VERSION 5.8 ;
BUSBITCHARS "[]" ;
DIVIDERCHAR "/" ;
UNITS
    DATABASE MICRONS 1000 ;
END UNITS

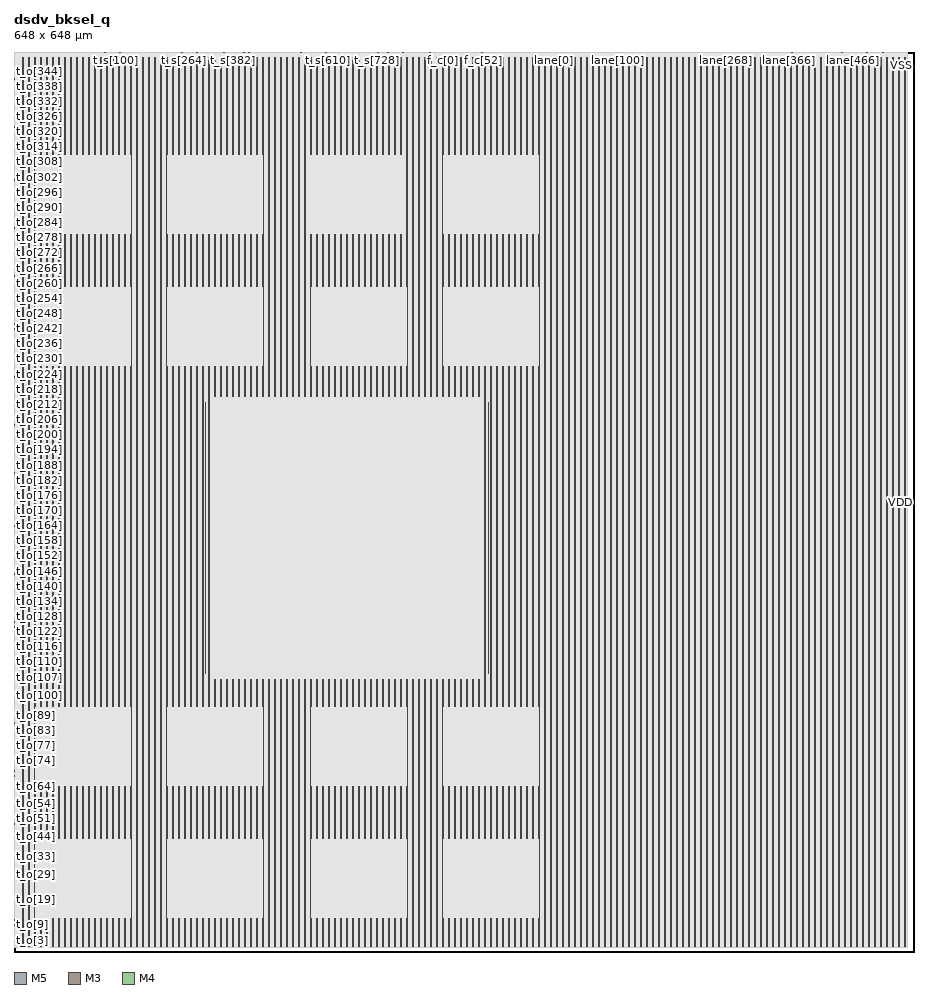
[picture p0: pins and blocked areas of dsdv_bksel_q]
MACRO dsdv_bksel_q
  FOREIGN dsdv_bksel_q 0 0 ;
  CLASS BLOCK ;
  SIZE 648 BY 648 ;
  PIN ck
    DIRECTION INPUT ;
    USE SIGNAL ;
    PORT
      LAYER M5 ;
        RECT  304.560 647.52 304.584 648 ;
    END
  END ck
  PIN f_c[0]
    DIRECTION INPUT ;
    USE SIGNAL ;
    PORT
      LAYER M3 ;
        RECT  309.132 647.962 309.15 648 ;
    END
  END f_c[0]
  PIN f_c[10]
    DIRECTION INPUT ;
    USE SIGNAL ;
    PORT
      LAYER M3 ;
        RECT  314.712 647.962 314.73 648 ;
    END
  END f_c[10]
  PIN f_c[11]
    DIRECTION INPUT ;
    USE SIGNAL ;
    PORT
      LAYER M5 ;
        RECT  315.264 647.916 315.288 648 ;
    END
  END f_c[11]
  PIN f_c[12]
    DIRECTION INPUT ;
    USE SIGNAL ;
    PORT
      LAYER M3 ;
        RECT  315.828 647.962 315.846 648 ;
    END
  END f_c[12]
  PIN f_c[13]
    DIRECTION INPUT ;
    USE SIGNAL ;
    PORT
      LAYER M5 ;
        RECT  316.368 647.916 316.392 648 ;
    END
  END f_c[13]
  PIN f_c[14]
    DIRECTION INPUT ;
    USE SIGNAL ;
    PORT
      LAYER M3 ;
        RECT  316.944 647.962 316.962 648 ;
    END
  END f_c[14]
  PIN f_c[15]
    DIRECTION INPUT ;
    USE SIGNAL ;
    PORT
      LAYER M5 ;
        RECT  317.472 647.916 317.496 648 ;
    END
  END f_c[15]
  PIN f_c[16]
    DIRECTION INPUT ;
    USE SIGNAL ;
    PORT
      LAYER M3 ;
        RECT  318.06 647.962 318.078 648 ;
    END
  END f_c[16]
  PIN f_c[17]
    DIRECTION INPUT ;
    USE SIGNAL ;
    PORT
      LAYER M5 ;
        RECT  318.624 647.916 318.648 648 ;
    END
  END f_c[17]
  PIN f_c[18]
    DIRECTION INPUT ;
    USE SIGNAL ;
    PORT
      LAYER M3 ;
        RECT  319.176 647.962 319.194 648 ;
    END
  END f_c[18]
  PIN f_c[19]
    DIRECTION INPUT ;
    USE SIGNAL ;
    PORT
      LAYER M5 ;
        RECT  319.728 647.916 319.752 648 ;
    END
  END f_c[19]
  PIN f_c[1]
    DIRECTION INPUT ;
    USE SIGNAL ;
    PORT
      LAYER M5 ;
        RECT  309.696 647.916 309.72 648 ;
    END
  END f_c[1]
  PIN f_c[20]
    DIRECTION INPUT ;
    USE SIGNAL ;
    PORT
      LAYER M3 ;
        RECT  320.292 647.962 320.31 648 ;
    END
  END f_c[20]
  PIN f_c[21]
    DIRECTION INPUT ;
    USE SIGNAL ;
    PORT
      LAYER M5 ;
        RECT  320.832 647.916 320.856 648 ;
    END
  END f_c[21]
  PIN f_c[22]
    DIRECTION INPUT ;
    USE SIGNAL ;
    PORT
      LAYER M3 ;
        RECT  321.372 647.962 321.39 648 ;
    END
  END f_c[22]
  PIN f_c[23]
    DIRECTION INPUT ;
    USE SIGNAL ;
    PORT
      LAYER M5 ;
        RECT  321.936 647.916 321.96 648 ;
    END
  END f_c[23]
  PIN f_c[24]
    DIRECTION INPUT ;
    USE SIGNAL ;
    PORT
      LAYER M3 ;
        RECT  322.488 647.962 322.506 648 ;
    END
  END f_c[24]
  PIN f_c[25]
    DIRECTION INPUT ;
    USE SIGNAL ;
    PORT
      LAYER M5 ;
        RECT  323.04 647.916 323.064 648 ;
    END
  END f_c[25]
  PIN f_c[26]
    DIRECTION INPUT ;
    USE SIGNAL ;
    PORT
      LAYER M3 ;
        RECT  323.604 647.962 323.622 648 ;
    END
  END f_c[26]
  PIN f_c[27]
    DIRECTION INPUT ;
    USE SIGNAL ;
    PORT
      LAYER M5 ;
        RECT  324.192 647.916 324.216 648 ;
    END
  END f_c[27]
  PIN f_c[28]
    DIRECTION INPUT ;
    USE SIGNAL ;
    PORT
      LAYER M3 ;
        RECT  324.72 647.962 324.738 648 ;
    END
  END f_c[28]
  PIN f_c[29]
    DIRECTION INPUT ;
    USE SIGNAL ;
    PORT
      LAYER M5 ;
        RECT  325.296 647.916 325.32 648 ;
    END
  END f_c[29]
  PIN f_c[2]
    DIRECTION INPUT ;
    USE SIGNAL ;
    PORT
      LAYER M3 ;
        RECT  310.248 647.962 310.266 648 ;
    END
  END f_c[2]
  PIN f_c[30]
    DIRECTION INPUT ;
    USE SIGNAL ;
    PORT
      LAYER M3 ;
        RECT  325.836 647.962 325.854 648 ;
    END
  END f_c[30]
  PIN f_c[31]
    DIRECTION INPUT ;
    USE SIGNAL ;
    PORT
      LAYER M5 ;
        RECT  326.4 647.916 326.424 648 ;
    END
  END f_c[31]
  PIN f_c[32]
    DIRECTION INPUT ;
    USE SIGNAL ;
    PORT
      LAYER M3 ;
        RECT  326.952 647.962 326.97 648 ;
    END
  END f_c[32]
  PIN f_c[33]
    DIRECTION INPUT ;
    USE SIGNAL ;
    PORT
      LAYER M5 ;
        RECT  327.504 647.916 327.528 648 ;
    END
  END f_c[33]
  PIN f_c[34]
    DIRECTION INPUT ;
    USE SIGNAL ;
    PORT
      LAYER M3 ;
        RECT  328.068 647.962 328.086 648 ;
    END
  END f_c[34]
  PIN f_c[35]
    DIRECTION INPUT ;
    USE SIGNAL ;
    PORT
      LAYER M5 ;
        RECT  328.608 647.916 328.632 648 ;
    END
  END f_c[35]
  PIN f_c[36]
    DIRECTION INPUT ;
    USE SIGNAL ;
    PORT
      LAYER M3 ;
        RECT  329.184 647.962 329.202 648 ;
    END
  END f_c[36]
  PIN f_c[37]
    DIRECTION INPUT ;
    USE SIGNAL ;
    PORT
      LAYER M5 ;
        RECT  329.712 647.916 329.736 648 ;
    END
  END f_c[37]
  PIN f_c[38]
    DIRECTION INPUT ;
    USE SIGNAL ;
    PORT
      LAYER M3 ;
        RECT  330.3 647.962 330.318 648 ;
    END
  END f_c[38]
  PIN f_c[39]
    DIRECTION INPUT ;
    USE SIGNAL ;
    PORT
      LAYER M5 ;
        RECT  330.864 647.916 330.888 648 ;
    END
  END f_c[39]
  PIN f_c[3]
    DIRECTION INPUT ;
    USE SIGNAL ;
    PORT
      LAYER M5 ;
        RECT  310.8 647.916 310.824 648 ;
    END
  END f_c[3]
  PIN f_c[40]
    DIRECTION INPUT ;
    USE SIGNAL ;
    PORT
      LAYER M3 ;
        RECT  331.416 647.962 331.434 648 ;
    END
  END f_c[40]
  PIN f_c[41]
    DIRECTION INPUT ;
    USE SIGNAL ;
    PORT
      LAYER M5 ;
        RECT  331.968 647.916 331.992 648 ;
    END
  END f_c[41]
  PIN f_c[42]
    DIRECTION INPUT ;
    USE SIGNAL ;
    PORT
      LAYER M3 ;
        RECT  332.532 647.962 332.55 648 ;
    END
  END f_c[42]
  PIN f_c[43]
    DIRECTION INPUT ;
    USE SIGNAL ;
    PORT
      LAYER M5 ;
        RECT  333.072 647.916 333.096 648 ;
    END
  END f_c[43]
  PIN f_c[44]
    DIRECTION INPUT ;
    USE SIGNAL ;
    PORT
      LAYER M3 ;
        RECT  333.612 647.962 333.63 648 ;
    END
  END f_c[44]
  PIN f_c[45]
    DIRECTION INPUT ;
    USE SIGNAL ;
    PORT
      LAYER M5 ;
        RECT  334.176 647.916 334.2 648 ;
    END
  END f_c[45]
  PIN f_c[46]
    DIRECTION INPUT ;
    USE SIGNAL ;
    PORT
      LAYER M3 ;
        RECT  334.728 647.962 334.746 648 ;
    END
  END f_c[46]
  PIN f_c[47]
    DIRECTION INPUT ;
    USE SIGNAL ;
    PORT
      LAYER M5 ;
        RECT  335.28 647.916 335.304 648 ;
    END
  END f_c[47]
  PIN f_c[48]
    DIRECTION INPUT ;
    USE SIGNAL ;
    PORT
      LAYER M3 ;
        RECT  335.844 647.962 335.862 648 ;
    END
  END f_c[48]
  PIN f_c[49]
    DIRECTION INPUT ;
    USE SIGNAL ;
    PORT
      LAYER M5 ;
        RECT  336.432 647.916 336.456 648 ;
    END
  END f_c[49]
  PIN f_c[4]
    DIRECTION INPUT ;
    USE SIGNAL ;
    PORT
      LAYER M3 ;
        RECT  311.364 647.962 311.382 648 ;
    END
  END f_c[4]
  PIN f_c[50]
    DIRECTION INPUT ;
    USE SIGNAL ;
    PORT
      LAYER M3 ;
        RECT  336.96 647.962 336.978 648 ;
    END
  END f_c[50]
  PIN f_c[51]
    DIRECTION INPUT ;
    USE SIGNAL ;
    PORT
      LAYER M5 ;
        RECT  337.536 647.916 337.56 648 ;
    END
  END f_c[51]
  PIN f_c[52]
    DIRECTION INPUT ;
    USE SIGNAL ;
    PORT
      LAYER M3 ;
        RECT  338.076 647.962 338.094 648 ;
    END
  END f_c[52]
  PIN f_c[53]
    DIRECTION INPUT ;
    USE SIGNAL ;
    PORT
      LAYER M5 ;
        RECT  338.64 647.916 338.664 648 ;
    END
  END f_c[53]
  PIN f_c[54]
    DIRECTION INPUT ;
    USE SIGNAL ;
    PORT
      LAYER M3 ;
        RECT  339.192 647.962 339.21 648 ;
    END
  END f_c[54]
  PIN f_c[55]
    DIRECTION INPUT ;
    USE SIGNAL ;
    PORT
      LAYER M5 ;
        RECT  339.744 647.916 339.768 648 ;
    END
  END f_c[55]
  PIN f_c[56]
    DIRECTION INPUT ;
    USE SIGNAL ;
    PORT
      LAYER M3 ;
        RECT  340.308 647.962 340.326 648 ;
    END
  END f_c[56]
  PIN f_c[57]
    DIRECTION INPUT ;
    USE SIGNAL ;
    PORT
      LAYER M5 ;
        RECT  340.848 647.916 340.872 648 ;
    END
  END f_c[57]
  PIN f_c[58]
    DIRECTION INPUT ;
    USE SIGNAL ;
    PORT
      LAYER M3 ;
        RECT  341.424 647.962 341.442 648 ;
    END
  END f_c[58]
  PIN f_c[59]
    DIRECTION INPUT ;
    USE SIGNAL ;
    PORT
      LAYER M5 ;
        RECT  341.952 647.916 341.976 648 ;
    END
  END f_c[59]
  PIN f_c[5]
    DIRECTION INPUT ;
    USE SIGNAL ;
    PORT
      LAYER M5 ;
        RECT  311.952 647.916 311.976 648 ;
    END
  END f_c[5]
  PIN f_c[60]
    DIRECTION INPUT ;
    USE SIGNAL ;
    PORT
      LAYER M3 ;
        RECT  342.54 647.962 342.558 648 ;
    END
  END f_c[60]
  PIN f_c[61]
    DIRECTION INPUT ;
    USE SIGNAL ;
    PORT
      LAYER M5 ;
        RECT  343.104 647.916 343.128 648 ;
    END
  END f_c[61]
  PIN f_c[62]
    DIRECTION INPUT ;
    USE SIGNAL ;
    PORT
      LAYER M3 ;
        RECT  343.656 647.962 343.674 648 ;
    END
  END f_c[62]
  PIN f_c[63]
    DIRECTION INPUT ;
    USE SIGNAL ;
    PORT
      LAYER M5 ;
        RECT  344.208 647.916 344.232 648 ;
    END
  END f_c[63]
  PIN f_c[64]
    DIRECTION INPUT ;
    USE SIGNAL ;
    PORT
      LAYER M3 ;
        RECT  344.772 647.962 344.79 648 ;
    END
  END f_c[64]
  PIN f_c[65]
    DIRECTION INPUT ;
    USE SIGNAL ;
    PORT
      LAYER M5 ;
        RECT  345.312 647.916 345.336 648 ;
    END
  END f_c[65]
  PIN f_c[6]
    DIRECTION INPUT ;
    USE SIGNAL ;
    PORT
      LAYER M3 ;
        RECT  312.48 647.962 312.498 648 ;
    END
  END f_c[6]
  PIN f_c[7]
    DIRECTION INPUT ;
    USE SIGNAL ;
    PORT
      LAYER M5 ;
        RECT  313.056 647.916 313.08 648 ;
    END
  END f_c[7]
  PIN f_c[8]
    DIRECTION INPUT ;
    USE SIGNAL ;
    PORT
      LAYER M3 ;
        RECT  313.596 647.962 313.614 648 ;
    END
  END f_c[8]
  PIN f_c[9]
    DIRECTION INPUT ;
    USE SIGNAL ;
    PORT
      LAYER M5 ;
        RECT  314.16 647.916 314.184 648 ;
    END
  END f_c[9]
  PIN f_cr
    DIRECTION INPUT ;
    USE SIGNAL ;
    PORT
      LAYER M3 ;
        RECT  346.68 647.962 346.698 648 ;
    END
  END f_cr
  PIN lane[0]
    DIRECTION INPUT ;
    USE SIGNAL ;
    PORT
      LAYER M3 ;
        RECT  389.016 647.962 389.034 648 ;
    END
  END lane[0]
  PIN lane[100]
    DIRECTION INPUT ;
    USE SIGNAL ;
    PORT
      LAYER M3 ;
        RECT  435.168 647.962 435.186 648 ;
    END
  END lane[100]
  PIN lane[101]
    DIRECTION INPUT ;
    USE SIGNAL ;
    PORT
      LAYER M5 ;
        RECT  435.6 647.916 435.624 648 ;
    END
  END lane[101]
  PIN lane[102]
    DIRECTION INPUT ;
    USE SIGNAL ;
    PORT
      LAYER M3 ;
        RECT  436.068 647.962 436.086 648 ;
    END
  END lane[102]
  PIN lane[103]
    DIRECTION INPUT ;
    USE SIGNAL ;
    PORT
      LAYER M5 ;
        RECT  436.56 647.916 436.584 648 ;
    END
  END lane[103]
  PIN lane[104]
    DIRECTION INPUT ;
    USE SIGNAL ;
    PORT
      LAYER M3 ;
        RECT  437.004 647.962 437.022 648 ;
    END
  END lane[104]
  PIN lane[105]
    DIRECTION INPUT ;
    USE SIGNAL ;
    PORT
      LAYER M5 ;
        RECT  437.472 647.916 437.496 648 ;
    END
  END lane[105]
  PIN lane[106]
    DIRECTION INPUT ;
    USE SIGNAL ;
    PORT
      LAYER M3 ;
        RECT  437.94 647.962 437.958 648 ;
    END
  END lane[106]
  PIN lane[107]
    DIRECTION INPUT ;
    USE SIGNAL ;
    PORT
      LAYER M5 ;
        RECT  438.384 647.916 438.408 648 ;
    END
  END lane[107]
  PIN lane[108]
    DIRECTION INPUT ;
    USE SIGNAL ;
    PORT
      LAYER M3 ;
        RECT  438.84 647.962 438.858 648 ;
    END
  END lane[108]
  PIN lane[109]
    DIRECTION INPUT ;
    USE SIGNAL ;
    PORT
      LAYER M5 ;
        RECT  439.296 647.916 439.32 648 ;
    END
  END lane[109]
  PIN lane[10]
    DIRECTION INPUT ;
    USE SIGNAL ;
    PORT
      LAYER M3 ;
        RECT  393.624 647.962 393.642 648 ;
    END
  END lane[10]
  PIN lane[110]
    DIRECTION INPUT ;
    USE SIGNAL ;
    PORT
      LAYER M3 ;
        RECT  439.776 647.962 439.794 648 ;
    END
  END lane[110]
  PIN lane[111]
    DIRECTION INPUT ;
    USE SIGNAL ;
    PORT
      LAYER M5 ;
        RECT  440.208 647.916 440.232 648 ;
    END
  END lane[111]
  PIN lane[112]
    DIRECTION INPUT ;
    USE SIGNAL ;
    PORT
      LAYER M3 ;
        RECT  440.712 647.962 440.73 648 ;
    END
  END lane[112]
  PIN lane[113]
    DIRECTION INPUT ;
    USE SIGNAL ;
    PORT
      LAYER M5 ;
        RECT  441.168 647.916 441.192 648 ;
    END
  END lane[113]
  PIN lane[114]
    DIRECTION INPUT ;
    USE SIGNAL ;
    PORT
      LAYER M3 ;
        RECT  441.612 647.962 441.63 648 ;
    END
  END lane[114]
  PIN lane[115]
    DIRECTION INPUT ;
    USE SIGNAL ;
    PORT
      LAYER M5 ;
        RECT  442.08 647.916 442.104 648 ;
    END
  END lane[115]
  PIN lane[116]
    DIRECTION INPUT ;
    USE SIGNAL ;
    PORT
      LAYER M3 ;
        RECT  442.548 647.962 442.566 648 ;
    END
  END lane[116]
  PIN lane[117]
    DIRECTION INPUT ;
    USE SIGNAL ;
    PORT
      LAYER M5 ;
        RECT  442.992 647.916 443.016 648 ;
    END
  END lane[117]
  PIN lane[118]
    DIRECTION INPUT ;
    USE SIGNAL ;
    PORT
      LAYER M3 ;
        RECT  443.448 647.962 443.466 648 ;
    END
  END lane[118]
  PIN lane[119]
    DIRECTION INPUT ;
    USE SIGNAL ;
    PORT
      LAYER M5 ;
        RECT  443.904 647.916 443.928 648 ;
    END
  END lane[119]
  PIN lane[11]
    DIRECTION INPUT ;
    USE SIGNAL ;
    PORT
      LAYER M5 ;
        RECT  394.08 647.916 394.104 648 ;
    END
  END lane[11]
  PIN lane[120]
    DIRECTION INPUT ;
    USE SIGNAL ;
    PORT
      LAYER M3 ;
        RECT  444.384 647.962 444.402 648 ;
    END
  END lane[120]
  PIN lane[121]
    DIRECTION INPUT ;
    USE SIGNAL ;
    PORT
      LAYER M5 ;
        RECT  444.864 647.916 444.888 648 ;
    END
  END lane[121]
  PIN lane[122]
    DIRECTION INPUT ;
    USE SIGNAL ;
    PORT
      LAYER M3 ;
        RECT  445.356 647.962 445.374 648 ;
    END
  END lane[122]
  PIN lane[123]
    DIRECTION INPUT ;
    USE SIGNAL ;
    PORT
      LAYER M5 ;
        RECT  445.776 647.916 445.8 648 ;
    END
  END lane[123]
  PIN lane[124]
    DIRECTION INPUT ;
    USE SIGNAL ;
    PORT
      LAYER M3 ;
        RECT  446.22 647.962 446.238 648 ;
    END
  END lane[124]
  PIN lane[125]
    DIRECTION INPUT ;
    USE SIGNAL ;
    PORT
      LAYER M5 ;
        RECT  446.688 647.916 446.712 648 ;
    END
  END lane[125]
  PIN lane[126]
    DIRECTION INPUT ;
    USE SIGNAL ;
    PORT
      LAYER M3 ;
        RECT  447.156 647.962 447.174 648 ;
    END
  END lane[126]
  PIN lane[127]
    DIRECTION INPUT ;
    USE SIGNAL ;
    PORT
      LAYER M5 ;
        RECT  447.6 647.916 447.624 648 ;
    END
  END lane[127]
  PIN lane[128]
    DIRECTION INPUT ;
    USE SIGNAL ;
    PORT
      LAYER M3 ;
        RECT  448.092 647.962 448.11 648 ;
    END
  END lane[128]
  PIN lane[129]
    DIRECTION INPUT ;
    USE SIGNAL ;
    PORT
      LAYER M5 ;
        RECT  448.512 647.916 448.536 648 ;
    END
  END lane[129]
  PIN lane[12]
    DIRECTION INPUT ;
    USE SIGNAL ;
    PORT
      LAYER M3 ;
        RECT  394.56 647.962 394.578 648 ;
    END
  END lane[12]
  PIN lane[130]
    DIRECTION INPUT ;
    USE SIGNAL ;
    PORT
      LAYER M3 ;
        RECT  448.992 647.962 449.01 648 ;
    END
  END lane[130]
  PIN lane[131]
    DIRECTION INPUT ;
    USE SIGNAL ;
    PORT
      LAYER M5 ;
        RECT  449.472 647.916 449.496 648 ;
    END
  END lane[131]
  PIN lane[132]
    DIRECTION INPUT ;
    USE SIGNAL ;
    PORT
      LAYER M3 ;
        RECT  449.928 647.962 449.946 648 ;
    END
  END lane[132]
  PIN lane[133]
    DIRECTION INPUT ;
    USE SIGNAL ;
    PORT
      LAYER M5 ;
        RECT  450.384 647.916 450.408 648 ;
    END
  END lane[133]
  PIN lane[134]
    DIRECTION INPUT ;
    USE SIGNAL ;
    PORT
      LAYER M3 ;
        RECT  450.828 647.962 450.846 648 ;
    END
  END lane[134]
  PIN lane[135]
    DIRECTION INPUT ;
    USE SIGNAL ;
    PORT
      LAYER M5 ;
        RECT  451.296 647.916 451.32 648 ;
    END
  END lane[135]
  PIN lane[136]
    DIRECTION INPUT ;
    USE SIGNAL ;
    PORT
      LAYER M3 ;
        RECT  451.764 647.962 451.782 648 ;
    END
  END lane[136]
  PIN lane[137]
    DIRECTION INPUT ;
    USE SIGNAL ;
    PORT
      LAYER M5 ;
        RECT  452.208 647.916 452.232 648 ;
    END
  END lane[137]
  PIN lane[138]
    DIRECTION INPUT ;
    USE SIGNAL ;
    PORT
      LAYER M3 ;
        RECT  452.7 647.962 452.718 648 ;
    END
  END lane[138]
  PIN lane[139]
    DIRECTION INPUT ;
    USE SIGNAL ;
    PORT
      LAYER M5 ;
        RECT  453.168 647.916 453.192 648 ;
    END
  END lane[139]
  PIN lane[13]
    DIRECTION INPUT ;
    USE SIGNAL ;
    PORT
      LAYER M5 ;
        RECT  395.04 647.916 395.064 648 ;
    END
  END lane[13]
  PIN lane[140]
    DIRECTION INPUT ;
    USE SIGNAL ;
    PORT
      LAYER M3 ;
        RECT  453.6 647.962 453.618 648 ;
    END
  END lane[140]
  PIN lane[141]
    DIRECTION INPUT ;
    USE SIGNAL ;
    PORT
      LAYER M5 ;
        RECT  454.08 647.916 454.104 648 ;
    END
  END lane[141]
  PIN lane[142]
    DIRECTION INPUT ;
    USE SIGNAL ;
    PORT
      LAYER M3 ;
        RECT  454.536 647.962 454.554 648 ;
    END
  END lane[142]
  PIN lane[143]
    DIRECTION INPUT ;
    USE SIGNAL ;
    PORT
      LAYER M5 ;
        RECT  454.992 647.916 455.016 648 ;
    END
  END lane[143]
  PIN lane[144]
    DIRECTION INPUT ;
    USE SIGNAL ;
    PORT
      LAYER M3 ;
        RECT  455.472 647.962 455.49 648 ;
    END
  END lane[144]
  PIN lane[145]
    DIRECTION INPUT ;
    USE SIGNAL ;
    PORT
      LAYER M5 ;
        RECT  455.904 647.916 455.928 648 ;
    END
  END lane[145]
  PIN lane[146]
    DIRECTION INPUT ;
    USE SIGNAL ;
    PORT
      LAYER M3 ;
        RECT  456.372 647.962 456.39 648 ;
    END
  END lane[146]
  PIN lane[147]
    DIRECTION INPUT ;
    USE SIGNAL ;
    PORT
      LAYER M5 ;
        RECT  456.816 647.916 456.84 648 ;
    END
  END lane[147]
  PIN lane[148]
    DIRECTION INPUT ;
    USE SIGNAL ;
    PORT
      LAYER M3 ;
        RECT  457.308 647.962 457.326 648 ;
    END
  END lane[148]
  PIN lane[149]
    DIRECTION INPUT ;
    USE SIGNAL ;
    PORT
      LAYER M5 ;
        RECT  457.776 647.916 457.8 648 ;
    END
  END lane[149]
  PIN lane[14]
    DIRECTION INPUT ;
    USE SIGNAL ;
    PORT
      LAYER M3 ;
        RECT  395.496 647.962 395.514 648 ;
    END
  END lane[14]
  PIN lane[150]
    DIRECTION INPUT ;
    USE SIGNAL ;
    PORT
      LAYER M3 ;
        RECT  458.244 647.962 458.262 648 ;
    END
  END lane[150]
  PIN lane[151]
    DIRECTION INPUT ;
    USE SIGNAL ;
    PORT
      LAYER M5 ;
        RECT  458.688 647.916 458.712 648 ;
    END
  END lane[151]
  PIN lane[152]
    DIRECTION INPUT ;
    USE SIGNAL ;
    PORT
      LAYER M3 ;
        RECT  459.144 647.962 459.162 648 ;
    END
  END lane[152]
  PIN lane[153]
    DIRECTION INPUT ;
    USE SIGNAL ;
    PORT
      LAYER M5 ;
        RECT  459.6 647.916 459.624 648 ;
    END
  END lane[153]
  PIN lane[154]
    DIRECTION INPUT ;
    USE SIGNAL ;
    PORT
      LAYER M3 ;
        RECT  460.08 647.962 460.098 648 ;
    END
  END lane[154]
  PIN lane[155]
    DIRECTION INPUT ;
    USE SIGNAL ;
    PORT
      LAYER M5 ;
        RECT  460.512 647.916 460.536 648 ;
    END
  END lane[155]
  PIN lane[156]
    DIRECTION INPUT ;
    USE SIGNAL ;
    PORT
      LAYER M3 ;
        RECT  460.98 647.962 460.998 648 ;
    END
  END lane[156]
  PIN lane[157]
    DIRECTION INPUT ;
    USE SIGNAL ;
    PORT
      LAYER M5 ;
        RECT  461.472 647.916 461.496 648 ;
    END
  END lane[157]
  PIN lane[158]
    DIRECTION INPUT ;
    USE SIGNAL ;
    PORT
      LAYER M3 ;
        RECT  461.916 647.962 461.934 648 ;
    END
  END lane[158]
  PIN lane[159]
    DIRECTION INPUT ;
    USE SIGNAL ;
    PORT
      LAYER M5 ;
        RECT  462.384 647.916 462.408 648 ;
    END
  END lane[159]
  PIN lane[15]
    DIRECTION INPUT ;
    USE SIGNAL ;
    PORT
      LAYER M5 ;
        RECT  395.952 647.916 395.976 648 ;
    END
  END lane[15]
  PIN lane[160]
    DIRECTION INPUT ;
    USE SIGNAL ;
    PORT
      LAYER M3 ;
        RECT  462.852 647.962 462.87 648 ;
    END
  END lane[160]
  PIN lane[161]
    DIRECTION INPUT ;
    USE SIGNAL ;
    PORT
      LAYER M5 ;
        RECT  463.296 647.916 463.32 648 ;
    END
  END lane[161]
  PIN lane[162]
    DIRECTION INPUT ;
    USE SIGNAL ;
    PORT
      LAYER M3 ;
        RECT  463.752 647.962 463.77 648 ;
    END
  END lane[162]
  PIN lane[163]
    DIRECTION INPUT ;
    USE SIGNAL ;
    PORT
      LAYER M5 ;
        RECT  464.208 647.916 464.232 648 ;
    END
  END lane[163]
  PIN lane[164]
    DIRECTION INPUT ;
    USE SIGNAL ;
    PORT
      LAYER M3 ;
        RECT  464.688 647.962 464.706 648 ;
    END
  END lane[164]
  PIN lane[165]
    DIRECTION INPUT ;
    USE SIGNAL ;
    PORT
      LAYER M5 ;
        RECT  465.12 647.916 465.144 648 ;
    END
  END lane[165]
  PIN lane[166]
    DIRECTION INPUT ;
    USE SIGNAL ;
    PORT
      LAYER M3 ;
        RECT  465.624 647.962 465.642 648 ;
    END
  END lane[166]
  PIN lane[167]
    DIRECTION INPUT ;
    USE SIGNAL ;
    PORT
      LAYER M5 ;
        RECT  466.08 647.916 466.104 648 ;
    END
  END lane[167]
  PIN lane[168]
    DIRECTION INPUT ;
    USE SIGNAL ;
    PORT
      LAYER M3 ;
        RECT  466.524 647.962 466.542 648 ;
    END
  END lane[168]
  PIN lane[169]
    DIRECTION INPUT ;
    USE SIGNAL ;
    PORT
      LAYER M5 ;
        RECT  466.992 647.916 467.016 648 ;
    END
  END lane[169]
  PIN lane[16]
    DIRECTION INPUT ;
    USE SIGNAL ;
    PORT
      LAYER M3 ;
        RECT  396.396 647.962 396.414 648 ;
    END
  END lane[16]
  PIN lane[170]
    DIRECTION INPUT ;
    USE SIGNAL ;
    PORT
      LAYER M3 ;
        RECT  467.46 647.962 467.478 648 ;
    END
  END lane[170]
  PIN lane[171]
    DIRECTION INPUT ;
    USE SIGNAL ;
    PORT
      LAYER M5 ;
        RECT  467.904 647.916 467.928 648 ;
    END
  END lane[171]
  PIN lane[172]
    DIRECTION INPUT ;
    USE SIGNAL ;
    PORT
      LAYER M3 ;
        RECT  468.36 647.962 468.378 648 ;
    END
  END lane[172]
  PIN lane[173]
    DIRECTION INPUT ;
    USE SIGNAL ;
    PORT
      LAYER M5 ;
        RECT  468.816 647.916 468.84 648 ;
    END
  END lane[173]
  PIN lane[174]
    DIRECTION INPUT ;
    USE SIGNAL ;
    PORT
      LAYER M3 ;
        RECT  469.296 647.962 469.314 648 ;
    END
  END lane[174]
  PIN lane[175]
    DIRECTION INPUT ;
    USE SIGNAL ;
    PORT
      LAYER M5 ;
        RECT  469.776 647.916 469.8 648 ;
    END
  END lane[175]
  PIN lane[176]
    DIRECTION INPUT ;
    USE SIGNAL ;
    PORT
      LAYER M3 ;
        RECT  470.232 647.962 470.25 648 ;
    END
  END lane[176]
  PIN lane[177]
    DIRECTION INPUT ;
    USE SIGNAL ;
    PORT
      LAYER M5 ;
        RECT  470.688 647.916 470.712 648 ;
    END
  END lane[177]
  PIN lane[178]
    DIRECTION INPUT ;
    USE SIGNAL ;
    PORT
      LAYER M3 ;
        RECT  471.132 647.962 471.15 648 ;
    END
  END lane[178]
  PIN lane[179]
    DIRECTION INPUT ;
    USE SIGNAL ;
    PORT
      LAYER M5 ;
        RECT  471.6 647.916 471.624 648 ;
    END
  END lane[179]
  PIN lane[17]
    DIRECTION INPUT ;
    USE SIGNAL ;
    PORT
      LAYER M5 ;
        RECT  396.864 647.916 396.888 648 ;
    END
  END lane[17]
  PIN lane[180]
    DIRECTION INPUT ;
    USE SIGNAL ;
    PORT
      LAYER M3 ;
        RECT  472.068 647.962 472.086 648 ;
    END
  END lane[180]
  PIN lane[181]
    DIRECTION INPUT ;
    USE SIGNAL ;
    PORT
      LAYER M5 ;
        RECT  472.512 647.916 472.536 648 ;
    END
  END lane[181]
  PIN lane[182]
    DIRECTION INPUT ;
    USE SIGNAL ;
    PORT
      LAYER M3 ;
        RECT  473.004 647.962 473.022 648 ;
    END
  END lane[182]
  PIN lane[183]
    DIRECTION INPUT ;
    USE SIGNAL ;
    PORT
      LAYER M5 ;
        RECT  473.424 647.916 473.448 648 ;
    END
  END lane[183]
  PIN lane[184]
    DIRECTION INPUT ;
    USE SIGNAL ;
    PORT
      LAYER M3 ;
        RECT  473.904 647.962 473.922 648 ;
    END
  END lane[184]
  PIN lane[185]
    DIRECTION INPUT ;
    USE SIGNAL ;
    PORT
      LAYER M5 ;
        RECT  474.384 647.916 474.408 648 ;
    END
  END lane[185]
  PIN lane[186]
    DIRECTION INPUT ;
    USE SIGNAL ;
    PORT
      LAYER M3 ;
        RECT  474.84 647.962 474.858 648 ;
    END
  END lane[186]
  PIN lane[187]
    DIRECTION INPUT ;
    USE SIGNAL ;
    PORT
      LAYER M5 ;
        RECT  475.296 647.916 475.32 648 ;
    END
  END lane[187]
  PIN lane[188]
    DIRECTION INPUT ;
    USE SIGNAL ;
    PORT
      LAYER M3 ;
        RECT  475.74 647.962 475.758 648 ;
    END
  END lane[188]
  PIN lane[189]
    DIRECTION INPUT ;
    USE SIGNAL ;
    PORT
      LAYER M5 ;
        RECT  476.208 647.916 476.232 648 ;
    END
  END lane[189]
  PIN lane[18]
    DIRECTION INPUT ;
    USE SIGNAL ;
    PORT
      LAYER M3 ;
        RECT  397.332 647.962 397.35 648 ;
    END
  END lane[18]
  PIN lane[190]
    DIRECTION INPUT ;
    USE SIGNAL ;
    PORT
      LAYER M3 ;
        RECT  476.676 647.962 476.694 648 ;
    END
  END lane[190]
  PIN lane[191]
    DIRECTION INPUT ;
    USE SIGNAL ;
    PORT
      LAYER M5 ;
        RECT  477.12 647.916 477.144 648 ;
    END
  END lane[191]
  PIN lane[192]
    DIRECTION INPUT ;
    USE SIGNAL ;
    PORT
      LAYER M3 ;
        RECT  477.576 647.962 477.594 648 ;
    END
  END lane[192]
  PIN lane[193]
    DIRECTION INPUT ;
    USE SIGNAL ;
    PORT
      LAYER M5 ;
        RECT  478.08 647.916 478.104 648 ;
    END
  END lane[193]
  PIN lane[194]
    DIRECTION INPUT ;
    USE SIGNAL ;
    PORT
      LAYER M3 ;
        RECT  478.512 647.962 478.53 648 ;
    END
  END lane[194]
  PIN lane[195]
    DIRECTION INPUT ;
    USE SIGNAL ;
    PORT
      LAYER M5 ;
        RECT  478.992 647.916 479.016 648 ;
    END
  END lane[195]
  PIN lane[196]
    DIRECTION INPUT ;
    USE SIGNAL ;
    PORT
      LAYER M3 ;
        RECT  479.448 647.962 479.466 648 ;
    END
  END lane[196]
  PIN lane[197]
    DIRECTION INPUT ;
    USE SIGNAL ;
    PORT
      LAYER M5 ;
        RECT  479.904 647.916 479.928 648 ;
    END
  END lane[197]
  PIN lane[198]
    DIRECTION INPUT ;
    USE SIGNAL ;
    PORT
      LAYER M3 ;
        RECT  480.384 647.962 480.402 648 ;
    END
  END lane[198]
  PIN lane[199]
    DIRECTION INPUT ;
    USE SIGNAL ;
    PORT
      LAYER M5 ;
        RECT  480.816 647.916 480.84 648 ;
    END
  END lane[199]
  PIN lane[19]
    DIRECTION INPUT ;
    USE SIGNAL ;
    PORT
      LAYER M5 ;
        RECT  397.776 647.916 397.8 648 ;
    END
  END lane[19]
  PIN lane[1]
    DIRECTION INPUT ;
    USE SIGNAL ;
    PORT
      LAYER M5 ;
        RECT  389.472 647.916 389.496 648 ;
    END
  END lane[1]
  PIN lane[200]
    DIRECTION INPUT ;
    USE SIGNAL ;
    PORT
      LAYER M3 ;
        RECT  481.284 647.962 481.302 648 ;
    END
  END lane[200]
  PIN lane[201]
    DIRECTION INPUT ;
    USE SIGNAL ;
    PORT
      LAYER M5 ;
        RECT  481.776 647.916 481.8 648 ;
    END
  END lane[201]
  PIN lane[202]
    DIRECTION INPUT ;
    USE SIGNAL ;
    PORT
      LAYER M3 ;
        RECT  482.22 647.962 482.238 648 ;
    END
  END lane[202]
  PIN lane[203]
    DIRECTION INPUT ;
    USE SIGNAL ;
    PORT
      LAYER M5 ;
        RECT  482.688 647.916 482.712 648 ;
    END
  END lane[203]
  PIN lane[204]
    DIRECTION INPUT ;
    USE SIGNAL ;
    PORT
      LAYER M3 ;
        RECT  483.156 647.962 483.174 648 ;
    END
  END lane[204]
  PIN lane[205]
    DIRECTION INPUT ;
    USE SIGNAL ;
    PORT
      LAYER M5 ;
        RECT  483.6 647.916 483.624 648 ;
    END
  END lane[205]
  PIN lane[206]
    DIRECTION INPUT ;
    USE SIGNAL ;
    PORT
      LAYER M3 ;
        RECT  484.056 647.962 484.074 648 ;
    END
  END lane[206]
  PIN lane[207]
    DIRECTION INPUT ;
    USE SIGNAL ;
    PORT
      LAYER M5 ;
        RECT  484.512 647.916 484.536 648 ;
    END
  END lane[207]
  PIN lane[208]
    DIRECTION INPUT ;
    USE SIGNAL ;
    PORT
      LAYER M3 ;
        RECT  484.992 647.962 485.01 648 ;
    END
  END lane[208]
  PIN lane[209]
    DIRECTION INPUT ;
    USE SIGNAL ;
    PORT
      LAYER M5 ;
        RECT  485.424 647.916 485.448 648 ;
    END
  END lane[209]
  PIN lane[20]
    DIRECTION INPUT ;
    USE SIGNAL ;
    PORT
      LAYER M3 ;
        RECT  398.232 647.962 398.25 648 ;
    END
  END lane[20]
  PIN lane[210]
    DIRECTION INPUT ;
    USE SIGNAL ;
    PORT
      LAYER M3 ;
        RECT  485.892 647.962 485.91 648 ;
    END
  END lane[210]
  PIN lane[211]
    DIRECTION INPUT ;
    USE SIGNAL ;
    PORT
      LAYER M5 ;
        RECT  486.384 647.916 486.408 648 ;
    END
  END lane[211]
  PIN lane[212]
    DIRECTION INPUT ;
    USE SIGNAL ;
    PORT
      LAYER M3 ;
        RECT  486.828 647.962 486.846 648 ;
    END
  END lane[212]
  PIN lane[213]
    DIRECTION INPUT ;
    USE SIGNAL ;
    PORT
      LAYER M5 ;
        RECT  487.296 647.916 487.32 648 ;
    END
  END lane[213]
  PIN lane[214]
    DIRECTION INPUT ;
    USE SIGNAL ;
    PORT
      LAYER M3 ;
        RECT  487.764 647.962 487.782 648 ;
    END
  END lane[214]
  PIN lane[215]
    DIRECTION INPUT ;
    USE SIGNAL ;
    PORT
      LAYER M5 ;
        RECT  488.208 647.916 488.232 648 ;
    END
  END lane[215]
  PIN lane[216]
    DIRECTION INPUT ;
    USE SIGNAL ;
    PORT
      LAYER M3 ;
        RECT  488.664 647.962 488.682 648 ;
    END
  END lane[216]
  PIN lane[217]
    DIRECTION INPUT ;
    USE SIGNAL ;
    PORT
      LAYER M5 ;
        RECT  489.12 647.916 489.144 648 ;
    END
  END lane[217]
  PIN lane[218]
    DIRECTION INPUT ;
    USE SIGNAL ;
    PORT
      LAYER M3 ;
        RECT  489.6 647.962 489.618 648 ;
    END
  END lane[218]
  PIN lane[219]
    DIRECTION INPUT ;
    USE SIGNAL ;
    PORT
      LAYER M5 ;
        RECT  490.08 647.916 490.104 648 ;
    END
  END lane[219]
  PIN lane[21]
    DIRECTION INPUT ;
    USE SIGNAL ;
    PORT
      LAYER M5 ;
        RECT  398.688 647.916 398.712 648 ;
    END
  END lane[21]
  PIN lane[220]
    DIRECTION INPUT ;
    USE SIGNAL ;
    PORT
      LAYER M3 ;
        RECT  490.536 647.962 490.554 648 ;
    END
  END lane[220]
  PIN lane[221]
    DIRECTION INPUT ;
    USE SIGNAL ;
    PORT
      LAYER M5 ;
        RECT  490.992 647.916 491.016 648 ;
    END
  END lane[221]
  PIN lane[222]
    DIRECTION INPUT ;
    USE SIGNAL ;
    PORT
      LAYER M3 ;
        RECT  491.436 647.962 491.454 648 ;
    END
  END lane[222]
  PIN lane[223]
    DIRECTION INPUT ;
    USE SIGNAL ;
    PORT
      LAYER M5 ;
        RECT  491.904 647.916 491.928 648 ;
    END
  END lane[223]
  PIN lane[224]
    DIRECTION INPUT ;
    USE SIGNAL ;
    PORT
      LAYER M3 ;
        RECT  492.372 647.962 492.39 648 ;
    END
  END lane[224]
  PIN lane[225]
    DIRECTION INPUT ;
    USE SIGNAL ;
    PORT
      LAYER M5 ;
        RECT  492.816 647.916 492.84 648 ;
    END
  END lane[225]
  PIN lane[226]
    DIRECTION INPUT ;
    USE SIGNAL ;
    PORT
      LAYER M3 ;
        RECT  493.272 647.962 493.29 648 ;
    END
  END lane[226]
  PIN lane[227]
    DIRECTION INPUT ;
    USE SIGNAL ;
    PORT
      LAYER M5 ;
        RECT  493.728 647.916 493.752 648 ;
    END
  END lane[227]
  PIN lane[228]
    DIRECTION INPUT ;
    USE SIGNAL ;
    PORT
      LAYER M3 ;
        RECT  494.208 647.962 494.226 648 ;
    END
  END lane[228]
  PIN lane[229]
    DIRECTION INPUT ;
    USE SIGNAL ;
    PORT
      LAYER M5 ;
        RECT  494.688 647.916 494.712 648 ;
    END
  END lane[229]
  PIN lane[22]
    DIRECTION INPUT ;
    USE SIGNAL ;
    PORT
      LAYER M3 ;
        RECT  399.168 647.962 399.186 648 ;
    END
  END lane[22]
  PIN lane[230]
    DIRECTION INPUT ;
    USE SIGNAL ;
    PORT
      LAYER M3 ;
        RECT  495.144 647.962 495.162 648 ;
    END
  END lane[230]
  PIN lane[231]
    DIRECTION INPUT ;
    USE SIGNAL ;
    PORT
      LAYER M5 ;
        RECT  495.6 647.916 495.624 648 ;
    END
  END lane[231]
  PIN lane[232]
    DIRECTION INPUT ;
    USE SIGNAL ;
    PORT
      LAYER M3 ;
        RECT  496.044 647.962 496.062 648 ;
    END
  END lane[232]
  PIN lane[233]
    DIRECTION INPUT ;
    USE SIGNAL ;
    PORT
      LAYER M5 ;
        RECT  496.512 647.916 496.536 648 ;
    END
  END lane[233]
  PIN lane[234]
    DIRECTION INPUT ;
    USE SIGNAL ;
    PORT
      LAYER M3 ;
        RECT  496.98 647.962 496.998 648 ;
    END
  END lane[234]
  PIN lane[235]
    DIRECTION INPUT ;
    USE SIGNAL ;
    PORT
      LAYER M5 ;
        RECT  497.424 647.916 497.448 648 ;
    END
  END lane[235]
  PIN lane[236]
    DIRECTION INPUT ;
    USE SIGNAL ;
    PORT
      LAYER M3 ;
        RECT  497.916 647.962 497.934 648 ;
    END
  END lane[236]
  PIN lane[237]
    DIRECTION INPUT ;
    USE SIGNAL ;
    PORT
      LAYER M5 ;
        RECT  498.384 647.916 498.408 648 ;
    END
  END lane[237]
  PIN lane[238]
    DIRECTION INPUT ;
    USE SIGNAL ;
    PORT
      LAYER M3 ;
        RECT  498.816 647.962 498.834 648 ;
    END
  END lane[238]
  PIN lane[239]
    DIRECTION INPUT ;
    USE SIGNAL ;
    PORT
      LAYER M5 ;
        RECT  499.296 647.916 499.32 648 ;
    END
  END lane[239]
  PIN lane[23]
    DIRECTION INPUT ;
    USE SIGNAL ;
    PORT
      LAYER M5 ;
        RECT  399.648 647.916 399.672 648 ;
    END
  END lane[23]
  PIN lane[240]
    DIRECTION INPUT ;
    USE SIGNAL ;
    PORT
      LAYER M3 ;
        RECT  499.752 647.962 499.77 648 ;
    END
  END lane[240]
  PIN lane[241]
    DIRECTION INPUT ;
    USE SIGNAL ;
    PORT
      LAYER M5 ;
        RECT  500.208 647.916 500.232 648 ;
    END
  END lane[241]
  PIN lane[242]
    DIRECTION INPUT ;
    USE SIGNAL ;
    PORT
      LAYER M3 ;
        RECT  500.688 647.962 500.706 648 ;
    END
  END lane[242]
  PIN lane[243]
    DIRECTION INPUT ;
    USE SIGNAL ;
    PORT
      LAYER M5 ;
        RECT  501.12 647.916 501.144 648 ;
    END
  END lane[243]
  PIN lane[244]
    DIRECTION INPUT ;
    USE SIGNAL ;
    PORT
      LAYER M3 ;
        RECT  501.588 647.962 501.606 648 ;
    END
  END lane[244]
  PIN lane[245]
    DIRECTION INPUT ;
    USE SIGNAL ;
    PORT
      LAYER M5 ;
        RECT  502.032 647.916 502.056 648 ;
    END
  END lane[245]
  PIN lane[246]
    DIRECTION INPUT ;
    USE SIGNAL ;
    PORT
      LAYER M3 ;
        RECT  502.524 647.962 502.542 648 ;
    END
  END lane[246]
  PIN lane[247]
    DIRECTION INPUT ;
    USE SIGNAL ;
    PORT
      LAYER M5 ;
        RECT  502.992 647.916 503.016 648 ;
    END
  END lane[247]
  PIN lane[248]
    DIRECTION INPUT ;
    USE SIGNAL ;
    PORT
      LAYER M3 ;
        RECT  503.424 647.962 503.442 648 ;
    END
  END lane[248]
  PIN lane[249]
    DIRECTION INPUT ;
    USE SIGNAL ;
    PORT
      LAYER M5 ;
        RECT  503.904 647.916 503.928 648 ;
    END
  END lane[249]
  PIN lane[24]
    DIRECTION INPUT ;
    USE SIGNAL ;
    PORT
      LAYER M3 ;
        RECT  400.104 647.962 400.122 648 ;
    END
  END lane[24]
  PIN lane[250]
    DIRECTION INPUT ;
    USE SIGNAL ;
    PORT
      LAYER M3 ;
        RECT  504.36 647.962 504.378 648 ;
    END
  END lane[250]
  PIN lane[251]
    DIRECTION INPUT ;
    USE SIGNAL ;
    PORT
      LAYER M5 ;
        RECT  504.816 647.916 504.84 648 ;
    END
  END lane[251]
  PIN lane[252]
    DIRECTION INPUT ;
    USE SIGNAL ;
    PORT
      LAYER M3 ;
        RECT  505.296 647.962 505.314 648 ;
    END
  END lane[252]
  PIN lane[253]
    DIRECTION INPUT ;
    USE SIGNAL ;
    PORT
      LAYER M5 ;
        RECT  505.728 647.916 505.752 648 ;
    END
  END lane[253]
  PIN lane[254]
    DIRECTION INPUT ;
    USE SIGNAL ;
    PORT
      LAYER M3 ;
        RECT  506.196 647.962 506.214 648 ;
    END
  END lane[254]
  PIN lane[255]
    DIRECTION INPUT ;
    USE SIGNAL ;
    PORT
      LAYER M5 ;
        RECT  506.688 647.916 506.712 648 ;
    END
  END lane[255]
  PIN lane[256]
    DIRECTION INPUT ;
    USE SIGNAL ;
    PORT
      LAYER M3 ;
        RECT  507.132 647.962 507.15 648 ;
    END
  END lane[256]
  PIN lane[257]
    DIRECTION INPUT ;
    USE SIGNAL ;
    PORT
      LAYER M5 ;
        RECT  507.6 647.916 507.624 648 ;
    END
  END lane[257]
  PIN lane[258]
    DIRECTION INPUT ;
    USE SIGNAL ;
    PORT
      LAYER M3 ;
        RECT  508.068 647.962 508.086 648 ;
    END
  END lane[258]
  PIN lane[259]
    DIRECTION INPUT ;
    USE SIGNAL ;
    PORT
      LAYER M5 ;
        RECT  508.512 647.916 508.536 648 ;
    END
  END lane[259]
  PIN lane[25]
    DIRECTION INPUT ;
    USE SIGNAL ;
    PORT
      LAYER M5 ;
        RECT  400.56 647.916 400.584 648 ;
    END
  END lane[25]
  PIN lane[260]
    DIRECTION INPUT ;
    USE SIGNAL ;
    PORT
      LAYER M3 ;
        RECT  508.968 647.962 508.986 648 ;
    END
  END lane[260]
  PIN lane[261]
    DIRECTION INPUT ;
    USE SIGNAL ;
    PORT
      LAYER M5 ;
        RECT  509.424 647.916 509.448 648 ;
    END
  END lane[261]
  PIN lane[262]
    DIRECTION INPUT ;
    USE SIGNAL ;
    PORT
      LAYER M3 ;
        RECT  509.904 647.962 509.922 648 ;
    END
  END lane[262]
  PIN lane[263]
    DIRECTION INPUT ;
    USE SIGNAL ;
    PORT
      LAYER M5 ;
        RECT  510.336 647.916 510.36 648 ;
    END
  END lane[263]
  PIN lane[264]
    DIRECTION INPUT ;
    USE SIGNAL ;
    PORT
      LAYER M3 ;
        RECT  510.804 647.962 510.822 648 ;
    END
  END lane[264]
  PIN lane[265]
    DIRECTION INPUT ;
    USE SIGNAL ;
    PORT
      LAYER M5 ;
        RECT  511.296 647.916 511.32 648 ;
    END
  END lane[265]
  PIN lane[266]
    DIRECTION INPUT ;
    USE SIGNAL ;
    PORT
      LAYER M3 ;
        RECT  511.74 647.962 511.758 648 ;
    END
  END lane[266]
  PIN lane[267]
    DIRECTION INPUT ;
    USE SIGNAL ;
    PORT
      LAYER M5 ;
        RECT  512.208 647.916 512.232 648 ;
    END
  END lane[267]
  PIN lane[268]
    DIRECTION INPUT ;
    USE SIGNAL ;
    PORT
      LAYER M3 ;
        RECT  512.676 647.962 512.694 648 ;
    END
  END lane[268]
  PIN lane[269]
    DIRECTION INPUT ;
    USE SIGNAL ;
    PORT
      LAYER M5 ;
        RECT  513.12 647.916 513.144 648 ;
    END
  END lane[269]
  PIN lane[26]
    DIRECTION INPUT ;
    USE SIGNAL ;
    PORT
      LAYER M3 ;
        RECT  401.004 647.962 401.022 648 ;
    END
  END lane[26]
  PIN lane[270]
    DIRECTION INPUT ;
    USE SIGNAL ;
    PORT
      LAYER M3 ;
        RECT  513.576 647.962 513.594 648 ;
    END
  END lane[270]
  PIN lane[271]
    DIRECTION INPUT ;
    USE SIGNAL ;
    PORT
      LAYER M5 ;
        RECT  514.032 647.916 514.056 648 ;
    END
  END lane[271]
  PIN lane[272]
    DIRECTION INPUT ;
    USE SIGNAL ;
    PORT
      LAYER M3 ;
        RECT  514.512 647.962 514.53 648 ;
    END
  END lane[272]
  PIN lane[273]
    DIRECTION INPUT ;
    USE SIGNAL ;
    PORT
      LAYER M5 ;
        RECT  514.992 647.916 515.016 648 ;
    END
  END lane[273]
  PIN lane[274]
    DIRECTION INPUT ;
    USE SIGNAL ;
    PORT
      LAYER M3 ;
        RECT  515.448 647.962 515.466 648 ;
    END
  END lane[274]
  PIN lane[275]
    DIRECTION INPUT ;
    USE SIGNAL ;
    PORT
      LAYER M5 ;
        RECT  515.904 647.916 515.928 648 ;
    END
  END lane[275]
  PIN lane[276]
    DIRECTION INPUT ;
    USE SIGNAL ;
    PORT
      LAYER M3 ;
        RECT  516.348 647.962 516.366 648 ;
    END
  END lane[276]
  PIN lane[277]
    DIRECTION INPUT ;
    USE SIGNAL ;
    PORT
      LAYER M5 ;
        RECT  516.816 647.916 516.84 648 ;
    END
  END lane[277]
  PIN lane[278]
    DIRECTION INPUT ;
    USE SIGNAL ;
    PORT
      LAYER M3 ;
        RECT  517.284 647.962 517.302 648 ;
    END
  END lane[278]
  PIN lane[279]
    DIRECTION INPUT ;
    USE SIGNAL ;
    PORT
      LAYER M5 ;
        RECT  517.728 647.916 517.752 648 ;
    END
  END lane[279]
  PIN lane[27]
    DIRECTION INPUT ;
    USE SIGNAL ;
    PORT
      LAYER M5 ;
        RECT  401.472 647.916 401.496 648 ;
    END
  END lane[27]
  PIN lane[280]
    DIRECTION INPUT ;
    USE SIGNAL ;
    PORT
      LAYER M3 ;
        RECT  518.22 647.962 518.238 648 ;
    END
  END lane[280]
  PIN lane[281]
    DIRECTION INPUT ;
    USE SIGNAL ;
    PORT
      LAYER M5 ;
        RECT  518.64 647.916 518.664 648 ;
    END
  END lane[281]
  PIN lane[282]
    DIRECTION INPUT ;
    USE SIGNAL ;
    PORT
      LAYER M3 ;
        RECT  519.12 647.962 519.138 648 ;
    END
  END lane[282]
  PIN lane[283]
    DIRECTION INPUT ;
    USE SIGNAL ;
    PORT
      LAYER M5 ;
        RECT  519.6 647.916 519.624 648 ;
    END
  END lane[283]
  PIN lane[284]
    DIRECTION INPUT ;
    USE SIGNAL ;
    PORT
      LAYER M3 ;
        RECT  520.056 647.962 520.074 648 ;
    END
  END lane[284]
  PIN lane[285]
    DIRECTION INPUT ;
    USE SIGNAL ;
    PORT
      LAYER M5 ;
        RECT  520.512 647.916 520.536 648 ;
    END
  END lane[285]
  PIN lane[286]
    DIRECTION INPUT ;
    USE SIGNAL ;
    PORT
      LAYER M3 ;
        RECT  520.956 647.962 520.974 648 ;
    END
  END lane[286]
  PIN lane[287]
    DIRECTION INPUT ;
    USE SIGNAL ;
    PORT
      LAYER M5 ;
        RECT  521.424 647.916 521.448 648 ;
    END
  END lane[287]
  PIN lane[288]
    DIRECTION INPUT ;
    USE SIGNAL ;
    PORT
      LAYER M3 ;
        RECT  521.892 647.962 521.91 648 ;
    END
  END lane[288]
  PIN lane[289]
    DIRECTION INPUT ;
    USE SIGNAL ;
    PORT
      LAYER M5 ;
        RECT  522.336 647.916 522.36 648 ;
    END
  END lane[289]
  PIN lane[28]
    DIRECTION INPUT ;
    USE SIGNAL ;
    PORT
      LAYER M3 ;
        RECT  401.94 647.962 401.958 648 ;
    END
  END lane[28]
  PIN lane[290]
    DIRECTION INPUT ;
    USE SIGNAL ;
    PORT
      LAYER M3 ;
        RECT  522.828 647.962 522.846 648 ;
    END
  END lane[290]
  PIN lane[291]
    DIRECTION INPUT ;
    USE SIGNAL ;
    PORT
      LAYER M5 ;
        RECT  523.296 647.916 523.32 648 ;
    END
  END lane[291]
  PIN lane[292]
    DIRECTION INPUT ;
    USE SIGNAL ;
    PORT
      LAYER M3 ;
        RECT  523.728 647.962 523.746 648 ;
    END
  END lane[292]
  PIN lane[293]
    DIRECTION INPUT ;
    USE SIGNAL ;
    PORT
      LAYER M5 ;
        RECT  524.208 647.916 524.232 648 ;
    END
  END lane[293]
  PIN lane[294]
    DIRECTION INPUT ;
    USE SIGNAL ;
    PORT
      LAYER M3 ;
        RECT  524.664 647.962 524.682 648 ;
    END
  END lane[294]
  PIN lane[295]
    DIRECTION INPUT ;
    USE SIGNAL ;
    PORT
      LAYER M5 ;
        RECT  525.12 647.916 525.144 648 ;
    END
  END lane[295]
  PIN lane[296]
    DIRECTION INPUT ;
    USE SIGNAL ;
    PORT
      LAYER M3 ;
        RECT  525.6 647.962 525.618 648 ;
    END
  END lane[296]
  PIN lane[297]
    DIRECTION INPUT ;
    USE SIGNAL ;
    PORT
      LAYER M5 ;
        RECT  526.032 647.916 526.056 648 ;
    END
  END lane[297]
  PIN lane[298]
    DIRECTION INPUT ;
    USE SIGNAL ;
    PORT
      LAYER M3 ;
        RECT  526.5 647.962 526.518 648 ;
    END
  END lane[298]
  PIN lane[299]
    DIRECTION INPUT ;
    USE SIGNAL ;
    PORT
      LAYER M5 ;
        RECT  526.944 647.916 526.968 648 ;
    END
  END lane[299]
  PIN lane[29]
    DIRECTION INPUT ;
    USE SIGNAL ;
    PORT
      LAYER M5 ;
        RECT  402.384 647.916 402.408 648 ;
    END
  END lane[29]
  PIN lane[2]
    DIRECTION INPUT ;
    USE SIGNAL ;
    PORT
      LAYER M3 ;
        RECT  389.952 647.962 389.97 648 ;
    END
  END lane[2]
  PIN lane[300]
    DIRECTION INPUT ;
    USE SIGNAL ;
    PORT
      LAYER M3 ;
        RECT  527.436 647.962 527.454 648 ;
    END
  END lane[300]
  PIN lane[301]
    DIRECTION INPUT ;
    USE SIGNAL ;
    PORT
      LAYER M5 ;
        RECT  527.904 647.916 527.928 648 ;
    END
  END lane[301]
  PIN lane[302]
    DIRECTION INPUT ;
    USE SIGNAL ;
    PORT
      LAYER M3 ;
        RECT  528.336 647.962 528.354 648 ;
    END
  END lane[302]
  PIN lane[303]
    DIRECTION INPUT ;
    USE SIGNAL ;
    PORT
      LAYER M5 ;
        RECT  528.816 647.916 528.84 648 ;
    END
  END lane[303]
  PIN lane[304]
    DIRECTION INPUT ;
    USE SIGNAL ;
    PORT
      LAYER M3 ;
        RECT  529.272 647.962 529.29 648 ;
    END
  END lane[304]
  PIN lane[305]
    DIRECTION INPUT ;
    USE SIGNAL ;
    PORT
      LAYER M5 ;
        RECT  529.728 647.916 529.752 648 ;
    END
  END lane[305]
  PIN lane[306]
    DIRECTION INPUT ;
    USE SIGNAL ;
    PORT
      LAYER M3 ;
        RECT  530.208 647.962 530.226 648 ;
    END
  END lane[306]
  PIN lane[307]
    DIRECTION INPUT ;
    USE SIGNAL ;
    PORT
      LAYER M5 ;
        RECT  530.64 647.916 530.664 648 ;
    END
  END lane[307]
  PIN lane[308]
    DIRECTION INPUT ;
    USE SIGNAL ;
    PORT
      LAYER M3 ;
        RECT  531.108 647.962 531.126 648 ;
    END
  END lane[308]
  PIN lane[309]
    DIRECTION INPUT ;
    USE SIGNAL ;
    PORT
      LAYER M5 ;
        RECT  531.6 647.916 531.624 648 ;
    END
  END lane[309]
  PIN lane[30]
    DIRECTION INPUT ;
    USE SIGNAL ;
    PORT
      LAYER M3 ;
        RECT  402.876 647.962 402.894 648 ;
    END
  END lane[30]
  PIN lane[310]
    DIRECTION INPUT ;
    USE SIGNAL ;
    PORT
      LAYER M3 ;
        RECT  532.044 647.962 532.062 648 ;
    END
  END lane[310]
  PIN lane[311]
    DIRECTION INPUT ;
    USE SIGNAL ;
    PORT
      LAYER M5 ;
        RECT  532.512 647.916 532.536 648 ;
    END
  END lane[311]
  PIN lane[312]
    DIRECTION INPUT ;
    USE SIGNAL ;
    PORT
      LAYER M3 ;
        RECT  532.98 647.962 532.998 648 ;
    END
  END lane[312]
  PIN lane[313]
    DIRECTION INPUT ;
    USE SIGNAL ;
    PORT
      LAYER M5 ;
        RECT  533.424 647.916 533.448 648 ;
    END
  END lane[313]
  PIN lane[314]
    DIRECTION INPUT ;
    USE SIGNAL ;
    PORT
      LAYER M3 ;
        RECT  533.88 647.962 533.898 648 ;
    END
  END lane[314]
  PIN lane[315]
    DIRECTION INPUT ;
    USE SIGNAL ;
    PORT
      LAYER M5 ;
        RECT  534.336 647.916 534.36 648 ;
    END
  END lane[315]
  PIN lane[316]
    DIRECTION INPUT ;
    USE SIGNAL ;
    PORT
      LAYER M3 ;
        RECT  534.816 647.962 534.834 648 ;
    END
  END lane[316]
  PIN lane[317]
    DIRECTION INPUT ;
    USE SIGNAL ;
    PORT
      LAYER M5 ;
        RECT  535.248 647.916 535.272 648 ;
    END
  END lane[317]
  PIN lane[318]
    DIRECTION INPUT ;
    USE SIGNAL ;
    PORT
      LAYER M3 ;
        RECT  535.752 647.962 535.77 648 ;
    END
  END lane[318]
  PIN lane[319]
    DIRECTION INPUT ;
    USE SIGNAL ;
    PORT
      LAYER M5 ;
        RECT  536.208 647.916 536.232 648 ;
    END
  END lane[319]
  PIN lane[31]
    DIRECTION INPUT ;
    USE SIGNAL ;
    PORT
      LAYER M5 ;
        RECT  403.344 647.916 403.368 648 ;
    END
  END lane[31]
  PIN lane[320]
    DIRECTION INPUT ;
    USE SIGNAL ;
    PORT
      LAYER M3 ;
        RECT  536.652 647.962 536.67 648 ;
    END
  END lane[320]
  PIN lane[321]
    DIRECTION INPUT ;
    USE SIGNAL ;
    PORT
      LAYER M5 ;
        RECT  537.12 647.916 537.144 648 ;
    END
  END lane[321]
  PIN lane[322]
    DIRECTION INPUT ;
    USE SIGNAL ;
    PORT
      LAYER M3 ;
        RECT  537.588 647.962 537.606 648 ;
    END
  END lane[322]
  PIN lane[323]
    DIRECTION INPUT ;
    USE SIGNAL ;
    PORT
      LAYER M5 ;
        RECT  538.032 647.916 538.056 648 ;
    END
  END lane[323]
  PIN lane[324]
    DIRECTION INPUT ;
    USE SIGNAL ;
    PORT
      LAYER M3 ;
        RECT  538.488 647.962 538.506 648 ;
    END
  END lane[324]
  PIN lane[325]
    DIRECTION INPUT ;
    USE SIGNAL ;
    PORT
      LAYER M5 ;
        RECT  538.944 647.916 538.968 648 ;
    END
  END lane[325]
  PIN lane[326]
    DIRECTION INPUT ;
    USE SIGNAL ;
    PORT
      LAYER M3 ;
        RECT  539.424 647.962 539.442 648 ;
    END
  END lane[326]
  PIN lane[327]
    DIRECTION INPUT ;
    USE SIGNAL ;
    PORT
      LAYER M5 ;
        RECT  539.904 647.916 539.928 648 ;
    END
  END lane[327]
  PIN lane[328]
    DIRECTION INPUT ;
    USE SIGNAL ;
    PORT
      LAYER M3 ;
        RECT  540.36 647.962 540.378 648 ;
    END
  END lane[328]
  PIN lane[329]
    DIRECTION INPUT ;
    USE SIGNAL ;
    PORT
      LAYER M5 ;
        RECT  540.816 647.916 540.84 648 ;
    END
  END lane[329]
  PIN lane[32]
    DIRECTION INPUT ;
    USE SIGNAL ;
    PORT
      LAYER M3 ;
        RECT  403.776 647.962 403.794 648 ;
    END
  END lane[32]
  PIN lane[330]
    DIRECTION INPUT ;
    USE SIGNAL ;
    PORT
      LAYER M3 ;
        RECT  541.26 647.962 541.278 648 ;
    END
  END lane[330]
  PIN lane[331]
    DIRECTION INPUT ;
    USE SIGNAL ;
    PORT
      LAYER M5 ;
        RECT  541.728 647.916 541.752 648 ;
    END
  END lane[331]
  PIN lane[332]
    DIRECTION INPUT ;
    USE SIGNAL ;
    PORT
      LAYER M3 ;
        RECT  542.196 647.962 542.214 648 ;
    END
  END lane[332]
  PIN lane[333]
    DIRECTION INPUT ;
    USE SIGNAL ;
    PORT
      LAYER M5 ;
        RECT  542.64 647.916 542.664 648 ;
    END
  END lane[333]
  PIN lane[334]
    DIRECTION INPUT ;
    USE SIGNAL ;
    PORT
      LAYER M3 ;
        RECT  543.132 647.962 543.15 648 ;
    END
  END lane[334]
  PIN lane[335]
    DIRECTION INPUT ;
    USE SIGNAL ;
    PORT
      LAYER M5 ;
        RECT  543.552 647.916 543.576 648 ;
    END
  END lane[335]
  PIN lane[336]
    DIRECTION INPUT ;
    USE SIGNAL ;
    PORT
      LAYER M3 ;
        RECT  544.032 647.962 544.05 648 ;
    END
  END lane[336]
  PIN lane[337]
    DIRECTION INPUT ;
    USE SIGNAL ;
    PORT
      LAYER M5 ;
        RECT  544.512 647.916 544.536 648 ;
    END
  END lane[337]
  PIN lane[338]
    DIRECTION INPUT ;
    USE SIGNAL ;
    PORT
      LAYER M3 ;
        RECT  544.968 647.962 544.986 648 ;
    END
  END lane[338]
  PIN lane[339]
    DIRECTION INPUT ;
    USE SIGNAL ;
    PORT
      LAYER M5 ;
        RECT  545.424 647.916 545.448 648 ;
    END
  END lane[339]
  PIN lane[33]
    DIRECTION INPUT ;
    USE SIGNAL ;
    PORT
      LAYER M5 ;
        RECT  404.256 647.916 404.28 648 ;
    END
  END lane[33]
  PIN lane[340]
    DIRECTION INPUT ;
    USE SIGNAL ;
    PORT
      LAYER M3 ;
        RECT  545.868 647.962 545.886 648 ;
    END
  END lane[340]
  PIN lane[341]
    DIRECTION INPUT ;
    USE SIGNAL ;
    PORT
      LAYER M5 ;
        RECT  546.336 647.916 546.36 648 ;
    END
  END lane[341]
  PIN lane[342]
    DIRECTION INPUT ;
    USE SIGNAL ;
    PORT
      LAYER M3 ;
        RECT  546.804 647.962 546.822 648 ;
    END
  END lane[342]
  PIN lane[343]
    DIRECTION INPUT ;
    USE SIGNAL ;
    PORT
      LAYER M5 ;
        RECT  547.248 647.916 547.272 648 ;
    END
  END lane[343]
  PIN lane[344]
    DIRECTION INPUT ;
    USE SIGNAL ;
    PORT
      LAYER M3 ;
        RECT  547.74 647.962 547.758 648 ;
    END
  END lane[344]
  PIN lane[345]
    DIRECTION INPUT ;
    USE SIGNAL ;
    PORT
      LAYER M5 ;
        RECT  548.208 647.916 548.232 648 ;
    END
  END lane[345]
  PIN lane[346]
    DIRECTION INPUT ;
    USE SIGNAL ;
    PORT
      LAYER M3 ;
        RECT  548.64 647.962 548.658 648 ;
    END
  END lane[346]
  PIN lane[347]
    DIRECTION INPUT ;
    USE SIGNAL ;
    PORT
      LAYER M5 ;
        RECT  549.12 647.916 549.144 648 ;
    END
  END lane[347]
  PIN lane[348]
    DIRECTION INPUT ;
    USE SIGNAL ;
    PORT
      LAYER M3 ;
        RECT  549.576 647.962 549.594 648 ;
    END
  END lane[348]
  PIN lane[349]
    DIRECTION INPUT ;
    USE SIGNAL ;
    PORT
      LAYER M5 ;
        RECT  550.032 647.916 550.056 648 ;
    END
  END lane[349]
  PIN lane[34]
    DIRECTION INPUT ;
    USE SIGNAL ;
    PORT
      LAYER M3 ;
        RECT  404.712 647.962 404.73 648 ;
    END
  END lane[34]
  PIN lane[350]
    DIRECTION INPUT ;
    USE SIGNAL ;
    PORT
      LAYER M3 ;
        RECT  550.512 647.962 550.53 648 ;
    END
  END lane[350]
  PIN lane[351]
    DIRECTION INPUT ;
    USE SIGNAL ;
    PORT
      LAYER M5 ;
        RECT  550.944 647.916 550.968 648 ;
    END
  END lane[351]
  PIN lane[352]
    DIRECTION INPUT ;
    USE SIGNAL ;
    PORT
      LAYER M3 ;
        RECT  551.412 647.962 551.43 648 ;
    END
  END lane[352]
  PIN lane[353]
    DIRECTION INPUT ;
    USE SIGNAL ;
    PORT
      LAYER M5 ;
        RECT  551.856 647.916 551.88 648 ;
    END
  END lane[353]
  PIN lane[354]
    DIRECTION INPUT ;
    USE SIGNAL ;
    PORT
      LAYER M3 ;
        RECT  552.348 647.962 552.366 648 ;
    END
  END lane[354]
  PIN lane[355]
    DIRECTION INPUT ;
    USE SIGNAL ;
    PORT
      LAYER M5 ;
        RECT  552.816 647.916 552.84 648 ;
    END
  END lane[355]
  PIN lane[356]
    DIRECTION INPUT ;
    USE SIGNAL ;
    PORT
      LAYER M3 ;
        RECT  553.284 647.962 553.302 648 ;
    END
  END lane[356]
  PIN lane[357]
    DIRECTION INPUT ;
    USE SIGNAL ;
    PORT
      LAYER M5 ;
        RECT  553.728 647.916 553.752 648 ;
    END
  END lane[357]
  PIN lane[358]
    DIRECTION INPUT ;
    USE SIGNAL ;
    PORT
      LAYER M3 ;
        RECT  554.184 647.962 554.202 648 ;
    END
  END lane[358]
  PIN lane[359]
    DIRECTION INPUT ;
    USE SIGNAL ;
    PORT
      LAYER M5 ;
        RECT  554.64 647.916 554.664 648 ;
    END
  END lane[359]
  PIN lane[35]
    DIRECTION INPUT ;
    USE SIGNAL ;
    PORT
      LAYER M5 ;
        RECT  405.168 647.916 405.192 648 ;
    END
  END lane[35]
  PIN lane[360]
    DIRECTION INPUT ;
    USE SIGNAL ;
    PORT
      LAYER M3 ;
        RECT  555.12 647.962 555.138 648 ;
    END
  END lane[360]
  PIN lane[361]
    DIRECTION INPUT ;
    USE SIGNAL ;
    PORT
      LAYER M5 ;
        RECT  555.552 647.916 555.576 648 ;
    END
  END lane[361]
  PIN lane[362]
    DIRECTION INPUT ;
    USE SIGNAL ;
    PORT
      LAYER M3 ;
        RECT  556.02 647.962 556.038 648 ;
    END
  END lane[362]
  PIN lane[363]
    DIRECTION INPUT ;
    USE SIGNAL ;
    PORT
      LAYER M5 ;
        RECT  556.512 647.916 556.536 648 ;
    END
  END lane[363]
  PIN lane[364]
    DIRECTION INPUT ;
    USE SIGNAL ;
    PORT
      LAYER M3 ;
        RECT  556.956 647.962 556.974 648 ;
    END
  END lane[364]
  PIN lane[365]
    DIRECTION INPUT ;
    USE SIGNAL ;
    PORT
      LAYER M5 ;
        RECT  557.424 647.916 557.448 648 ;
    END
  END lane[365]
  PIN lane[366]
    DIRECTION INPUT ;
    USE SIGNAL ;
    PORT
      LAYER M3 ;
        RECT  557.892 647.962 557.91 648 ;
    END
  END lane[366]
  PIN lane[367]
    DIRECTION INPUT ;
    USE SIGNAL ;
    PORT
      LAYER M5 ;
        RECT  558.336 647.916 558.36 648 ;
    END
  END lane[367]
  PIN lane[368]
    DIRECTION INPUT ;
    USE SIGNAL ;
    PORT
      LAYER M3 ;
        RECT  558.792 647.962 558.81 648 ;
    END
  END lane[368]
  PIN lane[369]
    DIRECTION INPUT ;
    USE SIGNAL ;
    PORT
      LAYER M5 ;
        RECT  559.248 647.916 559.272 648 ;
    END
  END lane[369]
  PIN lane[36]
    DIRECTION INPUT ;
    USE SIGNAL ;
    PORT
      LAYER M3 ;
        RECT  405.648 647.962 405.666 648 ;
    END
  END lane[36]
  PIN lane[370]
    DIRECTION INPUT ;
    USE SIGNAL ;
    PORT
      LAYER M3 ;
        RECT  559.728 647.962 559.746 648 ;
    END
  END lane[370]
  PIN lane[371]
    DIRECTION INPUT ;
    USE SIGNAL ;
    PORT
      LAYER M5 ;
        RECT  560.16 647.916 560.184 648 ;
    END
  END lane[371]
  PIN lane[372]
    DIRECTION INPUT ;
    USE SIGNAL ;
    PORT
      LAYER M3 ;
        RECT  560.664 647.962 560.682 648 ;
    END
  END lane[372]
  PIN lane[373]
    DIRECTION INPUT ;
    USE SIGNAL ;
    PORT
      LAYER M5 ;
        RECT  561.12 647.916 561.144 648 ;
    END
  END lane[373]
  PIN lane[374]
    DIRECTION INPUT ;
    USE SIGNAL ;
    PORT
      LAYER M3 ;
        RECT  561.564 647.962 561.582 648 ;
    END
  END lane[374]
  PIN lane[375]
    DIRECTION INPUT ;
    USE SIGNAL ;
    PORT
      LAYER M5 ;
        RECT  562.032 647.916 562.056 648 ;
    END
  END lane[375]
  PIN lane[376]
    DIRECTION INPUT ;
    USE SIGNAL ;
    PORT
      LAYER M3 ;
        RECT  562.5 647.962 562.518 648 ;
    END
  END lane[376]
  PIN lane[377]
    DIRECTION INPUT ;
    USE SIGNAL ;
    PORT
      LAYER M5 ;
        RECT  562.944 647.916 562.968 648 ;
    END
  END lane[377]
  PIN lane[378]
    DIRECTION INPUT ;
    USE SIGNAL ;
    PORT
      LAYER M3 ;
        RECT  563.4 647.962 563.418 648 ;
    END
  END lane[378]
  PIN lane[379]
    DIRECTION INPUT ;
    USE SIGNAL ;
    PORT
      LAYER M5 ;
        RECT  563.856 647.916 563.88 648 ;
    END
  END lane[379]
  PIN lane[37]
    DIRECTION INPUT ;
    USE SIGNAL ;
    PORT
      LAYER M5 ;
        RECT  406.08 647.916 406.104 648 ;
    END
  END lane[37]
  PIN lane[380]
    DIRECTION INPUT ;
    USE SIGNAL ;
    PORT
      LAYER M3 ;
        RECT  564.336 647.962 564.354 648 ;
    END
  END lane[380]
  PIN lane[381]
    DIRECTION INPUT ;
    USE SIGNAL ;
    PORT
      LAYER M5 ;
        RECT  564.816 647.916 564.84 648 ;
    END
  END lane[381]
  PIN lane[382]
    DIRECTION INPUT ;
    USE SIGNAL ;
    PORT
      LAYER M3 ;
        RECT  565.272 647.962 565.29 648 ;
    END
  END lane[382]
  PIN lane[383]
    DIRECTION INPUT ;
    USE SIGNAL ;
    PORT
      LAYER M5 ;
        RECT  565.728 647.916 565.752 648 ;
    END
  END lane[383]
  PIN lane[384]
    DIRECTION INPUT ;
    USE SIGNAL ;
    PORT
      LAYER M3 ;
        RECT  566.172 647.962 566.19 648 ;
    END
  END lane[384]
  PIN lane[385]
    DIRECTION INPUT ;
    USE SIGNAL ;
    PORT
      LAYER M5 ;
        RECT  566.64 647.916 566.664 648 ;
    END
  END lane[385]
  PIN lane[386]
    DIRECTION INPUT ;
    USE SIGNAL ;
    PORT
      LAYER M3 ;
        RECT  567.108 647.962 567.126 648 ;
    END
  END lane[386]
  PIN lane[387]
    DIRECTION INPUT ;
    USE SIGNAL ;
    PORT
      LAYER M5 ;
        RECT  567.552 647.916 567.576 648 ;
    END
  END lane[387]
  PIN lane[388]
    DIRECTION INPUT ;
    USE SIGNAL ;
    PORT
      LAYER M3 ;
        RECT  568.044 647.962 568.062 648 ;
    END
  END lane[388]
  PIN lane[389]
    DIRECTION INPUT ;
    USE SIGNAL ;
    PORT
      LAYER M5 ;
        RECT  568.464 647.916 568.488 648 ;
    END
  END lane[389]
  PIN lane[38]
    DIRECTION INPUT ;
    USE SIGNAL ;
    PORT
      LAYER M3 ;
        RECT  406.548 647.962 406.566 648 ;
    END
  END lane[38]
  PIN lane[390]
    DIRECTION INPUT ;
    USE SIGNAL ;
    PORT
      LAYER M3 ;
        RECT  568.944 647.962 568.962 648 ;
    END
  END lane[390]
  PIN lane[391]
    DIRECTION INPUT ;
    USE SIGNAL ;
    PORT
      LAYER M5 ;
        RECT  569.424 647.916 569.448 648 ;
    END
  END lane[391]
  PIN lane[392]
    DIRECTION INPUT ;
    USE SIGNAL ;
    PORT
      LAYER M3 ;
        RECT  569.88 647.962 569.898 648 ;
    END
  END lane[392]
  PIN lane[393]
    DIRECTION INPUT ;
    USE SIGNAL ;
    PORT
      LAYER M5 ;
        RECT  570.336 647.916 570.36 648 ;
    END
  END lane[393]
  PIN lane[394]
    DIRECTION INPUT ;
    USE SIGNAL ;
    PORT
      LAYER M3 ;
        RECT  570.78 647.962 570.798 648 ;
    END
  END lane[394]
  PIN lane[395]
    DIRECTION INPUT ;
    USE SIGNAL ;
    PORT
      LAYER M5 ;
        RECT  571.248 647.916 571.272 648 ;
    END
  END lane[395]
  PIN lane[396]
    DIRECTION INPUT ;
    USE SIGNAL ;
    PORT
      LAYER M3 ;
        RECT  571.716 647.962 571.734 648 ;
    END
  END lane[396]
  PIN lane[397]
    DIRECTION INPUT ;
    USE SIGNAL ;
    PORT
      LAYER M5 ;
        RECT  572.16 647.916 572.184 648 ;
    END
  END lane[397]
  PIN lane[398]
    DIRECTION INPUT ;
    USE SIGNAL ;
    PORT
      LAYER M3 ;
        RECT  572.652 647.962 572.67 648 ;
    END
  END lane[398]
  PIN lane[399]
    DIRECTION INPUT ;
    USE SIGNAL ;
    PORT
      LAYER M5 ;
        RECT  573.12 647.916 573.144 648 ;
    END
  END lane[399]
  PIN lane[39]
    DIRECTION INPUT ;
    USE SIGNAL ;
    PORT
      LAYER M5 ;
        RECT  406.992 647.916 407.016 648 ;
    END
  END lane[39]
  PIN lane[3]
    DIRECTION INPUT ;
    USE SIGNAL ;
    PORT
      LAYER M5 ;
        RECT  390.384 647.916 390.408 648 ;
    END
  END lane[3]
  PIN lane[400]
    DIRECTION INPUT ;
    USE SIGNAL ;
    PORT
      LAYER M3 ;
        RECT  573.552 647.962 573.57 648 ;
    END
  END lane[400]
  PIN lane[401]
    DIRECTION INPUT ;
    USE SIGNAL ;
    PORT
      LAYER M5 ;
        RECT  574.032 647.916 574.056 648 ;
    END
  END lane[401]
  PIN lane[402]
    DIRECTION INPUT ;
    USE SIGNAL ;
    PORT
      LAYER M3 ;
        RECT  574.488 647.962 574.506 648 ;
    END
  END lane[402]
  PIN lane[403]
    DIRECTION INPUT ;
    USE SIGNAL ;
    PORT
      LAYER M5 ;
        RECT  574.944 647.916 574.968 648 ;
    END
  END lane[403]
  PIN lane[404]
    DIRECTION INPUT ;
    USE SIGNAL ;
    PORT
      LAYER M3 ;
        RECT  575.424 647.962 575.442 648 ;
    END
  END lane[404]
  PIN lane[405]
    DIRECTION INPUT ;
    USE SIGNAL ;
    PORT
      LAYER M5 ;
        RECT  575.856 647.916 575.88 648 ;
    END
  END lane[405]
  PIN lane[406]
    DIRECTION INPUT ;
    USE SIGNAL ;
    PORT
      LAYER M3 ;
        RECT  576.324 647.962 576.342 648 ;
    END
  END lane[406]
  PIN lane[407]
    DIRECTION INPUT ;
    USE SIGNAL ;
    PORT
      LAYER M5 ;
        RECT  576.816 647.916 576.84 648 ;
    END
  END lane[407]
  PIN lane[408]
    DIRECTION INPUT ;
    USE SIGNAL ;
    PORT
      LAYER M3 ;
        RECT  577.26 647.962 577.278 648 ;
    END
  END lane[408]
  PIN lane[409]
    DIRECTION INPUT ;
    USE SIGNAL ;
    PORT
      LAYER M5 ;
        RECT  577.728 647.916 577.752 648 ;
    END
  END lane[409]
  PIN lane[40]
    DIRECTION INPUT ;
    USE SIGNAL ;
    PORT
      LAYER M3 ;
        RECT  407.484 647.962 407.502 648 ;
    END
  END lane[40]
  PIN lane[410]
    DIRECTION INPUT ;
    USE SIGNAL ;
    PORT
      LAYER M3 ;
        RECT  578.196 647.962 578.214 648 ;
    END
  END lane[410]
  PIN lane[411]
    DIRECTION INPUT ;
    USE SIGNAL ;
    PORT
      LAYER M5 ;
        RECT  578.64 647.916 578.664 648 ;
    END
  END lane[411]
  PIN lane[412]
    DIRECTION INPUT ;
    USE SIGNAL ;
    PORT
      LAYER M3 ;
        RECT  579.096 647.962 579.114 648 ;
    END
  END lane[412]
  PIN lane[413]
    DIRECTION INPUT ;
    USE SIGNAL ;
    PORT
      LAYER M5 ;
        RECT  579.552 647.916 579.576 648 ;
    END
  END lane[413]
  PIN lane[414]
    DIRECTION INPUT ;
    USE SIGNAL ;
    PORT
      LAYER M3 ;
        RECT  580.032 647.962 580.05 648 ;
    END
  END lane[414]
  PIN lane[415]
    DIRECTION INPUT ;
    USE SIGNAL ;
    PORT
      LAYER M5 ;
        RECT  580.464 647.916 580.488 648 ;
    END
  END lane[415]
  PIN lane[416]
    DIRECTION INPUT ;
    USE SIGNAL ;
    PORT
      LAYER M3 ;
        RECT  580.932 647.962 580.95 648 ;
    END
  END lane[416]
  PIN lane[417]
    DIRECTION INPUT ;
    USE SIGNAL ;
    PORT
      LAYER M5 ;
        RECT  581.424 647.916 581.448 648 ;
    END
  END lane[417]
  PIN lane[418]
    DIRECTION INPUT ;
    USE SIGNAL ;
    PORT
      LAYER M3 ;
        RECT  581.868 647.962 581.886 648 ;
    END
  END lane[418]
  PIN lane[419]
    DIRECTION INPUT ;
    USE SIGNAL ;
    PORT
      LAYER M5 ;
        RECT  582.336 647.916 582.36 648 ;
    END
  END lane[419]
  PIN lane[41]
    DIRECTION INPUT ;
    USE SIGNAL ;
    PORT
      LAYER M5 ;
        RECT  407.952 647.916 407.976 648 ;
    END
  END lane[41]
  PIN lane[420]
    DIRECTION INPUT ;
    USE SIGNAL ;
    PORT
      LAYER M3 ;
        RECT  582.804 647.962 582.822 648 ;
    END
  END lane[420]
  PIN lane[421]
    DIRECTION INPUT ;
    USE SIGNAL ;
    PORT
      LAYER M5 ;
        RECT  583.248 647.916 583.272 648 ;
    END
  END lane[421]
  PIN lane[422]
    DIRECTION INPUT ;
    USE SIGNAL ;
    PORT
      LAYER M3 ;
        RECT  583.704 647.962 583.722 648 ;
    END
  END lane[422]
  PIN lane[423]
    DIRECTION INPUT ;
    USE SIGNAL ;
    PORT
      LAYER M5 ;
        RECT  584.16 647.916 584.184 648 ;
    END
  END lane[423]
  PIN lane[424]
    DIRECTION INPUT ;
    USE SIGNAL ;
    PORT
      LAYER M3 ;
        RECT  584.64 647.962 584.658 648 ;
    END
  END lane[424]
  PIN lane[425]
    DIRECTION INPUT ;
    USE SIGNAL ;
    PORT
      LAYER M5 ;
        RECT  585.12 647.916 585.144 648 ;
    END
  END lane[425]
  PIN lane[426]
    DIRECTION INPUT ;
    USE SIGNAL ;
    PORT
      LAYER M3 ;
        RECT  585.576 647.962 585.594 648 ;
    END
  END lane[426]
  PIN lane[427]
    DIRECTION INPUT ;
    USE SIGNAL ;
    PORT
      LAYER M5 ;
        RECT  586.032 647.916 586.056 648 ;
    END
  END lane[427]
  PIN lane[428]
    DIRECTION INPUT ;
    USE SIGNAL ;
    PORT
      LAYER M3 ;
        RECT  586.476 647.962 586.494 648 ;
    END
  END lane[428]
  PIN lane[429]
    DIRECTION INPUT ;
    USE SIGNAL ;
    PORT
      LAYER M5 ;
        RECT  586.944 647.916 586.968 648 ;
    END
  END lane[429]
  PIN lane[42]
    DIRECTION INPUT ;
    USE SIGNAL ;
    PORT
      LAYER M3 ;
        RECT  408.384 647.962 408.402 648 ;
    END
  END lane[42]
  PIN lane[430]
    DIRECTION INPUT ;
    USE SIGNAL ;
    PORT
      LAYER M3 ;
        RECT  587.412 647.962 587.43 648 ;
    END
  END lane[430]
  PIN lane[431]
    DIRECTION INPUT ;
    USE SIGNAL ;
    PORT
      LAYER M5 ;
        RECT  587.856 647.916 587.88 648 ;
    END
  END lane[431]
  PIN lane[432]
    DIRECTION INPUT ;
    USE SIGNAL ;
    PORT
      LAYER M3 ;
        RECT  588.312 647.962 588.33 648 ;
    END
  END lane[432]
  PIN lane[433]
    DIRECTION INPUT ;
    USE SIGNAL ;
    PORT
      LAYER M5 ;
        RECT  588.768 647.916 588.792 648 ;
    END
  END lane[433]
  PIN lane[434]
    DIRECTION INPUT ;
    USE SIGNAL ;
    PORT
      LAYER M3 ;
        RECT  589.248 647.962 589.266 648 ;
    END
  END lane[434]
  PIN lane[435]
    DIRECTION INPUT ;
    USE SIGNAL ;
    PORT
      LAYER M5 ;
        RECT  589.728 647.916 589.752 648 ;
    END
  END lane[435]
  PIN lane[436]
    DIRECTION INPUT ;
    USE SIGNAL ;
    PORT
      LAYER M3 ;
        RECT  590.184 647.962 590.202 648 ;
    END
  END lane[436]
  PIN lane[437]
    DIRECTION INPUT ;
    USE SIGNAL ;
    PORT
      LAYER M5 ;
        RECT  590.64 647.916 590.664 648 ;
    END
  END lane[437]
  PIN lane[438]
    DIRECTION INPUT ;
    USE SIGNAL ;
    PORT
      LAYER M3 ;
        RECT  591.12 647.962 591.138 648 ;
    END
  END lane[438]
  PIN lane[439]
    DIRECTION INPUT ;
    USE SIGNAL ;
    PORT
      LAYER M5 ;
        RECT  591.552 647.916 591.576 648 ;
    END
  END lane[439]
  PIN lane[43]
    DIRECTION INPUT ;
    USE SIGNAL ;
    PORT
      LAYER M5 ;
        RECT  408.864 647.916 408.888 648 ;
    END
  END lane[43]
  PIN lane[440]
    DIRECTION INPUT ;
    USE SIGNAL ;
    PORT
      LAYER M3 ;
        RECT  592.02 647.962 592.038 648 ;
    END
  END lane[440]
  PIN lane[441]
    DIRECTION INPUT ;
    USE SIGNAL ;
    PORT
      LAYER M5 ;
        RECT  592.464 647.916 592.488 648 ;
    END
  END lane[441]
  PIN lane[442]
    DIRECTION INPUT ;
    USE SIGNAL ;
    PORT
      LAYER M3 ;
        RECT  592.956 647.962 592.974 648 ;
    END
  END lane[442]
  PIN lane[443]
    DIRECTION INPUT ;
    USE SIGNAL ;
    PORT
      LAYER M5 ;
        RECT  593.424 647.916 593.448 648 ;
    END
  END lane[443]
  PIN lane[444]
    DIRECTION INPUT ;
    USE SIGNAL ;
    PORT
      LAYER M3 ;
        RECT  593.856 647.962 593.874 648 ;
    END
  END lane[444]
  PIN lane[445]
    DIRECTION INPUT ;
    USE SIGNAL ;
    PORT
      LAYER M5 ;
        RECT  594.336 647.916 594.36 648 ;
    END
  END lane[445]
  PIN lane[446]
    DIRECTION INPUT ;
    USE SIGNAL ;
    PORT
      LAYER M3 ;
        RECT  594.792 647.962 594.81 648 ;
    END
  END lane[446]
  PIN lane[447]
    DIRECTION INPUT ;
    USE SIGNAL ;
    PORT
      LAYER M5 ;
        RECT  595.248 647.916 595.272 648 ;
    END
  END lane[447]
  PIN lane[448]
    DIRECTION INPUT ;
    USE SIGNAL ;
    PORT
      LAYER M3 ;
        RECT  595.728 647.962 595.746 648 ;
    END
  END lane[448]
  PIN lane[449]
    DIRECTION INPUT ;
    USE SIGNAL ;
    PORT
      LAYER M5 ;
        RECT  596.16 647.916 596.184 648 ;
    END
  END lane[449]
  PIN lane[44]
    DIRECTION INPUT ;
    USE SIGNAL ;
    PORT
      LAYER M3 ;
        RECT  409.32 647.962 409.338 648 ;
    END
  END lane[44]
  PIN lane[450]
    DIRECTION INPUT ;
    USE SIGNAL ;
    PORT
      LAYER M3 ;
        RECT  596.628 647.962 596.646 648 ;
    END
  END lane[450]
  PIN lane[451]
    DIRECTION INPUT ;
    USE SIGNAL ;
    PORT
      LAYER M5 ;
        RECT  597.072 647.916 597.096 648 ;
    END
  END lane[451]
  PIN lane[452]
    DIRECTION INPUT ;
    USE SIGNAL ;
    PORT
      LAYER M3 ;
        RECT  597.564 647.962 597.582 648 ;
    END
  END lane[452]
  PIN lane[453]
    DIRECTION INPUT ;
    USE SIGNAL ;
    PORT
      LAYER M5 ;
        RECT  598.032 647.916 598.056 648 ;
    END
  END lane[453]
  PIN lane[454]
    DIRECTION INPUT ;
    USE SIGNAL ;
    PORT
      LAYER M3 ;
        RECT  598.464 647.962 598.482 648 ;
    END
  END lane[454]
  PIN lane[455]
    DIRECTION INPUT ;
    USE SIGNAL ;
    PORT
      LAYER M5 ;
        RECT  598.944 647.916 598.968 648 ;
    END
  END lane[455]
  PIN lane[456]
    DIRECTION INPUT ;
    USE SIGNAL ;
    PORT
      LAYER M3 ;
        RECT  599.4 647.962 599.418 648 ;
    END
  END lane[456]
  PIN lane[457]
    DIRECTION INPUT ;
    USE SIGNAL ;
    PORT
      LAYER M5 ;
        RECT  599.856 647.916 599.88 648 ;
    END
  END lane[457]
  PIN lane[458]
    DIRECTION INPUT ;
    USE SIGNAL ;
    PORT
      LAYER M3 ;
        RECT  600.336 647.962 600.354 648 ;
    END
  END lane[458]
  PIN lane[459]
    DIRECTION INPUT ;
    USE SIGNAL ;
    PORT
      LAYER M5 ;
        RECT  600.768 647.916 600.792 648 ;
    END
  END lane[459]
  PIN lane[45]
    DIRECTION INPUT ;
    USE SIGNAL ;
    PORT
      LAYER M5 ;
        RECT  409.776 647.916 409.8 648 ;
    END
  END lane[45]
  PIN lane[460]
    DIRECTION INPUT ;
    USE SIGNAL ;
    PORT
      LAYER M3 ;
        RECT  601.236 647.962 601.254 648 ;
    END
  END lane[460]
  PIN lane[461]
    DIRECTION INPUT ;
    USE SIGNAL ;
    PORT
      LAYER M5 ;
        RECT  601.728 647.916 601.752 648 ;
    END
  END lane[461]
  PIN lane[462]
    DIRECTION INPUT ;
    USE SIGNAL ;
    PORT
      LAYER M3 ;
        RECT  602.172 647.962 602.19 648 ;
    END
  END lane[462]
  PIN lane[463]
    DIRECTION INPUT ;
    USE SIGNAL ;
    PORT
      LAYER M5 ;
        RECT  602.64 647.916 602.664 648 ;
    END
  END lane[463]
  PIN lane[464]
    DIRECTION INPUT ;
    USE SIGNAL ;
    PORT
      LAYER M3 ;
        RECT  603.108 647.962 603.126 648 ;
    END
  END lane[464]
  PIN lane[465]
    DIRECTION INPUT ;
    USE SIGNAL ;
    PORT
      LAYER M5 ;
        RECT  603.552 647.916 603.576 648 ;
    END
  END lane[465]
  PIN lane[466]
    DIRECTION INPUT ;
    USE SIGNAL ;
    PORT
      LAYER M3 ;
        RECT  604.008 647.962 604.026 648 ;
    END
  END lane[466]
  PIN lane[467]
    DIRECTION INPUT ;
    USE SIGNAL ;
    PORT
      LAYER M5 ;
        RECT  604.464 647.916 604.488 648 ;
    END
  END lane[467]
  PIN lane[468]
    DIRECTION INPUT ;
    USE SIGNAL ;
    PORT
      LAYER M3 ;
        RECT  604.944 647.962 604.962 648 ;
    END
  END lane[468]
  PIN lane[469]
    DIRECTION INPUT ;
    USE SIGNAL ;
    PORT
      LAYER M5 ;
        RECT  605.376 647.916 605.4 648 ;
    END
  END lane[469]
  PIN lane[46]
    DIRECTION INPUT ;
    USE SIGNAL ;
    PORT
      LAYER M3 ;
        RECT  410.256 647.962 410.274 648 ;
    END
  END lane[46]
  PIN lane[470]
    DIRECTION INPUT ;
    USE SIGNAL ;
    PORT
      LAYER M3 ;
        RECT  605.844 647.962 605.862 648 ;
    END
  END lane[470]
  PIN lane[471]
    DIRECTION INPUT ;
    USE SIGNAL ;
    PORT
      LAYER M5 ;
        RECT  606.336 647.916 606.36 648 ;
    END
  END lane[471]
  PIN lane[472]
    DIRECTION INPUT ;
    USE SIGNAL ;
    PORT
      LAYER M3 ;
        RECT  606.78 647.962 606.798 648 ;
    END
  END lane[472]
  PIN lane[473]
    DIRECTION INPUT ;
    USE SIGNAL ;
    PORT
      LAYER M5 ;
        RECT  607.248 647.916 607.272 648 ;
    END
  END lane[473]
  PIN lane[474]
    DIRECTION INPUT ;
    USE SIGNAL ;
    PORT
      LAYER M3 ;
        RECT  607.716 647.962 607.734 648 ;
    END
  END lane[474]
  PIN lane[475]
    DIRECTION INPUT ;
    USE SIGNAL ;
    PORT
      LAYER M5 ;
        RECT  608.16 647.916 608.184 648 ;
    END
  END lane[475]
  PIN lane[476]
    DIRECTION INPUT ;
    USE SIGNAL ;
    PORT
      LAYER M3 ;
        RECT  608.616 647.962 608.634 648 ;
    END
  END lane[476]
  PIN lane[477]
    DIRECTION INPUT ;
    USE SIGNAL ;
    PORT
      LAYER M5 ;
        RECT  609.072 647.916 609.096 648 ;
    END
  END lane[477]
  PIN lane[478]
    DIRECTION INPUT ;
    USE SIGNAL ;
    PORT
      LAYER M3 ;
        RECT  609.552 647.962 609.57 648 ;
    END
  END lane[478]
  PIN lane[479]
    DIRECTION INPUT ;
    USE SIGNAL ;
    PORT
      LAYER M5 ;
        RECT  610.032 647.916 610.056 648 ;
    END
  END lane[479]
  PIN lane[47]
    DIRECTION INPUT ;
    USE SIGNAL ;
    PORT
      LAYER M5 ;
        RECT  410.688 647.916 410.712 648 ;
    END
  END lane[47]
  PIN lane[480]
    DIRECTION INPUT ;
    USE SIGNAL ;
    PORT
      LAYER M3 ;
        RECT  610.488 647.962 610.506 648 ;
    END
  END lane[480]
  PIN lane[481]
    DIRECTION INPUT ;
    USE SIGNAL ;
    PORT
      LAYER M5 ;
        RECT  610.944 647.916 610.968 648 ;
    END
  END lane[481]
  PIN lane[482]
    DIRECTION INPUT ;
    USE SIGNAL ;
    PORT
      LAYER M3 ;
        RECT  611.388 647.962 611.406 648 ;
    END
  END lane[482]
  PIN lane[483]
    DIRECTION INPUT ;
    USE SIGNAL ;
    PORT
      LAYER M5 ;
        RECT  611.856 647.916 611.88 648 ;
    END
  END lane[483]
  PIN lane[484]
    DIRECTION INPUT ;
    USE SIGNAL ;
    PORT
      LAYER M3 ;
        RECT  612.324 647.962 612.342 648 ;
    END
  END lane[484]
  PIN lane[485]
    DIRECTION INPUT ;
    USE SIGNAL ;
    PORT
      LAYER M5 ;
        RECT  612.768 647.916 612.792 648 ;
    END
  END lane[485]
  PIN lane[486]
    DIRECTION INPUT ;
    USE SIGNAL ;
    PORT
      LAYER M3 ;
        RECT  613.26 647.962 613.278 648 ;
    END
  END lane[486]
  PIN lane[487]
    DIRECTION INPUT ;
    USE SIGNAL ;
    PORT
      LAYER M5 ;
        RECT  613.68 647.916 613.704 648 ;
    END
  END lane[487]
  PIN lane[488]
    DIRECTION INPUT ;
    USE SIGNAL ;
    PORT
      LAYER M3 ;
        RECT  614.16 647.962 614.178 648 ;
    END
  END lane[488]
  PIN lane[489]
    DIRECTION INPUT ;
    USE SIGNAL ;
    PORT
      LAYER M5 ;
        RECT  614.64 647.916 614.664 648 ;
    END
  END lane[489]
  PIN lane[48]
    DIRECTION INPUT ;
    USE SIGNAL ;
    PORT
      LAYER M3 ;
        RECT  411.156 647.962 411.174 648 ;
    END
  END lane[48]
  PIN lane[490]
    DIRECTION INPUT ;
    USE SIGNAL ;
    PORT
      LAYER M3 ;
        RECT  615.096 647.962 615.114 648 ;
    END
  END lane[490]
  PIN lane[491]
    DIRECTION INPUT ;
    USE SIGNAL ;
    PORT
      LAYER M5 ;
        RECT  615.552 647.916 615.576 648 ;
    END
  END lane[491]
  PIN lane[492]
    DIRECTION INPUT ;
    USE SIGNAL ;
    PORT
      LAYER M3 ;
        RECT  615.996 647.962 616.014 648 ;
    END
  END lane[492]
  PIN lane[493]
    DIRECTION INPUT ;
    USE SIGNAL ;
    PORT
      LAYER M5 ;
        RECT  616.464 647.916 616.488 648 ;
    END
  END lane[493]
  PIN lane[494]
    DIRECTION INPUT ;
    USE SIGNAL ;
    PORT
      LAYER M3 ;
        RECT  616.932 647.962 616.95 648 ;
    END
  END lane[494]
  PIN lane[495]
    DIRECTION INPUT ;
    USE SIGNAL ;
    PORT
      LAYER M5 ;
        RECT  617.376 647.916 617.4 648 ;
    END
  END lane[495]
  PIN lane[496]
    DIRECTION INPUT ;
    USE SIGNAL ;
    PORT
      LAYER M3 ;
        RECT  617.868 647.962 617.886 648 ;
    END
  END lane[496]
  PIN lane[497]
    DIRECTION INPUT ;
    USE SIGNAL ;
    PORT
      LAYER M5 ;
        RECT  618.336 647.916 618.36 648 ;
    END
  END lane[497]
  PIN lane[498]
    DIRECTION INPUT ;
    USE SIGNAL ;
    PORT
      LAYER M3 ;
        RECT  618.768 647.962 618.786 648 ;
    END
  END lane[498]
  PIN lane[499]
    DIRECTION INPUT ;
    USE SIGNAL ;
    PORT
      LAYER M5 ;
        RECT  619.248 647.916 619.272 648 ;
    END
  END lane[499]
  PIN lane[49]
    DIRECTION INPUT ;
    USE SIGNAL ;
    PORT
      LAYER M5 ;
        RECT  411.648 647.916 411.672 648 ;
    END
  END lane[49]
  PIN lane[4]
    DIRECTION INPUT ;
    USE SIGNAL ;
    PORT
      LAYER M3 ;
        RECT  390.852 647.962 390.87 648 ;
    END
  END lane[4]
  PIN lane[500]
    DIRECTION INPUT ;
    USE SIGNAL ;
    PORT
      LAYER M3 ;
        RECT  619.704 647.962 619.722 648 ;
    END
  END lane[500]
  PIN lane[501]
    DIRECTION INPUT ;
    USE SIGNAL ;
    PORT
      LAYER M5 ;
        RECT  620.16 647.916 620.184 648 ;
    END
  END lane[501]
  PIN lane[502]
    DIRECTION INPUT ;
    USE SIGNAL ;
    PORT
      LAYER M3 ;
        RECT  620.64 647.962 620.658 648 ;
    END
  END lane[502]
  PIN lane[503]
    DIRECTION INPUT ;
    USE SIGNAL ;
    PORT
      LAYER M5 ;
        RECT  621.072 647.916 621.096 648 ;
    END
  END lane[503]
  PIN lane[504]
    DIRECTION INPUT ;
    USE SIGNAL ;
    PORT
      LAYER M3 ;
        RECT  621.54 647.962 621.558 648 ;
    END
  END lane[504]
  PIN lane[505]
    DIRECTION INPUT ;
    USE SIGNAL ;
    PORT
      LAYER M5 ;
        RECT  621.984 647.916 622.008 648 ;
    END
  END lane[505]
  PIN lane[506]
    DIRECTION INPUT ;
    USE SIGNAL ;
    PORT
      LAYER M3 ;
        RECT  622.476 647.962 622.494 648 ;
    END
  END lane[506]
  PIN lane[507]
    DIRECTION INPUT ;
    USE SIGNAL ;
    PORT
      LAYER M5 ;
        RECT  622.944 647.916 622.968 648 ;
    END
  END lane[507]
  PIN lane[508]
    DIRECTION INPUT ;
    USE SIGNAL ;
    PORT
      LAYER M3 ;
        RECT  623.376 647.962 623.394 648 ;
    END
  END lane[508]
  PIN lane[509]
    DIRECTION INPUT ;
    USE SIGNAL ;
    PORT
      LAYER M5 ;
        RECT  623.856 647.916 623.88 648 ;
    END
  END lane[509]
  PIN lane[50]
    DIRECTION INPUT ;
    USE SIGNAL ;
    PORT
      LAYER M3 ;
        RECT  412.092 647.962 412.11 648 ;
    END
  END lane[50]
  PIN lane[510]
    DIRECTION INPUT ;
    USE SIGNAL ;
    PORT
      LAYER M3 ;
        RECT  624.312 647.962 624.33 648 ;
    END
  END lane[510]
  PIN lane[511]
    DIRECTION INPUT ;
    USE SIGNAL ;
    PORT
      LAYER M5 ;
        RECT  624.768 647.916 624.792 648 ;
    END
  END lane[511]
  PIN lane[512]
    DIRECTION INPUT ;
    USE SIGNAL ;
    PORT
      LAYER M3 ;
        RECT  625.248 647.962 625.266 648 ;
    END
  END lane[512]
  PIN lane[513]
    DIRECTION INPUT ;
    USE SIGNAL ;
    PORT
      LAYER M5 ;
        RECT  625.68 647.916 625.704 648 ;
    END
  END lane[513]
  PIN lane[514]
    DIRECTION INPUT ;
    USE SIGNAL ;
    PORT
      LAYER M3 ;
        RECT  626.148 647.962 626.166 648 ;
    END
  END lane[514]
  PIN lane[51]
    DIRECTION INPUT ;
    USE SIGNAL ;
    PORT
      LAYER M5 ;
        RECT  412.56 647.916 412.584 648 ;
    END
  END lane[51]
  PIN lane[52]
    DIRECTION INPUT ;
    USE SIGNAL ;
    PORT
      LAYER M3 ;
        RECT  413.028 647.962 413.046 648 ;
    END
  END lane[52]
  PIN lane[53]
    DIRECTION INPUT ;
    USE SIGNAL ;
    PORT
      LAYER M5 ;
        RECT  413.472 647.916 413.496 648 ;
    END
  END lane[53]
  PIN lane[54]
    DIRECTION INPUT ;
    USE SIGNAL ;
    PORT
      LAYER M3 ;
        RECT  413.928 647.962 413.946 648 ;
    END
  END lane[54]
  PIN lane[55]
    DIRECTION INPUT ;
    USE SIGNAL ;
    PORT
      LAYER M5 ;
        RECT  414.384 647.916 414.408 648 ;
    END
  END lane[55]
  PIN lane[56]
    DIRECTION INPUT ;
    USE SIGNAL ;
    PORT
      LAYER M3 ;
        RECT  414.864 647.962 414.882 648 ;
    END
  END lane[56]
  PIN lane[57]
    DIRECTION INPUT ;
    USE SIGNAL ;
    PORT
      LAYER M5 ;
        RECT  415.296 647.916 415.32 648 ;
    END
  END lane[57]
  PIN lane[58]
    DIRECTION INPUT ;
    USE SIGNAL ;
    PORT
      LAYER M3 ;
        RECT  415.764 647.962 415.782 648 ;
    END
  END lane[58]
  PIN lane[59]
    DIRECTION INPUT ;
    USE SIGNAL ;
    PORT
      LAYER M5 ;
        RECT  416.256 647.916 416.28 648 ;
    END
  END lane[59]
  PIN lane[5]
    DIRECTION INPUT ;
    USE SIGNAL ;
    PORT
      LAYER M5 ;
        RECT  391.344 647.916 391.368 648 ;
    END
  END lane[5]
  PIN lane[60]
    DIRECTION INPUT ;
    USE SIGNAL ;
    PORT
      LAYER M3 ;
        RECT  416.7 647.962 416.718 648 ;
    END
  END lane[60]
  PIN lane[61]
    DIRECTION INPUT ;
    USE SIGNAL ;
    PORT
      LAYER M5 ;
        RECT  417.168 647.916 417.192 648 ;
    END
  END lane[61]
  PIN lane[62]
    DIRECTION INPUT ;
    USE SIGNAL ;
    PORT
      LAYER M3 ;
        RECT  417.636 647.962 417.654 648 ;
    END
  END lane[62]
  PIN lane[63]
    DIRECTION INPUT ;
    USE SIGNAL ;
    PORT
      LAYER M5 ;
        RECT  418.08 647.916 418.104 648 ;
    END
  END lane[63]
  PIN lane[64]
    DIRECTION INPUT ;
    USE SIGNAL ;
    PORT
      LAYER M3 ;
        RECT  418.536 647.962 418.554 648 ;
    END
  END lane[64]
  PIN lane[65]
    DIRECTION INPUT ;
    USE SIGNAL ;
    PORT
      LAYER M5 ;
        RECT  418.992 647.916 419.016 648 ;
    END
  END lane[65]
  PIN lane[66]
    DIRECTION INPUT ;
    USE SIGNAL ;
    PORT
      LAYER M3 ;
        RECT  419.472 647.962 419.49 648 ;
    END
  END lane[66]
  PIN lane[67]
    DIRECTION INPUT ;
    USE SIGNAL ;
    PORT
      LAYER M5 ;
        RECT  419.952 647.916 419.976 648 ;
    END
  END lane[67]
  PIN lane[68]
    DIRECTION INPUT ;
    USE SIGNAL ;
    PORT
      LAYER M3 ;
        RECT  420.408 647.962 420.426 648 ;
    END
  END lane[68]
  PIN lane[69]
    DIRECTION INPUT ;
    USE SIGNAL ;
    PORT
      LAYER M5 ;
        RECT  420.864 647.916 420.888 648 ;
    END
  END lane[69]
  PIN lane[6]
    DIRECTION INPUT ;
    USE SIGNAL ;
    PORT
      LAYER M3 ;
        RECT  391.788 647.962 391.806 648 ;
    END
  END lane[6]
  PIN lane[70]
    DIRECTION INPUT ;
    USE SIGNAL ;
    PORT
      LAYER M3 ;
        RECT  421.308 647.962 421.326 648 ;
    END
  END lane[70]
  PIN lane[71]
    DIRECTION INPUT ;
    USE SIGNAL ;
    PORT
      LAYER M5 ;
        RECT  421.776 647.916 421.8 648 ;
    END
  END lane[71]
  PIN lane[72]
    DIRECTION INPUT ;
    USE SIGNAL ;
    PORT
      LAYER M3 ;
        RECT  422.244 647.962 422.262 648 ;
    END
  END lane[72]
  PIN lane[73]
    DIRECTION INPUT ;
    USE SIGNAL ;
    PORT
      LAYER M5 ;
        RECT  422.688 647.916 422.712 648 ;
    END
  END lane[73]
  PIN lane[74]
    DIRECTION INPUT ;
    USE SIGNAL ;
    PORT
      LAYER M3 ;
        RECT  423.18 647.962 423.198 648 ;
    END
  END lane[74]
  PIN lane[75]
    DIRECTION INPUT ;
    USE SIGNAL ;
    PORT
      LAYER M5 ;
        RECT  423.6 647.916 423.624 648 ;
    END
  END lane[75]
  PIN lane[76]
    DIRECTION INPUT ;
    USE SIGNAL ;
    PORT
      LAYER M3 ;
        RECT  424.08 647.962 424.098 648 ;
    END
  END lane[76]
  PIN lane[77]
    DIRECTION INPUT ;
    USE SIGNAL ;
    PORT
      LAYER M5 ;
        RECT  424.56 647.916 424.584 648 ;
    END
  END lane[77]
  PIN lane[78]
    DIRECTION INPUT ;
    USE SIGNAL ;
    PORT
      LAYER M3 ;
        RECT  425.016 647.962 425.034 648 ;
    END
  END lane[78]
  PIN lane[79]
    DIRECTION INPUT ;
    USE SIGNAL ;
    PORT
      LAYER M5 ;
        RECT  425.472 647.916 425.496 648 ;
    END
  END lane[79]
  PIN lane[7]
    DIRECTION INPUT ;
    USE SIGNAL ;
    PORT
      LAYER M5 ;
        RECT  392.256 647.916 392.28 648 ;
    END
  END lane[7]
  PIN lane[80]
    DIRECTION INPUT ;
    USE SIGNAL ;
    PORT
      LAYER M3 ;
        RECT  425.916 647.962 425.934 648 ;
    END
  END lane[80]
  PIN lane[81]
    DIRECTION INPUT ;
    USE SIGNAL ;
    PORT
      LAYER M5 ;
        RECT  426.384 647.916 426.408 648 ;
    END
  END lane[81]
  PIN lane[82]
    DIRECTION INPUT ;
    USE SIGNAL ;
    PORT
      LAYER M3 ;
        RECT  426.852 647.962 426.87 648 ;
    END
  END lane[82]
  PIN lane[83]
    DIRECTION INPUT ;
    USE SIGNAL ;
    PORT
      LAYER M5 ;
        RECT  427.296 647.916 427.32 648 ;
    END
  END lane[83]
  PIN lane[84]
    DIRECTION INPUT ;
    USE SIGNAL ;
    PORT
      LAYER M3 ;
        RECT  427.788 647.962 427.806 648 ;
    END
  END lane[84]
  PIN lane[85]
    DIRECTION INPUT ;
    USE SIGNAL ;
    PORT
      LAYER M5 ;
        RECT  428.256 647.916 428.28 648 ;
    END
  END lane[85]
  PIN lane[86]
    DIRECTION INPUT ;
    USE SIGNAL ;
    PORT
      LAYER M3 ;
        RECT  428.688 647.962 428.706 648 ;
    END
  END lane[86]
  PIN lane[87]
    DIRECTION INPUT ;
    USE SIGNAL ;
    PORT
      LAYER M5 ;
        RECT  429.168 647.916 429.192 648 ;
    END
  END lane[87]
  PIN lane[88]
    DIRECTION INPUT ;
    USE SIGNAL ;
    PORT
      LAYER M3 ;
        RECT  429.624 647.962 429.642 648 ;
    END
  END lane[88]
  PIN lane[89]
    DIRECTION INPUT ;
    USE SIGNAL ;
    PORT
      LAYER M5 ;
        RECT  430.08 647.916 430.104 648 ;
    END
  END lane[89]
  PIN lane[8]
    DIRECTION INPUT ;
    USE SIGNAL ;
    PORT
      LAYER M3 ;
        RECT  392.724 647.962 392.742 648 ;
    END
  END lane[8]
  PIN lane[90]
    DIRECTION INPUT ;
    USE SIGNAL ;
    PORT
      LAYER M3 ;
        RECT  430.56 647.962 430.578 648 ;
    END
  END lane[90]
  PIN lane[91]
    DIRECTION INPUT ;
    USE SIGNAL ;
    PORT
      LAYER M5 ;
        RECT  430.992 647.916 431.016 648 ;
    END
  END lane[91]
  PIN lane[92]
    DIRECTION INPUT ;
    USE SIGNAL ;
    PORT
      LAYER M3 ;
        RECT  431.46 647.962 431.478 648 ;
    END
  END lane[92]
  PIN lane[93]
    DIRECTION INPUT ;
    USE SIGNAL ;
    PORT
      LAYER M5 ;
        RECT  431.904 647.916 431.928 648 ;
    END
  END lane[93]
  PIN lane[94]
    DIRECTION INPUT ;
    USE SIGNAL ;
    PORT
      LAYER M3 ;
        RECT  432.396 647.962 432.414 648 ;
    END
  END lane[94]
  PIN lane[95]
    DIRECTION INPUT ;
    USE SIGNAL ;
    PORT
      LAYER M5 ;
        RECT  432.864 647.916 432.888 648 ;
    END
  END lane[95]
  PIN lane[96]
    DIRECTION INPUT ;
    USE SIGNAL ;
    PORT
      LAYER M3 ;
        RECT  433.296 647.962 433.314 648 ;
    END
  END lane[96]
  PIN lane[97]
    DIRECTION INPUT ;
    USE SIGNAL ;
    PORT
      LAYER M5 ;
        RECT  433.776 647.916 433.8 648 ;
    END
  END lane[97]
  PIN lane[98]
    DIRECTION INPUT ;
    USE SIGNAL ;
    PORT
      LAYER M3 ;
        RECT  434.232 647.962 434.25 648 ;
    END
  END lane[98]
  PIN lane[99]
    DIRECTION INPUT ;
    USE SIGNAL ;
    PORT
      LAYER M5 ;
        RECT  434.688 647.916 434.712 648 ;
    END
  END lane[99]
  PIN lane[9]
    DIRECTION INPUT ;
    USE SIGNAL ;
    PORT
      LAYER M5 ;
        RECT  393.168 647.916 393.192 648 ;
    END
  END lane[9]
  PIN rst
    DIRECTION INPUT ;
    USE SIGNAL ;
    PORT
      LAYER M3 ;
        RECT  307.836 647.962 307.854 648 ;
    END
  END rst
  PIN t_o[0]
    DIRECTION OUTPUT ;
    USE SIGNAL ;
    PORT
      LAYER M4 ;
        RECT  0 3.072 0.084 3.096 ;
    END
  END t_o[0]
  PIN t_o[100]
    DIRECTION OUTPUT ;
    USE SIGNAL ;
    PORT
      LAYER M4 ;
        RECT  0 184.896 0.084 184.92 ;
    END
  END t_o[100]
  PIN t_o[101]
    DIRECTION OUTPUT ;
    USE SIGNAL ;
    PORT
      LAYER M4 ;
        RECT  0 186.72 0.084 186.744 ;
    END
  END t_o[101]
  PIN t_o[102]
    DIRECTION OUTPUT ;
    USE SIGNAL ;
    PORT
      LAYER M4 ;
        RECT  0 188.544 0.084 188.568 ;
    END
  END t_o[102]
  PIN t_o[103]
    DIRECTION OUTPUT ;
    USE SIGNAL ;
    PORT
      LAYER M4 ;
        RECT  0 190.32 0.084 190.344 ;
    END
  END t_o[103]
  PIN t_o[104]
    DIRECTION OUTPUT ;
    USE SIGNAL ;
    PORT
      LAYER M4 ;
        RECT  0 192.144 0.084 192.168 ;
    END
  END t_o[104]
  PIN t_o[105]
    DIRECTION OUTPUT ;
    USE SIGNAL ;
    PORT
      LAYER M4 ;
        RECT  0 193.968 0.084 193.992 ;
    END
  END t_o[105]
  PIN t_o[106]
    DIRECTION OUTPUT ;
    USE SIGNAL ;
    PORT
      LAYER M4 ;
        RECT  0 195.792 0.084 195.816 ;
    END
  END t_o[106]
  PIN t_o[107]
    DIRECTION OUTPUT ;
    USE SIGNAL ;
    PORT
      LAYER M4 ;
        RECT  0 197.616 0.084 197.64 ;
    END
  END t_o[107]
  PIN t_o[108]
    DIRECTION OUTPUT ;
    USE SIGNAL ;
    PORT
      LAYER M4 ;
        RECT  0 199.44 0.084 199.464 ;
    END
  END t_o[108]
  PIN t_o[109]
    DIRECTION OUTPUT ;
    USE SIGNAL ;
    PORT
      LAYER M4 ;
        RECT  0 201.264 0.084 201.288 ;
    END
  END t_o[109]
  PIN t_o[10]
    DIRECTION OUTPUT ;
    USE SIGNAL ;
    PORT
      LAYER M4 ;
        RECT  0 21.264 0.084 21.288 ;
    END
  END t_o[10]
  PIN t_o[110]
    DIRECTION OUTPUT ;
    USE SIGNAL ;
    PORT
      LAYER M4 ;
        RECT  0 203.088 0.084 203.112 ;
    END
  END t_o[110]
  PIN t_o[111]
    DIRECTION OUTPUT ;
    USE SIGNAL ;
    PORT
      LAYER M4 ;
        RECT  0 204.912 0.084 204.936 ;
    END
  END t_o[111]
  PIN t_o[112]
    DIRECTION OUTPUT ;
    USE SIGNAL ;
    PORT
      LAYER M4 ;
        RECT  0 206.688 0.084 206.712 ;
    END
  END t_o[112]
  PIN t_o[113]
    DIRECTION OUTPUT ;
    USE SIGNAL ;
    PORT
      LAYER M4 ;
        RECT  0 208.512 0.084 208.536 ;
    END
  END t_o[113]
  PIN t_o[114]
    DIRECTION OUTPUT ;
    USE SIGNAL ;
    PORT
      LAYER M4 ;
        RECT  0 210.336 0.084 210.36 ;
    END
  END t_o[114]
  PIN t_o[115]
    DIRECTION OUTPUT ;
    USE SIGNAL ;
    PORT
      LAYER M4 ;
        RECT  0 212.16 0.084 212.184 ;
    END
  END t_o[115]
  PIN t_o[116]
    DIRECTION OUTPUT ;
    USE SIGNAL ;
    PORT
      LAYER M4 ;
        RECT  0 213.984 0.084 214.008 ;
    END
  END t_o[116]
  PIN t_o[117]
    DIRECTION OUTPUT ;
    USE SIGNAL ;
    PORT
      LAYER M4 ;
        RECT  0 215.808 0.084 215.832 ;
    END
  END t_o[117]
  PIN t_o[118]
    DIRECTION OUTPUT ;
    USE SIGNAL ;
    PORT
      LAYER M4 ;
        RECT  0 217.632 0.084 217.656 ;
    END
  END t_o[118]
  PIN t_o[119]
    DIRECTION OUTPUT ;
    USE SIGNAL ;
    PORT
      LAYER M4 ;
        RECT  0 219.456 0.084 219.48 ;
    END
  END t_o[119]
  PIN t_o[11]
    DIRECTION OUTPUT ;
    USE SIGNAL ;
    PORT
      LAYER M4 ;
        RECT  0 23.04 0.084 23.064 ;
    END
  END t_o[11]
  PIN t_o[120]
    DIRECTION OUTPUT ;
    USE SIGNAL ;
    PORT
      LAYER M4 ;
        RECT  0 221.232 0.084 221.256 ;
    END
  END t_o[120]
  PIN t_o[121]
    DIRECTION OUTPUT ;
    USE SIGNAL ;
    PORT
      LAYER M4 ;
        RECT  0 223.056 0.084 223.08 ;
    END
  END t_o[121]
  PIN t_o[122]
    DIRECTION OUTPUT ;
    USE SIGNAL ;
    PORT
      LAYER M4 ;
        RECT  0 224.88 0.084 224.904 ;
    END
  END t_o[122]
  PIN t_o[123]
    DIRECTION OUTPUT ;
    USE SIGNAL ;
    PORT
      LAYER M4 ;
        RECT  0 226.704 0.084 226.728 ;
    END
  END t_o[123]
  PIN t_o[124]
    DIRECTION OUTPUT ;
    USE SIGNAL ;
    PORT
      LAYER M4 ;
        RECT  0 228.528 0.084 228.552 ;
    END
  END t_o[124]
  PIN t_o[125]
    DIRECTION OUTPUT ;
    USE SIGNAL ;
    PORT
      LAYER M4 ;
        RECT  0 230.352 0.084 230.376 ;
    END
  END t_o[125]
  PIN t_o[126]
    DIRECTION OUTPUT ;
    USE SIGNAL ;
    PORT
      LAYER M4 ;
        RECT  0 232.176 0.084 232.2 ;
    END
  END t_o[126]
  PIN t_o[127]
    DIRECTION OUTPUT ;
    USE SIGNAL ;
    PORT
      LAYER M4 ;
        RECT  0 234 0.084 234.024 ;
    END
  END t_o[127]
  PIN t_o[128]
    DIRECTION OUTPUT ;
    USE SIGNAL ;
    PORT
      LAYER M4 ;
        RECT  0 235.824 0.084 235.848 ;
    END
  END t_o[128]
  PIN t_o[129]
    DIRECTION OUTPUT ;
    USE SIGNAL ;
    PORT
      LAYER M4 ;
        RECT  0 237.6 0.084 237.624 ;
    END
  END t_o[129]
  PIN t_o[12]
    DIRECTION OUTPUT ;
    USE SIGNAL ;
    PORT
      LAYER M4 ;
        RECT  0 24.864 0.084 24.888 ;
    END
  END t_o[12]
  PIN t_o[130]
    DIRECTION OUTPUT ;
    USE SIGNAL ;
    PORT
      LAYER M4 ;
        RECT  0 239.424 0.084 239.448 ;
    END
  END t_o[130]
  PIN t_o[131]
    DIRECTION OUTPUT ;
    USE SIGNAL ;
    PORT
      LAYER M4 ;
        RECT  0 241.248 0.084 241.272 ;
    END
  END t_o[131]
  PIN t_o[132]
    DIRECTION OUTPUT ;
    USE SIGNAL ;
    PORT
      LAYER M4 ;
        RECT  0 243.072 0.084 243.096 ;
    END
  END t_o[132]
  PIN t_o[133]
    DIRECTION OUTPUT ;
    USE SIGNAL ;
    PORT
      LAYER M4 ;
        RECT  0 244.896 0.084 244.92 ;
    END
  END t_o[133]
  PIN t_o[134]
    DIRECTION OUTPUT ;
    USE SIGNAL ;
    PORT
      LAYER M4 ;
        RECT  0 246.72 0.084 246.744 ;
    END
  END t_o[134]
  PIN t_o[135]
    DIRECTION OUTPUT ;
    USE SIGNAL ;
    PORT
      LAYER M4 ;
        RECT  0 248.544 0.084 248.568 ;
    END
  END t_o[135]
  PIN t_o[136]
    DIRECTION OUTPUT ;
    USE SIGNAL ;
    PORT
      LAYER M4 ;
        RECT  0 250.368 0.084 250.392 ;
    END
  END t_o[136]
  PIN t_o[137]
    DIRECTION OUTPUT ;
    USE SIGNAL ;
    PORT
      LAYER M4 ;
        RECT  0 252.144 0.084 252.168 ;
    END
  END t_o[137]
  PIN t_o[138]
    DIRECTION OUTPUT ;
    USE SIGNAL ;
    PORT
      LAYER M4 ;
        RECT  0 253.968 0.084 253.992 ;
    END
  END t_o[138]
  PIN t_o[139]
    DIRECTION OUTPUT ;
    USE SIGNAL ;
    PORT
      LAYER M4 ;
        RECT  0 255.792 0.084 255.816 ;
    END
  END t_o[139]
  PIN t_o[13]
    DIRECTION OUTPUT ;
    USE SIGNAL ;
    PORT
      LAYER M4 ;
        RECT  0 26.688 0.084 26.712 ;
    END
  END t_o[13]
  PIN t_o[140]
    DIRECTION OUTPUT ;
    USE SIGNAL ;
    PORT
      LAYER M4 ;
        RECT  0 257.616 0.084 257.64 ;
    END
  END t_o[140]
  PIN t_o[141]
    DIRECTION OUTPUT ;
    USE SIGNAL ;
    PORT
      LAYER M4 ;
        RECT  0 259.44 0.084 259.464 ;
    END
  END t_o[141]
  PIN t_o[142]
    DIRECTION OUTPUT ;
    USE SIGNAL ;
    PORT
      LAYER M4 ;
        RECT  0 261.264 0.084 261.288 ;
    END
  END t_o[142]
  PIN t_o[143]
    DIRECTION OUTPUT ;
    USE SIGNAL ;
    PORT
      LAYER M4 ;
        RECT  0 263.088 0.084 263.112 ;
    END
  END t_o[143]
  PIN t_o[144]
    DIRECTION OUTPUT ;
    USE SIGNAL ;
    PORT
      LAYER M4 ;
        RECT  0 264.912 0.084 264.936 ;
    END
  END t_o[144]
  PIN t_o[145]
    DIRECTION OUTPUT ;
    USE SIGNAL ;
    PORT
      LAYER M4 ;
        RECT  0 266.688 0.084 266.712 ;
    END
  END t_o[145]
  PIN t_o[146]
    DIRECTION OUTPUT ;
    USE SIGNAL ;
    PORT
      LAYER M4 ;
        RECT  0 268.512 0.084 268.536 ;
    END
  END t_o[146]
  PIN t_o[147]
    DIRECTION OUTPUT ;
    USE SIGNAL ;
    PORT
      LAYER M4 ;
        RECT  0 270.336 0.084 270.36 ;
    END
  END t_o[147]
  PIN t_o[148]
    DIRECTION OUTPUT ;
    USE SIGNAL ;
    PORT
      LAYER M4 ;
        RECT  0 272.16 0.084 272.184 ;
    END
  END t_o[148]
  PIN t_o[149]
    DIRECTION OUTPUT ;
    USE SIGNAL ;
    PORT
      LAYER M4 ;
        RECT  0 273.984 0.084 274.008 ;
    END
  END t_o[149]
  PIN t_o[14]
    DIRECTION OUTPUT ;
    USE SIGNAL ;
    PORT
      LAYER M4 ;
        RECT  0 28.512 0.084 28.536 ;
    END
  END t_o[14]
  PIN t_o[150]
    DIRECTION OUTPUT ;
    USE SIGNAL ;
    PORT
      LAYER M4 ;
        RECT  0 275.808 0.084 275.832 ;
    END
  END t_o[150]
  PIN t_o[151]
    DIRECTION OUTPUT ;
    USE SIGNAL ;
    PORT
      LAYER M4 ;
        RECT  0 277.632 0.084 277.656 ;
    END
  END t_o[151]
  PIN t_o[152]
    DIRECTION OUTPUT ;
    USE SIGNAL ;
    PORT
      LAYER M4 ;
        RECT  0 279.456 0.084 279.48 ;
    END
  END t_o[152]
  PIN t_o[153]
    DIRECTION OUTPUT ;
    USE SIGNAL ;
    PORT
      LAYER M4 ;
        RECT  0 281.28 0.084 281.304 ;
    END
  END t_o[153]
  PIN t_o[154]
    DIRECTION OUTPUT ;
    USE SIGNAL ;
    PORT
      LAYER M4 ;
        RECT  0 283.056 0.084 283.08 ;
    END
  END t_o[154]
  PIN t_o[155]
    DIRECTION OUTPUT ;
    USE SIGNAL ;
    PORT
      LAYER M4 ;
        RECT  0 284.88 0.084 284.904 ;
    END
  END t_o[155]
  PIN t_o[156]
    DIRECTION OUTPUT ;
    USE SIGNAL ;
    PORT
      LAYER M4 ;
        RECT  0 286.704 0.084 286.728 ;
    END
  END t_o[156]
  PIN t_o[157]
    DIRECTION OUTPUT ;
    USE SIGNAL ;
    PORT
      LAYER M4 ;
        RECT  0 288.528 0.084 288.552 ;
    END
  END t_o[157]
  PIN t_o[158]
    DIRECTION OUTPUT ;
    USE SIGNAL ;
    PORT
      LAYER M4 ;
        RECT  0 290.352 0.084 290.376 ;
    END
  END t_o[158]
  PIN t_o[159]
    DIRECTION OUTPUT ;
    USE SIGNAL ;
    PORT
      LAYER M4 ;
        RECT  0 292.176 0.084 292.2 ;
    END
  END t_o[159]
  PIN t_o[15]
    DIRECTION OUTPUT ;
    USE SIGNAL ;
    PORT
      LAYER M4 ;
        RECT  0 30.336 0.084 30.36 ;
    END
  END t_o[15]
  PIN t_o[160]
    DIRECTION OUTPUT ;
    USE SIGNAL ;
    PORT
      LAYER M4 ;
        RECT  0 294 0.084 294.024 ;
    END
  END t_o[160]
  PIN t_o[161]
    DIRECTION OUTPUT ;
    USE SIGNAL ;
    PORT
      LAYER M4 ;
        RECT  0 295.824 0.084 295.848 ;
    END
  END t_o[161]
  PIN t_o[162]
    DIRECTION OUTPUT ;
    USE SIGNAL ;
    PORT
      LAYER M4 ;
        RECT  0 297.6 0.084 297.624 ;
    END
  END t_o[162]
  PIN t_o[163]
    DIRECTION OUTPUT ;
    USE SIGNAL ;
    PORT
      LAYER M4 ;
        RECT  0 299.424 0.084 299.448 ;
    END
  END t_o[163]
  PIN t_o[164]
    DIRECTION OUTPUT ;
    USE SIGNAL ;
    PORT
      LAYER M4 ;
        RECT  0 301.248 0.084 301.272 ;
    END
  END t_o[164]
  PIN t_o[165]
    DIRECTION OUTPUT ;
    USE SIGNAL ;
    PORT
      LAYER M4 ;
        RECT  0 303.072 0.084 303.096 ;
    END
  END t_o[165]
  PIN t_o[166]
    DIRECTION OUTPUT ;
    USE SIGNAL ;
    PORT
      LAYER M4 ;
        RECT  0 304.896 0.084 304.92 ;
    END
  END t_o[166]
  PIN t_o[167]
    DIRECTION OUTPUT ;
    USE SIGNAL ;
    PORT
      LAYER M4 ;
        RECT  0 306.72 0.084 306.744 ;
    END
  END t_o[167]
  PIN t_o[168]
    DIRECTION OUTPUT ;
    USE SIGNAL ;
    PORT
      LAYER M4 ;
        RECT  0 308.544 0.084 308.568 ;
    END
  END t_o[168]
  PIN t_o[169]
    DIRECTION OUTPUT ;
    USE SIGNAL ;
    PORT
      LAYER M4 ;
        RECT  0 310.368 0.084 310.392 ;
    END
  END t_o[169]
  PIN t_o[16]
    DIRECTION OUTPUT ;
    USE SIGNAL ;
    PORT
      LAYER M4 ;
        RECT  0 32.16 0.084 32.184 ;
    END
  END t_o[16]
  PIN t_o[170]
    DIRECTION OUTPUT ;
    USE SIGNAL ;
    PORT
      LAYER M4 ;
        RECT  0 312.192 0.084 312.216 ;
    END
  END t_o[170]
  PIN t_o[171]
    DIRECTION OUTPUT ;
    USE SIGNAL ;
    PORT
      LAYER M4 ;
        RECT  0 313.968 0.084 313.992 ;
    END
  END t_o[171]
  PIN t_o[172]
    DIRECTION OUTPUT ;
    USE SIGNAL ;
    PORT
      LAYER M4 ;
        RECT  0 315.792 0.084 315.816 ;
    END
  END t_o[172]
  PIN t_o[173]
    DIRECTION OUTPUT ;
    USE SIGNAL ;
    PORT
      LAYER M4 ;
        RECT  0 317.616 0.084 317.64 ;
    END
  END t_o[173]
  PIN t_o[174]
    DIRECTION OUTPUT ;
    USE SIGNAL ;
    PORT
      LAYER M4 ;
        RECT  0 319.44 0.084 319.464 ;
    END
  END t_o[174]
  PIN t_o[175]
    DIRECTION OUTPUT ;
    USE SIGNAL ;
    PORT
      LAYER M4 ;
        RECT  0 321.264 0.084 321.288 ;
    END
  END t_o[175]
  PIN t_o[176]
    DIRECTION OUTPUT ;
    USE SIGNAL ;
    PORT
      LAYER M4 ;
        RECT  0 323.088 0.084 323.112 ;
    END
  END t_o[176]
  PIN t_o[177]
    DIRECTION OUTPUT ;
    USE SIGNAL ;
    PORT
      LAYER M4 ;
        RECT  0 324.912 0.084 324.936 ;
    END
  END t_o[177]
  PIN t_o[178]
    DIRECTION OUTPUT ;
    USE SIGNAL ;
    PORT
      LAYER M4 ;
        RECT  0 326.736 0.084 326.76 ;
    END
  END t_o[178]
  PIN t_o[179]
    DIRECTION OUTPUT ;
    USE SIGNAL ;
    PORT
      LAYER M4 ;
        RECT  0 328.512 0.084 328.536 ;
    END
  END t_o[179]
  PIN t_o[17]
    DIRECTION OUTPUT ;
    USE SIGNAL ;
    PORT
      LAYER M4 ;
        RECT  0 33.984 0.084 34.008 ;
    END
  END t_o[17]
  PIN t_o[180]
    DIRECTION OUTPUT ;
    USE SIGNAL ;
    PORT
      LAYER M4 ;
        RECT  0 330.336 0.084 330.36 ;
    END
  END t_o[180]
  PIN t_o[181]
    DIRECTION OUTPUT ;
    USE SIGNAL ;
    PORT
      LAYER M4 ;
        RECT  0 332.16 0.084 332.184 ;
    END
  END t_o[181]
  PIN t_o[182]
    DIRECTION OUTPUT ;
    USE SIGNAL ;
    PORT
      LAYER M4 ;
        RECT  0 333.984 0.084 334.008 ;
    END
  END t_o[182]
  PIN t_o[183]
    DIRECTION OUTPUT ;
    USE SIGNAL ;
    PORT
      LAYER M4 ;
        RECT  0 335.808 0.084 335.832 ;
    END
  END t_o[183]
  PIN t_o[184]
    DIRECTION OUTPUT ;
    USE SIGNAL ;
    PORT
      LAYER M4 ;
        RECT  0 337.632 0.084 337.656 ;
    END
  END t_o[184]
  PIN t_o[185]
    DIRECTION OUTPUT ;
    USE SIGNAL ;
    PORT
      LAYER M4 ;
        RECT  0 339.456 0.084 339.48 ;
    END
  END t_o[185]
  PIN t_o[186]
    DIRECTION OUTPUT ;
    USE SIGNAL ;
    PORT
      LAYER M4 ;
        RECT  0 341.28 0.084 341.304 ;
    END
  END t_o[186]
  PIN t_o[187]
    DIRECTION OUTPUT ;
    USE SIGNAL ;
    PORT
      LAYER M4 ;
        RECT  0 343.104 0.084 343.128 ;
    END
  END t_o[187]
  PIN t_o[188]
    DIRECTION OUTPUT ;
    USE SIGNAL ;
    PORT
      LAYER M4 ;
        RECT  0 344.88 0.084 344.904 ;
    END
  END t_o[188]
  PIN t_o[189]
    DIRECTION OUTPUT ;
    USE SIGNAL ;
    PORT
      LAYER M4 ;
        RECT  0 346.704 0.084 346.728 ;
    END
  END t_o[189]
  PIN t_o[18]
    DIRECTION OUTPUT ;
    USE SIGNAL ;
    PORT
      LAYER M4 ;
        RECT  0 35.808 0.084 35.832 ;
    END
  END t_o[18]
  PIN t_o[190]
    DIRECTION OUTPUT ;
    USE SIGNAL ;
    PORT
      LAYER M4 ;
        RECT  0 348.528 0.084 348.552 ;
    END
  END t_o[190]
  PIN t_o[191]
    DIRECTION OUTPUT ;
    USE SIGNAL ;
    PORT
      LAYER M4 ;
        RECT  0 350.352 0.084 350.376 ;
    END
  END t_o[191]
  PIN t_o[192]
    DIRECTION OUTPUT ;
    USE SIGNAL ;
    PORT
      LAYER M4 ;
        RECT  0 352.176 0.084 352.2 ;
    END
  END t_o[192]
  PIN t_o[193]
    DIRECTION OUTPUT ;
    USE SIGNAL ;
    PORT
      LAYER M4 ;
        RECT  0 354 0.084 354.024 ;
    END
  END t_o[193]
  PIN t_o[194]
    DIRECTION OUTPUT ;
    USE SIGNAL ;
    PORT
      LAYER M4 ;
        RECT  0 355.824 0.084 355.848 ;
    END
  END t_o[194]
  PIN t_o[195]
    DIRECTION OUTPUT ;
    USE SIGNAL ;
    PORT
      LAYER M4 ;
        RECT  0 357.648 0.084 357.672 ;
    END
  END t_o[195]
  PIN t_o[196]
    DIRECTION OUTPUT ;
    USE SIGNAL ;
    PORT
      LAYER M4 ;
        RECT  0 359.424 0.084 359.448 ;
    END
  END t_o[196]
  PIN t_o[197]
    DIRECTION OUTPUT ;
    USE SIGNAL ;
    PORT
      LAYER M4 ;
        RECT  0 361.248 0.084 361.272 ;
    END
  END t_o[197]
  PIN t_o[198]
    DIRECTION OUTPUT ;
    USE SIGNAL ;
    PORT
      LAYER M4 ;
        RECT  0 363.072 0.084 363.096 ;
    END
  END t_o[198]
  PIN t_o[199]
    DIRECTION OUTPUT ;
    USE SIGNAL ;
    PORT
      LAYER M4 ;
        RECT  0 364.896 0.084 364.92 ;
    END
  END t_o[199]
  PIN t_o[19]
    DIRECTION OUTPUT ;
    USE SIGNAL ;
    PORT
      LAYER M4 ;
        RECT  0 37.584 0.084 37.608 ;
    END
  END t_o[19]
  PIN t_o[1]
    DIRECTION OUTPUT ;
    USE SIGNAL ;
    PORT
      LAYER M4 ;
        RECT  0 4.896 0.084 4.92 ;
    END
  END t_o[1]
  PIN t_o[200]
    DIRECTION OUTPUT ;
    USE SIGNAL ;
    PORT
      LAYER M4 ;
        RECT  0 366.72 0.084 366.744 ;
    END
  END t_o[200]
  PIN t_o[201]
    DIRECTION OUTPUT ;
    USE SIGNAL ;
    PORT
      LAYER M4 ;
        RECT  0 368.544 0.084 368.568 ;
    END
  END t_o[201]
  PIN t_o[202]
    DIRECTION OUTPUT ;
    USE SIGNAL ;
    PORT
      LAYER M4 ;
        RECT  0 370.368 0.084 370.392 ;
    END
  END t_o[202]
  PIN t_o[203]
    DIRECTION OUTPUT ;
    USE SIGNAL ;
    PORT
      LAYER M4 ;
        RECT  0 372.192 0.084 372.216 ;
    END
  END t_o[203]
  PIN t_o[204]
    DIRECTION OUTPUT ;
    USE SIGNAL ;
    PORT
      LAYER M4 ;
        RECT  0 373.968 0.084 373.992 ;
    END
  END t_o[204]
  PIN t_o[205]
    DIRECTION OUTPUT ;
    USE SIGNAL ;
    PORT
      LAYER M4 ;
        RECT  0 375.792 0.084 375.816 ;
    END
  END t_o[205]
  PIN t_o[206]
    DIRECTION OUTPUT ;
    USE SIGNAL ;
    PORT
      LAYER M4 ;
        RECT  0 377.616 0.084 377.64 ;
    END
  END t_o[206]
  PIN t_o[207]
    DIRECTION OUTPUT ;
    USE SIGNAL ;
    PORT
      LAYER M4 ;
        RECT  0 379.44 0.084 379.464 ;
    END
  END t_o[207]
  PIN t_o[208]
    DIRECTION OUTPUT ;
    USE SIGNAL ;
    PORT
      LAYER M4 ;
        RECT  0 381.264 0.084 381.288 ;
    END
  END t_o[208]
  PIN t_o[209]
    DIRECTION OUTPUT ;
    USE SIGNAL ;
    PORT
      LAYER M4 ;
        RECT  0 383.088 0.084 383.112 ;
    END
  END t_o[209]
  PIN t_o[20]
    DIRECTION OUTPUT ;
    USE SIGNAL ;
    PORT
      LAYER M4 ;
        RECT  0 39.408 0.084 39.432 ;
    END
  END t_o[20]
  PIN t_o[210]
    DIRECTION OUTPUT ;
    USE SIGNAL ;
    PORT
      LAYER M4 ;
        RECT  0 384.912 0.084 384.936 ;
    END
  END t_o[210]
  PIN t_o[211]
    DIRECTION OUTPUT ;
    USE SIGNAL ;
    PORT
      LAYER M4 ;
        RECT  0 386.736 0.084 386.76 ;
    END
  END t_o[211]
  PIN t_o[212]
    DIRECTION OUTPUT ;
    USE SIGNAL ;
    PORT
      LAYER M4 ;
        RECT  0 388.56 0.084 388.584 ;
    END
  END t_o[212]
  PIN t_o[213]
    DIRECTION OUTPUT ;
    USE SIGNAL ;
    PORT
      LAYER M4 ;
        RECT  0 390.336 0.084 390.36 ;
    END
  END t_o[213]
  PIN t_o[214]
    DIRECTION OUTPUT ;
    USE SIGNAL ;
    PORT
      LAYER M4 ;
        RECT  0 392.16 0.084 392.184 ;
    END
  END t_o[214]
  PIN t_o[215]
    DIRECTION OUTPUT ;
    USE SIGNAL ;
    PORT
      LAYER M4 ;
        RECT  0 393.984 0.084 394.008 ;
    END
  END t_o[215]
  PIN t_o[216]
    DIRECTION OUTPUT ;
    USE SIGNAL ;
    PORT
      LAYER M4 ;
        RECT  0 395.808 0.084 395.832 ;
    END
  END t_o[216]
  PIN t_o[217]
    DIRECTION OUTPUT ;
    USE SIGNAL ;
    PORT
      LAYER M4 ;
        RECT  0 397.632 0.084 397.656 ;
    END
  END t_o[217]
  PIN t_o[218]
    DIRECTION OUTPUT ;
    USE SIGNAL ;
    PORT
      LAYER M4 ;
        RECT  0 399.456 0.084 399.48 ;
    END
  END t_o[218]
  PIN t_o[219]
    DIRECTION OUTPUT ;
    USE SIGNAL ;
    PORT
      LAYER M4 ;
        RECT  0 401.28 0.084 401.304 ;
    END
  END t_o[219]
  PIN t_o[21]
    DIRECTION OUTPUT ;
    USE SIGNAL ;
    PORT
      LAYER M4 ;
        RECT  0 41.232 0.084 41.256 ;
    END
  END t_o[21]
  PIN t_o[220]
    DIRECTION OUTPUT ;
    USE SIGNAL ;
    PORT
      LAYER M4 ;
        RECT  0 403.104 0.084 403.128 ;
    END
  END t_o[220]
  PIN t_o[221]
    DIRECTION OUTPUT ;
    USE SIGNAL ;
    PORT
      LAYER M4 ;
        RECT  0 404.88 0.084 404.904 ;
    END
  END t_o[221]
  PIN t_o[222]
    DIRECTION OUTPUT ;
    USE SIGNAL ;
    PORT
      LAYER M4 ;
        RECT  0 406.704 0.084 406.728 ;
    END
  END t_o[222]
  PIN t_o[223]
    DIRECTION OUTPUT ;
    USE SIGNAL ;
    PORT
      LAYER M4 ;
        RECT  0 408.528 0.084 408.552 ;
    END
  END t_o[223]
  PIN t_o[224]
    DIRECTION OUTPUT ;
    USE SIGNAL ;
    PORT
      LAYER M4 ;
        RECT  0 410.352 0.084 410.376 ;
    END
  END t_o[224]
  PIN t_o[225]
    DIRECTION OUTPUT ;
    USE SIGNAL ;
    PORT
      LAYER M4 ;
        RECT  0 412.176 0.084 412.2 ;
    END
  END t_o[225]
  PIN t_o[226]
    DIRECTION OUTPUT ;
    USE SIGNAL ;
    PORT
      LAYER M4 ;
        RECT  0 414 0.084 414.024 ;
    END
  END t_o[226]
  PIN t_o[227]
    DIRECTION OUTPUT ;
    USE SIGNAL ;
    PORT
      LAYER M4 ;
        RECT  0 415.824 0.084 415.848 ;
    END
  END t_o[227]
  PIN t_o[228]
    DIRECTION OUTPUT ;
    USE SIGNAL ;
    PORT
      LAYER M4 ;
        RECT  0 417.648 0.084 417.672 ;
    END
  END t_o[228]
  PIN t_o[229]
    DIRECTION OUTPUT ;
    USE SIGNAL ;
    PORT
      LAYER M4 ;
        RECT  0 419.472 0.084 419.496 ;
    END
  END t_o[229]
  PIN t_o[22]
    DIRECTION OUTPUT ;
    USE SIGNAL ;
    PORT
      LAYER M4 ;
        RECT  0 43.056 0.084 43.08 ;
    END
  END t_o[22]
  PIN t_o[230]
    DIRECTION OUTPUT ;
    USE SIGNAL ;
    PORT
      LAYER M4 ;
        RECT  0 421.248 0.084 421.272 ;
    END
  END t_o[230]
  PIN t_o[231]
    DIRECTION OUTPUT ;
    USE SIGNAL ;
    PORT
      LAYER M4 ;
        RECT  0 423.072 0.084 423.096 ;
    END
  END t_o[231]
  PIN t_o[232]
    DIRECTION OUTPUT ;
    USE SIGNAL ;
    PORT
      LAYER M4 ;
        RECT  0 424.896 0.084 424.92 ;
    END
  END t_o[232]
  PIN t_o[233]
    DIRECTION OUTPUT ;
    USE SIGNAL ;
    PORT
      LAYER M4 ;
        RECT  0 426.72 0.084 426.744 ;
    END
  END t_o[233]
  PIN t_o[234]
    DIRECTION OUTPUT ;
    USE SIGNAL ;
    PORT
      LAYER M4 ;
        RECT  0 428.544 0.084 428.568 ;
    END
  END t_o[234]
  PIN t_o[235]
    DIRECTION OUTPUT ;
    USE SIGNAL ;
    PORT
      LAYER M4 ;
        RECT  0 430.368 0.084 430.392 ;
    END
  END t_o[235]
  PIN t_o[236]
    DIRECTION OUTPUT ;
    USE SIGNAL ;
    PORT
      LAYER M4 ;
        RECT  0 432.192 0.084 432.216 ;
    END
  END t_o[236]
  PIN t_o[237]
    DIRECTION OUTPUT ;
    USE SIGNAL ;
    PORT
      LAYER M4 ;
        RECT  0 434.016 0.084 434.04 ;
    END
  END t_o[237]
  PIN t_o[238]
    DIRECTION OUTPUT ;
    USE SIGNAL ;
    PORT
      LAYER M4 ;
        RECT  0 435.792 0.084 435.816 ;
    END
  END t_o[238]
  PIN t_o[239]
    DIRECTION OUTPUT ;
    USE SIGNAL ;
    PORT
      LAYER M4 ;
        RECT  0 437.616 0.084 437.64 ;
    END
  END t_o[239]
  PIN t_o[23]
    DIRECTION OUTPUT ;
    USE SIGNAL ;
    PORT
      LAYER M4 ;
        RECT  0 44.88 0.084 44.904 ;
    END
  END t_o[23]
  PIN t_o[240]
    DIRECTION OUTPUT ;
    USE SIGNAL ;
    PORT
      LAYER M4 ;
        RECT  0 439.44 0.084 439.464 ;
    END
  END t_o[240]
  PIN t_o[241]
    DIRECTION OUTPUT ;
    USE SIGNAL ;
    PORT
      LAYER M4 ;
        RECT  0 441.264 0.084 441.288 ;
    END
  END t_o[241]
  PIN t_o[242]
    DIRECTION OUTPUT ;
    USE SIGNAL ;
    PORT
      LAYER M4 ;
        RECT  0 443.088 0.084 443.112 ;
    END
  END t_o[242]
  PIN t_o[243]
    DIRECTION OUTPUT ;
    USE SIGNAL ;
    PORT
      LAYER M4 ;
        RECT  0 444.912 0.084 444.936 ;
    END
  END t_o[243]
  PIN t_o[244]
    DIRECTION OUTPUT ;
    USE SIGNAL ;
    PORT
      LAYER M4 ;
        RECT  0 446.736 0.084 446.76 ;
    END
  END t_o[244]
  PIN t_o[245]
    DIRECTION OUTPUT ;
    USE SIGNAL ;
    PORT
      LAYER M4 ;
        RECT  0 448.56 0.084 448.584 ;
    END
  END t_o[245]
  PIN t_o[246]
    DIRECTION OUTPUT ;
    USE SIGNAL ;
    PORT
      LAYER M4 ;
        RECT  0 450.384 0.084 450.408 ;
    END
  END t_o[246]
  PIN t_o[247]
    DIRECTION OUTPUT ;
    USE SIGNAL ;
    PORT
      LAYER M4 ;
        RECT  0 452.16 0.084 452.184 ;
    END
  END t_o[247]
  PIN t_o[248]
    DIRECTION OUTPUT ;
    USE SIGNAL ;
    PORT
      LAYER M4 ;
        RECT  0 453.984 0.084 454.008 ;
    END
  END t_o[248]
  PIN t_o[249]
    DIRECTION OUTPUT ;
    USE SIGNAL ;
    PORT
      LAYER M4 ;
        RECT  0 455.808 0.084 455.832 ;
    END
  END t_o[249]
  PIN t_o[24]
    DIRECTION OUTPUT ;
    USE SIGNAL ;
    PORT
      LAYER M4 ;
        RECT  0 46.704 0.084 46.728 ;
    END
  END t_o[24]
  PIN t_o[250]
    DIRECTION OUTPUT ;
    USE SIGNAL ;
    PORT
      LAYER M4 ;
        RECT  0 457.632 0.084 457.656 ;
    END
  END t_o[250]
  PIN t_o[251]
    DIRECTION OUTPUT ;
    USE SIGNAL ;
    PORT
      LAYER M4 ;
        RECT  0 459.456 0.084 459.48 ;
    END
  END t_o[251]
  PIN t_o[252]
    DIRECTION OUTPUT ;
    USE SIGNAL ;
    PORT
      LAYER M4 ;
        RECT  0 461.28 0.084 461.304 ;
    END
  END t_o[252]
  PIN t_o[253]
    DIRECTION OUTPUT ;
    USE SIGNAL ;
    PORT
      LAYER M4 ;
        RECT  0 463.104 0.084 463.128 ;
    END
  END t_o[253]
  PIN t_o[254]
    DIRECTION OUTPUT ;
    USE SIGNAL ;
    PORT
      LAYER M4 ;
        RECT  0 464.928 0.084 464.952 ;
    END
  END t_o[254]
  PIN t_o[255]
    DIRECTION OUTPUT ;
    USE SIGNAL ;
    PORT
      LAYER M4 ;
        RECT  0 466.704 0.084 466.728 ;
    END
  END t_o[255]
  PIN t_o[256]
    DIRECTION OUTPUT ;
    USE SIGNAL ;
    PORT
      LAYER M4 ;
        RECT  0 468.528 0.084 468.552 ;
    END
  END t_o[256]
  PIN t_o[257]
    DIRECTION OUTPUT ;
    USE SIGNAL ;
    PORT
      LAYER M4 ;
        RECT  0 470.352 0.084 470.376 ;
    END
  END t_o[257]
  PIN t_o[258]
    DIRECTION OUTPUT ;
    USE SIGNAL ;
    PORT
      LAYER M4 ;
        RECT  0 472.176 0.084 472.2 ;
    END
  END t_o[258]
  PIN t_o[259]
    DIRECTION OUTPUT ;
    USE SIGNAL ;
    PORT
      LAYER M4 ;
        RECT  0 474 0.084 474.024 ;
    END
  END t_o[259]
  PIN t_o[25]
    DIRECTION OUTPUT ;
    USE SIGNAL ;
    PORT
      LAYER M4 ;
        RECT  0 48.528 0.084 48.552 ;
    END
  END t_o[25]
  PIN t_o[260]
    DIRECTION OUTPUT ;
    USE SIGNAL ;
    PORT
      LAYER M4 ;
        RECT  0 475.824 0.084 475.848 ;
    END
  END t_o[260]
  PIN t_o[261]
    DIRECTION OUTPUT ;
    USE SIGNAL ;
    PORT
      LAYER M4 ;
        RECT  0 477.648 0.084 477.672 ;
    END
  END t_o[261]
  PIN t_o[262]
    DIRECTION OUTPUT ;
    USE SIGNAL ;
    PORT
      LAYER M4 ;
        RECT  0 479.472 0.084 479.496 ;
    END
  END t_o[262]
  PIN t_o[263]
    DIRECTION OUTPUT ;
    USE SIGNAL ;
    PORT
      LAYER M4 ;
        RECT  0 481.248 0.084 481.272 ;
    END
  END t_o[263]
  PIN t_o[264]
    DIRECTION OUTPUT ;
    USE SIGNAL ;
    PORT
      LAYER M4 ;
        RECT  0 483.072 0.084 483.096 ;
    END
  END t_o[264]
  PIN t_o[265]
    DIRECTION OUTPUT ;
    USE SIGNAL ;
    PORT
      LAYER M4 ;
        RECT  0 484.896 0.084 484.92 ;
    END
  END t_o[265]
  PIN t_o[266]
    DIRECTION OUTPUT ;
    USE SIGNAL ;
    PORT
      LAYER M4 ;
        RECT  0 486.72 0.084 486.744 ;
    END
  END t_o[266]
  PIN t_o[267]
    DIRECTION OUTPUT ;
    USE SIGNAL ;
    PORT
      LAYER M4 ;
        RECT  0 488.544 0.084 488.568 ;
    END
  END t_o[267]
  PIN t_o[268]
    DIRECTION OUTPUT ;
    USE SIGNAL ;
    PORT
      LAYER M4 ;
        RECT  0 490.368 0.084 490.392 ;
    END
  END t_o[268]
  PIN t_o[269]
    DIRECTION OUTPUT ;
    USE SIGNAL ;
    PORT
      LAYER M4 ;
        RECT  0 492.192 0.084 492.216 ;
    END
  END t_o[269]
  PIN t_o[26]
    DIRECTION OUTPUT ;
    USE SIGNAL ;
    PORT
      LAYER M4 ;
        RECT  0 50.352 0.084 50.376 ;
    END
  END t_o[26]
  PIN t_o[270]
    DIRECTION OUTPUT ;
    USE SIGNAL ;
    PORT
      LAYER M4 ;
        RECT  0 494.016 0.084 494.04 ;
    END
  END t_o[270]
  PIN t_o[271]
    DIRECTION OUTPUT ;
    USE SIGNAL ;
    PORT
      LAYER M4 ;
        RECT  0 495.84 0.084 495.864 ;
    END
  END t_o[271]
  PIN t_o[272]
    DIRECTION OUTPUT ;
    USE SIGNAL ;
    PORT
      LAYER M4 ;
        RECT  0 497.616 0.084 497.64 ;
    END
  END t_o[272]
  PIN t_o[273]
    DIRECTION OUTPUT ;
    USE SIGNAL ;
    PORT
      LAYER M4 ;
        RECT  0 499.44 0.084 499.464 ;
    END
  END t_o[273]
  PIN t_o[274]
    DIRECTION OUTPUT ;
    USE SIGNAL ;
    PORT
      LAYER M4 ;
        RECT  0 501.264 0.084 501.288 ;
    END
  END t_o[274]
  PIN t_o[275]
    DIRECTION OUTPUT ;
    USE SIGNAL ;
    PORT
      LAYER M4 ;
        RECT  0 503.088 0.084 503.112 ;
    END
  END t_o[275]
  PIN t_o[276]
    DIRECTION OUTPUT ;
    USE SIGNAL ;
    PORT
      LAYER M4 ;
        RECT  0 504.912 0.084 504.936 ;
    END
  END t_o[276]
  PIN t_o[277]
    DIRECTION OUTPUT ;
    USE SIGNAL ;
    PORT
      LAYER M4 ;
        RECT  0 506.736 0.084 506.76 ;
    END
  END t_o[277]
  PIN t_o[278]
    DIRECTION OUTPUT ;
    USE SIGNAL ;
    PORT
      LAYER M4 ;
        RECT  0 508.56 0.084 508.584 ;
    END
  END t_o[278]
  PIN t_o[279]
    DIRECTION OUTPUT ;
    USE SIGNAL ;
    PORT
      LAYER M4 ;
        RECT  0 510.384 0.084 510.408 ;
    END
  END t_o[279]
  PIN t_o[27]
    DIRECTION OUTPUT ;
    USE SIGNAL ;
    PORT
      LAYER M4 ;
        RECT  0 52.128 0.084 52.152 ;
    END
  END t_o[27]
  PIN t_o[280]
    DIRECTION OUTPUT ;
    USE SIGNAL ;
    PORT
      LAYER M4 ;
        RECT  0 512.16 0.084 512.184 ;
    END
  END t_o[280]
  PIN t_o[281]
    DIRECTION OUTPUT ;
    USE SIGNAL ;
    PORT
      LAYER M4 ;
        RECT  0 513.984 0.084 514.008 ;
    END
  END t_o[281]
  PIN t_o[282]
    DIRECTION OUTPUT ;
    USE SIGNAL ;
    PORT
      LAYER M4 ;
        RECT  0 515.808 0.084 515.832 ;
    END
  END t_o[282]
  PIN t_o[283]
    DIRECTION OUTPUT ;
    USE SIGNAL ;
    PORT
      LAYER M4 ;
        RECT  0 517.632 0.084 517.656 ;
    END
  END t_o[283]
  PIN t_o[284]
    DIRECTION OUTPUT ;
    USE SIGNAL ;
    PORT
      LAYER M4 ;
        RECT  0 519.456 0.084 519.48 ;
    END
  END t_o[284]
  PIN t_o[285]
    DIRECTION OUTPUT ;
    USE SIGNAL ;
    PORT
      LAYER M4 ;
        RECT  0 521.28 0.084 521.304 ;
    END
  END t_o[285]
  PIN t_o[286]
    DIRECTION OUTPUT ;
    USE SIGNAL ;
    PORT
      LAYER M4 ;
        RECT  0 523.104 0.084 523.128 ;
    END
  END t_o[286]
  PIN t_o[287]
    DIRECTION OUTPUT ;
    USE SIGNAL ;
    PORT
      LAYER M4 ;
        RECT  0 524.928 0.084 524.952 ;
    END
  END t_o[287]
  PIN t_o[288]
    DIRECTION OUTPUT ;
    USE SIGNAL ;
    PORT
      LAYER M4 ;
        RECT  0 526.752 0.084 526.776 ;
    END
  END t_o[288]
  PIN t_o[289]
    DIRECTION OUTPUT ;
    USE SIGNAL ;
    PORT
      LAYER M4 ;
        RECT  0 528.528 0.084 528.552 ;
    END
  END t_o[289]
  PIN t_o[28]
    DIRECTION OUTPUT ;
    USE SIGNAL ;
    PORT
      LAYER M4 ;
        RECT  0 53.952 0.084 53.976 ;
    END
  END t_o[28]
  PIN t_o[290]
    DIRECTION OUTPUT ;
    USE SIGNAL ;
    PORT
      LAYER M4 ;
        RECT  0 530.352 0.084 530.376 ;
    END
  END t_o[290]
  PIN t_o[291]
    DIRECTION OUTPUT ;
    USE SIGNAL ;
    PORT
      LAYER M4 ;
        RECT  0 532.176 0.084 532.2 ;
    END
  END t_o[291]
  PIN t_o[292]
    DIRECTION OUTPUT ;
    USE SIGNAL ;
    PORT
      LAYER M4 ;
        RECT  0 534 0.084 534.024 ;
    END
  END t_o[292]
  PIN t_o[293]
    DIRECTION OUTPUT ;
    USE SIGNAL ;
    PORT
      LAYER M4 ;
        RECT  0 535.824 0.084 535.848 ;
    END
  END t_o[293]
  PIN t_o[294]
    DIRECTION OUTPUT ;
    USE SIGNAL ;
    PORT
      LAYER M4 ;
        RECT  0 537.648 0.084 537.672 ;
    END
  END t_o[294]
  PIN t_o[295]
    DIRECTION OUTPUT ;
    USE SIGNAL ;
    PORT
      LAYER M4 ;
        RECT  0 539.472 0.084 539.496 ;
    END
  END t_o[295]
  PIN t_o[296]
    DIRECTION OUTPUT ;
    USE SIGNAL ;
    PORT
      LAYER M4 ;
        RECT  0 541.296 0.084 541.32 ;
    END
  END t_o[296]
  PIN t_o[297]
    DIRECTION OUTPUT ;
    USE SIGNAL ;
    PORT
      LAYER M4 ;
        RECT  0 543.072 0.084 543.096 ;
    END
  END t_o[297]
  PIN t_o[298]
    DIRECTION OUTPUT ;
    USE SIGNAL ;
    PORT
      LAYER M4 ;
        RECT  0 544.896 0.084 544.92 ;
    END
  END t_o[298]
  PIN t_o[299]
    DIRECTION OUTPUT ;
    USE SIGNAL ;
    PORT
      LAYER M4 ;
        RECT  0 546.72 0.084 546.744 ;
    END
  END t_o[299]
  PIN t_o[29]
    DIRECTION OUTPUT ;
    USE SIGNAL ;
    PORT
      LAYER M4 ;
        RECT  0 55.776 0.084 55.8 ;
    END
  END t_o[29]
  PIN t_o[2]
    DIRECTION OUTPUT ;
    USE SIGNAL ;
    PORT
      LAYER M4 ;
        RECT  0 6.672 0.084 6.696 ;
    END
  END t_o[2]
  PIN t_o[300]
    DIRECTION OUTPUT ;
    USE SIGNAL ;
    PORT
      LAYER M4 ;
        RECT  0 548.544 0.084 548.568 ;
    END
  END t_o[300]
  PIN t_o[301]
    DIRECTION OUTPUT ;
    USE SIGNAL ;
    PORT
      LAYER M4 ;
        RECT  0 550.368 0.084 550.392 ;
    END
  END t_o[301]
  PIN t_o[302]
    DIRECTION OUTPUT ;
    USE SIGNAL ;
    PORT
      LAYER M4 ;
        RECT  0 552.192 0.084 552.216 ;
    END
  END t_o[302]
  PIN t_o[303]
    DIRECTION OUTPUT ;
    USE SIGNAL ;
    PORT
      LAYER M4 ;
        RECT  0 554.016 0.084 554.04 ;
    END
  END t_o[303]
  PIN t_o[304]
    DIRECTION OUTPUT ;
    USE SIGNAL ;
    PORT
      LAYER M4 ;
        RECT  0 555.84 0.084 555.864 ;
    END
  END t_o[304]
  PIN t_o[305]
    DIRECTION OUTPUT ;
    USE SIGNAL ;
    PORT
      LAYER M4 ;
        RECT  0 557.664 0.084 557.688 ;
    END
  END t_o[305]
  PIN t_o[306]
    DIRECTION OUTPUT ;
    USE SIGNAL ;
    PORT
      LAYER M4 ;
        RECT  0 559.44 0.084 559.464 ;
    END
  END t_o[306]
  PIN t_o[307]
    DIRECTION OUTPUT ;
    USE SIGNAL ;
    PORT
      LAYER M4 ;
        RECT  0 561.264 0.084 561.288 ;
    END
  END t_o[307]
  PIN t_o[308]
    DIRECTION OUTPUT ;
    USE SIGNAL ;
    PORT
      LAYER M4 ;
        RECT  0 563.088 0.084 563.112 ;
    END
  END t_o[308]
  PIN t_o[309]
    DIRECTION OUTPUT ;
    USE SIGNAL ;
    PORT
      LAYER M4 ;
        RECT  0 564.912 0.084 564.936 ;
    END
  END t_o[309]
  PIN t_o[30]
    DIRECTION OUTPUT ;
    USE SIGNAL ;
    PORT
      LAYER M4 ;
        RECT  0 57.6 0.084 57.624 ;
    END
  END t_o[30]
  PIN t_o[310]
    DIRECTION OUTPUT ;
    USE SIGNAL ;
    PORT
      LAYER M4 ;
        RECT  0 566.736 0.084 566.76 ;
    END
  END t_o[310]
  PIN t_o[311]
    DIRECTION OUTPUT ;
    USE SIGNAL ;
    PORT
      LAYER M4 ;
        RECT  0 568.56 0.084 568.584 ;
    END
  END t_o[311]
  PIN t_o[312]
    DIRECTION OUTPUT ;
    USE SIGNAL ;
    PORT
      LAYER M4 ;
        RECT  0 570.384 0.084 570.408 ;
    END
  END t_o[312]
  PIN t_o[313]
    DIRECTION OUTPUT ;
    USE SIGNAL ;
    PORT
      LAYER M4 ;
        RECT  0 572.208 0.084 572.232 ;
    END
  END t_o[313]
  PIN t_o[314]
    DIRECTION OUTPUT ;
    USE SIGNAL ;
    PORT
      LAYER M4 ;
        RECT  0 573.984 0.084 574.008 ;
    END
  END t_o[314]
  PIN t_o[315]
    DIRECTION OUTPUT ;
    USE SIGNAL ;
    PORT
      LAYER M4 ;
        RECT  0 575.808 0.084 575.832 ;
    END
  END t_o[315]
  PIN t_o[316]
    DIRECTION OUTPUT ;
    USE SIGNAL ;
    PORT
      LAYER M4 ;
        RECT  0 577.632 0.084 577.656 ;
    END
  END t_o[316]
  PIN t_o[317]
    DIRECTION OUTPUT ;
    USE SIGNAL ;
    PORT
      LAYER M4 ;
        RECT  0 579.456 0.084 579.48 ;
    END
  END t_o[317]
  PIN t_o[318]
    DIRECTION OUTPUT ;
    USE SIGNAL ;
    PORT
      LAYER M4 ;
        RECT  0 581.28 0.084 581.304 ;
    END
  END t_o[318]
  PIN t_o[319]
    DIRECTION OUTPUT ;
    USE SIGNAL ;
    PORT
      LAYER M4 ;
        RECT  0 583.104 0.084 583.128 ;
    END
  END t_o[319]
  PIN t_o[31]
    DIRECTION OUTPUT ;
    USE SIGNAL ;
    PORT
      LAYER M4 ;
        RECT  0 59.424 0.084 59.448 ;
    END
  END t_o[31]
  PIN t_o[320]
    DIRECTION OUTPUT ;
    USE SIGNAL ;
    PORT
      LAYER M4 ;
        RECT  0 584.928 0.084 584.952 ;
    END
  END t_o[320]
  PIN t_o[321]
    DIRECTION OUTPUT ;
    USE SIGNAL ;
    PORT
      LAYER M4 ;
        RECT  0 586.752 0.084 586.776 ;
    END
  END t_o[321]
  PIN t_o[322]
    DIRECTION OUTPUT ;
    USE SIGNAL ;
    PORT
      LAYER M4 ;
        RECT  0 588.528 0.084 588.552 ;
    END
  END t_o[322]
  PIN t_o[323]
    DIRECTION OUTPUT ;
    USE SIGNAL ;
    PORT
      LAYER M4 ;
        RECT  0 590.352 0.084 590.376 ;
    END
  END t_o[323]
  PIN t_o[324]
    DIRECTION OUTPUT ;
    USE SIGNAL ;
    PORT
      LAYER M4 ;
        RECT  0 592.176 0.084 592.2 ;
    END
  END t_o[324]
  PIN t_o[325]
    DIRECTION OUTPUT ;
    USE SIGNAL ;
    PORT
      LAYER M4 ;
        RECT  0 594 0.084 594.024 ;
    END
  END t_o[325]
  PIN t_o[326]
    DIRECTION OUTPUT ;
    USE SIGNAL ;
    PORT
      LAYER M4 ;
        RECT  0 595.824 0.084 595.848 ;
    END
  END t_o[326]
  PIN t_o[327]
    DIRECTION OUTPUT ;
    USE SIGNAL ;
    PORT
      LAYER M4 ;
        RECT  0 597.648 0.084 597.672 ;
    END
  END t_o[327]
  PIN t_o[328]
    DIRECTION OUTPUT ;
    USE SIGNAL ;
    PORT
      LAYER M4 ;
        RECT  0 599.472 0.084 599.496 ;
    END
  END t_o[328]
  PIN t_o[329]
    DIRECTION OUTPUT ;
    USE SIGNAL ;
    PORT
      LAYER M4 ;
        RECT  0 601.296 0.084 601.32 ;
    END
  END t_o[329]
  PIN t_o[32]
    DIRECTION OUTPUT ;
    USE SIGNAL ;
    PORT
      LAYER M4 ;
        RECT  0 61.248 0.084 61.272 ;
    END
  END t_o[32]
  PIN t_o[330]
    DIRECTION OUTPUT ;
    USE SIGNAL ;
    PORT
      LAYER M4 ;
        RECT  0 603.12 0.084 603.144 ;
    END
  END t_o[330]
  PIN t_o[331]
    DIRECTION OUTPUT ;
    USE SIGNAL ;
    PORT
      LAYER M4 ;
        RECT  0 604.896 0.084 604.92 ;
    END
  END t_o[331]
  PIN t_o[332]
    DIRECTION OUTPUT ;
    USE SIGNAL ;
    PORT
      LAYER M4 ;
        RECT  0 606.72 0.084 606.744 ;
    END
  END t_o[332]
  PIN t_o[333]
    DIRECTION OUTPUT ;
    USE SIGNAL ;
    PORT
      LAYER M4 ;
        RECT  0 608.544 0.084 608.568 ;
    END
  END t_o[333]
  PIN t_o[334]
    DIRECTION OUTPUT ;
    USE SIGNAL ;
    PORT
      LAYER M4 ;
        RECT  0 610.368 0.084 610.392 ;
    END
  END t_o[334]
  PIN t_o[335]
    DIRECTION OUTPUT ;
    USE SIGNAL ;
    PORT
      LAYER M4 ;
        RECT  0 612.192 0.084 612.216 ;
    END
  END t_o[335]
  PIN t_o[336]
    DIRECTION OUTPUT ;
    USE SIGNAL ;
    PORT
      LAYER M4 ;
        RECT  0 614.016 0.084 614.04 ;
    END
  END t_o[336]
  PIN t_o[337]
    DIRECTION OUTPUT ;
    USE SIGNAL ;
    PORT
      LAYER M4 ;
        RECT  0 615.84 0.084 615.864 ;
    END
  END t_o[337]
  PIN t_o[338]
    DIRECTION OUTPUT ;
    USE SIGNAL ;
    PORT
      LAYER M4 ;
        RECT  0 617.664 0.084 617.688 ;
    END
  END t_o[338]
  PIN t_o[339]
    DIRECTION OUTPUT ;
    USE SIGNAL ;
    PORT
      LAYER M4 ;
        RECT  0 619.44 0.084 619.464 ;
    END
  END t_o[339]
  PIN t_o[33]
    DIRECTION OUTPUT ;
    USE SIGNAL ;
    PORT
      LAYER M4 ;
        RECT  0 63.072 0.084 63.096 ;
    END
  END t_o[33]
  PIN t_o[340]
    DIRECTION OUTPUT ;
    USE SIGNAL ;
    PORT
      LAYER M4 ;
        RECT  0 621.264 0.084 621.288 ;
    END
  END t_o[340]
  PIN t_o[341]
    DIRECTION OUTPUT ;
    USE SIGNAL ;
    PORT
      LAYER M4 ;
        RECT  0 623.088 0.084 623.112 ;
    END
  END t_o[341]
  PIN t_o[342]
    DIRECTION OUTPUT ;
    USE SIGNAL ;
    PORT
      LAYER M4 ;
        RECT  0 624.912 0.084 624.936 ;
    END
  END t_o[342]
  PIN t_o[343]
    DIRECTION OUTPUT ;
    USE SIGNAL ;
    PORT
      LAYER M4 ;
        RECT  0 626.736 0.084 626.76 ;
    END
  END t_o[343]
  PIN t_o[344]
    DIRECTION OUTPUT ;
    USE SIGNAL ;
    PORT
      LAYER M4 ;
        RECT  0 628.56 0.084 628.584 ;
    END
  END t_o[344]
  PIN t_o[345]
    DIRECTION OUTPUT ;
    USE SIGNAL ;
    PORT
      LAYER M4 ;
        RECT  0 630.384 0.084 630.408 ;
    END
  END t_o[345]
  PIN t_o[346]
    DIRECTION OUTPUT ;
    USE SIGNAL ;
    PORT
      LAYER M4 ;
        RECT  0 632.208 0.084 632.232 ;
    END
  END t_o[346]
  PIN t_o[347]
    DIRECTION OUTPUT ;
    USE SIGNAL ;
    PORT
      LAYER M4 ;
        RECT  0 634.032 0.084 634.056 ;
    END
  END t_o[347]
  PIN t_o[348]
    DIRECTION OUTPUT ;
    USE SIGNAL ;
    PORT
      LAYER M4 ;
        RECT  0 635.808 0.084 635.832 ;
    END
  END t_o[348]
  PIN t_o[349]
    DIRECTION OUTPUT ;
    USE SIGNAL ;
    PORT
      LAYER M4 ;
        RECT  0 637.632 0.084 637.656 ;
    END
  END t_o[349]
  PIN t_o[34]
    DIRECTION OUTPUT ;
    USE SIGNAL ;
    PORT
      LAYER M4 ;
        RECT  0 64.896 0.084 64.92 ;
    END
  END t_o[34]
  PIN t_o[350]
    DIRECTION OUTPUT ;
    USE SIGNAL ;
    PORT
      LAYER M4 ;
        RECT  0 639.456 0.084 639.48 ;
    END
  END t_o[350]
  PIN t_o[351]
    DIRECTION OUTPUT ;
    USE SIGNAL ;
    PORT
      LAYER M4 ;
        RECT  0 641.28 0.084 641.304 ;
    END
  END t_o[351]
  PIN t_o[352]
    DIRECTION OUTPUT ;
    USE SIGNAL ;
    PORT
      LAYER M4 ;
        RECT  0 643.104 0.084 643.128 ;
    END
  END t_o[352]
  PIN t_o[353]
    DIRECTION OUTPUT ;
    USE SIGNAL ;
    PORT
      LAYER M4 ;
        RECT  0 644.928 0.084 644.952 ;
    END
  END t_o[353]
  PIN t_o[35]
    DIRECTION OUTPUT ;
    USE SIGNAL ;
    PORT
      LAYER M4 ;
        RECT  0 66.72 0.084 66.744 ;
    END
  END t_o[35]
  PIN t_o[36]
    DIRECTION OUTPUT ;
    USE SIGNAL ;
    PORT
      LAYER M4 ;
        RECT  0 68.496 0.084 68.52 ;
    END
  END t_o[36]
  PIN t_o[37]
    DIRECTION OUTPUT ;
    USE SIGNAL ;
    PORT
      LAYER M4 ;
        RECT  0 70.32 0.084 70.344 ;
    END
  END t_o[37]
  PIN t_o[38]
    DIRECTION OUTPUT ;
    USE SIGNAL ;
    PORT
      LAYER M4 ;
        RECT  0 72.144 0.084 72.168 ;
    END
  END t_o[38]
  PIN t_o[39]
    DIRECTION OUTPUT ;
    USE SIGNAL ;
    PORT
      LAYER M4 ;
        RECT  0 73.968 0.084 73.992 ;
    END
  END t_o[39]
  PIN t_o[3]
    DIRECTION OUTPUT ;
    USE SIGNAL ;
    PORT
      LAYER M4 ;
        RECT  0 8.496 0.084 8.52 ;
    END
  END t_o[3]
  PIN t_o[40]
    DIRECTION OUTPUT ;
    USE SIGNAL ;
    PORT
      LAYER M4 ;
        RECT  0 75.792 0.084 75.816 ;
    END
  END t_o[40]
  PIN t_o[41]
    DIRECTION OUTPUT ;
    USE SIGNAL ;
    PORT
      LAYER M4 ;
        RECT  0 77.616 0.084 77.64 ;
    END
  END t_o[41]
  PIN t_o[42]
    DIRECTION OUTPUT ;
    USE SIGNAL ;
    PORT
      LAYER M4 ;
        RECT  0 79.44 0.084 79.464 ;
    END
  END t_o[42]
  PIN t_o[43]
    DIRECTION OUTPUT ;
    USE SIGNAL ;
    PORT
      LAYER M4 ;
        RECT  0 81.264 0.084 81.288 ;
    END
  END t_o[43]
  PIN t_o[44]
    DIRECTION OUTPUT ;
    USE SIGNAL ;
    PORT
      LAYER M4 ;
        RECT  0 83.04 0.084 83.064 ;
    END
  END t_o[44]
  PIN t_o[45]
    DIRECTION OUTPUT ;
    USE SIGNAL ;
    PORT
      LAYER M4 ;
        RECT  0 84.864 0.084 84.888 ;
    END
  END t_o[45]
  PIN t_o[46]
    DIRECTION OUTPUT ;
    USE SIGNAL ;
    PORT
      LAYER M4 ;
        RECT  0 86.688 0.084 86.712 ;
    END
  END t_o[46]
  PIN t_o[47]
    DIRECTION OUTPUT ;
    USE SIGNAL ;
    PORT
      LAYER M4 ;
        RECT  0 88.512 0.084 88.536 ;
    END
  END t_o[47]
  PIN t_o[48]
    DIRECTION OUTPUT ;
    USE SIGNAL ;
    PORT
      LAYER M4 ;
        RECT  0 90.336 0.084 90.36 ;
    END
  END t_o[48]
  PIN t_o[49]
    DIRECTION OUTPUT ;
    USE SIGNAL ;
    PORT
      LAYER M4 ;
        RECT  0 92.16 0.084 92.184 ;
    END
  END t_o[49]
  PIN t_o[4]
    DIRECTION OUTPUT ;
    USE SIGNAL ;
    PORT
      LAYER M4 ;
        RECT  0 10.32 0.084 10.344 ;
    END
  END t_o[4]
  PIN t_o[50]
    DIRECTION OUTPUT ;
    USE SIGNAL ;
    PORT
      LAYER M4 ;
        RECT  0 93.984 0.084 94.008 ;
    END
  END t_o[50]
  PIN t_o[51]
    DIRECTION OUTPUT ;
    USE SIGNAL ;
    PORT
      LAYER M4 ;
        RECT  0 95.808 0.084 95.832 ;
    END
  END t_o[51]
  PIN t_o[52]
    DIRECTION OUTPUT ;
    USE SIGNAL ;
    PORT
      LAYER M4 ;
        RECT  0 97.632 0.084 97.656 ;
    END
  END t_o[52]
  PIN t_o[53]
    DIRECTION OUTPUT ;
    USE SIGNAL ;
    PORT
      LAYER M4 ;
        RECT  0 99.408 0.084 99.432 ;
    END
  END t_o[53]
  PIN t_o[54]
    DIRECTION OUTPUT ;
    USE SIGNAL ;
    PORT
      LAYER M4 ;
        RECT  0 101.232 0.084 101.256 ;
    END
  END t_o[54]
  PIN t_o[55]
    DIRECTION OUTPUT ;
    USE SIGNAL ;
    PORT
      LAYER M4 ;
        RECT  0 103.056 0.084 103.08 ;
    END
  END t_o[55]
  PIN t_o[56]
    DIRECTION OUTPUT ;
    USE SIGNAL ;
    PORT
      LAYER M4 ;
        RECT  0 104.88 0.084 104.904 ;
    END
  END t_o[56]
  PIN t_o[57]
    DIRECTION OUTPUT ;
    USE SIGNAL ;
    PORT
      LAYER M4 ;
        RECT  0 106.704 0.084 106.728 ;
    END
  END t_o[57]
  PIN t_o[58]
    DIRECTION OUTPUT ;
    USE SIGNAL ;
    PORT
      LAYER M4 ;
        RECT  0 108.528 0.084 108.552 ;
    END
  END t_o[58]
  PIN t_o[59]
    DIRECTION OUTPUT ;
    USE SIGNAL ;
    PORT
      LAYER M4 ;
        RECT  0 110.352 0.084 110.376 ;
    END
  END t_o[59]
  PIN t_o[5]
    DIRECTION OUTPUT ;
    USE SIGNAL ;
    PORT
      LAYER M4 ;
        RECT  0 12.144 0.084 12.168 ;
    END
  END t_o[5]
  PIN t_o[60]
    DIRECTION OUTPUT ;
    USE SIGNAL ;
    PORT
      LAYER M4 ;
        RECT  0 112.176 0.084 112.2 ;
    END
  END t_o[60]
  PIN t_o[61]
    DIRECTION OUTPUT ;
    USE SIGNAL ;
    PORT
      LAYER M4 ;
        RECT  0 113.952 0.084 113.976 ;
    END
  END t_o[61]
  PIN t_o[62]
    DIRECTION OUTPUT ;
    USE SIGNAL ;
    PORT
      LAYER M4 ;
        RECT  0 115.776 0.084 115.8 ;
    END
  END t_o[62]
  PIN t_o[63]
    DIRECTION OUTPUT ;
    USE SIGNAL ;
    PORT
      LAYER M4 ;
        RECT  0 117.6 0.084 117.624 ;
    END
  END t_o[63]
  PIN t_o[64]
    DIRECTION OUTPUT ;
    USE SIGNAL ;
    PORT
      LAYER M4 ;
        RECT  0 119.424 0.084 119.448 ;
    END
  END t_o[64]
  PIN t_o[65]
    DIRECTION OUTPUT ;
    USE SIGNAL ;
    PORT
      LAYER M4 ;
        RECT  0 121.248 0.084 121.272 ;
    END
  END t_o[65]
  PIN t_o[66]
    DIRECTION OUTPUT ;
    USE SIGNAL ;
    PORT
      LAYER M4 ;
        RECT  0 123.072 0.084 123.096 ;
    END
  END t_o[66]
  PIN t_o[67]
    DIRECTION OUTPUT ;
    USE SIGNAL ;
    PORT
      LAYER M4 ;
        RECT  0 124.896 0.084 124.92 ;
    END
  END t_o[67]
  PIN t_o[68]
    DIRECTION OUTPUT ;
    USE SIGNAL ;
    PORT
      LAYER M4 ;
        RECT  0 126.72 0.084 126.744 ;
    END
  END t_o[68]
  PIN t_o[69]
    DIRECTION OUTPUT ;
    USE SIGNAL ;
    PORT
      LAYER M4 ;
        RECT  0 128.544 0.084 128.568 ;
    END
  END t_o[69]
  PIN t_o[6]
    DIRECTION OUTPUT ;
    USE SIGNAL ;
    PORT
      LAYER M4 ;
        RECT  0 13.968 0.084 13.992 ;
    END
  END t_o[6]
  PIN t_o[70]
    DIRECTION OUTPUT ;
    USE SIGNAL ;
    PORT
      LAYER M4 ;
        RECT  0 130.32 0.084 130.344 ;
    END
  END t_o[70]
  PIN t_o[71]
    DIRECTION OUTPUT ;
    USE SIGNAL ;
    PORT
      LAYER M4 ;
        RECT  0 132.144 0.084 132.168 ;
    END
  END t_o[71]
  PIN t_o[72]
    DIRECTION OUTPUT ;
    USE SIGNAL ;
    PORT
      LAYER M4 ;
        RECT  0 133.968 0.084 133.992 ;
    END
  END t_o[72]
  PIN t_o[73]
    DIRECTION OUTPUT ;
    USE SIGNAL ;
    PORT
      LAYER M4 ;
        RECT  0 135.792 0.084 135.816 ;
    END
  END t_o[73]
  PIN t_o[74]
    DIRECTION OUTPUT ;
    USE SIGNAL ;
    PORT
      LAYER M4 ;
        RECT  0 137.616 0.084 137.64 ;
    END
  END t_o[74]
  PIN t_o[75]
    DIRECTION OUTPUT ;
    USE SIGNAL ;
    PORT
      LAYER M4 ;
        RECT  0 139.44 0.084 139.464 ;
    END
  END t_o[75]
  PIN t_o[76]
    DIRECTION OUTPUT ;
    USE SIGNAL ;
    PORT
      LAYER M4 ;
        RECT  0 141.264 0.084 141.288 ;
    END
  END t_o[76]
  PIN t_o[77]
    DIRECTION OUTPUT ;
    USE SIGNAL ;
    PORT
      LAYER M4 ;
        RECT  0 143.088 0.084 143.112 ;
    END
  END t_o[77]
  PIN t_o[78]
    DIRECTION OUTPUT ;
    USE SIGNAL ;
    PORT
      LAYER M4 ;
        RECT  0 144.864 0.084 144.888 ;
    END
  END t_o[78]
  PIN t_o[79]
    DIRECTION OUTPUT ;
    USE SIGNAL ;
    PORT
      LAYER M4 ;
        RECT  0 146.688 0.084 146.712 ;
    END
  END t_o[79]
  PIN t_o[7]
    DIRECTION OUTPUT ;
    USE SIGNAL ;
    PORT
      LAYER M4 ;
        RECT  0 15.792 0.084 15.816 ;
    END
  END t_o[7]
  PIN t_o[80]
    DIRECTION OUTPUT ;
    USE SIGNAL ;
    PORT
      LAYER M4 ;
        RECT  0 148.512 0.084 148.536 ;
    END
  END t_o[80]
  PIN t_o[81]
    DIRECTION OUTPUT ;
    USE SIGNAL ;
    PORT
      LAYER M4 ;
        RECT  0 150.336 0.084 150.36 ;
    END
  END t_o[81]
  PIN t_o[82]
    DIRECTION OUTPUT ;
    USE SIGNAL ;
    PORT
      LAYER M4 ;
        RECT  0 152.16 0.084 152.184 ;
    END
  END t_o[82]
  PIN t_o[83]
    DIRECTION OUTPUT ;
    USE SIGNAL ;
    PORT
      LAYER M4 ;
        RECT  0 153.984 0.084 154.008 ;
    END
  END t_o[83]
  PIN t_o[84]
    DIRECTION OUTPUT ;
    USE SIGNAL ;
    PORT
      LAYER M4 ;
        RECT  0 155.808 0.084 155.832 ;
    END
  END t_o[84]
  PIN t_o[85]
    DIRECTION OUTPUT ;
    USE SIGNAL ;
    PORT
      LAYER M4 ;
        RECT  0 157.632 0.084 157.656 ;
    END
  END t_o[85]
  PIN t_o[86]
    DIRECTION OUTPUT ;
    USE SIGNAL ;
    PORT
      LAYER M4 ;
        RECT  0 159.408 0.084 159.432 ;
    END
  END t_o[86]
  PIN t_o[87]
    DIRECTION OUTPUT ;
    USE SIGNAL ;
    PORT
      LAYER M4 ;
        RECT  0 161.232 0.084 161.256 ;
    END
  END t_o[87]
  PIN t_o[88]
    DIRECTION OUTPUT ;
    USE SIGNAL ;
    PORT
      LAYER M4 ;
        RECT  0 163.056 0.084 163.08 ;
    END
  END t_o[88]
  PIN t_o[89]
    DIRECTION OUTPUT ;
    USE SIGNAL ;
    PORT
      LAYER M4 ;
        RECT  0 164.88 0.084 164.904 ;
    END
  END t_o[89]
  PIN t_o[8]
    DIRECTION OUTPUT ;
    USE SIGNAL ;
    PORT
      LAYER M4 ;
        RECT  0 17.616 0.084 17.64 ;
    END
  END t_o[8]
  PIN t_o[90]
    DIRECTION OUTPUT ;
    USE SIGNAL ;
    PORT
      LAYER M4 ;
        RECT  0 166.704 0.084 166.728 ;
    END
  END t_o[90]
  PIN t_o[91]
    DIRECTION OUTPUT ;
    USE SIGNAL ;
    PORT
      LAYER M4 ;
        RECT  0 168.528 0.084 168.552 ;
    END
  END t_o[91]
  PIN t_o[92]
    DIRECTION OUTPUT ;
    USE SIGNAL ;
    PORT
      LAYER M4 ;
        RECT  0 170.352 0.084 170.376 ;
    END
  END t_o[92]
  PIN t_o[93]
    DIRECTION OUTPUT ;
    USE SIGNAL ;
    PORT
      LAYER M4 ;
        RECT  0 172.176 0.084 172.2 ;
    END
  END t_o[93]
  PIN t_o[94]
    DIRECTION OUTPUT ;
    USE SIGNAL ;
    PORT
      LAYER M4 ;
        RECT  0 174 0.084 174.024 ;
    END
  END t_o[94]
  PIN t_o[95]
    DIRECTION OUTPUT ;
    USE SIGNAL ;
    PORT
      LAYER M4 ;
        RECT  0 175.776 0.084 175.8 ;
    END
  END t_o[95]
  PIN t_o[96]
    DIRECTION OUTPUT ;
    USE SIGNAL ;
    PORT
      LAYER M4 ;
        RECT  0 177.6 0.084 177.624 ;
    END
  END t_o[96]
  PIN t_o[97]
    DIRECTION OUTPUT ;
    USE SIGNAL ;
    PORT
      LAYER M4 ;
        RECT  0 179.424 0.084 179.448 ;
    END
  END t_o[97]
  PIN t_o[98]
    DIRECTION OUTPUT ;
    USE SIGNAL ;
    PORT
      LAYER M4 ;
        RECT  0 181.248 0.084 181.272 ;
    END
  END t_o[98]
  PIN t_o[99]
    DIRECTION OUTPUT ;
    USE SIGNAL ;
    PORT
      LAYER M4 ;
        RECT  0 183.072 0.084 183.096 ;
    END
  END t_o[99]
  PIN t_o[9]
    DIRECTION OUTPUT ;
    USE SIGNAL ;
    PORT
      LAYER M4 ;
        RECT  0 19.44 0.084 19.464 ;
    END
  END t_o[9]
  PIN t_s[0]
    DIRECTION OUTPUT ;
    USE SIGNAL ;
    PORT
      LAYER M3 ;
        RECT  43.344 647.962 43.362 648 ;
    END
  END t_s[0]
  PIN t_s[100]
    DIRECTION OUTPUT ;
    USE SIGNAL ;
    PORT
      LAYER M3 ;
        RECT  73.296 647.962 73.314 648 ;
    END
  END t_s[100]
  PIN t_s[101]
    DIRECTION OUTPUT ;
    USE SIGNAL ;
    PORT
      LAYER M5 ;
        RECT  73.584 647.916 73.608 648 ;
    END
  END t_s[101]
  PIN t_s[102]
    DIRECTION OUTPUT ;
    USE SIGNAL ;
    PORT
      LAYER M3 ;
        RECT  73.908 647.962 73.926 648 ;
    END
  END t_s[102]
  PIN t_s[103]
    DIRECTION OUTPUT ;
    USE SIGNAL ;
    PORT
      LAYER M5 ;
        RECT  74.208 647.916 74.232 648 ;
    END
  END t_s[103]
  PIN t_s[104]
    DIRECTION OUTPUT ;
    USE SIGNAL ;
    PORT
      LAYER M3 ;
        RECT  74.52 647.962 74.538 648 ;
    END
  END t_s[104]
  PIN t_s[105]
    DIRECTION OUTPUT ;
    USE SIGNAL ;
    PORT
      LAYER M5 ;
        RECT  74.784 647.916 74.808 648 ;
    END
  END t_s[105]
  PIN t_s[106]
    DIRECTION OUTPUT ;
    USE SIGNAL ;
    PORT
      LAYER M3 ;
        RECT  75.096 647.962 75.114 648 ;
    END
  END t_s[106]
  PIN t_s[107]
    DIRECTION OUTPUT ;
    USE SIGNAL ;
    PORT
      LAYER M5 ;
        RECT  75.408 647.916 75.432 648 ;
    END
  END t_s[107]
  PIN t_s[108]
    DIRECTION OUTPUT ;
    USE SIGNAL ;
    PORT
      LAYER M3 ;
        RECT  75.708 647.962 75.726 648 ;
    END
  END t_s[108]
  PIN t_s[109]
    DIRECTION OUTPUT ;
    USE SIGNAL ;
    PORT
      LAYER M5 ;
        RECT  75.984 647.916 76.008 648 ;
    END
  END t_s[109]
  PIN t_s[10]
    DIRECTION OUTPUT ;
    USE SIGNAL ;
    PORT
      LAYER M3 ;
        RECT  46.332 647.962 46.35 648 ;
    END
  END t_s[10]
  PIN t_s[110]
    DIRECTION OUTPUT ;
    USE SIGNAL ;
    PORT
      LAYER M3 ;
        RECT  76.32 647.962 76.338 648 ;
    END
  END t_s[110]
  PIN t_s[111]
    DIRECTION OUTPUT ;
    USE SIGNAL ;
    PORT
      LAYER M5 ;
        RECT  76.608 647.916 76.632 648 ;
    END
  END t_s[111]
  PIN t_s[112]
    DIRECTION OUTPUT ;
    USE SIGNAL ;
    PORT
      LAYER M3 ;
        RECT  76.896 647.962 76.914 648 ;
    END
  END t_s[112]
  PIN t_s[113]
    DIRECTION OUTPUT ;
    USE SIGNAL ;
    PORT
      LAYER M5 ;
        RECT  77.184 647.916 77.208 648 ;
    END
  END t_s[113]
  PIN t_s[114]
    DIRECTION OUTPUT ;
    USE SIGNAL ;
    PORT
      LAYER M3 ;
        RECT  77.508 647.962 77.526 648 ;
    END
  END t_s[114]
  PIN t_s[115]
    DIRECTION OUTPUT ;
    USE SIGNAL ;
    PORT
      LAYER M5 ;
        RECT  77.808 647.916 77.832 648 ;
    END
  END t_s[115]
  PIN t_s[116]
    DIRECTION OUTPUT ;
    USE SIGNAL ;
    PORT
      LAYER M3 ;
        RECT  78.084 647.962 78.102 648 ;
    END
  END t_s[116]
  PIN t_s[117]
    DIRECTION OUTPUT ;
    USE SIGNAL ;
    PORT
      LAYER M5 ;
        RECT  78.384 647.916 78.408 648 ;
    END
  END t_s[117]
  PIN t_s[118]
    DIRECTION OUTPUT ;
    USE SIGNAL ;
    PORT
      LAYER M3 ;
        RECT  78.696 647.962 78.714 648 ;
    END
  END t_s[118]
  PIN t_s[119]
    DIRECTION OUTPUT ;
    USE SIGNAL ;
    PORT
      LAYER M5 ;
        RECT  79.008 647.916 79.032 648 ;
    END
  END t_s[119]
  PIN t_s[11]
    DIRECTION OUTPUT ;
    USE SIGNAL ;
    PORT
      LAYER M5 ;
        RECT  46.656 647.916 46.68 648 ;
    END
  END t_s[11]
  PIN t_s[120]
    DIRECTION OUTPUT ;
    USE SIGNAL ;
    PORT
      LAYER M3 ;
        RECT  79.308 647.962 79.326 648 ;
    END
  END t_s[120]
  PIN t_s[121]
    DIRECTION OUTPUT ;
    USE SIGNAL ;
    PORT
      LAYER M5 ;
        RECT  79.584 647.916 79.608 648 ;
    END
  END t_s[121]
  PIN t_s[122]
    DIRECTION OUTPUT ;
    USE SIGNAL ;
    PORT
      LAYER M3 ;
        RECT  79.884 647.962 79.902 648 ;
    END
  END t_s[122]
  PIN t_s[123]
    DIRECTION OUTPUT ;
    USE SIGNAL ;
    PORT
      LAYER M5 ;
        RECT  80.208 647.916 80.232 648 ;
    END
  END t_s[123]
  PIN t_s[124]
    DIRECTION OUTPUT ;
    USE SIGNAL ;
    PORT
      LAYER M3 ;
        RECT  80.496 647.962 80.514 648 ;
    END
  END t_s[124]
  PIN t_s[125]
    DIRECTION OUTPUT ;
    USE SIGNAL ;
    PORT
      LAYER M5 ;
        RECT  80.784 647.916 80.808 648 ;
    END
  END t_s[125]
  PIN t_s[126]
    DIRECTION OUTPUT ;
    USE SIGNAL ;
    PORT
      LAYER M3 ;
        RECT  81.108 647.962 81.126 648 ;
    END
  END t_s[126]
  PIN t_s[127]
    DIRECTION OUTPUT ;
    USE SIGNAL ;
    PORT
      LAYER M5 ;
        RECT  81.408 647.916 81.432 648 ;
    END
  END t_s[127]
  PIN t_s[128]
    DIRECTION OUTPUT ;
    USE SIGNAL ;
    PORT
      LAYER M3 ;
        RECT  81.684 647.962 81.702 648 ;
    END
  END t_s[128]
  PIN t_s[129]
    DIRECTION OUTPUT ;
    USE SIGNAL ;
    PORT
      LAYER M5 ;
        RECT  81.984 647.916 82.008 648 ;
    END
  END t_s[129]
  PIN t_s[12]
    DIRECTION OUTPUT ;
    USE SIGNAL ;
    PORT
      LAYER M3 ;
        RECT  46.944 647.962 46.962 648 ;
    END
  END t_s[12]
  PIN t_s[130]
    DIRECTION OUTPUT ;
    USE SIGNAL ;
    PORT
      LAYER M3 ;
        RECT  82.296 647.962 82.314 648 ;
    END
  END t_s[130]
  PIN t_s[131]
    DIRECTION OUTPUT ;
    USE SIGNAL ;
    PORT
      LAYER M5 ;
        RECT  82.608 647.916 82.632 648 ;
    END
  END t_s[131]
  PIN t_s[132]
    DIRECTION OUTPUT ;
    USE SIGNAL ;
    PORT
      LAYER M3 ;
        RECT  82.908 647.962 82.926 648 ;
    END
  END t_s[132]
  PIN t_s[133]
    DIRECTION OUTPUT ;
    USE SIGNAL ;
    PORT
      LAYER M5 ;
        RECT  83.184 647.916 83.208 648 ;
    END
  END t_s[133]
  PIN t_s[134]
    DIRECTION OUTPUT ;
    USE SIGNAL ;
    PORT
      LAYER M3 ;
        RECT  83.484 647.962 83.502 648 ;
    END
  END t_s[134]
  PIN t_s[135]
    DIRECTION OUTPUT ;
    USE SIGNAL ;
    PORT
      LAYER M5 ;
        RECT  83.808 647.916 83.832 648 ;
    END
  END t_s[135]
  PIN t_s[136]
    DIRECTION OUTPUT ;
    USE SIGNAL ;
    PORT
      LAYER M3 ;
        RECT  84.096 647.962 84.114 648 ;
    END
  END t_s[136]
  PIN t_s[137]
    DIRECTION OUTPUT ;
    USE SIGNAL ;
    PORT
      LAYER M5 ;
        RECT  84.384 647.916 84.408 648 ;
    END
  END t_s[137]
  PIN t_s[138]
    DIRECTION OUTPUT ;
    USE SIGNAL ;
    PORT
      LAYER M3 ;
        RECT  84.708 647.962 84.726 648 ;
    END
  END t_s[138]
  PIN t_s[139]
    DIRECTION OUTPUT ;
    USE SIGNAL ;
    PORT
      LAYER M5 ;
        RECT  85.008 647.916 85.032 648 ;
    END
  END t_s[139]
  PIN t_s[13]
    DIRECTION OUTPUT ;
    USE SIGNAL ;
    PORT
      LAYER M5 ;
        RECT  47.232 647.916 47.256 648 ;
    END
  END t_s[13]
  PIN t_s[140]
    DIRECTION OUTPUT ;
    USE SIGNAL ;
    PORT
      LAYER M3 ;
        RECT  85.284 647.962 85.302 648 ;
    END
  END t_s[140]
  PIN t_s[141]
    DIRECTION OUTPUT ;
    USE SIGNAL ;
    PORT
      LAYER M5 ;
        RECT  85.584 647.916 85.608 648 ;
    END
  END t_s[141]
  PIN t_s[142]
    DIRECTION OUTPUT ;
    USE SIGNAL ;
    PORT
      LAYER M3 ;
        RECT  85.896 647.962 85.914 648 ;
    END
  END t_s[142]
  PIN t_s[143]
    DIRECTION OUTPUT ;
    USE SIGNAL ;
    PORT
      LAYER M5 ;
        RECT  86.208 647.916 86.232 648 ;
    END
  END t_s[143]
  PIN t_s[144]
    DIRECTION OUTPUT ;
    USE SIGNAL ;
    PORT
      LAYER M3 ;
        RECT  86.508 647.962 86.526 648 ;
    END
  END t_s[144]
  PIN t_s[145]
    DIRECTION OUTPUT ;
    USE SIGNAL ;
    PORT
      LAYER M5 ;
        RECT  86.784 647.916 86.808 648 ;
    END
  END t_s[145]
  PIN t_s[146]
    DIRECTION OUTPUT ;
    USE SIGNAL ;
    PORT
      LAYER M3 ;
        RECT  87.084 647.962 87.102 648 ;
    END
  END t_s[146]
  PIN t_s[147]
    DIRECTION OUTPUT ;
    USE SIGNAL ;
    PORT
      LAYER M5 ;
        RECT  87.408 647.916 87.432 648 ;
    END
  END t_s[147]
  PIN t_s[148]
    DIRECTION OUTPUT ;
    USE SIGNAL ;
    PORT
      LAYER M3 ;
        RECT  87.696 647.962 87.714 648 ;
    END
  END t_s[148]
  PIN t_s[149]
    DIRECTION OUTPUT ;
    USE SIGNAL ;
    PORT
      LAYER M5 ;
        RECT  87.984 647.916 88.008 648 ;
    END
  END t_s[149]
  PIN t_s[14]
    DIRECTION OUTPUT ;
    USE SIGNAL ;
    PORT
      LAYER M3 ;
        RECT  47.52 647.962 47.538 648 ;
    END
  END t_s[14]
  PIN t_s[150]
    DIRECTION OUTPUT ;
    USE SIGNAL ;
    PORT
      LAYER M3 ;
        RECT  88.272 647.962 88.29 648 ;
    END
  END t_s[150]
  PIN t_s[151]
    DIRECTION OUTPUT ;
    USE SIGNAL ;
    PORT
      LAYER M5 ;
        RECT  88.608 647.916 88.632 648 ;
    END
  END t_s[151]
  PIN t_s[152]
    DIRECTION OUTPUT ;
    USE SIGNAL ;
    PORT
      LAYER M3 ;
        RECT  88.884 647.962 88.902 648 ;
    END
  END t_s[152]
  PIN t_s[153]
    DIRECTION OUTPUT ;
    USE SIGNAL ;
    PORT
      LAYER M5 ;
        RECT  89.184 647.916 89.208 648 ;
    END
  END t_s[153]
  PIN t_s[154]
    DIRECTION OUTPUT ;
    USE SIGNAL ;
    PORT
      LAYER M3 ;
        RECT  89.496 647.962 89.514 648 ;
    END
  END t_s[154]
  PIN t_s[155]
    DIRECTION OUTPUT ;
    USE SIGNAL ;
    PORT
      LAYER M5 ;
        RECT  89.808 647.916 89.832 648 ;
    END
  END t_s[155]
  PIN t_s[156]
    DIRECTION OUTPUT ;
    USE SIGNAL ;
    PORT
      LAYER M3 ;
        RECT  90.072 647.962 90.09 648 ;
    END
  END t_s[156]
  PIN t_s[157]
    DIRECTION OUTPUT ;
    USE SIGNAL ;
    PORT
      LAYER M5 ;
        RECT  90.384 647.916 90.408 648 ;
    END
  END t_s[157]
  PIN t_s[158]
    DIRECTION OUTPUT ;
    USE SIGNAL ;
    PORT
      LAYER M3 ;
        RECT  90.684 647.962 90.702 648 ;
    END
  END t_s[158]
  PIN t_s[159]
    DIRECTION OUTPUT ;
    USE SIGNAL ;
    PORT
      LAYER M5 ;
        RECT  90.96 647.916 90.984 648 ;
    END
  END t_s[159]
  PIN t_s[15]
    DIRECTION OUTPUT ;
    USE SIGNAL ;
    PORT
      LAYER M5 ;
        RECT  47.856 647.916 47.88 648 ;
    END
  END t_s[15]
  PIN t_s[160]
    DIRECTION OUTPUT ;
    USE SIGNAL ;
    PORT
      LAYER M3 ;
        RECT  91.296 647.962 91.314 648 ;
    END
  END t_s[160]
  PIN t_s[161]
    DIRECTION OUTPUT ;
    USE SIGNAL ;
    PORT
      LAYER M5 ;
        RECT  91.584 647.916 91.608 648 ;
    END
  END t_s[161]
  PIN t_s[162]
    DIRECTION OUTPUT ;
    USE SIGNAL ;
    PORT
      LAYER M3 ;
        RECT  91.872 647.962 91.89 648 ;
    END
  END t_s[162]
  PIN t_s[163]
    DIRECTION OUTPUT ;
    USE SIGNAL ;
    PORT
      LAYER M5 ;
        RECT  92.16 647.916 92.184 648 ;
    END
  END t_s[163]
  PIN t_s[164]
    DIRECTION OUTPUT ;
    USE SIGNAL ;
    PORT
      LAYER M3 ;
        RECT  92.484 647.962 92.502 648 ;
    END
  END t_s[164]
  PIN t_s[165]
    DIRECTION OUTPUT ;
    USE SIGNAL ;
    PORT
      LAYER M5 ;
        RECT  92.784 647.916 92.808 648 ;
    END
  END t_s[165]
  PIN t_s[166]
    DIRECTION OUTPUT ;
    USE SIGNAL ;
    PORT
      LAYER M3 ;
        RECT  93.096 647.962 93.114 648 ;
    END
  END t_s[166]
  PIN t_s[167]
    DIRECTION OUTPUT ;
    USE SIGNAL ;
    PORT
      LAYER M5 ;
        RECT  93.36 647.916 93.384 648 ;
    END
  END t_s[167]
  PIN t_s[168]
    DIRECTION OUTPUT ;
    USE SIGNAL ;
    PORT
      LAYER M3 ;
        RECT  93.672 647.962 93.69 648 ;
    END
  END t_s[168]
  PIN t_s[169]
    DIRECTION OUTPUT ;
    USE SIGNAL ;
    PORT
      LAYER M5 ;
        RECT  93.984 647.916 94.008 648 ;
    END
  END t_s[169]
  PIN t_s[16]
    DIRECTION OUTPUT ;
    USE SIGNAL ;
    PORT
      LAYER M3 ;
        RECT  48.132 647.962 48.15 648 ;
    END
  END t_s[16]
  PIN t_s[170]
    DIRECTION OUTPUT ;
    USE SIGNAL ;
    PORT
      LAYER M3 ;
        RECT  94.284 647.962 94.302 648 ;
    END
  END t_s[170]
  PIN t_s[171]
    DIRECTION OUTPUT ;
    USE SIGNAL ;
    PORT
      LAYER M5 ;
        RECT  94.56 647.916 94.584 648 ;
    END
  END t_s[171]
  PIN t_s[172]
    DIRECTION OUTPUT ;
    USE SIGNAL ;
    PORT
      LAYER M3 ;
        RECT  94.896 647.962 94.914 648 ;
    END
  END t_s[172]
  PIN t_s[173]
    DIRECTION OUTPUT ;
    USE SIGNAL ;
    PORT
      LAYER M5 ;
        RECT  95.184 647.916 95.208 648 ;
    END
  END t_s[173]
  PIN t_s[174]
    DIRECTION OUTPUT ;
    USE SIGNAL ;
    PORT
      LAYER M3 ;
        RECT  95.472 647.962 95.49 648 ;
    END
  END t_s[174]
  PIN t_s[175]
    DIRECTION OUTPUT ;
    USE SIGNAL ;
    PORT
      LAYER M5 ;
        RECT  95.76 647.916 95.784 648 ;
    END
  END t_s[175]
  PIN t_s[176]
    DIRECTION OUTPUT ;
    USE SIGNAL ;
    PORT
      LAYER M3 ;
        RECT  96.084 647.962 96.102 648 ;
    END
  END t_s[176]
  PIN t_s[177]
    DIRECTION OUTPUT ;
    USE SIGNAL ;
    PORT
      LAYER M5 ;
        RECT  96.384 647.916 96.408 648 ;
    END
  END t_s[177]
  PIN t_s[178]
    DIRECTION OUTPUT ;
    USE SIGNAL ;
    PORT
      LAYER M3 ;
        RECT  96.696 647.962 96.714 648 ;
    END
  END t_s[178]
  PIN t_s[179]
    DIRECTION OUTPUT ;
    USE SIGNAL ;
    PORT
      LAYER M5 ;
        RECT  96.96 647.916 96.984 648 ;
    END
  END t_s[179]
  PIN t_s[17]
    DIRECTION OUTPUT ;
    USE SIGNAL ;
    PORT
      LAYER M5 ;
        RECT  48.432 647.916 48.456 648 ;
    END
  END t_s[17]
  PIN t_s[180]
    DIRECTION OUTPUT ;
    USE SIGNAL ;
    PORT
      LAYER M3 ;
        RECT  97.272 647.962 97.29 648 ;
    END
  END t_s[180]
  PIN t_s[181]
    DIRECTION OUTPUT ;
    USE SIGNAL ;
    PORT
      LAYER M5 ;
        RECT  97.584 647.916 97.608 648 ;
    END
  END t_s[181]
  PIN t_s[182]
    DIRECTION OUTPUT ;
    USE SIGNAL ;
    PORT
      LAYER M3 ;
        RECT  97.884 647.962 97.902 648 ;
    END
  END t_s[182]
  PIN t_s[183]
    DIRECTION OUTPUT ;
    USE SIGNAL ;
    PORT
      LAYER M5 ;
        RECT  98.16 647.916 98.184 648 ;
    END
  END t_s[183]
  PIN t_s[184]
    DIRECTION OUTPUT ;
    USE SIGNAL ;
    PORT
      LAYER M3 ;
        RECT  98.46 647.962 98.478 648 ;
    END
  END t_s[184]
  PIN t_s[185]
    DIRECTION OUTPUT ;
    USE SIGNAL ;
    PORT
      LAYER M5 ;
        RECT  98.784 647.916 98.808 648 ;
    END
  END t_s[185]
  PIN t_s[186]
    DIRECTION OUTPUT ;
    USE SIGNAL ;
    PORT
      LAYER M3 ;
        RECT  99.072 647.962 99.09 648 ;
    END
  END t_s[186]
  PIN t_s[187]
    DIRECTION OUTPUT ;
    USE SIGNAL ;
    PORT
      LAYER M5 ;
        RECT  99.36 647.916 99.384 648 ;
    END
  END t_s[187]
  PIN t_s[188]
    DIRECTION OUTPUT ;
    USE SIGNAL ;
    PORT
      LAYER M3 ;
        RECT  99.684 647.962 99.702 648 ;
    END
  END t_s[188]
  PIN t_s[189]
    DIRECTION OUTPUT ;
    USE SIGNAL ;
    PORT
      LAYER M5 ;
        RECT  99.984 647.916 100.008 648 ;
    END
  END t_s[189]
  PIN t_s[18]
    DIRECTION OUTPUT ;
    USE SIGNAL ;
    PORT
      LAYER M3 ;
        RECT  48.744 647.962 48.762 648 ;
    END
  END t_s[18]
  PIN t_s[190]
    DIRECTION OUTPUT ;
    USE SIGNAL ;
    PORT
      LAYER M3 ;
        RECT  100.26 647.962 100.278 648 ;
    END
  END t_s[190]
  PIN t_s[191]
    DIRECTION OUTPUT ;
    USE SIGNAL ;
    PORT
      LAYER M5 ;
        RECT  100.56 647.916 100.584 648 ;
    END
  END t_s[191]
  PIN t_s[192]
    DIRECTION OUTPUT ;
    USE SIGNAL ;
    PORT
      LAYER M3 ;
        RECT  100.872 647.962 100.89 648 ;
    END
  END t_s[192]
  PIN t_s[193]
    DIRECTION OUTPUT ;
    USE SIGNAL ;
    PORT
      LAYER M5 ;
        RECT  101.184 647.916 101.208 648 ;
    END
  END t_s[193]
  PIN t_s[194]
    DIRECTION OUTPUT ;
    USE SIGNAL ;
    PORT
      LAYER M3 ;
        RECT  101.484 647.962 101.502 648 ;
    END
  END t_s[194]
  PIN t_s[195]
    DIRECTION OUTPUT ;
    USE SIGNAL ;
    PORT
      LAYER M5 ;
        RECT  101.76 647.916 101.784 648 ;
    END
  END t_s[195]
  PIN t_s[196]
    DIRECTION OUTPUT ;
    USE SIGNAL ;
    PORT
      LAYER M3 ;
        RECT  102.06 647.962 102.078 648 ;
    END
  END t_s[196]
  PIN t_s[197]
    DIRECTION OUTPUT ;
    USE SIGNAL ;
    PORT
      LAYER M5 ;
        RECT  102.384 647.916 102.408 648 ;
    END
  END t_s[197]
  PIN t_s[198]
    DIRECTION OUTPUT ;
    USE SIGNAL ;
    PORT
      LAYER M3 ;
        RECT  102.672 647.962 102.69 648 ;
    END
  END t_s[198]
  PIN t_s[199]
    DIRECTION OUTPUT ;
    USE SIGNAL ;
    PORT
      LAYER M5 ;
        RECT  102.96 647.916 102.984 648 ;
    END
  END t_s[199]
  PIN t_s[19]
    DIRECTION OUTPUT ;
    USE SIGNAL ;
    PORT
      LAYER M5 ;
        RECT  49.008 647.916 49.032 648 ;
    END
  END t_s[19]
  PIN t_s[1]
    DIRECTION OUTPUT ;
    USE SIGNAL ;
    PORT
      LAYER M5 ;
        RECT  43.632 647.916 43.656 648 ;
    END
  END t_s[1]
  PIN t_s[200]
    DIRECTION OUTPUT ;
    USE SIGNAL ;
    PORT
      LAYER M3 ;
        RECT  103.284 647.962 103.302 648 ;
    END
  END t_s[200]
  PIN t_s[201]
    DIRECTION OUTPUT ;
    USE SIGNAL ;
    PORT
      LAYER M5 ;
        RECT  103.584 647.916 103.608 648 ;
    END
  END t_s[201]
  PIN t_s[202]
    DIRECTION OUTPUT ;
    USE SIGNAL ;
    PORT
      LAYER M3 ;
        RECT  103.86 647.962 103.878 648 ;
    END
  END t_s[202]
  PIN t_s[203]
    DIRECTION OUTPUT ;
    USE SIGNAL ;
    PORT
      LAYER M5 ;
        RECT  104.16 647.916 104.184 648 ;
    END
  END t_s[203]
  PIN t_s[204]
    DIRECTION OUTPUT ;
    USE SIGNAL ;
    PORT
      LAYER M3 ;
        RECT  104.472 647.962 104.49 648 ;
    END
  END t_s[204]
  PIN t_s[205]
    DIRECTION OUTPUT ;
    USE SIGNAL ;
    PORT
      LAYER M5 ;
        RECT  104.784 647.916 104.808 648 ;
    END
  END t_s[205]
  PIN t_s[206]
    DIRECTION OUTPUT ;
    USE SIGNAL ;
    PORT
      LAYER M3 ;
        RECT  105.084 647.962 105.102 648 ;
    END
  END t_s[206]
  PIN t_s[207]
    DIRECTION OUTPUT ;
    USE SIGNAL ;
    PORT
      LAYER M5 ;
        RECT  105.36 647.916 105.384 648 ;
    END
  END t_s[207]
  PIN t_s[208]
    DIRECTION OUTPUT ;
    USE SIGNAL ;
    PORT
      LAYER M3 ;
        RECT  105.66 647.962 105.678 648 ;
    END
  END t_s[208]
  PIN t_s[209]
    DIRECTION OUTPUT ;
    USE SIGNAL ;
    PORT
      LAYER M5 ;
        RECT  105.984 647.916 106.008 648 ;
    END
  END t_s[209]
  PIN t_s[20]
    DIRECTION OUTPUT ;
    USE SIGNAL ;
    PORT
      LAYER M3 ;
        RECT  49.32 647.962 49.338 648 ;
    END
  END t_s[20]
  PIN t_s[210]
    DIRECTION OUTPUT ;
    USE SIGNAL ;
    PORT
      LAYER M3 ;
        RECT  106.272 647.962 106.29 648 ;
    END
  END t_s[210]
  PIN t_s[211]
    DIRECTION OUTPUT ;
    USE SIGNAL ;
    PORT
      LAYER M5 ;
        RECT  106.56 647.916 106.584 648 ;
    END
  END t_s[211]
  PIN t_s[212]
    DIRECTION OUTPUT ;
    USE SIGNAL ;
    PORT
      LAYER M3 ;
        RECT  106.884 647.962 106.902 648 ;
    END
  END t_s[212]
  PIN t_s[213]
    DIRECTION OUTPUT ;
    USE SIGNAL ;
    PORT
      LAYER M5 ;
        RECT  107.184 647.916 107.208 648 ;
    END
  END t_s[213]
  PIN t_s[214]
    DIRECTION OUTPUT ;
    USE SIGNAL ;
    PORT
      LAYER M3 ;
        RECT  107.46 647.962 107.478 648 ;
    END
  END t_s[214]
  PIN t_s[215]
    DIRECTION OUTPUT ;
    USE SIGNAL ;
    PORT
      LAYER M5 ;
        RECT  107.76 647.916 107.784 648 ;
    END
  END t_s[215]
  PIN t_s[216]
    DIRECTION OUTPUT ;
    USE SIGNAL ;
    PORT
      LAYER M3 ;
        RECT  108.072 647.962 108.09 648 ;
    END
  END t_s[216]
  PIN t_s[217]
    DIRECTION OUTPUT ;
    USE SIGNAL ;
    PORT
      LAYER M5 ;
        RECT  108.384 647.916 108.408 648 ;
    END
  END t_s[217]
  PIN t_s[218]
    DIRECTION OUTPUT ;
    USE SIGNAL ;
    PORT
      LAYER M3 ;
        RECT  108.648 647.962 108.666 648 ;
    END
  END t_s[218]
  PIN t_s[219]
    DIRECTION OUTPUT ;
    USE SIGNAL ;
    PORT
      LAYER M5 ;
        RECT  108.96 647.916 108.984 648 ;
    END
  END t_s[219]
  PIN t_s[21]
    DIRECTION OUTPUT ;
    USE SIGNAL ;
    PORT
      LAYER M5 ;
        RECT  49.632 647.916 49.656 648 ;
    END
  END t_s[21]
  PIN t_s[220]
    DIRECTION OUTPUT ;
    USE SIGNAL ;
    PORT
      LAYER M3 ;
        RECT  109.26 647.962 109.278 648 ;
    END
  END t_s[220]
  PIN t_s[221]
    DIRECTION OUTPUT ;
    USE SIGNAL ;
    PORT
      LAYER M5 ;
        RECT  109.584 647.916 109.608 648 ;
    END
  END t_s[221]
  PIN t_s[222]
    DIRECTION OUTPUT ;
    USE SIGNAL ;
    PORT
      LAYER M3 ;
        RECT  109.872 647.962 109.89 648 ;
    END
  END t_s[222]
  PIN t_s[223]
    DIRECTION OUTPUT ;
    USE SIGNAL ;
    PORT
      LAYER M5 ;
        RECT  110.16 647.916 110.184 648 ;
    END
  END t_s[223]
  PIN t_s[224]
    DIRECTION OUTPUT ;
    USE SIGNAL ;
    PORT
      LAYER M3 ;
        RECT  110.448 647.962 110.466 648 ;
    END
  END t_s[224]
  PIN t_s[225]
    DIRECTION OUTPUT ;
    USE SIGNAL ;
    PORT
      LAYER M5 ;
        RECT  110.784 647.916 110.808 648 ;
    END
  END t_s[225]
  PIN t_s[226]
    DIRECTION OUTPUT ;
    USE SIGNAL ;
    PORT
      LAYER M3 ;
        RECT  111.06 647.962 111.078 648 ;
    END
  END t_s[226]
  PIN t_s[227]
    DIRECTION OUTPUT ;
    USE SIGNAL ;
    PORT
      LAYER M5 ;
        RECT  111.36 647.916 111.384 648 ;
    END
  END t_s[227]
  PIN t_s[228]
    DIRECTION OUTPUT ;
    USE SIGNAL ;
    PORT
      LAYER M3 ;
        RECT  111.672 647.962 111.69 648 ;
    END
  END t_s[228]
  PIN t_s[229]
    DIRECTION OUTPUT ;
    USE SIGNAL ;
    PORT
      LAYER M5 ;
        RECT  111.936 647.916 111.96 648 ;
    END
  END t_s[229]
  PIN t_s[22]
    DIRECTION OUTPUT ;
    USE SIGNAL ;
    PORT
      LAYER M3 ;
        RECT  49.932 647.962 49.95 648 ;
    END
  END t_s[22]
  PIN t_s[230]
    DIRECTION OUTPUT ;
    USE SIGNAL ;
    PORT
      LAYER M3 ;
        RECT  112.248 647.962 112.266 648 ;
    END
  END t_s[230]
  PIN t_s[231]
    DIRECTION OUTPUT ;
    USE SIGNAL ;
    PORT
      LAYER M5 ;
        RECT  112.56 647.916 112.584 648 ;
    END
  END t_s[231]
  PIN t_s[232]
    DIRECTION OUTPUT ;
    USE SIGNAL ;
    PORT
      LAYER M3 ;
        RECT  112.86 647.962 112.878 648 ;
    END
  END t_s[232]
  PIN t_s[233]
    DIRECTION OUTPUT ;
    USE SIGNAL ;
    PORT
      LAYER M5 ;
        RECT  113.136 647.916 113.16 648 ;
    END
  END t_s[233]
  PIN t_s[234]
    DIRECTION OUTPUT ;
    USE SIGNAL ;
    PORT
      LAYER M3 ;
        RECT  113.472 647.962 113.49 648 ;
    END
  END t_s[234]
  PIN t_s[235]
    DIRECTION OUTPUT ;
    USE SIGNAL ;
    PORT
      LAYER M5 ;
        RECT  113.76 647.916 113.784 648 ;
    END
  END t_s[235]
  PIN t_s[236]
    DIRECTION OUTPUT ;
    USE SIGNAL ;
    PORT
      LAYER M3 ;
        RECT  114.048 647.962 114.066 648 ;
    END
  END t_s[236]
  PIN t_s[237]
    DIRECTION OUTPUT ;
    USE SIGNAL ;
    PORT
      LAYER M5 ;
        RECT  114.336 647.916 114.36 648 ;
    END
  END t_s[237]
  PIN t_s[238]
    DIRECTION OUTPUT ;
    USE SIGNAL ;
    PORT
      LAYER M3 ;
        RECT  114.66 647.962 114.678 648 ;
    END
  END t_s[238]
  PIN t_s[239]
    DIRECTION OUTPUT ;
    USE SIGNAL ;
    PORT
      LAYER M5 ;
        RECT  114.96 647.916 114.984 648 ;
    END
  END t_s[239]
  PIN t_s[23]
    DIRECTION OUTPUT ;
    USE SIGNAL ;
    PORT
      LAYER M5 ;
        RECT  50.208 647.916 50.232 648 ;
    END
  END t_s[23]
  PIN t_s[240]
    DIRECTION OUTPUT ;
    USE SIGNAL ;
    PORT
      LAYER M3 ;
        RECT  115.272 647.962 115.29 648 ;
    END
  END t_s[240]
  PIN t_s[241]
    DIRECTION OUTPUT ;
    USE SIGNAL ;
    PORT
      LAYER M5 ;
        RECT  115.536 647.916 115.56 648 ;
    END
  END t_s[241]
  PIN t_s[242]
    DIRECTION OUTPUT ;
    USE SIGNAL ;
    PORT
      LAYER M3 ;
        RECT  115.848 647.962 115.866 648 ;
    END
  END t_s[242]
  PIN t_s[243]
    DIRECTION OUTPUT ;
    USE SIGNAL ;
    PORT
      LAYER M5 ;
        RECT  116.16 647.916 116.184 648 ;
    END
  END t_s[243]
  PIN t_s[244]
    DIRECTION OUTPUT ;
    USE SIGNAL ;
    PORT
      LAYER M3 ;
        RECT  116.46 647.962 116.478 648 ;
    END
  END t_s[244]
  PIN t_s[245]
    DIRECTION OUTPUT ;
    USE SIGNAL ;
    PORT
      LAYER M5 ;
        RECT  116.736 647.916 116.76 648 ;
    END
  END t_s[245]
  PIN t_s[246]
    DIRECTION OUTPUT ;
    USE SIGNAL ;
    PORT
      LAYER M3 ;
        RECT  117.072 647.962 117.09 648 ;
    END
  END t_s[246]
  PIN t_s[247]
    DIRECTION OUTPUT ;
    USE SIGNAL ;
    PORT
      LAYER M5 ;
        RECT  117.36 647.916 117.384 648 ;
    END
  END t_s[247]
  PIN t_s[248]
    DIRECTION OUTPUT ;
    USE SIGNAL ;
    PORT
      LAYER M3 ;
        RECT  117.648 647.962 117.666 648 ;
    END
  END t_s[248]
  PIN t_s[249]
    DIRECTION OUTPUT ;
    USE SIGNAL ;
    PORT
      LAYER M5 ;
        RECT  117.936 647.916 117.96 648 ;
    END
  END t_s[249]
  PIN t_s[24]
    DIRECTION OUTPUT ;
    USE SIGNAL ;
    PORT
      LAYER M3 ;
        RECT  50.544 647.962 50.562 648 ;
    END
  END t_s[24]
  PIN t_s[250]
    DIRECTION OUTPUT ;
    USE SIGNAL ;
    PORT
      LAYER M3 ;
        RECT  118.26 647.962 118.278 648 ;
    END
  END t_s[250]
  PIN t_s[251]
    DIRECTION OUTPUT ;
    USE SIGNAL ;
    PORT
      LAYER M5 ;
        RECT  118.56 647.916 118.584 648 ;
    END
  END t_s[251]
  PIN t_s[252]
    DIRECTION OUTPUT ;
    USE SIGNAL ;
    PORT
      LAYER M3 ;
        RECT  118.836 647.962 118.854 648 ;
    END
  END t_s[252]
  PIN t_s[253]
    DIRECTION OUTPUT ;
    USE SIGNAL ;
    PORT
      LAYER M5 ;
        RECT  119.136 647.916 119.16 648 ;
    END
  END t_s[253]
  PIN t_s[254]
    DIRECTION OUTPUT ;
    USE SIGNAL ;
    PORT
      LAYER M3 ;
        RECT  119.448 647.962 119.466 648 ;
    END
  END t_s[254]
  PIN t_s[255]
    DIRECTION OUTPUT ;
    USE SIGNAL ;
    PORT
      LAYER M5 ;
        RECT  119.76 647.916 119.784 648 ;
    END
  END t_s[255]
  PIN t_s[256]
    DIRECTION OUTPUT ;
    USE SIGNAL ;
    PORT
      LAYER M3 ;
        RECT  120.06 647.962 120.078 648 ;
    END
  END t_s[256]
  PIN t_s[257]
    DIRECTION OUTPUT ;
    USE SIGNAL ;
    PORT
      LAYER M5 ;
        RECT  120.336 647.916 120.36 648 ;
    END
  END t_s[257]
  PIN t_s[258]
    DIRECTION OUTPUT ;
    USE SIGNAL ;
    PORT
      LAYER M3 ;
        RECT  120.636 647.962 120.654 648 ;
    END
  END t_s[258]
  PIN t_s[259]
    DIRECTION OUTPUT ;
    USE SIGNAL ;
    PORT
      LAYER M5 ;
        RECT  120.96 647.916 120.984 648 ;
    END
  END t_s[259]
  PIN t_s[25]
    DIRECTION OUTPUT ;
    USE SIGNAL ;
    PORT
      LAYER M5 ;
        RECT  50.832 647.916 50.856 648 ;
    END
  END t_s[25]
  PIN t_s[260]
    DIRECTION OUTPUT ;
    USE SIGNAL ;
    PORT
      LAYER M3 ;
        RECT  121.248 647.962 121.266 648 ;
    END
  END t_s[260]
  PIN t_s[261]
    DIRECTION OUTPUT ;
    USE SIGNAL ;
    PORT
      LAYER M5 ;
        RECT  121.536 647.916 121.56 648 ;
    END
  END t_s[261]
  PIN t_s[262]
    DIRECTION OUTPUT ;
    USE SIGNAL ;
    PORT
      LAYER M3 ;
        RECT  121.86 647.962 121.878 648 ;
    END
  END t_s[262]
  PIN t_s[263]
    DIRECTION OUTPUT ;
    USE SIGNAL ;
    PORT
      LAYER M5 ;
        RECT  122.16 647.916 122.184 648 ;
    END
  END t_s[263]
  PIN t_s[264]
    DIRECTION OUTPUT ;
    USE SIGNAL ;
    PORT
      LAYER M3 ;
        RECT  122.436 647.962 122.454 648 ;
    END
  END t_s[264]
  PIN t_s[265]
    DIRECTION OUTPUT ;
    USE SIGNAL ;
    PORT
      LAYER M5 ;
        RECT  122.736 647.916 122.76 648 ;
    END
  END t_s[265]
  PIN t_s[266]
    DIRECTION OUTPUT ;
    USE SIGNAL ;
    PORT
      LAYER M3 ;
        RECT  123.048 647.962 123.066 648 ;
    END
  END t_s[266]
  PIN t_s[267]
    DIRECTION OUTPUT ;
    USE SIGNAL ;
    PORT
      LAYER M5 ;
        RECT  123.36 647.916 123.384 648 ;
    END
  END t_s[267]
  PIN t_s[268]
    DIRECTION OUTPUT ;
    USE SIGNAL ;
    PORT
      LAYER M3 ;
        RECT  123.66 647.962 123.678 648 ;
    END
  END t_s[268]
  PIN t_s[269]
    DIRECTION OUTPUT ;
    USE SIGNAL ;
    PORT
      LAYER M5 ;
        RECT  123.936 647.916 123.96 648 ;
    END
  END t_s[269]
  PIN t_s[26]
    DIRECTION OUTPUT ;
    USE SIGNAL ;
    PORT
      LAYER M3 ;
        RECT  51.12 647.962 51.138 648 ;
    END
  END t_s[26]
  PIN t_s[270]
    DIRECTION OUTPUT ;
    USE SIGNAL ;
    PORT
      LAYER M3 ;
        RECT  124.236 647.962 124.254 648 ;
    END
  END t_s[270]
  PIN t_s[271]
    DIRECTION OUTPUT ;
    USE SIGNAL ;
    PORT
      LAYER M5 ;
        RECT  124.56 647.916 124.584 648 ;
    END
  END t_s[271]
  PIN t_s[272]
    DIRECTION OUTPUT ;
    USE SIGNAL ;
    PORT
      LAYER M3 ;
        RECT  124.848 647.962 124.866 648 ;
    END
  END t_s[272]
  PIN t_s[273]
    DIRECTION OUTPUT ;
    USE SIGNAL ;
    PORT
      LAYER M5 ;
        RECT  125.136 647.916 125.16 648 ;
    END
  END t_s[273]
  PIN t_s[274]
    DIRECTION OUTPUT ;
    USE SIGNAL ;
    PORT
      LAYER M3 ;
        RECT  125.46 647.962 125.478 648 ;
    END
  END t_s[274]
  PIN t_s[275]
    DIRECTION OUTPUT ;
    USE SIGNAL ;
    PORT
      LAYER M5 ;
        RECT  125.76 647.916 125.784 648 ;
    END
  END t_s[275]
  PIN t_s[276]
    DIRECTION OUTPUT ;
    USE SIGNAL ;
    PORT
      LAYER M3 ;
        RECT  126.036 647.962 126.054 648 ;
    END
  END t_s[276]
  PIN t_s[277]
    DIRECTION OUTPUT ;
    USE SIGNAL ;
    PORT
      LAYER M5 ;
        RECT  126.336 647.916 126.36 648 ;
    END
  END t_s[277]
  PIN t_s[278]
    DIRECTION OUTPUT ;
    USE SIGNAL ;
    PORT
      LAYER M3 ;
        RECT  126.648 647.962 126.666 648 ;
    END
  END t_s[278]
  PIN t_s[279]
    DIRECTION OUTPUT ;
    USE SIGNAL ;
    PORT
      LAYER M5 ;
        RECT  126.96 647.916 126.984 648 ;
    END
  END t_s[279]
  PIN t_s[27]
    DIRECTION OUTPUT ;
    USE SIGNAL ;
    PORT
      LAYER M5 ;
        RECT  51.408 647.916 51.432 648 ;
    END
  END t_s[27]
  PIN t_s[280]
    DIRECTION OUTPUT ;
    USE SIGNAL ;
    PORT
      LAYER M3 ;
        RECT  127.26 647.962 127.278 648 ;
    END
  END t_s[280]
  PIN t_s[281]
    DIRECTION OUTPUT ;
    USE SIGNAL ;
    PORT
      LAYER M5 ;
        RECT  127.536 647.916 127.56 648 ;
    END
  END t_s[281]
  PIN t_s[282]
    DIRECTION OUTPUT ;
    USE SIGNAL ;
    PORT
      LAYER M3 ;
        RECT  127.836 647.962 127.854 648 ;
    END
  END t_s[282]
  PIN t_s[283]
    DIRECTION OUTPUT ;
    USE SIGNAL ;
    PORT
      LAYER M5 ;
        RECT  128.16 647.916 128.184 648 ;
    END
  END t_s[283]
  PIN t_s[284]
    DIRECTION OUTPUT ;
    USE SIGNAL ;
    PORT
      LAYER M3 ;
        RECT  128.448 647.962 128.466 648 ;
    END
  END t_s[284]
  PIN t_s[285]
    DIRECTION OUTPUT ;
    USE SIGNAL ;
    PORT
      LAYER M5 ;
        RECT  128.736 647.916 128.76 648 ;
    END
  END t_s[285]
  PIN t_s[286]
    DIRECTION OUTPUT ;
    USE SIGNAL ;
    PORT
      LAYER M3 ;
        RECT  129.06 647.962 129.078 648 ;
    END
  END t_s[286]
  PIN t_s[287]
    DIRECTION OUTPUT ;
    USE SIGNAL ;
    PORT
      LAYER M5 ;
        RECT  129.36 647.916 129.384 648 ;
    END
  END t_s[287]
  PIN t_s[288]
    DIRECTION OUTPUT ;
    USE SIGNAL ;
    PORT
      LAYER M3 ;
        RECT  129.636 647.962 129.654 648 ;
    END
  END t_s[288]
  PIN t_s[289]
    DIRECTION OUTPUT ;
    USE SIGNAL ;
    PORT
      LAYER M5 ;
        RECT  129.936 647.916 129.96 648 ;
    END
  END t_s[289]
  PIN t_s[28]
    DIRECTION OUTPUT ;
    USE SIGNAL ;
    PORT
      LAYER M3 ;
        RECT  51.732 647.962 51.75 648 ;
    END
  END t_s[28]
  PIN t_s[290]
    DIRECTION OUTPUT ;
    USE SIGNAL ;
    PORT
      LAYER M3 ;
        RECT  130.248 647.962 130.266 648 ;
    END
  END t_s[290]
  PIN t_s[291]
    DIRECTION OUTPUT ;
    USE SIGNAL ;
    PORT
      LAYER M5 ;
        RECT  130.56 647.916 130.584 648 ;
    END
  END t_s[291]
  PIN t_s[292]
    DIRECTION OUTPUT ;
    USE SIGNAL ;
    PORT
      LAYER M3 ;
        RECT  130.824 647.962 130.842 648 ;
    END
  END t_s[292]
  PIN t_s[293]
    DIRECTION OUTPUT ;
    USE SIGNAL ;
    PORT
      LAYER M5 ;
        RECT  131.136 647.916 131.16 648 ;
    END
  END t_s[293]
  PIN t_s[294]
    DIRECTION OUTPUT ;
    USE SIGNAL ;
    PORT
      LAYER M3 ;
        RECT  131.436 647.962 131.454 648 ;
    END
  END t_s[294]
  PIN t_s[295]
    DIRECTION OUTPUT ;
    USE SIGNAL ;
    PORT
      LAYER M5 ;
        RECT  131.76 647.916 131.784 648 ;
    END
  END t_s[295]
  PIN t_s[296]
    DIRECTION OUTPUT ;
    USE SIGNAL ;
    PORT
      LAYER M3 ;
        RECT  132.048 647.962 132.066 648 ;
    END
  END t_s[296]
  PIN t_s[297]
    DIRECTION OUTPUT ;
    USE SIGNAL ;
    PORT
      LAYER M5 ;
        RECT  132.336 647.916 132.36 648 ;
    END
  END t_s[297]
  PIN t_s[298]
    DIRECTION OUTPUT ;
    USE SIGNAL ;
    PORT
      LAYER M3 ;
        RECT  132.624 647.962 132.642 648 ;
    END
  END t_s[298]
  PIN t_s[299]
    DIRECTION OUTPUT ;
    USE SIGNAL ;
    PORT
      LAYER M5 ;
        RECT  132.912 647.916 132.936 648 ;
    END
  END t_s[299]
  PIN t_s[29]
    DIRECTION OUTPUT ;
    USE SIGNAL ;
    PORT
      LAYER M5 ;
        RECT  52.032 647.916 52.056 648 ;
    END
  END t_s[29]
  PIN t_s[2]
    DIRECTION OUTPUT ;
    USE SIGNAL ;
    PORT
      LAYER M3 ;
        RECT  43.956 647.962 43.974 648 ;
    END
  END t_s[2]
  PIN t_s[300]
    DIRECTION OUTPUT ;
    USE SIGNAL ;
    PORT
      LAYER M3 ;
        RECT  133.236 647.962 133.254 648 ;
    END
  END t_s[300]
  PIN t_s[301]
    DIRECTION OUTPUT ;
    USE SIGNAL ;
    PORT
      LAYER M5 ;
        RECT  133.536 647.916 133.56 648 ;
    END
  END t_s[301]
  PIN t_s[302]
    DIRECTION OUTPUT ;
    USE SIGNAL ;
    PORT
      LAYER M3 ;
        RECT  133.848 647.962 133.866 648 ;
    END
  END t_s[302]
  PIN t_s[303]
    DIRECTION OUTPUT ;
    USE SIGNAL ;
    PORT
      LAYER M5 ;
        RECT  134.112 647.916 134.136 648 ;
    END
  END t_s[303]
  PIN t_s[304]
    DIRECTION OUTPUT ;
    USE SIGNAL ;
    PORT
      LAYER M3 ;
        RECT  134.424 647.962 134.442 648 ;
    END
  END t_s[304]
  PIN t_s[305]
    DIRECTION OUTPUT ;
    USE SIGNAL ;
    PORT
      LAYER M5 ;
        RECT  134.736 647.916 134.76 648 ;
    END
  END t_s[305]
  PIN t_s[306]
    DIRECTION OUTPUT ;
    USE SIGNAL ;
    PORT
      LAYER M3 ;
        RECT  135.036 647.962 135.054 648 ;
    END
  END t_s[306]
  PIN t_s[307]
    DIRECTION OUTPUT ;
    USE SIGNAL ;
    PORT
      LAYER M5 ;
        RECT  135.312 647.916 135.336 648 ;
    END
  END t_s[307]
  PIN t_s[308]
    DIRECTION OUTPUT ;
    USE SIGNAL ;
    PORT
      LAYER M3 ;
        RECT  135.648 647.962 135.666 648 ;
    END
  END t_s[308]
  PIN t_s[309]
    DIRECTION OUTPUT ;
    USE SIGNAL ;
    PORT
      LAYER M5 ;
        RECT  135.936 647.916 135.96 648 ;
    END
  END t_s[309]
  PIN t_s[30]
    DIRECTION OUTPUT ;
    USE SIGNAL ;
    PORT
      LAYER M3 ;
        RECT  52.344 647.962 52.362 648 ;
    END
  END t_s[30]
  PIN t_s[310]
    DIRECTION OUTPUT ;
    USE SIGNAL ;
    PORT
      LAYER M3 ;
        RECT  136.224 647.962 136.242 648 ;
    END
  END t_s[310]
  PIN t_s[311]
    DIRECTION OUTPUT ;
    USE SIGNAL ;
    PORT
      LAYER M5 ;
        RECT  136.512 647.916 136.536 648 ;
    END
  END t_s[311]
  PIN t_s[312]
    DIRECTION OUTPUT ;
    USE SIGNAL ;
    PORT
      LAYER M3 ;
        RECT  136.836 647.962 136.854 648 ;
    END
  END t_s[312]
  PIN t_s[313]
    DIRECTION OUTPUT ;
    USE SIGNAL ;
    PORT
      LAYER M5 ;
        RECT  137.136 647.916 137.16 648 ;
    END
  END t_s[313]
  PIN t_s[314]
    DIRECTION OUTPUT ;
    USE SIGNAL ;
    PORT
      LAYER M3 ;
        RECT  137.448 647.962 137.466 648 ;
    END
  END t_s[314]
  PIN t_s[315]
    DIRECTION OUTPUT ;
    USE SIGNAL ;
    PORT
      LAYER M5 ;
        RECT  137.712 647.916 137.736 648 ;
    END
  END t_s[315]
  PIN t_s[316]
    DIRECTION OUTPUT ;
    USE SIGNAL ;
    PORT
      LAYER M3 ;
        RECT  138.024 647.962 138.042 648 ;
    END
  END t_s[316]
  PIN t_s[317]
    DIRECTION OUTPUT ;
    USE SIGNAL ;
    PORT
      LAYER M5 ;
        RECT  138.336 647.916 138.36 648 ;
    END
  END t_s[317]
  PIN t_s[318]
    DIRECTION OUTPUT ;
    USE SIGNAL ;
    PORT
      LAYER M3 ;
        RECT  138.636 647.962 138.654 648 ;
    END
  END t_s[318]
  PIN t_s[319]
    DIRECTION OUTPUT ;
    USE SIGNAL ;
    PORT
      LAYER M5 ;
        RECT  138.912 647.916 138.936 648 ;
    END
  END t_s[319]
  PIN t_s[31]
    DIRECTION OUTPUT ;
    USE SIGNAL ;
    PORT
      LAYER M5 ;
        RECT  52.608 647.916 52.632 648 ;
    END
  END t_s[31]
  PIN t_s[320]
    DIRECTION OUTPUT ;
    USE SIGNAL ;
    PORT
      LAYER M3 ;
        RECT  139.248 647.962 139.266 648 ;
    END
  END t_s[320]
  PIN t_s[321]
    DIRECTION OUTPUT ;
    USE SIGNAL ;
    PORT
      LAYER M5 ;
        RECT  139.536 647.916 139.56 648 ;
    END
  END t_s[321]
  PIN t_s[322]
    DIRECTION OUTPUT ;
    USE SIGNAL ;
    PORT
      LAYER M3 ;
        RECT  139.824 647.962 139.842 648 ;
    END
  END t_s[322]
  PIN t_s[323]
    DIRECTION OUTPUT ;
    USE SIGNAL ;
    PORT
      LAYER M5 ;
        RECT  140.112 647.916 140.136 648 ;
    END
  END t_s[323]
  PIN t_s[324]
    DIRECTION OUTPUT ;
    USE SIGNAL ;
    PORT
      LAYER M3 ;
        RECT  140.436 647.962 140.454 648 ;
    END
  END t_s[324]
  PIN t_s[325]
    DIRECTION OUTPUT ;
    USE SIGNAL ;
    PORT
      LAYER M5 ;
        RECT  140.736 647.916 140.76 648 ;
    END
  END t_s[325]
  PIN t_s[326]
    DIRECTION OUTPUT ;
    USE SIGNAL ;
    PORT
      LAYER M3 ;
        RECT  141.012 647.962 141.03 648 ;
    END
  END t_s[326]
  PIN t_s[327]
    DIRECTION OUTPUT ;
    USE SIGNAL ;
    PORT
      LAYER M5 ;
        RECT  141.312 647.916 141.336 648 ;
    END
  END t_s[327]
  PIN t_s[328]
    DIRECTION OUTPUT ;
    USE SIGNAL ;
    PORT
      LAYER M3 ;
        RECT  141.624 647.962 141.642 648 ;
    END
  END t_s[328]
  PIN t_s[329]
    DIRECTION OUTPUT ;
    USE SIGNAL ;
    PORT
      LAYER M5 ;
        RECT  141.936 647.916 141.96 648 ;
    END
  END t_s[329]
  PIN t_s[32]
    DIRECTION OUTPUT ;
    USE SIGNAL ;
    PORT
      LAYER M3 ;
        RECT  52.92 647.962 52.938 648 ;
    END
  END t_s[32]
  PIN t_s[330]
    DIRECTION OUTPUT ;
    USE SIGNAL ;
    PORT
      LAYER M3 ;
        RECT  142.236 647.962 142.254 648 ;
    END
  END t_s[330]
  PIN t_s[331]
    DIRECTION OUTPUT ;
    USE SIGNAL ;
    PORT
      LAYER M5 ;
        RECT  142.512 647.916 142.536 648 ;
    END
  END t_s[331]
  PIN t_s[332]
    DIRECTION OUTPUT ;
    USE SIGNAL ;
    PORT
      LAYER M3 ;
        RECT  142.812 647.962 142.83 648 ;
    END
  END t_s[332]
  PIN t_s[333]
    DIRECTION OUTPUT ;
    USE SIGNAL ;
    PORT
      LAYER M5 ;
        RECT  143.136 647.916 143.16 648 ;
    END
  END t_s[333]
  PIN t_s[334]
    DIRECTION OUTPUT ;
    USE SIGNAL ;
    PORT
      LAYER M3 ;
        RECT  143.424 647.962 143.442 648 ;
    END
  END t_s[334]
  PIN t_s[335]
    DIRECTION OUTPUT ;
    USE SIGNAL ;
    PORT
      LAYER M5 ;
        RECT  143.712 647.916 143.736 648 ;
    END
  END t_s[335]
  PIN t_s[336]
    DIRECTION OUTPUT ;
    USE SIGNAL ;
    PORT
      LAYER M3 ;
        RECT  144.036 647.962 144.054 648 ;
    END
  END t_s[336]
  PIN t_s[337]
    DIRECTION OUTPUT ;
    USE SIGNAL ;
    PORT
      LAYER M5 ;
        RECT  144.336 647.916 144.36 648 ;
    END
  END t_s[337]
  PIN t_s[338]
    DIRECTION OUTPUT ;
    USE SIGNAL ;
    PORT
      LAYER M3 ;
        RECT  144.612 647.962 144.63 648 ;
    END
  END t_s[338]
  PIN t_s[339]
    DIRECTION OUTPUT ;
    USE SIGNAL ;
    PORT
      LAYER M5 ;
        RECT  144.912 647.916 144.936 648 ;
    END
  END t_s[339]
  PIN t_s[33]
    DIRECTION OUTPUT ;
    USE SIGNAL ;
    PORT
      LAYER M5 ;
        RECT  53.232 647.916 53.256 648 ;
    END
  END t_s[33]
  PIN t_s[340]
    DIRECTION OUTPUT ;
    USE SIGNAL ;
    PORT
      LAYER M3 ;
        RECT  145.224 647.962 145.242 648 ;
    END
  END t_s[340]
  PIN t_s[341]
    DIRECTION OUTPUT ;
    USE SIGNAL ;
    PORT
      LAYER M5 ;
        RECT  145.536 647.916 145.56 648 ;
    END
  END t_s[341]
  PIN t_s[342]
    DIRECTION OUTPUT ;
    USE SIGNAL ;
    PORT
      LAYER M3 ;
        RECT  145.836 647.962 145.854 648 ;
    END
  END t_s[342]
  PIN t_s[343]
    DIRECTION OUTPUT ;
    USE SIGNAL ;
    PORT
      LAYER M5 ;
        RECT  146.112 647.916 146.136 648 ;
    END
  END t_s[343]
  PIN t_s[344]
    DIRECTION OUTPUT ;
    USE SIGNAL ;
    PORT
      LAYER M3 ;
        RECT  146.412 647.962 146.43 648 ;
    END
  END t_s[344]
  PIN t_s[345]
    DIRECTION OUTPUT ;
    USE SIGNAL ;
    PORT
      LAYER M5 ;
        RECT  146.736 647.916 146.76 648 ;
    END
  END t_s[345]
  PIN t_s[346]
    DIRECTION OUTPUT ;
    USE SIGNAL ;
    PORT
      LAYER M3 ;
        RECT  147.024 647.962 147.042 648 ;
    END
  END t_s[346]
  PIN t_s[347]
    DIRECTION OUTPUT ;
    USE SIGNAL ;
    PORT
      LAYER M5 ;
        RECT  147.312 647.916 147.336 648 ;
    END
  END t_s[347]
  PIN t_s[348]
    DIRECTION OUTPUT ;
    USE SIGNAL ;
    PORT
      LAYER M3 ;
        RECT  147.636 647.962 147.654 648 ;
    END
  END t_s[348]
  PIN t_s[349]
    DIRECTION OUTPUT ;
    USE SIGNAL ;
    PORT
      LAYER M5 ;
        RECT  147.936 647.916 147.96 648 ;
    END
  END t_s[349]
  PIN t_s[34]
    DIRECTION OUTPUT ;
    USE SIGNAL ;
    PORT
      LAYER M3 ;
        RECT  53.532 647.962 53.55 648 ;
    END
  END t_s[34]
  PIN t_s[350]
    DIRECTION OUTPUT ;
    USE SIGNAL ;
    PORT
      LAYER M3 ;
        RECT  148.212 647.962 148.23 648 ;
    END
  END t_s[350]
  PIN t_s[351]
    DIRECTION OUTPUT ;
    USE SIGNAL ;
    PORT
      LAYER M5 ;
        RECT  148.512 647.916 148.536 648 ;
    END
  END t_s[351]
  PIN t_s[352]
    DIRECTION OUTPUT ;
    USE SIGNAL ;
    PORT
      LAYER M3 ;
        RECT  148.824 647.962 148.842 648 ;
    END
  END t_s[352]
  PIN t_s[353]
    DIRECTION OUTPUT ;
    USE SIGNAL ;
    PORT
      LAYER M5 ;
        RECT  149.136 647.916 149.16 648 ;
    END
  END t_s[353]
  PIN t_s[354]
    DIRECTION OUTPUT ;
    USE SIGNAL ;
    PORT
      LAYER M3 ;
        RECT  149.436 647.962 149.454 648 ;
    END
  END t_s[354]
  PIN t_s[355]
    DIRECTION OUTPUT ;
    USE SIGNAL ;
    PORT
      LAYER M5 ;
        RECT  149.712 647.916 149.736 648 ;
    END
  END t_s[355]
  PIN t_s[356]
    DIRECTION OUTPUT ;
    USE SIGNAL ;
    PORT
      LAYER M3 ;
        RECT  150.012 647.962 150.03 648 ;
    END
  END t_s[356]
  PIN t_s[357]
    DIRECTION OUTPUT ;
    USE SIGNAL ;
    PORT
      LAYER M5 ;
        RECT  150.336 647.916 150.36 648 ;
    END
  END t_s[357]
  PIN t_s[358]
    DIRECTION OUTPUT ;
    USE SIGNAL ;
    PORT
      LAYER M3 ;
        RECT  150.624 647.962 150.642 648 ;
    END
  END t_s[358]
  PIN t_s[359]
    DIRECTION OUTPUT ;
    USE SIGNAL ;
    PORT
      LAYER M5 ;
        RECT  150.912 647.916 150.936 648 ;
    END
  END t_s[359]
  PIN t_s[35]
    DIRECTION OUTPUT ;
    USE SIGNAL ;
    PORT
      LAYER M5 ;
        RECT  53.808 647.916 53.832 648 ;
    END
  END t_s[35]
  PIN t_s[360]
    DIRECTION OUTPUT ;
    USE SIGNAL ;
    PORT
      LAYER M3 ;
        RECT  151.2 647.962 151.218 648 ;
    END
  END t_s[360]
  PIN t_s[361]
    DIRECTION OUTPUT ;
    USE SIGNAL ;
    PORT
      LAYER M5 ;
        RECT  151.536 647.916 151.56 648 ;
    END
  END t_s[361]
  PIN t_s[362]
    DIRECTION OUTPUT ;
    USE SIGNAL ;
    PORT
      LAYER M3 ;
        RECT  151.812 647.962 151.83 648 ;
    END
  END t_s[362]
  PIN t_s[363]
    DIRECTION OUTPUT ;
    USE SIGNAL ;
    PORT
      LAYER M5 ;
        RECT  152.112 647.916 152.136 648 ;
    END
  END t_s[363]
  PIN t_s[364]
    DIRECTION OUTPUT ;
    USE SIGNAL ;
    PORT
      LAYER M3 ;
        RECT  152.424 647.962 152.442 648 ;
    END
  END t_s[364]
  PIN t_s[365]
    DIRECTION OUTPUT ;
    USE SIGNAL ;
    PORT
      LAYER M5 ;
        RECT  152.688 647.916 152.712 648 ;
    END
  END t_s[365]
  PIN t_s[366]
    DIRECTION OUTPUT ;
    USE SIGNAL ;
    PORT
      LAYER M3 ;
        RECT  153 647.962 153.018 648 ;
    END
  END t_s[366]
  PIN t_s[367]
    DIRECTION OUTPUT ;
    USE SIGNAL ;
    PORT
      LAYER M5 ;
        RECT  153.312 647.916 153.336 648 ;
    END
  END t_s[367]
  PIN t_s[368]
    DIRECTION OUTPUT ;
    USE SIGNAL ;
    PORT
      LAYER M3 ;
        RECT  153.612 647.962 153.63 648 ;
    END
  END t_s[368]
  PIN t_s[369]
    DIRECTION OUTPUT ;
    USE SIGNAL ;
    PORT
      LAYER M5 ;
        RECT  153.888 647.916 153.912 648 ;
    END
  END t_s[369]
  PIN t_s[36]
    DIRECTION OUTPUT ;
    USE SIGNAL ;
    PORT
      LAYER M3 ;
        RECT  54.144 647.962 54.162 648 ;
    END
  END t_s[36]
  PIN t_s[370]
    DIRECTION OUTPUT ;
    USE SIGNAL ;
    PORT
      LAYER M3 ;
        RECT  154.224 647.962 154.242 648 ;
    END
  END t_s[370]
  PIN t_s[371]
    DIRECTION OUTPUT ;
    USE SIGNAL ;
    PORT
      LAYER M5 ;
        RECT  154.512 647.916 154.536 648 ;
    END
  END t_s[371]
  PIN t_s[372]
    DIRECTION OUTPUT ;
    USE SIGNAL ;
    PORT
      LAYER M3 ;
        RECT  154.8 647.962 154.818 648 ;
    END
  END t_s[372]
  PIN t_s[373]
    DIRECTION OUTPUT ;
    USE SIGNAL ;
    PORT
      LAYER M5 ;
        RECT  155.088 647.916 155.112 648 ;
    END
  END t_s[373]
  PIN t_s[374]
    DIRECTION OUTPUT ;
    USE SIGNAL ;
    PORT
      LAYER M3 ;
        RECT  155.412 647.962 155.43 648 ;
    END
  END t_s[374]
  PIN t_s[375]
    DIRECTION OUTPUT ;
    USE SIGNAL ;
    PORT
      LAYER M5 ;
        RECT  155.712 647.916 155.736 648 ;
    END
  END t_s[375]
  PIN t_s[376]
    DIRECTION OUTPUT ;
    USE SIGNAL ;
    PORT
      LAYER M3 ;
        RECT  156.024 647.962 156.042 648 ;
    END
  END t_s[376]
  PIN t_s[377]
    DIRECTION OUTPUT ;
    USE SIGNAL ;
    PORT
      LAYER M5 ;
        RECT  156.288 647.916 156.312 648 ;
    END
  END t_s[377]
  PIN t_s[378]
    DIRECTION OUTPUT ;
    USE SIGNAL ;
    PORT
      LAYER M3 ;
        RECT  156.6 647.962 156.618 648 ;
    END
  END t_s[378]
  PIN t_s[379]
    DIRECTION OUTPUT ;
    USE SIGNAL ;
    PORT
      LAYER M5 ;
        RECT  156.912 647.916 156.936 648 ;
    END
  END t_s[379]
  PIN t_s[37]
    DIRECTION OUTPUT ;
    USE SIGNAL ;
    PORT
      LAYER M5 ;
        RECT  54.432 647.916 54.456 648 ;
    END
  END t_s[37]
  PIN t_s[380]
    DIRECTION OUTPUT ;
    USE SIGNAL ;
    PORT
      LAYER M3 ;
        RECT  157.212 647.962 157.23 648 ;
    END
  END t_s[380]
  PIN t_s[381]
    DIRECTION OUTPUT ;
    USE SIGNAL ;
    PORT
      LAYER M5 ;
        RECT  157.488 647.916 157.512 648 ;
    END
  END t_s[381]
  PIN t_s[382]
    DIRECTION OUTPUT ;
    USE SIGNAL ;
    PORT
      LAYER M3 ;
        RECT  157.824 647.962 157.842 648 ;
    END
  END t_s[382]
  PIN t_s[383]
    DIRECTION OUTPUT ;
    USE SIGNAL ;
    PORT
      LAYER M5 ;
        RECT  158.112 647.916 158.136 648 ;
    END
  END t_s[383]
  PIN t_s[384]
    DIRECTION OUTPUT ;
    USE SIGNAL ;
    PORT
      LAYER M3 ;
        RECT  158.4 647.962 158.418 648 ;
    END
  END t_s[384]
  PIN t_s[385]
    DIRECTION OUTPUT ;
    USE SIGNAL ;
    PORT
      LAYER M5 ;
        RECT  158.688 647.916 158.712 648 ;
    END
  END t_s[385]
  PIN t_s[386]
    DIRECTION OUTPUT ;
    USE SIGNAL ;
    PORT
      LAYER M3 ;
        RECT  159.012 647.962 159.03 648 ;
    END
  END t_s[386]
  PIN t_s[387]
    DIRECTION OUTPUT ;
    USE SIGNAL ;
    PORT
      LAYER M5 ;
        RECT  159.312 647.916 159.336 648 ;
    END
  END t_s[387]
  PIN t_s[388]
    DIRECTION OUTPUT ;
    USE SIGNAL ;
    PORT
      LAYER M3 ;
        RECT  159.624 647.962 159.642 648 ;
    END
  END t_s[388]
  PIN t_s[389]
    DIRECTION OUTPUT ;
    USE SIGNAL ;
    PORT
      LAYER M5 ;
        RECT  159.888 647.916 159.912 648 ;
    END
  END t_s[389]
  PIN t_s[38]
    DIRECTION OUTPUT ;
    USE SIGNAL ;
    PORT
      LAYER M3 ;
        RECT  54.72 647.962 54.738 648 ;
    END
  END t_s[38]
  PIN t_s[390]
    DIRECTION OUTPUT ;
    USE SIGNAL ;
    PORT
      LAYER M3 ;
        RECT  160.2 647.962 160.218 648 ;
    END
  END t_s[390]
  PIN t_s[391]
    DIRECTION OUTPUT ;
    USE SIGNAL ;
    PORT
      LAYER M5 ;
        RECT  160.512 647.916 160.536 648 ;
    END
  END t_s[391]
  PIN t_s[392]
    DIRECTION OUTPUT ;
    USE SIGNAL ;
    PORT
      LAYER M3 ;
        RECT  160.812 647.962 160.83 648 ;
    END
  END t_s[392]
  PIN t_s[393]
    DIRECTION OUTPUT ;
    USE SIGNAL ;
    PORT
      LAYER M5 ;
        RECT  161.088 647.916 161.112 648 ;
    END
  END t_s[393]
  PIN t_s[394]
    DIRECTION OUTPUT ;
    USE SIGNAL ;
    PORT
      LAYER M3 ;
        RECT  161.388 647.962 161.406 648 ;
    END
  END t_s[394]
  PIN t_s[395]
    DIRECTION OUTPUT ;
    USE SIGNAL ;
    PORT
      LAYER M5 ;
        RECT  161.712 647.916 161.736 648 ;
    END
  END t_s[395]
  PIN t_s[396]
    DIRECTION OUTPUT ;
    USE SIGNAL ;
    PORT
      LAYER M3 ;
        RECT  162 647.962 162.018 648 ;
    END
  END t_s[396]
  PIN t_s[397]
    DIRECTION OUTPUT ;
    USE SIGNAL ;
    PORT
      LAYER M5 ;
        RECT  162.288 647.916 162.312 648 ;
    END
  END t_s[397]
  PIN t_s[398]
    DIRECTION OUTPUT ;
    USE SIGNAL ;
    PORT
      LAYER M3 ;
        RECT  162.612 647.962 162.63 648 ;
    END
  END t_s[398]
  PIN t_s[399]
    DIRECTION OUTPUT ;
    USE SIGNAL ;
    PORT
      LAYER M5 ;
        RECT  162.912 647.916 162.936 648 ;
    END
  END t_s[399]
  PIN t_s[39]
    DIRECTION OUTPUT ;
    USE SIGNAL ;
    PORT
      LAYER M5 ;
        RECT  55.008 647.916 55.032 648 ;
    END
  END t_s[39]
  PIN t_s[3]
    DIRECTION OUTPUT ;
    USE SIGNAL ;
    PORT
      LAYER M5 ;
        RECT  44.256 647.916 44.28 648 ;
    END
  END t_s[3]
  PIN t_s[400]
    DIRECTION OUTPUT ;
    USE SIGNAL ;
    PORT
      LAYER M3 ;
        RECT  163.188 647.962 163.206 648 ;
    END
  END t_s[400]
  PIN t_s[401]
    DIRECTION OUTPUT ;
    USE SIGNAL ;
    PORT
      LAYER M5 ;
        RECT  163.488 647.916 163.512 648 ;
    END
  END t_s[401]
  PIN t_s[402]
    DIRECTION OUTPUT ;
    USE SIGNAL ;
    PORT
      LAYER M3 ;
        RECT  163.8 647.962 163.818 648 ;
    END
  END t_s[402]
  PIN t_s[403]
    DIRECTION OUTPUT ;
    USE SIGNAL ;
    PORT
      LAYER M5 ;
        RECT  164.112 647.916 164.136 648 ;
    END
  END t_s[403]
  PIN t_s[404]
    DIRECTION OUTPUT ;
    USE SIGNAL ;
    PORT
      LAYER M3 ;
        RECT  164.412 647.962 164.43 648 ;
    END
  END t_s[404]
  PIN t_s[405]
    DIRECTION OUTPUT ;
    USE SIGNAL ;
    PORT
      LAYER M5 ;
        RECT  164.688 647.916 164.712 648 ;
    END
  END t_s[405]
  PIN t_s[406]
    DIRECTION OUTPUT ;
    USE SIGNAL ;
    PORT
      LAYER M3 ;
        RECT  164.988 647.962 165.006 648 ;
    END
  END t_s[406]
  PIN t_s[407]
    DIRECTION OUTPUT ;
    USE SIGNAL ;
    PORT
      LAYER M5 ;
        RECT  165.312 647.916 165.336 648 ;
    END
  END t_s[407]
  PIN t_s[408]
    DIRECTION OUTPUT ;
    USE SIGNAL ;
    PORT
      LAYER M3 ;
        RECT  165.6 647.962 165.618 648 ;
    END
  END t_s[408]
  PIN t_s[409]
    DIRECTION OUTPUT ;
    USE SIGNAL ;
    PORT
      LAYER M5 ;
        RECT  165.888 647.916 165.912 648 ;
    END
  END t_s[409]
  PIN t_s[40]
    DIRECTION OUTPUT ;
    USE SIGNAL ;
    PORT
      LAYER M3 ;
        RECT  55.332 647.962 55.35 648 ;
    END
  END t_s[40]
  PIN t_s[410]
    DIRECTION OUTPUT ;
    USE SIGNAL ;
    PORT
      LAYER M3 ;
        RECT  166.212 647.962 166.23 648 ;
    END
  END t_s[410]
  PIN t_s[411]
    DIRECTION OUTPUT ;
    USE SIGNAL ;
    PORT
      LAYER M5 ;
        RECT  166.512 647.916 166.536 648 ;
    END
  END t_s[411]
  PIN t_s[412]
    DIRECTION OUTPUT ;
    USE SIGNAL ;
    PORT
      LAYER M3 ;
        RECT  166.788 647.962 166.806 648 ;
    END
  END t_s[412]
  PIN t_s[413]
    DIRECTION OUTPUT ;
    USE SIGNAL ;
    PORT
      LAYER M5 ;
        RECT  167.088 647.916 167.112 648 ;
    END
  END t_s[413]
  PIN t_s[414]
    DIRECTION OUTPUT ;
    USE SIGNAL ;
    PORT
      LAYER M3 ;
        RECT  167.4 647.962 167.418 648 ;
    END
  END t_s[414]
  PIN t_s[415]
    DIRECTION OUTPUT ;
    USE SIGNAL ;
    PORT
      LAYER M5 ;
        RECT  167.712 647.916 167.736 648 ;
    END
  END t_s[415]
  PIN t_s[416]
    DIRECTION OUTPUT ;
    USE SIGNAL ;
    PORT
      LAYER M3 ;
        RECT  168.012 647.962 168.03 648 ;
    END
  END t_s[416]
  PIN t_s[417]
    DIRECTION OUTPUT ;
    USE SIGNAL ;
    PORT
      LAYER M5 ;
        RECT  168.288 647.916 168.312 648 ;
    END
  END t_s[417]
  PIN t_s[418]
    DIRECTION OUTPUT ;
    USE SIGNAL ;
    PORT
      LAYER M3 ;
        RECT  168.588 647.962 168.606 648 ;
    END
  END t_s[418]
  PIN t_s[419]
    DIRECTION OUTPUT ;
    USE SIGNAL ;
    PORT
      LAYER M5 ;
        RECT  168.912 647.916 168.936 648 ;
    END
  END t_s[419]
  PIN t_s[41]
    DIRECTION OUTPUT ;
    USE SIGNAL ;
    PORT
      LAYER M5 ;
        RECT  55.632 647.916 55.656 648 ;
    END
  END t_s[41]
  PIN t_s[420]
    DIRECTION OUTPUT ;
    USE SIGNAL ;
    PORT
      LAYER M3 ;
        RECT  169.2 647.962 169.218 648 ;
    END
  END t_s[420]
  PIN t_s[421]
    DIRECTION OUTPUT ;
    USE SIGNAL ;
    PORT
      LAYER M5 ;
        RECT  169.488 647.916 169.512 648 ;
    END
  END t_s[421]
  PIN t_s[422]
    DIRECTION OUTPUT ;
    USE SIGNAL ;
    PORT
      LAYER M3 ;
        RECT  169.812 647.962 169.83 648 ;
    END
  END t_s[422]
  PIN t_s[423]
    DIRECTION OUTPUT ;
    USE SIGNAL ;
    PORT
      LAYER M5 ;
        RECT  170.112 647.916 170.136 648 ;
    END
  END t_s[423]
  PIN t_s[424]
    DIRECTION OUTPUT ;
    USE SIGNAL ;
    PORT
      LAYER M3 ;
        RECT  170.388 647.962 170.406 648 ;
    END
  END t_s[424]
  PIN t_s[425]
    DIRECTION OUTPUT ;
    USE SIGNAL ;
    PORT
      LAYER M5 ;
        RECT  170.688 647.916 170.712 648 ;
    END
  END t_s[425]
  PIN t_s[426]
    DIRECTION OUTPUT ;
    USE SIGNAL ;
    PORT
      LAYER M3 ;
        RECT  171 647.962 171.018 648 ;
    END
  END t_s[426]
  PIN t_s[427]
    DIRECTION OUTPUT ;
    USE SIGNAL ;
    PORT
      LAYER M5 ;
        RECT  171.312 647.916 171.336 648 ;
    END
  END t_s[427]
  PIN t_s[428]
    DIRECTION OUTPUT ;
    USE SIGNAL ;
    PORT
      LAYER M3 ;
        RECT  171.576 647.962 171.594 648 ;
    END
  END t_s[428]
  PIN t_s[429]
    DIRECTION OUTPUT ;
    USE SIGNAL ;
    PORT
      LAYER M5 ;
        RECT  171.888 647.916 171.912 648 ;
    END
  END t_s[429]
  PIN t_s[42]
    DIRECTION OUTPUT ;
    USE SIGNAL ;
    PORT
      LAYER M3 ;
        RECT  55.944 647.962 55.962 648 ;
    END
  END t_s[42]
  PIN t_s[430]
    DIRECTION OUTPUT ;
    USE SIGNAL ;
    PORT
      LAYER M3 ;
        RECT  172.188 647.962 172.206 648 ;
    END
  END t_s[430]
  PIN t_s[431]
    DIRECTION OUTPUT ;
    USE SIGNAL ;
    PORT
      LAYER M5 ;
        RECT  172.512 647.916 172.536 648 ;
    END
  END t_s[431]
  PIN t_s[432]
    DIRECTION OUTPUT ;
    USE SIGNAL ;
    PORT
      LAYER M3 ;
        RECT  172.8 647.962 172.818 648 ;
    END
  END t_s[432]
  PIN t_s[433]
    DIRECTION OUTPUT ;
    USE SIGNAL ;
    PORT
      LAYER M5 ;
        RECT  173.088 647.916 173.112 648 ;
    END
  END t_s[433]
  PIN t_s[434]
    DIRECTION OUTPUT ;
    USE SIGNAL ;
    PORT
      LAYER M3 ;
        RECT  173.376 647.962 173.394 648 ;
    END
  END t_s[434]
  PIN t_s[435]
    DIRECTION OUTPUT ;
    USE SIGNAL ;
    PORT
      LAYER M5 ;
        RECT  173.664 647.916 173.688 648 ;
    END
  END t_s[435]
  PIN t_s[436]
    DIRECTION OUTPUT ;
    USE SIGNAL ;
    PORT
      LAYER M3 ;
        RECT  173.988 647.962 174.006 648 ;
    END
  END t_s[436]
  PIN t_s[437]
    DIRECTION OUTPUT ;
    USE SIGNAL ;
    PORT
      LAYER M5 ;
        RECT  174.288 647.916 174.312 648 ;
    END
  END t_s[437]
  PIN t_s[438]
    DIRECTION OUTPUT ;
    USE SIGNAL ;
    PORT
      LAYER M3 ;
        RECT  174.6 647.962 174.618 648 ;
    END
  END t_s[438]
  PIN t_s[439]
    DIRECTION OUTPUT ;
    USE SIGNAL ;
    PORT
      LAYER M5 ;
        RECT  174.864 647.916 174.888 648 ;
    END
  END t_s[439]
  PIN t_s[43]
    DIRECTION OUTPUT ;
    USE SIGNAL ;
    PORT
      LAYER M5 ;
        RECT  56.208 647.916 56.232 648 ;
    END
  END t_s[43]
  PIN t_s[440]
    DIRECTION OUTPUT ;
    USE SIGNAL ;
    PORT
      LAYER M3 ;
        RECT  175.176 647.962 175.194 648 ;
    END
  END t_s[440]
  PIN t_s[441]
    DIRECTION OUTPUT ;
    USE SIGNAL ;
    PORT
      LAYER M5 ;
        RECT  175.488 647.916 175.512 648 ;
    END
  END t_s[441]
  PIN t_s[442]
    DIRECTION OUTPUT ;
    USE SIGNAL ;
    PORT
      LAYER M3 ;
        RECT  175.788 647.962 175.806 648 ;
    END
  END t_s[442]
  PIN t_s[443]
    DIRECTION OUTPUT ;
    USE SIGNAL ;
    PORT
      LAYER M5 ;
        RECT  176.064 647.916 176.088 648 ;
    END
  END t_s[443]
  PIN t_s[444]
    DIRECTION OUTPUT ;
    USE SIGNAL ;
    PORT
      LAYER M3 ;
        RECT  176.4 647.962 176.418 648 ;
    END
  END t_s[444]
  PIN t_s[445]
    DIRECTION OUTPUT ;
    USE SIGNAL ;
    PORT
      LAYER M5 ;
        RECT  176.688 647.916 176.712 648 ;
    END
  END t_s[445]
  PIN t_s[446]
    DIRECTION OUTPUT ;
    USE SIGNAL ;
    PORT
      LAYER M3 ;
        RECT  176.976 647.962 176.994 648 ;
    END
  END t_s[446]
  PIN t_s[447]
    DIRECTION OUTPUT ;
    USE SIGNAL ;
    PORT
      LAYER M5 ;
        RECT  177.264 647.916 177.288 648 ;
    END
  END t_s[447]
  PIN t_s[448]
    DIRECTION OUTPUT ;
    USE SIGNAL ;
    PORT
      LAYER M3 ;
        RECT  177.588 647.962 177.606 648 ;
    END
  END t_s[448]
  PIN t_s[449]
    DIRECTION OUTPUT ;
    USE SIGNAL ;
    PORT
      LAYER M5 ;
        RECT  177.888 647.916 177.912 648 ;
    END
  END t_s[449]
  PIN t_s[44]
    DIRECTION OUTPUT ;
    USE SIGNAL ;
    PORT
      LAYER M3 ;
        RECT  56.52 647.962 56.538 648 ;
    END
  END t_s[44]
  PIN t_s[450]
    DIRECTION OUTPUT ;
    USE SIGNAL ;
    PORT
      LAYER M3 ;
        RECT  178.2 647.962 178.218 648 ;
    END
  END t_s[450]
  PIN t_s[451]
    DIRECTION OUTPUT ;
    USE SIGNAL ;
    PORT
      LAYER M5 ;
        RECT  178.464 647.916 178.488 648 ;
    END
  END t_s[451]
  PIN t_s[452]
    DIRECTION OUTPUT ;
    USE SIGNAL ;
    PORT
      LAYER M3 ;
        RECT  178.776 647.962 178.794 648 ;
    END
  END t_s[452]
  PIN t_s[453]
    DIRECTION OUTPUT ;
    USE SIGNAL ;
    PORT
      LAYER M5 ;
        RECT  179.088 647.916 179.112 648 ;
    END
  END t_s[453]
  PIN t_s[454]
    DIRECTION OUTPUT ;
    USE SIGNAL ;
    PORT
      LAYER M3 ;
        RECT  179.388 647.962 179.406 648 ;
    END
  END t_s[454]
  PIN t_s[455]
    DIRECTION OUTPUT ;
    USE SIGNAL ;
    PORT
      LAYER M5 ;
        RECT  179.664 647.916 179.688 648 ;
    END
  END t_s[455]
  PIN t_s[456]
    DIRECTION OUTPUT ;
    USE SIGNAL ;
    PORT
      LAYER M3 ;
        RECT  180 647.962 180.018 648 ;
    END
  END t_s[456]
  PIN t_s[457]
    DIRECTION OUTPUT ;
    USE SIGNAL ;
    PORT
      LAYER M5 ;
        RECT  180.288 647.916 180.312 648 ;
    END
  END t_s[457]
  PIN t_s[458]
    DIRECTION OUTPUT ;
    USE SIGNAL ;
    PORT
      LAYER M3 ;
        RECT  180.576 647.962 180.594 648 ;
    END
  END t_s[458]
  PIN t_s[459]
    DIRECTION OUTPUT ;
    USE SIGNAL ;
    PORT
      LAYER M5 ;
        RECT  180.864 647.916 180.888 648 ;
    END
  END t_s[459]
  PIN t_s[45]
    DIRECTION OUTPUT ;
    USE SIGNAL ;
    PORT
      LAYER M5 ;
        RECT  56.832 647.916 56.856 648 ;
    END
  END t_s[45]
  PIN t_s[460]
    DIRECTION OUTPUT ;
    USE SIGNAL ;
    PORT
      LAYER M3 ;
        RECT  181.188 647.962 181.206 648 ;
    END
  END t_s[460]
  PIN t_s[461]
    DIRECTION OUTPUT ;
    USE SIGNAL ;
    PORT
      LAYER M5 ;
        RECT  181.488 647.916 181.512 648 ;
    END
  END t_s[461]
  PIN t_s[462]
    DIRECTION OUTPUT ;
    USE SIGNAL ;
    PORT
      LAYER M3 ;
        RECT  181.764 647.962 181.782 648 ;
    END
  END t_s[462]
  PIN t_s[463]
    DIRECTION OUTPUT ;
    USE SIGNAL ;
    PORT
      LAYER M5 ;
        RECT  182.064 647.916 182.088 648 ;
    END
  END t_s[463]
  PIN t_s[464]
    DIRECTION OUTPUT ;
    USE SIGNAL ;
    PORT
      LAYER M3 ;
        RECT  182.376 647.962 182.394 648 ;
    END
  END t_s[464]
  PIN t_s[465]
    DIRECTION OUTPUT ;
    USE SIGNAL ;
    PORT
      LAYER M5 ;
        RECT  182.688 647.916 182.712 648 ;
    END
  END t_s[465]
  PIN t_s[466]
    DIRECTION OUTPUT ;
    USE SIGNAL ;
    PORT
      LAYER M3 ;
        RECT  182.988 647.962 183.006 648 ;
    END
  END t_s[466]
  PIN t_s[467]
    DIRECTION OUTPUT ;
    USE SIGNAL ;
    PORT
      LAYER M5 ;
        RECT  183.264 647.916 183.288 648 ;
    END
  END t_s[467]
  PIN t_s[468]
    DIRECTION OUTPUT ;
    USE SIGNAL ;
    PORT
      LAYER M3 ;
        RECT  183.564 647.962 183.582 648 ;
    END
  END t_s[468]
  PIN t_s[469]
    DIRECTION OUTPUT ;
    USE SIGNAL ;
    PORT
      LAYER M5 ;
        RECT  183.888 647.916 183.912 648 ;
    END
  END t_s[469]
  PIN t_s[46]
    DIRECTION OUTPUT ;
    USE SIGNAL ;
    PORT
      LAYER M3 ;
        RECT  57.132 647.962 57.15 648 ;
    END
  END t_s[46]
  PIN t_s[470]
    DIRECTION OUTPUT ;
    USE SIGNAL ;
    PORT
      LAYER M3 ;
        RECT  184.176 647.962 184.194 648 ;
    END
  END t_s[470]
  PIN t_s[471]
    DIRECTION OUTPUT ;
    USE SIGNAL ;
    PORT
      LAYER M5 ;
        RECT  184.464 647.916 184.488 648 ;
    END
  END t_s[471]
  PIN t_s[472]
    DIRECTION OUTPUT ;
    USE SIGNAL ;
    PORT
      LAYER M3 ;
        RECT  184.788 647.962 184.806 648 ;
    END
  END t_s[472]
  PIN t_s[473]
    DIRECTION OUTPUT ;
    USE SIGNAL ;
    PORT
      LAYER M5 ;
        RECT  185.088 647.916 185.112 648 ;
    END
  END t_s[473]
  PIN t_s[474]
    DIRECTION OUTPUT ;
    USE SIGNAL ;
    PORT
      LAYER M3 ;
        RECT  185.364 647.962 185.382 648 ;
    END
  END t_s[474]
  PIN t_s[475]
    DIRECTION OUTPUT ;
    USE SIGNAL ;
    PORT
      LAYER M5 ;
        RECT  185.664 647.916 185.688 648 ;
    END
  END t_s[475]
  PIN t_s[476]
    DIRECTION OUTPUT ;
    USE SIGNAL ;
    PORT
      LAYER M3 ;
        RECT  185.976 647.962 185.994 648 ;
    END
  END t_s[476]
  PIN t_s[477]
    DIRECTION OUTPUT ;
    USE SIGNAL ;
    PORT
      LAYER M5 ;
        RECT  186.288 647.916 186.312 648 ;
    END
  END t_s[477]
  PIN t_s[478]
    DIRECTION OUTPUT ;
    USE SIGNAL ;
    PORT
      LAYER M3 ;
        RECT  186.588 647.962 186.606 648 ;
    END
  END t_s[478]
  PIN t_s[479]
    DIRECTION OUTPUT ;
    USE SIGNAL ;
    PORT
      LAYER M5 ;
        RECT  186.864 647.916 186.888 648 ;
    END
  END t_s[479]
  PIN t_s[47]
    DIRECTION OUTPUT ;
    USE SIGNAL ;
    PORT
      LAYER M5 ;
        RECT  57.408 647.916 57.432 648 ;
    END
  END t_s[47]
  PIN t_s[480]
    DIRECTION OUTPUT ;
    USE SIGNAL ;
    PORT
      LAYER M3 ;
        RECT  187.164 647.962 187.182 648 ;
    END
  END t_s[480]
  PIN t_s[481]
    DIRECTION OUTPUT ;
    USE SIGNAL ;
    PORT
      LAYER M5 ;
        RECT  187.488 647.916 187.512 648 ;
    END
  END t_s[481]
  PIN t_s[482]
    DIRECTION OUTPUT ;
    USE SIGNAL ;
    PORT
      LAYER M3 ;
        RECT  187.776 647.962 187.794 648 ;
    END
  END t_s[482]
  PIN t_s[483]
    DIRECTION OUTPUT ;
    USE SIGNAL ;
    PORT
      LAYER M5 ;
        RECT  188.064 647.916 188.088 648 ;
    END
  END t_s[483]
  PIN t_s[484]
    DIRECTION OUTPUT ;
    USE SIGNAL ;
    PORT
      LAYER M3 ;
        RECT  188.388 647.962 188.406 648 ;
    END
  END t_s[484]
  PIN t_s[485]
    DIRECTION OUTPUT ;
    USE SIGNAL ;
    PORT
      LAYER M5 ;
        RECT  188.688 647.916 188.712 648 ;
    END
  END t_s[485]
  PIN t_s[486]
    DIRECTION OUTPUT ;
    USE SIGNAL ;
    PORT
      LAYER M3 ;
        RECT  188.964 647.962 188.982 648 ;
    END
  END t_s[486]
  PIN t_s[487]
    DIRECTION OUTPUT ;
    USE SIGNAL ;
    PORT
      LAYER M5 ;
        RECT  189.264 647.916 189.288 648 ;
    END
  END t_s[487]
  PIN t_s[488]
    DIRECTION OUTPUT ;
    USE SIGNAL ;
    PORT
      LAYER M3 ;
        RECT  189.576 647.962 189.594 648 ;
    END
  END t_s[488]
  PIN t_s[489]
    DIRECTION OUTPUT ;
    USE SIGNAL ;
    PORT
      LAYER M5 ;
        RECT  189.888 647.916 189.912 648 ;
    END
  END t_s[489]
  PIN t_s[48]
    DIRECTION OUTPUT ;
    USE SIGNAL ;
    PORT
      LAYER M3 ;
        RECT  57.708 647.962 57.726 648 ;
    END
  END t_s[48]
  PIN t_s[490]
    DIRECTION OUTPUT ;
    USE SIGNAL ;
    PORT
      LAYER M3 ;
        RECT  190.188 647.962 190.206 648 ;
    END
  END t_s[490]
  PIN t_s[491]
    DIRECTION OUTPUT ;
    USE SIGNAL ;
    PORT
      LAYER M5 ;
        RECT  190.464 647.916 190.488 648 ;
    END
  END t_s[491]
  PIN t_s[492]
    DIRECTION OUTPUT ;
    USE SIGNAL ;
    PORT
      LAYER M3 ;
        RECT  190.764 647.962 190.782 648 ;
    END
  END t_s[492]
  PIN t_s[493]
    DIRECTION OUTPUT ;
    USE SIGNAL ;
    PORT
      LAYER M5 ;
        RECT  191.088 647.916 191.112 648 ;
    END
  END t_s[493]
  PIN t_s[494]
    DIRECTION OUTPUT ;
    USE SIGNAL ;
    PORT
      LAYER M3 ;
        RECT  191.376 647.962 191.394 648 ;
    END
  END t_s[494]
  PIN t_s[495]
    DIRECTION OUTPUT ;
    USE SIGNAL ;
    PORT
      LAYER M5 ;
        RECT  191.664 647.916 191.688 648 ;
    END
  END t_s[495]
  PIN t_s[496]
    DIRECTION OUTPUT ;
    USE SIGNAL ;
    PORT
      LAYER M3 ;
        RECT  191.952 647.962 191.97 648 ;
    END
  END t_s[496]
  PIN t_s[497]
    DIRECTION OUTPUT ;
    USE SIGNAL ;
    PORT
      LAYER M5 ;
        RECT  192.288 647.916 192.312 648 ;
    END
  END t_s[497]
  PIN t_s[498]
    DIRECTION OUTPUT ;
    USE SIGNAL ;
    PORT
      LAYER M3 ;
        RECT  192.564 647.962 192.582 648 ;
    END
  END t_s[498]
  PIN t_s[499]
    DIRECTION OUTPUT ;
    USE SIGNAL ;
    PORT
      LAYER M5 ;
        RECT  192.864 647.916 192.888 648 ;
    END
  END t_s[499]
  PIN t_s[49]
    DIRECTION OUTPUT ;
    USE SIGNAL ;
    PORT
      LAYER M5 ;
        RECT  58.032 647.916 58.056 648 ;
    END
  END t_s[49]
  PIN t_s[4]
    DIRECTION OUTPUT ;
    USE SIGNAL ;
    PORT
      LAYER M3 ;
        RECT  44.532 647.962 44.55 648 ;
    END
  END t_s[4]
  PIN t_s[500]
    DIRECTION OUTPUT ;
    USE SIGNAL ;
    PORT
      LAYER M3 ;
        RECT  193.176 647.962 193.194 648 ;
    END
  END t_s[500]
  PIN t_s[501]
    DIRECTION OUTPUT ;
    USE SIGNAL ;
    PORT
      LAYER M5 ;
        RECT  193.488 647.916 193.512 648 ;
    END
  END t_s[501]
  PIN t_s[502]
    DIRECTION OUTPUT ;
    USE SIGNAL ;
    PORT
      LAYER M3 ;
        RECT  193.752 647.962 193.77 648 ;
    END
  END t_s[502]
  PIN t_s[503]
    DIRECTION OUTPUT ;
    USE SIGNAL ;
    PORT
      LAYER M5 ;
        RECT  194.064 647.916 194.088 648 ;
    END
  END t_s[503]
  PIN t_s[504]
    DIRECTION OUTPUT ;
    USE SIGNAL ;
    PORT
      LAYER M3 ;
        RECT  194.364 647.962 194.382 648 ;
    END
  END t_s[504]
  PIN t_s[505]
    DIRECTION OUTPUT ;
    USE SIGNAL ;
    PORT
      LAYER M5 ;
        RECT  194.64 647.916 194.664 648 ;
    END
  END t_s[505]
  PIN t_s[506]
    DIRECTION OUTPUT ;
    USE SIGNAL ;
    PORT
      LAYER M3 ;
        RECT  194.976 647.962 194.994 648 ;
    END
  END t_s[506]
  PIN t_s[507]
    DIRECTION OUTPUT ;
    USE SIGNAL ;
    PORT
      LAYER M5 ;
        RECT  195.264 647.916 195.288 648 ;
    END
  END t_s[507]
  PIN t_s[508]
    DIRECTION OUTPUT ;
    USE SIGNAL ;
    PORT
      LAYER M3 ;
        RECT  195.552 647.962 195.57 648 ;
    END
  END t_s[508]
  PIN t_s[509]
    DIRECTION OUTPUT ;
    USE SIGNAL ;
    PORT
      LAYER M5 ;
        RECT  195.84 647.916 195.864 648 ;
    END
  END t_s[509]
  PIN t_s[50]
    DIRECTION OUTPUT ;
    USE SIGNAL ;
    PORT
      LAYER M3 ;
        RECT  58.32 647.962 58.338 648 ;
    END
  END t_s[50]
  PIN t_s[510]
    DIRECTION OUTPUT ;
    USE SIGNAL ;
    PORT
      LAYER M3 ;
        RECT  196.164 647.962 196.182 648 ;
    END
  END t_s[510]
  PIN t_s[511]
    DIRECTION OUTPUT ;
    USE SIGNAL ;
    PORT
      LAYER M5 ;
        RECT  196.464 647.916 196.488 648 ;
    END
  END t_s[511]
  PIN t_s[512]
    DIRECTION OUTPUT ;
    USE SIGNAL ;
    PORT
      LAYER M3 ;
        RECT  196.776 647.962 196.794 648 ;
    END
  END t_s[512]
  PIN t_s[513]
    DIRECTION OUTPUT ;
    USE SIGNAL ;
    PORT
      LAYER M5 ;
        RECT  197.04 647.916 197.064 648 ;
    END
  END t_s[513]
  PIN t_s[514]
    DIRECTION OUTPUT ;
    USE SIGNAL ;
    PORT
      LAYER M3 ;
        RECT  197.352 647.962 197.37 648 ;
    END
  END t_s[514]
  PIN t_s[515]
    DIRECTION OUTPUT ;
    USE SIGNAL ;
    PORT
      LAYER M5 ;
        RECT  197.664 647.916 197.688 648 ;
    END
  END t_s[515]
  PIN t_s[516]
    DIRECTION OUTPUT ;
    USE SIGNAL ;
    PORT
      LAYER M3 ;
        RECT  197.964 647.962 197.982 648 ;
    END
  END t_s[516]
  PIN t_s[517]
    DIRECTION OUTPUT ;
    USE SIGNAL ;
    PORT
      LAYER M5 ;
        RECT  198.24 647.916 198.264 648 ;
    END
  END t_s[517]
  PIN t_s[518]
    DIRECTION OUTPUT ;
    USE SIGNAL ;
    PORT
      LAYER M3 ;
        RECT  198.576 647.962 198.594 648 ;
    END
  END t_s[518]
  PIN t_s[519]
    DIRECTION OUTPUT ;
    USE SIGNAL ;
    PORT
      LAYER M5 ;
        RECT  198.864 647.916 198.888 648 ;
    END
  END t_s[519]
  PIN t_s[51]
    DIRECTION OUTPUT ;
    USE SIGNAL ;
    PORT
      LAYER M5 ;
        RECT  58.608 647.916 58.632 648 ;
    END
  END t_s[51]
  PIN t_s[520]
    DIRECTION OUTPUT ;
    USE SIGNAL ;
    PORT
      LAYER M3 ;
        RECT  199.152 647.962 199.17 648 ;
    END
  END t_s[520]
  PIN t_s[521]
    DIRECTION OUTPUT ;
    USE SIGNAL ;
    PORT
      LAYER M5 ;
        RECT  199.44 647.916 199.464 648 ;
    END
  END t_s[521]
  PIN t_s[522]
    DIRECTION OUTPUT ;
    USE SIGNAL ;
    PORT
      LAYER M3 ;
        RECT  199.764 647.962 199.782 648 ;
    END
  END t_s[522]
  PIN t_s[523]
    DIRECTION OUTPUT ;
    USE SIGNAL ;
    PORT
      LAYER M5 ;
        RECT  200.064 647.916 200.088 648 ;
    END
  END t_s[523]
  PIN t_s[524]
    DIRECTION OUTPUT ;
    USE SIGNAL ;
    PORT
      LAYER M3 ;
        RECT  200.376 647.962 200.394 648 ;
    END
  END t_s[524]
  PIN t_s[525]
    DIRECTION OUTPUT ;
    USE SIGNAL ;
    PORT
      LAYER M5 ;
        RECT  200.64 647.916 200.664 648 ;
    END
  END t_s[525]
  PIN t_s[526]
    DIRECTION OUTPUT ;
    USE SIGNAL ;
    PORT
      LAYER M3 ;
        RECT  200.952 647.962 200.97 648 ;
    END
  END t_s[526]
  PIN t_s[527]
    DIRECTION OUTPUT ;
    USE SIGNAL ;
    PORT
      LAYER M5 ;
        RECT  201.264 647.916 201.288 648 ;
    END
  END t_s[527]
  PIN t_s[528]
    DIRECTION OUTPUT ;
    USE SIGNAL ;
    PORT
      LAYER M3 ;
        RECT  201.564 647.962 201.582 648 ;
    END
  END t_s[528]
  PIN t_s[529]
    DIRECTION OUTPUT ;
    USE SIGNAL ;
    PORT
      LAYER M5 ;
        RECT  201.84 647.916 201.864 648 ;
    END
  END t_s[529]
  PIN t_s[52]
    DIRECTION OUTPUT ;
    USE SIGNAL ;
    PORT
      LAYER M3 ;
        RECT  58.932 647.962 58.95 648 ;
    END
  END t_s[52]
  PIN t_s[530]
    DIRECTION OUTPUT ;
    USE SIGNAL ;
    PORT
      LAYER M3 ;
        RECT  202.14 647.962 202.158 648 ;
    END
  END t_s[530]
  PIN t_s[531]
    DIRECTION OUTPUT ;
    USE SIGNAL ;
    PORT
      LAYER M5 ;
        RECT  202.464 647.916 202.488 648 ;
    END
  END t_s[531]
  PIN t_s[532]
    DIRECTION OUTPUT ;
    USE SIGNAL ;
    PORT
      LAYER M3 ;
        RECT  202.752 647.962 202.77 648 ;
    END
  END t_s[532]
  PIN t_s[533]
    DIRECTION OUTPUT ;
    USE SIGNAL ;
    PORT
      LAYER M5 ;
        RECT  203.04 647.916 203.064 648 ;
    END
  END t_s[533]
  PIN t_s[534]
    DIRECTION OUTPUT ;
    USE SIGNAL ;
    PORT
      LAYER M3 ;
        RECT  203.364 647.962 203.382 648 ;
    END
  END t_s[534]
  PIN t_s[535]
    DIRECTION OUTPUT ;
    USE SIGNAL ;
    PORT
      LAYER M5 ;
        RECT  203.664 647.916 203.688 648 ;
    END
  END t_s[535]
  PIN t_s[536]
    DIRECTION OUTPUT ;
    USE SIGNAL ;
    PORT
      LAYER M3 ;
        RECT  203.94 647.962 203.958 648 ;
    END
  END t_s[536]
  PIN t_s[537]
    DIRECTION OUTPUT ;
    USE SIGNAL ;
    PORT
      LAYER M5 ;
        RECT  204.24 647.916 204.264 648 ;
    END
  END t_s[537]
  PIN t_s[538]
    DIRECTION OUTPUT ;
    USE SIGNAL ;
    PORT
      LAYER M3 ;
        RECT  204.552 647.962 204.57 648 ;
    END
  END t_s[538]
  PIN t_s[539]
    DIRECTION OUTPUT ;
    USE SIGNAL ;
    PORT
      LAYER M5 ;
        RECT  204.864 647.916 204.888 648 ;
    END
  END t_s[539]
  PIN t_s[53]
    DIRECTION OUTPUT ;
    USE SIGNAL ;
    PORT
      LAYER M5 ;
        RECT  59.232 647.916 59.256 648 ;
    END
  END t_s[53]
  PIN t_s[540]
    DIRECTION OUTPUT ;
    USE SIGNAL ;
    PORT
      LAYER M3 ;
        RECT  205.164 647.962 205.182 648 ;
    END
  END t_s[540]
  PIN t_s[541]
    DIRECTION OUTPUT ;
    USE SIGNAL ;
    PORT
      LAYER M5 ;
        RECT  205.44 647.916 205.464 648 ;
    END
  END t_s[541]
  PIN t_s[542]
    DIRECTION OUTPUT ;
    USE SIGNAL ;
    PORT
      LAYER M3 ;
        RECT  205.74 647.962 205.758 648 ;
    END
  END t_s[542]
  PIN t_s[543]
    DIRECTION OUTPUT ;
    USE SIGNAL ;
    PORT
      LAYER M5 ;
        RECT  206.064 647.916 206.088 648 ;
    END
  END t_s[543]
  PIN t_s[544]
    DIRECTION OUTPUT ;
    USE SIGNAL ;
    PORT
      LAYER M3 ;
        RECT  206.352 647.962 206.37 648 ;
    END
  END t_s[544]
  PIN t_s[545]
    DIRECTION OUTPUT ;
    USE SIGNAL ;
    PORT
      LAYER M5 ;
        RECT  206.64 647.916 206.664 648 ;
    END
  END t_s[545]
  PIN t_s[546]
    DIRECTION OUTPUT ;
    USE SIGNAL ;
    PORT
      LAYER M3 ;
        RECT  206.964 647.962 206.982 648 ;
    END
  END t_s[546]
  PIN t_s[547]
    DIRECTION OUTPUT ;
    USE SIGNAL ;
    PORT
      LAYER M5 ;
        RECT  207.264 647.916 207.288 648 ;
    END
  END t_s[547]
  PIN t_s[548]
    DIRECTION OUTPUT ;
    USE SIGNAL ;
    PORT
      LAYER M3 ;
        RECT  207.54 647.962 207.558 648 ;
    END
  END t_s[548]
  PIN t_s[549]
    DIRECTION OUTPUT ;
    USE SIGNAL ;
    PORT
      LAYER M5 ;
        RECT  207.84 647.916 207.864 648 ;
    END
  END t_s[549]
  PIN t_s[54]
    DIRECTION OUTPUT ;
    USE SIGNAL ;
    PORT
      LAYER M3 ;
        RECT  59.508 647.962 59.526 648 ;
    END
  END t_s[54]
  PIN t_s[550]
    DIRECTION OUTPUT ;
    USE SIGNAL ;
    PORT
      LAYER M3 ;
        RECT  208.152 647.962 208.17 648 ;
    END
  END t_s[550]
  PIN t_s[551]
    DIRECTION OUTPUT ;
    USE SIGNAL ;
    PORT
      LAYER M5 ;
        RECT  208.464 647.916 208.488 648 ;
    END
  END t_s[551]
  PIN t_s[552]
    DIRECTION OUTPUT ;
    USE SIGNAL ;
    PORT
      LAYER M3 ;
        RECT  208.764 647.962 208.782 648 ;
    END
  END t_s[552]
  PIN t_s[553]
    DIRECTION OUTPUT ;
    USE SIGNAL ;
    PORT
      LAYER M5 ;
        RECT  209.04 647.916 209.064 648 ;
    END
  END t_s[553]
  PIN t_s[554]
    DIRECTION OUTPUT ;
    USE SIGNAL ;
    PORT
      LAYER M3 ;
        RECT  209.34 647.962 209.358 648 ;
    END
  END t_s[554]
  PIN t_s[555]
    DIRECTION OUTPUT ;
    USE SIGNAL ;
    PORT
      LAYER M5 ;
        RECT  209.664 647.916 209.688 648 ;
    END
  END t_s[555]
  PIN t_s[556]
    DIRECTION OUTPUT ;
    USE SIGNAL ;
    PORT
      LAYER M3 ;
        RECT  209.952 647.962 209.97 648 ;
    END
  END t_s[556]
  PIN t_s[557]
    DIRECTION OUTPUT ;
    USE SIGNAL ;
    PORT
      LAYER M5 ;
        RECT  210.24 647.916 210.264 648 ;
    END
  END t_s[557]
  PIN t_s[558]
    DIRECTION OUTPUT ;
    USE SIGNAL ;
    PORT
      LAYER M3 ;
        RECT  210.564 647.962 210.582 648 ;
    END
  END t_s[558]
  PIN t_s[559]
    DIRECTION OUTPUT ;
    USE SIGNAL ;
    PORT
      LAYER M5 ;
        RECT  210.864 647.916 210.888 648 ;
    END
  END t_s[559]
  PIN t_s[55]
    DIRECTION OUTPUT ;
    USE SIGNAL ;
    PORT
      LAYER M5 ;
        RECT  59.808 647.916 59.832 648 ;
    END
  END t_s[55]
  PIN t_s[560]
    DIRECTION OUTPUT ;
    USE SIGNAL ;
    PORT
      LAYER M3 ;
        RECT  211.14 647.962 211.158 648 ;
    END
  END t_s[560]
  PIN t_s[561]
    DIRECTION OUTPUT ;
    USE SIGNAL ;
    PORT
      LAYER M5 ;
        RECT  211.44 647.916 211.464 648 ;
    END
  END t_s[561]
  PIN t_s[562]
    DIRECTION OUTPUT ;
    USE SIGNAL ;
    PORT
      LAYER M3 ;
        RECT  211.752 647.962 211.77 648 ;
    END
  END t_s[562]
  PIN t_s[563]
    DIRECTION OUTPUT ;
    USE SIGNAL ;
    PORT
      LAYER M5 ;
        RECT  212.064 647.916 212.088 648 ;
    END
  END t_s[563]
  PIN t_s[564]
    DIRECTION OUTPUT ;
    USE SIGNAL ;
    PORT
      LAYER M3 ;
        RECT  212.328 647.962 212.346 648 ;
    END
  END t_s[564]
  PIN t_s[565]
    DIRECTION OUTPUT ;
    USE SIGNAL ;
    PORT
      LAYER M5 ;
        RECT  212.64 647.916 212.664 648 ;
    END
  END t_s[565]
  PIN t_s[566]
    DIRECTION OUTPUT ;
    USE SIGNAL ;
    PORT
      LAYER M3 ;
        RECT  212.94 647.962 212.958 648 ;
    END
  END t_s[566]
  PIN t_s[567]
    DIRECTION OUTPUT ;
    USE SIGNAL ;
    PORT
      LAYER M5 ;
        RECT  213.264 647.916 213.288 648 ;
    END
  END t_s[567]
  PIN t_s[568]
    DIRECTION OUTPUT ;
    USE SIGNAL ;
    PORT
      LAYER M3 ;
        RECT  213.552 647.962 213.57 648 ;
    END
  END t_s[568]
  PIN t_s[569]
    DIRECTION OUTPUT ;
    USE SIGNAL ;
    PORT
      LAYER M5 ;
        RECT  213.84 647.916 213.864 648 ;
    END
  END t_s[569]
  PIN t_s[56]
    DIRECTION OUTPUT ;
    USE SIGNAL ;
    PORT
      LAYER M3 ;
        RECT  60.12 647.962 60.138 648 ;
    END
  END t_s[56]
  PIN t_s[570]
    DIRECTION OUTPUT ;
    USE SIGNAL ;
    PORT
      LAYER M3 ;
        RECT  214.128 647.962 214.146 648 ;
    END
  END t_s[570]
  PIN t_s[571]
    DIRECTION OUTPUT ;
    USE SIGNAL ;
    PORT
      LAYER M5 ;
        RECT  214.464 647.916 214.488 648 ;
    END
  END t_s[571]
  PIN t_s[572]
    DIRECTION OUTPUT ;
    USE SIGNAL ;
    PORT
      LAYER M3 ;
        RECT  214.74 647.962 214.758 648 ;
    END
  END t_s[572]
  PIN t_s[573]
    DIRECTION OUTPUT ;
    USE SIGNAL ;
    PORT
      LAYER M5 ;
        RECT  215.04 647.916 215.064 648 ;
    END
  END t_s[573]
  PIN t_s[574]
    DIRECTION OUTPUT ;
    USE SIGNAL ;
    PORT
      LAYER M3 ;
        RECT  215.352 647.962 215.37 648 ;
    END
  END t_s[574]
  PIN t_s[575]
    DIRECTION OUTPUT ;
    USE SIGNAL ;
    PORT
      LAYER M5 ;
        RECT  215.616 647.916 215.64 648 ;
    END
  END t_s[575]
  PIN t_s[576]
    DIRECTION OUTPUT ;
    USE SIGNAL ;
    PORT
      LAYER M3 ;
        RECT  215.928 647.962 215.946 648 ;
    END
  END t_s[576]
  PIN t_s[577]
    DIRECTION OUTPUT ;
    USE SIGNAL ;
    PORT
      LAYER M5 ;
        RECT  216.24 647.916 216.264 648 ;
    END
  END t_s[577]
  PIN t_s[578]
    DIRECTION OUTPUT ;
    USE SIGNAL ;
    PORT
      LAYER M3 ;
        RECT  216.54 647.962 216.558 648 ;
    END
  END t_s[578]
  PIN t_s[579]
    DIRECTION OUTPUT ;
    USE SIGNAL ;
    PORT
      LAYER M5 ;
        RECT  216.816 647.916 216.84 648 ;
    END
  END t_s[579]
  PIN t_s[57]
    DIRECTION OUTPUT ;
    USE SIGNAL ;
    PORT
      LAYER M5 ;
        RECT  60.432 647.916 60.456 648 ;
    END
  END t_s[57]
  PIN t_s[580]
    DIRECTION OUTPUT ;
    USE SIGNAL ;
    PORT
      LAYER M3 ;
        RECT  217.152 647.962 217.17 648 ;
    END
  END t_s[580]
  PIN t_s[581]
    DIRECTION OUTPUT ;
    USE SIGNAL ;
    PORT
      LAYER M5 ;
        RECT  217.44 647.916 217.464 648 ;
    END
  END t_s[581]
  PIN t_s[582]
    DIRECTION OUTPUT ;
    USE SIGNAL ;
    PORT
      LAYER M3 ;
        RECT  217.728 647.962 217.746 648 ;
    END
  END t_s[582]
  PIN t_s[583]
    DIRECTION OUTPUT ;
    USE SIGNAL ;
    PORT
      LAYER M5 ;
        RECT  218.016 647.916 218.04 648 ;
    END
  END t_s[583]
  PIN t_s[584]
    DIRECTION OUTPUT ;
    USE SIGNAL ;
    PORT
      LAYER M3 ;
        RECT  218.34 647.962 218.358 648 ;
    END
  END t_s[584]
  PIN t_s[585]
    DIRECTION OUTPUT ;
    USE SIGNAL ;
    PORT
      LAYER M5 ;
        RECT  218.64 647.916 218.664 648 ;
    END
  END t_s[585]
  PIN t_s[586]
    DIRECTION OUTPUT ;
    USE SIGNAL ;
    PORT
      LAYER M3 ;
        RECT  218.952 647.962 218.97 648 ;
    END
  END t_s[586]
  PIN t_s[587]
    DIRECTION OUTPUT ;
    USE SIGNAL ;
    PORT
      LAYER M5 ;
        RECT  219.216 647.916 219.24 648 ;
    END
  END t_s[587]
  PIN t_s[588]
    DIRECTION OUTPUT ;
    USE SIGNAL ;
    PORT
      LAYER M3 ;
        RECT  219.528 647.962 219.546 648 ;
    END
  END t_s[588]
  PIN t_s[589]
    DIRECTION OUTPUT ;
    USE SIGNAL ;
    PORT
      LAYER M5 ;
        RECT  219.84 647.916 219.864 648 ;
    END
  END t_s[589]
  PIN t_s[58]
    DIRECTION OUTPUT ;
    USE SIGNAL ;
    PORT
      LAYER M3 ;
        RECT  60.732 647.962 60.75 648 ;
    END
  END t_s[58]
  PIN t_s[590]
    DIRECTION OUTPUT ;
    USE SIGNAL ;
    PORT
      LAYER M3 ;
        RECT  220.14 647.962 220.158 648 ;
    END
  END t_s[590]
  PIN t_s[591]
    DIRECTION OUTPUT ;
    USE SIGNAL ;
    PORT
      LAYER M5 ;
        RECT  220.416 647.916 220.44 648 ;
    END
  END t_s[591]
  PIN t_s[592]
    DIRECTION OUTPUT ;
    USE SIGNAL ;
    PORT
      LAYER M3 ;
        RECT  220.752 647.962 220.77 648 ;
    END
  END t_s[592]
  PIN t_s[593]
    DIRECTION OUTPUT ;
    USE SIGNAL ;
    PORT
      LAYER M5 ;
        RECT  221.04 647.916 221.064 648 ;
    END
  END t_s[593]
  PIN t_s[594]
    DIRECTION OUTPUT ;
    USE SIGNAL ;
    PORT
      LAYER M3 ;
        RECT  221.328 647.962 221.346 648 ;
    END
  END t_s[594]
  PIN t_s[595]
    DIRECTION OUTPUT ;
    USE SIGNAL ;
    PORT
      LAYER M5 ;
        RECT  221.616 647.916 221.64 648 ;
    END
  END t_s[595]
  PIN t_s[596]
    DIRECTION OUTPUT ;
    USE SIGNAL ;
    PORT
      LAYER M3 ;
        RECT  221.94 647.962 221.958 648 ;
    END
  END t_s[596]
  PIN t_s[597]
    DIRECTION OUTPUT ;
    USE SIGNAL ;
    PORT
      LAYER M5 ;
        RECT  222.24 647.916 222.264 648 ;
    END
  END t_s[597]
  PIN t_s[598]
    DIRECTION OUTPUT ;
    USE SIGNAL ;
    PORT
      LAYER M3 ;
        RECT  222.516 647.962 222.534 648 ;
    END
  END t_s[598]
  PIN t_s[599]
    DIRECTION OUTPUT ;
    USE SIGNAL ;
    PORT
      LAYER M5 ;
        RECT  222.816 647.916 222.84 648 ;
    END
  END t_s[599]
  PIN t_s[59]
    DIRECTION OUTPUT ;
    USE SIGNAL ;
    PORT
      LAYER M5 ;
        RECT  61.008 647.916 61.032 648 ;
    END
  END t_s[59]
  PIN t_s[5]
    DIRECTION OUTPUT ;
    USE SIGNAL ;
    PORT
      LAYER M5 ;
        RECT  44.832 647.916 44.856 648 ;
    END
  END t_s[5]
  PIN t_s[600]
    DIRECTION OUTPUT ;
    USE SIGNAL ;
    PORT
      LAYER M3 ;
        RECT  223.128 647.962 223.146 648 ;
    END
  END t_s[600]
  PIN t_s[601]
    DIRECTION OUTPUT ;
    USE SIGNAL ;
    PORT
      LAYER M5 ;
        RECT  223.44 647.916 223.464 648 ;
    END
  END t_s[601]
  PIN t_s[602]
    DIRECTION OUTPUT ;
    USE SIGNAL ;
    PORT
      LAYER M3 ;
        RECT  223.74 647.962 223.758 648 ;
    END
  END t_s[602]
  PIN t_s[603]
    DIRECTION OUTPUT ;
    USE SIGNAL ;
    PORT
      LAYER M5 ;
        RECT  224.016 647.916 224.04 648 ;
    END
  END t_s[603]
  PIN t_s[604]
    DIRECTION OUTPUT ;
    USE SIGNAL ;
    PORT
      LAYER M3 ;
        RECT  224.316 647.962 224.334 648 ;
    END
  END t_s[604]
  PIN t_s[605]
    DIRECTION OUTPUT ;
    USE SIGNAL ;
    PORT
      LAYER M5 ;
        RECT  224.64 647.916 224.664 648 ;
    END
  END t_s[605]
  PIN t_s[606]
    DIRECTION OUTPUT ;
    USE SIGNAL ;
    PORT
      LAYER M3 ;
        RECT  224.928 647.962 224.946 648 ;
    END
  END t_s[606]
  PIN t_s[607]
    DIRECTION OUTPUT ;
    USE SIGNAL ;
    PORT
      LAYER M5 ;
        RECT  225.216 647.916 225.24 648 ;
    END
  END t_s[607]
  PIN t_s[608]
    DIRECTION OUTPUT ;
    USE SIGNAL ;
    PORT
      LAYER M3 ;
        RECT  225.54 647.962 225.558 648 ;
    END
  END t_s[608]
  PIN t_s[609]
    DIRECTION OUTPUT ;
    USE SIGNAL ;
    PORT
      LAYER M5 ;
        RECT  225.84 647.916 225.864 648 ;
    END
  END t_s[609]
  PIN t_s[60]
    DIRECTION OUTPUT ;
    USE SIGNAL ;
    PORT
      LAYER M3 ;
        RECT  61.308 647.962 61.326 648 ;
    END
  END t_s[60]
  PIN t_s[610]
    DIRECTION OUTPUT ;
    USE SIGNAL ;
    PORT
      LAYER M3 ;
        RECT  226.116 647.962 226.134 648 ;
    END
  END t_s[610]
  PIN t_s[611]
    DIRECTION OUTPUT ;
    USE SIGNAL ;
    PORT
      LAYER M5 ;
        RECT  226.416 647.916 226.44 648 ;
    END
  END t_s[611]
  PIN t_s[612]
    DIRECTION OUTPUT ;
    USE SIGNAL ;
    PORT
      LAYER M3 ;
        RECT  226.728 647.962 226.746 648 ;
    END
  END t_s[612]
  PIN t_s[613]
    DIRECTION OUTPUT ;
    USE SIGNAL ;
    PORT
      LAYER M5 ;
        RECT  227.04 647.916 227.064 648 ;
    END
  END t_s[613]
  PIN t_s[614]
    DIRECTION OUTPUT ;
    USE SIGNAL ;
    PORT
      LAYER M3 ;
        RECT  227.34 647.962 227.358 648 ;
    END
  END t_s[614]
  PIN t_s[615]
    DIRECTION OUTPUT ;
    USE SIGNAL ;
    PORT
      LAYER M5 ;
        RECT  227.616 647.916 227.64 648 ;
    END
  END t_s[615]
  PIN t_s[616]
    DIRECTION OUTPUT ;
    USE SIGNAL ;
    PORT
      LAYER M3 ;
        RECT  227.916 647.962 227.934 648 ;
    END
  END t_s[616]
  PIN t_s[617]
    DIRECTION OUTPUT ;
    USE SIGNAL ;
    PORT
      LAYER M5 ;
        RECT  228.24 647.916 228.264 648 ;
    END
  END t_s[617]
  PIN t_s[618]
    DIRECTION OUTPUT ;
    USE SIGNAL ;
    PORT
      LAYER M3 ;
        RECT  228.528 647.962 228.546 648 ;
    END
  END t_s[618]
  PIN t_s[619]
    DIRECTION OUTPUT ;
    USE SIGNAL ;
    PORT
      LAYER M5 ;
        RECT  228.816 647.916 228.84 648 ;
    END
  END t_s[619]
  PIN t_s[61]
    DIRECTION OUTPUT ;
    USE SIGNAL ;
    PORT
      LAYER M5 ;
        RECT  61.632 647.916 61.656 648 ;
    END
  END t_s[61]
  PIN t_s[620]
    DIRECTION OUTPUT ;
    USE SIGNAL ;
    PORT
      LAYER M3 ;
        RECT  229.14 647.962 229.158 648 ;
    END
  END t_s[620]
  PIN t_s[621]
    DIRECTION OUTPUT ;
    USE SIGNAL ;
    PORT
      LAYER M5 ;
        RECT  229.44 647.916 229.464 648 ;
    END
  END t_s[621]
  PIN t_s[622]
    DIRECTION OUTPUT ;
    USE SIGNAL ;
    PORT
      LAYER M3 ;
        RECT  229.716 647.962 229.734 648 ;
    END
  END t_s[622]
  PIN t_s[623]
    DIRECTION OUTPUT ;
    USE SIGNAL ;
    PORT
      LAYER M5 ;
        RECT  230.016 647.916 230.04 648 ;
    END
  END t_s[623]
  PIN t_s[624]
    DIRECTION OUTPUT ;
    USE SIGNAL ;
    PORT
      LAYER M3 ;
        RECT  230.328 647.962 230.346 648 ;
    END
  END t_s[624]
  PIN t_s[625]
    DIRECTION OUTPUT ;
    USE SIGNAL ;
    PORT
      LAYER M5 ;
        RECT  230.64 647.916 230.664 648 ;
    END
  END t_s[625]
  PIN t_s[626]
    DIRECTION OUTPUT ;
    USE SIGNAL ;
    PORT
      LAYER M3 ;
        RECT  230.94 647.962 230.958 648 ;
    END
  END t_s[626]
  PIN t_s[627]
    DIRECTION OUTPUT ;
    USE SIGNAL ;
    PORT
      LAYER M5 ;
        RECT  231.216 647.916 231.24 648 ;
    END
  END t_s[627]
  PIN t_s[628]
    DIRECTION OUTPUT ;
    USE SIGNAL ;
    PORT
      LAYER M3 ;
        RECT  231.516 647.962 231.534 648 ;
    END
  END t_s[628]
  PIN t_s[629]
    DIRECTION OUTPUT ;
    USE SIGNAL ;
    PORT
      LAYER M5 ;
        RECT  231.84 647.916 231.864 648 ;
    END
  END t_s[629]
  PIN t_s[62]
    DIRECTION OUTPUT ;
    USE SIGNAL ;
    PORT
      LAYER M3 ;
        RECT  61.92 647.962 61.938 648 ;
    END
  END t_s[62]
  PIN t_s[630]
    DIRECTION OUTPUT ;
    USE SIGNAL ;
    PORT
      LAYER M3 ;
        RECT  232.128 647.962 232.146 648 ;
    END
  END t_s[630]
  PIN t_s[631]
    DIRECTION OUTPUT ;
    USE SIGNAL ;
    PORT
      LAYER M5 ;
        RECT  232.416 647.916 232.44 648 ;
    END
  END t_s[631]
  PIN t_s[632]
    DIRECTION OUTPUT ;
    USE SIGNAL ;
    PORT
      LAYER M3 ;
        RECT  232.74 647.962 232.758 648 ;
    END
  END t_s[632]
  PIN t_s[633]
    DIRECTION OUTPUT ;
    USE SIGNAL ;
    PORT
      LAYER M5 ;
        RECT  233.04 647.916 233.064 648 ;
    END
  END t_s[633]
  PIN t_s[634]
    DIRECTION OUTPUT ;
    USE SIGNAL ;
    PORT
      LAYER M3 ;
        RECT  233.316 647.962 233.334 648 ;
    END
  END t_s[634]
  PIN t_s[635]
    DIRECTION OUTPUT ;
    USE SIGNAL ;
    PORT
      LAYER M5 ;
        RECT  233.616 647.916 233.64 648 ;
    END
  END t_s[635]
  PIN t_s[636]
    DIRECTION OUTPUT ;
    USE SIGNAL ;
    PORT
      LAYER M3 ;
        RECT  233.928 647.962 233.946 648 ;
    END
  END t_s[636]
  PIN t_s[637]
    DIRECTION OUTPUT ;
    USE SIGNAL ;
    PORT
      LAYER M5 ;
        RECT  234.24 647.916 234.264 648 ;
    END
  END t_s[637]
  PIN t_s[638]
    DIRECTION OUTPUT ;
    USE SIGNAL ;
    PORT
      LAYER M3 ;
        RECT  234.504 647.962 234.522 648 ;
    END
  END t_s[638]
  PIN t_s[639]
    DIRECTION OUTPUT ;
    USE SIGNAL ;
    PORT
      LAYER M5 ;
        RECT  234.816 647.916 234.84 648 ;
    END
  END t_s[639]
  PIN t_s[63]
    DIRECTION OUTPUT ;
    USE SIGNAL ;
    PORT
      LAYER M5 ;
        RECT  62.208 647.916 62.232 648 ;
    END
  END t_s[63]
  PIN t_s[640]
    DIRECTION OUTPUT ;
    USE SIGNAL ;
    PORT
      LAYER M3 ;
        RECT  235.116 647.962 235.134 648 ;
    END
  END t_s[640]
  PIN t_s[641]
    DIRECTION OUTPUT ;
    USE SIGNAL ;
    PORT
      LAYER M5 ;
        RECT  235.44 647.916 235.464 648 ;
    END
  END t_s[641]
  PIN t_s[642]
    DIRECTION OUTPUT ;
    USE SIGNAL ;
    PORT
      LAYER M3 ;
        RECT  235.728 647.962 235.746 648 ;
    END
  END t_s[642]
  PIN t_s[643]
    DIRECTION OUTPUT ;
    USE SIGNAL ;
    PORT
      LAYER M5 ;
        RECT  236.016 647.916 236.04 648 ;
    END
  END t_s[643]
  PIN t_s[644]
    DIRECTION OUTPUT ;
    USE SIGNAL ;
    PORT
      LAYER M3 ;
        RECT  236.304 647.962 236.322 648 ;
    END
  END t_s[644]
  PIN t_s[645]
    DIRECTION OUTPUT ;
    USE SIGNAL ;
    PORT
      LAYER M5 ;
        RECT  236.592 647.916 236.616 648 ;
    END
  END t_s[645]
  PIN t_s[646]
    DIRECTION OUTPUT ;
    USE SIGNAL ;
    PORT
      LAYER M3 ;
        RECT  236.916 647.962 236.934 648 ;
    END
  END t_s[646]
  PIN t_s[647]
    DIRECTION OUTPUT ;
    USE SIGNAL ;
    PORT
      LAYER M5 ;
        RECT  237.216 647.916 237.24 648 ;
    END
  END t_s[647]
  PIN t_s[648]
    DIRECTION OUTPUT ;
    USE SIGNAL ;
    PORT
      LAYER M3 ;
        RECT  237.528 647.962 237.546 648 ;
    END
  END t_s[648]
  PIN t_s[649]
    DIRECTION OUTPUT ;
    USE SIGNAL ;
    PORT
      LAYER M5 ;
        RECT  237.792 647.916 237.816 648 ;
    END
  END t_s[649]
  PIN t_s[64]
    DIRECTION OUTPUT ;
    USE SIGNAL ;
    PORT
      LAYER M3 ;
        RECT  62.532 647.962 62.55 648 ;
    END
  END t_s[64]
  PIN t_s[650]
    DIRECTION OUTPUT ;
    USE SIGNAL ;
    PORT
      LAYER M3 ;
        RECT  238.104 647.962 238.122 648 ;
    END
  END t_s[650]
  PIN t_s[651]
    DIRECTION OUTPUT ;
    USE SIGNAL ;
    PORT
      LAYER M5 ;
        RECT  238.416 647.916 238.44 648 ;
    END
  END t_s[651]
  PIN t_s[652]
    DIRECTION OUTPUT ;
    USE SIGNAL ;
    PORT
      LAYER M3 ;
        RECT  238.716 647.962 238.734 648 ;
    END
  END t_s[652]
  PIN t_s[653]
    DIRECTION OUTPUT ;
    USE SIGNAL ;
    PORT
      LAYER M5 ;
        RECT  238.992 647.916 239.016 648 ;
    END
  END t_s[653]
  PIN t_s[654]
    DIRECTION OUTPUT ;
    USE SIGNAL ;
    PORT
      LAYER M3 ;
        RECT  239.328 647.962 239.346 648 ;
    END
  END t_s[654]
  PIN t_s[655]
    DIRECTION OUTPUT ;
    USE SIGNAL ;
    PORT
      LAYER M5 ;
        RECT  239.616 647.916 239.64 648 ;
    END
  END t_s[655]
  PIN t_s[656]
    DIRECTION OUTPUT ;
    USE SIGNAL ;
    PORT
      LAYER M3 ;
        RECT  239.904 647.962 239.922 648 ;
    END
  END t_s[656]
  PIN t_s[657]
    DIRECTION OUTPUT ;
    USE SIGNAL ;
    PORT
      LAYER M5 ;
        RECT  240.192 647.916 240.216 648 ;
    END
  END t_s[657]
  PIN t_s[658]
    DIRECTION OUTPUT ;
    USE SIGNAL ;
    PORT
      LAYER M3 ;
        RECT  240.516 647.962 240.534 648 ;
    END
  END t_s[658]
  PIN t_s[659]
    DIRECTION OUTPUT ;
    USE SIGNAL ;
    PORT
      LAYER M5 ;
        RECT  240.816 647.916 240.84 648 ;
    END
  END t_s[659]
  PIN t_s[65]
    DIRECTION OUTPUT ;
    USE SIGNAL ;
    PORT
      LAYER M5 ;
        RECT  62.832 647.916 62.856 648 ;
    END
  END t_s[65]
  PIN t_s[660]
    DIRECTION OUTPUT ;
    USE SIGNAL ;
    PORT
      LAYER M3 ;
        RECT  241.128 647.962 241.146 648 ;
    END
  END t_s[660]
  PIN t_s[661]
    DIRECTION OUTPUT ;
    USE SIGNAL ;
    PORT
      LAYER M5 ;
        RECT  241.392 647.916 241.416 648 ;
    END
  END t_s[661]
  PIN t_s[662]
    DIRECTION OUTPUT ;
    USE SIGNAL ;
    PORT
      LAYER M3 ;
        RECT  241.704 647.962 241.722 648 ;
    END
  END t_s[662]
  PIN t_s[663]
    DIRECTION OUTPUT ;
    USE SIGNAL ;
    PORT
      LAYER M5 ;
        RECT  242.016 647.916 242.04 648 ;
    END
  END t_s[663]
  PIN t_s[664]
    DIRECTION OUTPUT ;
    USE SIGNAL ;
    PORT
      LAYER M3 ;
        RECT  242.316 647.962 242.334 648 ;
    END
  END t_s[664]
  PIN t_s[665]
    DIRECTION OUTPUT ;
    USE SIGNAL ;
    PORT
      LAYER M5 ;
        RECT  242.592 647.916 242.616 648 ;
    END
  END t_s[665]
  PIN t_s[666]
    DIRECTION OUTPUT ;
    USE SIGNAL ;
    PORT
      LAYER M3 ;
        RECT  242.928 647.962 242.946 648 ;
    END
  END t_s[666]
  PIN t_s[667]
    DIRECTION OUTPUT ;
    USE SIGNAL ;
    PORT
      LAYER M5 ;
        RECT  243.216 647.916 243.24 648 ;
    END
  END t_s[667]
  PIN t_s[668]
    DIRECTION OUTPUT ;
    USE SIGNAL ;
    PORT
      LAYER M3 ;
        RECT  243.504 647.962 243.522 648 ;
    END
  END t_s[668]
  PIN t_s[669]
    DIRECTION OUTPUT ;
    USE SIGNAL ;
    PORT
      LAYER M5 ;
        RECT  243.792 647.916 243.816 648 ;
    END
  END t_s[669]
  PIN t_s[66]
    DIRECTION OUTPUT ;
    USE SIGNAL ;
    PORT
      LAYER M3 ;
        RECT  63.108 647.962 63.126 648 ;
    END
  END t_s[66]
  PIN t_s[670]
    DIRECTION OUTPUT ;
    USE SIGNAL ;
    PORT
      LAYER M3 ;
        RECT  244.116 647.962 244.134 648 ;
    END
  END t_s[670]
  PIN t_s[671]
    DIRECTION OUTPUT ;
    USE SIGNAL ;
    PORT
      LAYER M5 ;
        RECT  244.416 647.916 244.44 648 ;
    END
  END t_s[671]
  PIN t_s[672]
    DIRECTION OUTPUT ;
    USE SIGNAL ;
    PORT
      LAYER M3 ;
        RECT  244.692 647.962 244.71 648 ;
    END
  END t_s[672]
  PIN t_s[673]
    DIRECTION OUTPUT ;
    USE SIGNAL ;
    PORT
      LAYER M5 ;
        RECT  244.992 647.916 245.016 648 ;
    END
  END t_s[673]
  PIN t_s[674]
    DIRECTION OUTPUT ;
    USE SIGNAL ;
    PORT
      LAYER M3 ;
        RECT  245.304 647.962 245.322 648 ;
    END
  END t_s[674]
  PIN t_s[675]
    DIRECTION OUTPUT ;
    USE SIGNAL ;
    PORT
      LAYER M5 ;
        RECT  245.616 647.916 245.64 648 ;
    END
  END t_s[675]
  PIN t_s[676]
    DIRECTION OUTPUT ;
    USE SIGNAL ;
    PORT
      LAYER M3 ;
        RECT  245.916 647.962 245.934 648 ;
    END
  END t_s[676]
  PIN t_s[677]
    DIRECTION OUTPUT ;
    USE SIGNAL ;
    PORT
      LAYER M5 ;
        RECT  246.192 647.916 246.216 648 ;
    END
  END t_s[677]
  PIN t_s[678]
    DIRECTION OUTPUT ;
    USE SIGNAL ;
    PORT
      LAYER M3 ;
        RECT  246.492 647.962 246.51 648 ;
    END
  END t_s[678]
  PIN t_s[679]
    DIRECTION OUTPUT ;
    USE SIGNAL ;
    PORT
      LAYER M5 ;
        RECT  246.816 647.916 246.84 648 ;
    END
  END t_s[679]
  PIN t_s[67]
    DIRECTION OUTPUT ;
    USE SIGNAL ;
    PORT
      LAYER M5 ;
        RECT  63.408 647.916 63.432 648 ;
    END
  END t_s[67]
  PIN t_s[680]
    DIRECTION OUTPUT ;
    USE SIGNAL ;
    PORT
      LAYER M3 ;
        RECT  247.104 647.962 247.122 648 ;
    END
  END t_s[680]
  PIN t_s[681]
    DIRECTION OUTPUT ;
    USE SIGNAL ;
    PORT
      LAYER M5 ;
        RECT  247.392 647.916 247.416 648 ;
    END
  END t_s[681]
  PIN t_s[682]
    DIRECTION OUTPUT ;
    USE SIGNAL ;
    PORT
      LAYER M3 ;
        RECT  247.716 647.962 247.734 648 ;
    END
  END t_s[682]
  PIN t_s[683]
    DIRECTION OUTPUT ;
    USE SIGNAL ;
    PORT
      LAYER M5 ;
        RECT  248.016 647.916 248.04 648 ;
    END
  END t_s[683]
  PIN t_s[684]
    DIRECTION OUTPUT ;
    USE SIGNAL ;
    PORT
      LAYER M3 ;
        RECT  248.292 647.962 248.31 648 ;
    END
  END t_s[684]
  PIN t_s[685]
    DIRECTION OUTPUT ;
    USE SIGNAL ;
    PORT
      LAYER M5 ;
        RECT  248.592 647.916 248.616 648 ;
    END
  END t_s[685]
  PIN t_s[686]
    DIRECTION OUTPUT ;
    USE SIGNAL ;
    PORT
      LAYER M3 ;
        RECT  248.904 647.962 248.922 648 ;
    END
  END t_s[686]
  PIN t_s[687]
    DIRECTION OUTPUT ;
    USE SIGNAL ;
    PORT
      LAYER M5 ;
        RECT  249.216 647.916 249.24 648 ;
    END
  END t_s[687]
  PIN t_s[688]
    DIRECTION OUTPUT ;
    USE SIGNAL ;
    PORT
      LAYER M3 ;
        RECT  249.516 647.962 249.534 648 ;
    END
  END t_s[688]
  PIN t_s[689]
    DIRECTION OUTPUT ;
    USE SIGNAL ;
    PORT
      LAYER M5 ;
        RECT  249.792 647.916 249.816 648 ;
    END
  END t_s[689]
  PIN t_s[68]
    DIRECTION OUTPUT ;
    USE SIGNAL ;
    PORT
      LAYER M3 ;
        RECT  63.72 647.962 63.738 648 ;
    END
  END t_s[68]
  PIN t_s[690]
    DIRECTION OUTPUT ;
    USE SIGNAL ;
    PORT
      LAYER M3 ;
        RECT  250.092 647.962 250.11 648 ;
    END
  END t_s[690]
  PIN t_s[691]
    DIRECTION OUTPUT ;
    USE SIGNAL ;
    PORT
      LAYER M5 ;
        RECT  250.416 647.916 250.44 648 ;
    END
  END t_s[691]
  PIN t_s[692]
    DIRECTION OUTPUT ;
    USE SIGNAL ;
    PORT
      LAYER M3 ;
        RECT  250.704 647.962 250.722 648 ;
    END
  END t_s[692]
  PIN t_s[693]
    DIRECTION OUTPUT ;
    USE SIGNAL ;
    PORT
      LAYER M5 ;
        RECT  250.992 647.916 251.016 648 ;
    END
  END t_s[693]
  PIN t_s[694]
    DIRECTION OUTPUT ;
    USE SIGNAL ;
    PORT
      LAYER M3 ;
        RECT  251.316 647.962 251.334 648 ;
    END
  END t_s[694]
  PIN t_s[695]
    DIRECTION OUTPUT ;
    USE SIGNAL ;
    PORT
      LAYER M5 ;
        RECT  251.616 647.916 251.64 648 ;
    END
  END t_s[695]
  PIN t_s[696]
    DIRECTION OUTPUT ;
    USE SIGNAL ;
    PORT
      LAYER M3 ;
        RECT  251.892 647.962 251.91 648 ;
    END
  END t_s[696]
  PIN t_s[697]
    DIRECTION OUTPUT ;
    USE SIGNAL ;
    PORT
      LAYER M5 ;
        RECT  252.192 647.916 252.216 648 ;
    END
  END t_s[697]
  PIN t_s[698]
    DIRECTION OUTPUT ;
    USE SIGNAL ;
    PORT
      LAYER M3 ;
        RECT  252.504 647.962 252.522 648 ;
    END
  END t_s[698]
  PIN t_s[699]
    DIRECTION OUTPUT ;
    USE SIGNAL ;
    PORT
      LAYER M5 ;
        RECT  252.816 647.916 252.84 648 ;
    END
  END t_s[699]
  PIN t_s[69]
    DIRECTION OUTPUT ;
    USE SIGNAL ;
    PORT
      LAYER M5 ;
        RECT  64.032 647.916 64.056 648 ;
    END
  END t_s[69]
  PIN t_s[6]
    DIRECTION OUTPUT ;
    USE SIGNAL ;
    PORT
      LAYER M3 ;
        RECT  45.144 647.962 45.162 648 ;
    END
  END t_s[6]
  PIN t_s[700]
    DIRECTION OUTPUT ;
    USE SIGNAL ;
    PORT
      LAYER M3 ;
        RECT  253.116 647.962 253.134 648 ;
    END
  END t_s[700]
  PIN t_s[701]
    DIRECTION OUTPUT ;
    USE SIGNAL ;
    PORT
      LAYER M5 ;
        RECT  253.392 647.916 253.416 648 ;
    END
  END t_s[701]
  PIN t_s[702]
    DIRECTION OUTPUT ;
    USE SIGNAL ;
    PORT
      LAYER M3 ;
        RECT  253.692 647.962 253.71 648 ;
    END
  END t_s[702]
  PIN t_s[703]
    DIRECTION OUTPUT ;
    USE SIGNAL ;
    PORT
      LAYER M5 ;
        RECT  254.016 647.916 254.04 648 ;
    END
  END t_s[703]
  PIN t_s[704]
    DIRECTION OUTPUT ;
    USE SIGNAL ;
    PORT
      LAYER M3 ;
        RECT  254.304 647.962 254.322 648 ;
    END
  END t_s[704]
  PIN t_s[705]
    DIRECTION OUTPUT ;
    USE SIGNAL ;
    PORT
      LAYER M5 ;
        RECT  254.592 647.916 254.616 648 ;
    END
  END t_s[705]
  PIN t_s[706]
    DIRECTION OUTPUT ;
    USE SIGNAL ;
    PORT
      LAYER M3 ;
        RECT  254.88 647.962 254.898 648 ;
    END
  END t_s[706]
  PIN t_s[707]
    DIRECTION OUTPUT ;
    USE SIGNAL ;
    PORT
      LAYER M5 ;
        RECT  255.216 647.916 255.24 648 ;
    END
  END t_s[707]
  PIN t_s[708]
    DIRECTION OUTPUT ;
    USE SIGNAL ;
    PORT
      LAYER M3 ;
        RECT  255.492 647.962 255.51 648 ;
    END
  END t_s[708]
  PIN t_s[709]
    DIRECTION OUTPUT ;
    USE SIGNAL ;
    PORT
      LAYER M5 ;
        RECT  255.792 647.916 255.816 648 ;
    END
  END t_s[709]
  PIN t_s[70]
    DIRECTION OUTPUT ;
    USE SIGNAL ;
    PORT
      LAYER M3 ;
        RECT  64.332 647.962 64.35 648 ;
    END
  END t_s[70]
  PIN t_s[710]
    DIRECTION OUTPUT ;
    USE SIGNAL ;
    PORT
      LAYER M3 ;
        RECT  256.104 647.962 256.122 648 ;
    END
  END t_s[710]
  PIN t_s[711]
    DIRECTION OUTPUT ;
    USE SIGNAL ;
    PORT
      LAYER M5 ;
        RECT  256.368 647.916 256.392 648 ;
    END
  END t_s[711]
  PIN t_s[712]
    DIRECTION OUTPUT ;
    USE SIGNAL ;
    PORT
      LAYER M3 ;
        RECT  256.68 647.962 256.698 648 ;
    END
  END t_s[712]
  PIN t_s[713]
    DIRECTION OUTPUT ;
    USE SIGNAL ;
    PORT
      LAYER M5 ;
        RECT  256.992 647.916 257.016 648 ;
    END
  END t_s[713]
  PIN t_s[714]
    DIRECTION OUTPUT ;
    USE SIGNAL ;
    PORT
      LAYER M3 ;
        RECT  257.292 647.962 257.31 648 ;
    END
  END t_s[714]
  PIN t_s[715]
    DIRECTION OUTPUT ;
    USE SIGNAL ;
    PORT
      LAYER M5 ;
        RECT  257.568 647.916 257.592 648 ;
    END
  END t_s[715]
  PIN t_s[716]
    DIRECTION OUTPUT ;
    USE SIGNAL ;
    PORT
      LAYER M3 ;
        RECT  257.904 647.962 257.922 648 ;
    END
  END t_s[716]
  PIN t_s[717]
    DIRECTION OUTPUT ;
    USE SIGNAL ;
    PORT
      LAYER M5 ;
        RECT  258.192 647.916 258.216 648 ;
    END
  END t_s[717]
  PIN t_s[718]
    DIRECTION OUTPUT ;
    USE SIGNAL ;
    PORT
      LAYER M3 ;
        RECT  258.48 647.962 258.498 648 ;
    END
  END t_s[718]
  PIN t_s[719]
    DIRECTION OUTPUT ;
    USE SIGNAL ;
    PORT
      LAYER M5 ;
        RECT  258.768 647.916 258.792 648 ;
    END
  END t_s[719]
  PIN t_s[71]
    DIRECTION OUTPUT ;
    USE SIGNAL ;
    PORT
      LAYER M5 ;
        RECT  64.608 647.916 64.632 648 ;
    END
  END t_s[71]
  PIN t_s[720]
    DIRECTION OUTPUT ;
    USE SIGNAL ;
    PORT
      LAYER M3 ;
        RECT  259.092 647.962 259.11 648 ;
    END
  END t_s[720]
  PIN t_s[721]
    DIRECTION OUTPUT ;
    USE SIGNAL ;
    PORT
      LAYER M5 ;
        RECT  259.392 647.916 259.416 648 ;
    END
  END t_s[721]
  PIN t_s[722]
    DIRECTION OUTPUT ;
    USE SIGNAL ;
    PORT
      LAYER M3 ;
        RECT  259.704 647.962 259.722 648 ;
    END
  END t_s[722]
  PIN t_s[723]
    DIRECTION OUTPUT ;
    USE SIGNAL ;
    PORT
      LAYER M5 ;
        RECT  259.968 647.916 259.992 648 ;
    END
  END t_s[723]
  PIN t_s[724]
    DIRECTION OUTPUT ;
    USE SIGNAL ;
    PORT
      LAYER M3 ;
        RECT  260.28 647.962 260.298 648 ;
    END
  END t_s[724]
  PIN t_s[725]
    DIRECTION OUTPUT ;
    USE SIGNAL ;
    PORT
      LAYER M5 ;
        RECT  260.592 647.916 260.616 648 ;
    END
  END t_s[725]
  PIN t_s[726]
    DIRECTION OUTPUT ;
    USE SIGNAL ;
    PORT
      LAYER M3 ;
        RECT  260.892 647.962 260.91 648 ;
    END
  END t_s[726]
  PIN t_s[727]
    DIRECTION OUTPUT ;
    USE SIGNAL ;
    PORT
      LAYER M5 ;
        RECT  261.168 647.916 261.192 648 ;
    END
  END t_s[727]
  PIN t_s[728]
    DIRECTION OUTPUT ;
    USE SIGNAL ;
    PORT
      LAYER M3 ;
        RECT  261.504 647.962 261.522 648 ;
    END
  END t_s[728]
  PIN t_s[729]
    DIRECTION OUTPUT ;
    USE SIGNAL ;
    PORT
      LAYER M5 ;
        RECT  261.792 647.916 261.816 648 ;
    END
  END t_s[729]
  PIN t_s[72]
    DIRECTION OUTPUT ;
    USE SIGNAL ;
    PORT
      LAYER M3 ;
        RECT  64.908 647.962 64.926 648 ;
    END
  END t_s[72]
  PIN t_s[730]
    DIRECTION OUTPUT ;
    USE SIGNAL ;
    PORT
      LAYER M3 ;
        RECT  262.08 647.962 262.098 648 ;
    END
  END t_s[730]
  PIN t_s[731]
    DIRECTION OUTPUT ;
    USE SIGNAL ;
    PORT
      LAYER M5 ;
        RECT  262.368 647.916 262.392 648 ;
    END
  END t_s[731]
  PIN t_s[732]
    DIRECTION OUTPUT ;
    USE SIGNAL ;
    PORT
      LAYER M3 ;
        RECT  262.692 647.962 262.71 648 ;
    END
  END t_s[732]
  PIN t_s[733]
    DIRECTION OUTPUT ;
    USE SIGNAL ;
    PORT
      LAYER M5 ;
        RECT  262.992 647.916 263.016 648 ;
    END
  END t_s[733]
  PIN t_s[734]
    DIRECTION OUTPUT ;
    USE SIGNAL ;
    PORT
      LAYER M3 ;
        RECT  263.304 647.962 263.322 648 ;
    END
  END t_s[734]
  PIN t_s[735]
    DIRECTION OUTPUT ;
    USE SIGNAL ;
    PORT
      LAYER M5 ;
        RECT  263.568 647.916 263.592 648 ;
    END
  END t_s[735]
  PIN t_s[736]
    DIRECTION OUTPUT ;
    USE SIGNAL ;
    PORT
      LAYER M3 ;
        RECT  263.88 647.962 263.898 648 ;
    END
  END t_s[736]
  PIN t_s[737]
    DIRECTION OUTPUT ;
    USE SIGNAL ;
    PORT
      LAYER M5 ;
        RECT  264.192 647.916 264.216 648 ;
    END
  END t_s[737]
  PIN t_s[738]
    DIRECTION OUTPUT ;
    USE SIGNAL ;
    PORT
      LAYER M3 ;
        RECT  264.492 647.962 264.51 648 ;
    END
  END t_s[738]
  PIN t_s[739]
    DIRECTION OUTPUT ;
    USE SIGNAL ;
    PORT
      LAYER M5 ;
        RECT  264.768 647.916 264.792 648 ;
    END
  END t_s[739]
  PIN t_s[73]
    DIRECTION OUTPUT ;
    USE SIGNAL ;
    PORT
      LAYER M5 ;
        RECT  65.232 647.916 65.256 648 ;
    END
  END t_s[73]
  PIN t_s[740]
    DIRECTION OUTPUT ;
    USE SIGNAL ;
    PORT
      LAYER M3 ;
        RECT  265.068 647.962 265.086 648 ;
    END
  END t_s[740]
  PIN t_s[741]
    DIRECTION OUTPUT ;
    USE SIGNAL ;
    PORT
      LAYER M5 ;
        RECT  265.392 647.916 265.416 648 ;
    END
  END t_s[741]
  PIN t_s[742]
    DIRECTION OUTPUT ;
    USE SIGNAL ;
    PORT
      LAYER M3 ;
        RECT  265.68 647.962 265.698 648 ;
    END
  END t_s[742]
  PIN t_s[743]
    DIRECTION OUTPUT ;
    USE SIGNAL ;
    PORT
      LAYER M5 ;
        RECT  265.968 647.916 265.992 648 ;
    END
  END t_s[743]
  PIN t_s[744]
    DIRECTION OUTPUT ;
    USE SIGNAL ;
    PORT
      LAYER M3 ;
        RECT  266.292 647.962 266.31 648 ;
    END
  END t_s[744]
  PIN t_s[745]
    DIRECTION OUTPUT ;
    USE SIGNAL ;
    PORT
      LAYER M5 ;
        RECT  266.592 647.916 266.616 648 ;
    END
  END t_s[745]
  PIN t_s[746]
    DIRECTION OUTPUT ;
    USE SIGNAL ;
    PORT
      LAYER M3 ;
        RECT  266.868 647.962 266.886 648 ;
    END
  END t_s[746]
  PIN t_s[747]
    DIRECTION OUTPUT ;
    USE SIGNAL ;
    PORT
      LAYER M5 ;
        RECT  267.168 647.916 267.192 648 ;
    END
  END t_s[747]
  PIN t_s[748]
    DIRECTION OUTPUT ;
    USE SIGNAL ;
    PORT
      LAYER M3 ;
        RECT  267.48 647.962 267.498 648 ;
    END
  END t_s[748]
  PIN t_s[749]
    DIRECTION OUTPUT ;
    USE SIGNAL ;
    PORT
      LAYER M5 ;
        RECT  267.792 647.916 267.816 648 ;
    END
  END t_s[749]
  PIN t_s[74]
    DIRECTION OUTPUT ;
    USE SIGNAL ;
    PORT
      LAYER M3 ;
        RECT  65.52 647.962 65.538 648 ;
    END
  END t_s[74]
  PIN t_s[750]
    DIRECTION OUTPUT ;
    USE SIGNAL ;
    PORT
      LAYER M3 ;
        RECT  268.092 647.962 268.11 648 ;
    END
  END t_s[750]
  PIN t_s[751]
    DIRECTION OUTPUT ;
    USE SIGNAL ;
    PORT
      LAYER M5 ;
        RECT  268.368 647.916 268.392 648 ;
    END
  END t_s[751]
  PIN t_s[752]
    DIRECTION OUTPUT ;
    USE SIGNAL ;
    PORT
      LAYER M3 ;
        RECT  268.668 647.962 268.686 648 ;
    END
  END t_s[752]
  PIN t_s[753]
    DIRECTION OUTPUT ;
    USE SIGNAL ;
    PORT
      LAYER M5 ;
        RECT  268.992 647.916 269.016 648 ;
    END
  END t_s[753]
  PIN t_s[754]
    DIRECTION OUTPUT ;
    USE SIGNAL ;
    PORT
      LAYER M3 ;
        RECT  269.28 647.962 269.298 648 ;
    END
  END t_s[754]
  PIN t_s[755]
    DIRECTION OUTPUT ;
    USE SIGNAL ;
    PORT
      LAYER M5 ;
        RECT  269.568 647.916 269.592 648 ;
    END
  END t_s[755]
  PIN t_s[756]
    DIRECTION OUTPUT ;
    USE SIGNAL ;
    PORT
      LAYER M3 ;
        RECT  269.892 647.962 269.91 648 ;
    END
  END t_s[756]
  PIN t_s[757]
    DIRECTION OUTPUT ;
    USE SIGNAL ;
    PORT
      LAYER M5 ;
        RECT  270.192 647.916 270.216 648 ;
    END
  END t_s[757]
  PIN t_s[758]
    DIRECTION OUTPUT ;
    USE SIGNAL ;
    PORT
      LAYER M3 ;
        RECT  270.468 647.962 270.486 648 ;
    END
  END t_s[758]
  PIN t_s[759]
    DIRECTION OUTPUT ;
    USE SIGNAL ;
    PORT
      LAYER M5 ;
        RECT  270.768 647.916 270.792 648 ;
    END
  END t_s[759]
  PIN t_s[75]
    DIRECTION OUTPUT ;
    USE SIGNAL ;
    PORT
      LAYER M5 ;
        RECT  65.808 647.916 65.832 648 ;
    END
  END t_s[75]
  PIN t_s[760]
    DIRECTION OUTPUT ;
    USE SIGNAL ;
    PORT
      LAYER M3 ;
        RECT  271.08 647.962 271.098 648 ;
    END
  END t_s[760]
  PIN t_s[761]
    DIRECTION OUTPUT ;
    USE SIGNAL ;
    PORT
      LAYER M5 ;
        RECT  271.392 647.916 271.416 648 ;
    END
  END t_s[761]
  PIN t_s[762]
    DIRECTION OUTPUT ;
    USE SIGNAL ;
    PORT
      LAYER M3 ;
        RECT  271.692 647.962 271.71 648 ;
    END
  END t_s[762]
  PIN t_s[763]
    DIRECTION OUTPUT ;
    USE SIGNAL ;
    PORT
      LAYER M5 ;
        RECT  271.968 647.916 271.992 648 ;
    END
  END t_s[763]
  PIN t_s[764]
    DIRECTION OUTPUT ;
    USE SIGNAL ;
    PORT
      LAYER M3 ;
        RECT  272.268 647.962 272.286 648 ;
    END
  END t_s[764]
  PIN t_s[765]
    DIRECTION OUTPUT ;
    USE SIGNAL ;
    PORT
      LAYER M5 ;
        RECT  272.592 647.916 272.616 648 ;
    END
  END t_s[765]
  PIN t_s[766]
    DIRECTION OUTPUT ;
    USE SIGNAL ;
    PORT
      LAYER M3 ;
        RECT  272.88 647.962 272.898 648 ;
    END
  END t_s[766]
  PIN t_s[767]
    DIRECTION OUTPUT ;
    USE SIGNAL ;
    PORT
      LAYER M5 ;
        RECT  273.168 647.916 273.192 648 ;
    END
  END t_s[767]
  PIN t_s[768]
    DIRECTION OUTPUT ;
    USE SIGNAL ;
    PORT
      LAYER M3 ;
        RECT  273.492 647.962 273.51 648 ;
    END
  END t_s[768]
  PIN t_s[769]
    DIRECTION OUTPUT ;
    USE SIGNAL ;
    PORT
      LAYER M5 ;
        RECT  273.792 647.916 273.816 648 ;
    END
  END t_s[769]
  PIN t_s[76]
    DIRECTION OUTPUT ;
    USE SIGNAL ;
    PORT
      LAYER M3 ;
        RECT  66.132 647.962 66.15 648 ;
    END
  END t_s[76]
  PIN t_s[770]
    DIRECTION OUTPUT ;
    USE SIGNAL ;
    PORT
      LAYER M3 ;
        RECT  274.068 647.962 274.086 648 ;
    END
  END t_s[770]
  PIN t_s[771]
    DIRECTION OUTPUT ;
    USE SIGNAL ;
    PORT
      LAYER M5 ;
        RECT  274.368 647.916 274.392 648 ;
    END
  END t_s[771]
  PIN t_s[772]
    DIRECTION OUTPUT ;
    USE SIGNAL ;
    PORT
      LAYER M3 ;
        RECT  274.68 647.962 274.698 648 ;
    END
  END t_s[772]
  PIN t_s[773]
    DIRECTION OUTPUT ;
    USE SIGNAL ;
    PORT
      LAYER M5 ;
        RECT  274.992 647.916 275.016 648 ;
    END
  END t_s[773]
  PIN t_s[774]
    DIRECTION OUTPUT ;
    USE SIGNAL ;
    PORT
      LAYER M3 ;
        RECT  275.256 647.962 275.274 648 ;
    END
  END t_s[774]
  PIN t_s[775]
    DIRECTION OUTPUT ;
    USE SIGNAL ;
    PORT
      LAYER M5 ;
        RECT  275.568 647.916 275.592 648 ;
    END
  END t_s[775]
  PIN t_s[776]
    DIRECTION OUTPUT ;
    USE SIGNAL ;
    PORT
      LAYER M3 ;
        RECT  275.868 647.962 275.886 648 ;
    END
  END t_s[776]
  PIN t_s[777]
    DIRECTION OUTPUT ;
    USE SIGNAL ;
    PORT
      LAYER M5 ;
        RECT  276.192 647.916 276.216 648 ;
    END
  END t_s[777]
  PIN t_s[778]
    DIRECTION OUTPUT ;
    USE SIGNAL ;
    PORT
      LAYER M3 ;
        RECT  276.48 647.962 276.498 648 ;
    END
  END t_s[778]
  PIN t_s[779]
    DIRECTION OUTPUT ;
    USE SIGNAL ;
    PORT
      LAYER M5 ;
        RECT  276.768 647.916 276.792 648 ;
    END
  END t_s[779]
  PIN t_s[77]
    DIRECTION OUTPUT ;
    USE SIGNAL ;
    PORT
      LAYER M5 ;
        RECT  66.432 647.916 66.456 648 ;
    END
  END t_s[77]
  PIN t_s[780]
    DIRECTION OUTPUT ;
    USE SIGNAL ;
    PORT
      LAYER M3 ;
        RECT  277.056 647.962 277.074 648 ;
    END
  END t_s[780]
  PIN t_s[781]
    DIRECTION OUTPUT ;
    USE SIGNAL ;
    PORT
      LAYER M5 ;
        RECT  277.344 647.916 277.368 648 ;
    END
  END t_s[781]
  PIN t_s[782]
    DIRECTION OUTPUT ;
    USE SIGNAL ;
    PORT
      LAYER M3 ;
        RECT  277.668 647.962 277.686 648 ;
    END
  END t_s[782]
  PIN t_s[783]
    DIRECTION OUTPUT ;
    USE SIGNAL ;
    PORT
      LAYER M5 ;
        RECT  277.968 647.916 277.992 648 ;
    END
  END t_s[783]
  PIN t_s[784]
    DIRECTION OUTPUT ;
    USE SIGNAL ;
    PORT
      LAYER M3 ;
        RECT  278.28 647.962 278.298 648 ;
    END
  END t_s[784]
  PIN t_s[785]
    DIRECTION OUTPUT ;
    USE SIGNAL ;
    PORT
      LAYER M5 ;
        RECT  278.544 647.916 278.568 648 ;
    END
  END t_s[785]
  PIN t_s[786]
    DIRECTION OUTPUT ;
    USE SIGNAL ;
    PORT
      LAYER M3 ;
        RECT  278.856 647.962 278.874 648 ;
    END
  END t_s[786]
  PIN t_s[787]
    DIRECTION OUTPUT ;
    USE SIGNAL ;
    PORT
      LAYER M5 ;
        RECT  279.168 647.916 279.192 648 ;
    END
  END t_s[787]
  PIN t_s[788]
    DIRECTION OUTPUT ;
    USE SIGNAL ;
    PORT
      LAYER M3 ;
        RECT  279.468 647.962 279.486 648 ;
    END
  END t_s[788]
  PIN t_s[789]
    DIRECTION OUTPUT ;
    USE SIGNAL ;
    PORT
      LAYER M5 ;
        RECT  279.744 647.916 279.768 648 ;
    END
  END t_s[789]
  PIN t_s[78]
    DIRECTION OUTPUT ;
    USE SIGNAL ;
    PORT
      LAYER M3 ;
        RECT  66.708 647.962 66.726 648 ;
    END
  END t_s[78]
  PIN t_s[790]
    DIRECTION OUTPUT ;
    USE SIGNAL ;
    PORT
      LAYER M3 ;
        RECT  280.08 647.962 280.098 648 ;
    END
  END t_s[790]
  PIN t_s[791]
    DIRECTION OUTPUT ;
    USE SIGNAL ;
    PORT
      LAYER M5 ;
        RECT  280.368 647.916 280.392 648 ;
    END
  END t_s[791]
  PIN t_s[792]
    DIRECTION OUTPUT ;
    USE SIGNAL ;
    PORT
      LAYER M3 ;
        RECT  280.656 647.962 280.674 648 ;
    END
  END t_s[792]
  PIN t_s[793]
    DIRECTION OUTPUT ;
    USE SIGNAL ;
    PORT
      LAYER M5 ;
        RECT  280.944 647.916 280.968 648 ;
    END
  END t_s[793]
  PIN t_s[794]
    DIRECTION OUTPUT ;
    USE SIGNAL ;
    PORT
      LAYER M3 ;
        RECT  281.268 647.962 281.286 648 ;
    END
  END t_s[794]
  PIN t_s[795]
    DIRECTION OUTPUT ;
    USE SIGNAL ;
    PORT
      LAYER M5 ;
        RECT  281.568 647.916 281.592 648 ;
    END
  END t_s[795]
  PIN t_s[796]
    DIRECTION OUTPUT ;
    USE SIGNAL ;
    PORT
      LAYER M3 ;
        RECT  281.88 647.962 281.898 648 ;
    END
  END t_s[796]
  PIN t_s[797]
    DIRECTION OUTPUT ;
    USE SIGNAL ;
    PORT
      LAYER M5 ;
        RECT  282.144 647.916 282.168 648 ;
    END
  END t_s[797]
  PIN t_s[798]
    DIRECTION OUTPUT ;
    USE SIGNAL ;
    PORT
      LAYER M3 ;
        RECT  282.456 647.962 282.474 648 ;
    END
  END t_s[798]
  PIN t_s[799]
    DIRECTION OUTPUT ;
    USE SIGNAL ;
    PORT
      LAYER M5 ;
        RECT  282.768 647.916 282.792 648 ;
    END
  END t_s[799]
  PIN t_s[79]
    DIRECTION OUTPUT ;
    USE SIGNAL ;
    PORT
      LAYER M5 ;
        RECT  67.008 647.916 67.032 648 ;
    END
  END t_s[79]
  PIN t_s[7]
    DIRECTION OUTPUT ;
    USE SIGNAL ;
    PORT
      LAYER M5 ;
        RECT  45.456 647.916 45.48 648 ;
    END
  END t_s[7]
  PIN t_s[800]
    DIRECTION OUTPUT ;
    USE SIGNAL ;
    PORT
      LAYER M3 ;
        RECT  283.068 647.962 283.086 648 ;
    END
  END t_s[800]
  PIN t_s[801]
    DIRECTION OUTPUT ;
    USE SIGNAL ;
    PORT
      LAYER M5 ;
        RECT  283.344 647.916 283.368 648 ;
    END
  END t_s[801]
  PIN t_s[802]
    DIRECTION OUTPUT ;
    USE SIGNAL ;
    PORT
      LAYER M3 ;
        RECT  283.68 647.962 283.698 648 ;
    END
  END t_s[802]
  PIN t_s[803]
    DIRECTION OUTPUT ;
    USE SIGNAL ;
    PORT
      LAYER M5 ;
        RECT  283.968 647.916 283.992 648 ;
    END
  END t_s[803]
  PIN t_s[804]
    DIRECTION OUTPUT ;
    USE SIGNAL ;
    PORT
      LAYER M3 ;
        RECT  284.256 647.962 284.274 648 ;
    END
  END t_s[804]
  PIN t_s[805]
    DIRECTION OUTPUT ;
    USE SIGNAL ;
    PORT
      LAYER M5 ;
        RECT  284.544 647.916 284.568 648 ;
    END
  END t_s[805]
  PIN t_s[806]
    DIRECTION OUTPUT ;
    USE SIGNAL ;
    PORT
      LAYER M3 ;
        RECT  284.868 647.962 284.886 648 ;
    END
  END t_s[806]
  PIN t_s[807]
    DIRECTION OUTPUT ;
    USE SIGNAL ;
    PORT
      LAYER M5 ;
        RECT  285.168 647.916 285.192 648 ;
    END
  END t_s[807]
  PIN t_s[808]
    DIRECTION OUTPUT ;
    USE SIGNAL ;
    PORT
      LAYER M3 ;
        RECT  285.444 647.962 285.462 648 ;
    END
  END t_s[808]
  PIN t_s[809]
    DIRECTION OUTPUT ;
    USE SIGNAL ;
    PORT
      LAYER M5 ;
        RECT  285.744 647.916 285.768 648 ;
    END
  END t_s[809]
  PIN t_s[80]
    DIRECTION OUTPUT ;
    USE SIGNAL ;
    PORT
      LAYER M3 ;
        RECT  67.32 647.962 67.338 648 ;
    END
  END t_s[80]
  PIN t_s[810]
    DIRECTION OUTPUT ;
    USE SIGNAL ;
    PORT
      LAYER M3 ;
        RECT  286.056 647.962 286.074 648 ;
    END
  END t_s[810]
  PIN t_s[811]
    DIRECTION OUTPUT ;
    USE SIGNAL ;
    PORT
      LAYER M5 ;
        RECT  286.368 647.916 286.392 648 ;
    END
  END t_s[811]
  PIN t_s[812]
    DIRECTION OUTPUT ;
    USE SIGNAL ;
    PORT
      LAYER M3 ;
        RECT  286.668 647.962 286.686 648 ;
    END
  END t_s[812]
  PIN t_s[813]
    DIRECTION OUTPUT ;
    USE SIGNAL ;
    PORT
      LAYER M5 ;
        RECT  286.944 647.916 286.968 648 ;
    END
  END t_s[813]
  PIN t_s[814]
    DIRECTION OUTPUT ;
    USE SIGNAL ;
    PORT
      LAYER M3 ;
        RECT  287.244 647.962 287.262 648 ;
    END
  END t_s[814]
  PIN t_s[815]
    DIRECTION OUTPUT ;
    USE SIGNAL ;
    PORT
      LAYER M5 ;
        RECT  287.568 647.916 287.592 648 ;
    END
  END t_s[815]
  PIN t_s[816]
    DIRECTION OUTPUT ;
    USE SIGNAL ;
    PORT
      LAYER M3 ;
        RECT  287.856 647.962 287.874 648 ;
    END
  END t_s[816]
  PIN t_s[817]
    DIRECTION OUTPUT ;
    USE SIGNAL ;
    PORT
      LAYER M5 ;
        RECT  288.144 647.916 288.168 648 ;
    END
  END t_s[817]
  PIN t_s[818]
    DIRECTION OUTPUT ;
    USE SIGNAL ;
    PORT
      LAYER M3 ;
        RECT  288.468 647.962 288.486 648 ;
    END
  END t_s[818]
  PIN t_s[819]
    DIRECTION OUTPUT ;
    USE SIGNAL ;
    PORT
      LAYER M5 ;
        RECT  288.768 647.916 288.792 648 ;
    END
  END t_s[819]
  PIN t_s[81]
    DIRECTION OUTPUT ;
    USE SIGNAL ;
    PORT
      LAYER M5 ;
        RECT  67.632 647.916 67.656 648 ;
    END
  END t_s[81]
  PIN t_s[820]
    DIRECTION OUTPUT ;
    USE SIGNAL ;
    PORT
      LAYER M3 ;
        RECT  289.044 647.962 289.062 648 ;
    END
  END t_s[820]
  PIN t_s[821]
    DIRECTION OUTPUT ;
    USE SIGNAL ;
    PORT
      LAYER M5 ;
        RECT  289.344 647.916 289.368 648 ;
    END
  END t_s[821]
  PIN t_s[822]
    DIRECTION OUTPUT ;
    USE SIGNAL ;
    PORT
      LAYER M3 ;
        RECT  289.656 647.962 289.674 648 ;
    END
  END t_s[822]
  PIN t_s[823]
    DIRECTION OUTPUT ;
    USE SIGNAL ;
    PORT
      LAYER M5 ;
        RECT  289.968 647.916 289.992 648 ;
    END
  END t_s[823]
  PIN t_s[824]
    DIRECTION OUTPUT ;
    USE SIGNAL ;
    PORT
      LAYER M3 ;
        RECT  290.268 647.962 290.286 648 ;
    END
  END t_s[824]
  PIN t_s[825]
    DIRECTION OUTPUT ;
    USE SIGNAL ;
    PORT
      LAYER M5 ;
        RECT  290.544 647.916 290.568 648 ;
    END
  END t_s[825]
  PIN t_s[826]
    DIRECTION OUTPUT ;
    USE SIGNAL ;
    PORT
      LAYER M3 ;
        RECT  290.844 647.962 290.862 648 ;
    END
  END t_s[826]
  PIN t_s[827]
    DIRECTION OUTPUT ;
    USE SIGNAL ;
    PORT
      LAYER M5 ;
        RECT  291.168 647.916 291.192 648 ;
    END
  END t_s[827]
  PIN t_s[828]
    DIRECTION OUTPUT ;
    USE SIGNAL ;
    PORT
      LAYER M3 ;
        RECT  291.456 647.962 291.474 648 ;
    END
  END t_s[828]
  PIN t_s[829]
    DIRECTION OUTPUT ;
    USE SIGNAL ;
    PORT
      LAYER M5 ;
        RECT  291.744 647.916 291.768 648 ;
    END
  END t_s[829]
  PIN t_s[82]
    DIRECTION OUTPUT ;
    USE SIGNAL ;
    PORT
      LAYER M3 ;
        RECT  67.896 647.962 67.914 648 ;
    END
  END t_s[82]
  PIN t_s[830]
    DIRECTION OUTPUT ;
    USE SIGNAL ;
    PORT
      LAYER M3 ;
        RECT  292.068 647.962 292.086 648 ;
    END
  END t_s[830]
  PIN t_s[831]
    DIRECTION OUTPUT ;
    USE SIGNAL ;
    PORT
      LAYER M5 ;
        RECT  292.368 647.916 292.392 648 ;
    END
  END t_s[831]
  PIN t_s[832]
    DIRECTION OUTPUT ;
    USE SIGNAL ;
    PORT
      LAYER M3 ;
        RECT  292.644 647.962 292.662 648 ;
    END
  END t_s[832]
  PIN t_s[833]
    DIRECTION OUTPUT ;
    USE SIGNAL ;
    PORT
      LAYER M5 ;
        RECT  292.944 647.916 292.968 648 ;
    END
  END t_s[833]
  PIN t_s[834]
    DIRECTION OUTPUT ;
    USE SIGNAL ;
    PORT
      LAYER M3 ;
        RECT  293.256 647.962 293.274 648 ;
    END
  END t_s[834]
  PIN t_s[835]
    DIRECTION OUTPUT ;
    USE SIGNAL ;
    PORT
      LAYER M5 ;
        RECT  293.568 647.916 293.592 648 ;
    END
  END t_s[835]
  PIN t_s[836]
    DIRECTION OUTPUT ;
    USE SIGNAL ;
    PORT
      LAYER M3 ;
        RECT  293.868 647.962 293.886 648 ;
    END
  END t_s[836]
  PIN t_s[837]
    DIRECTION OUTPUT ;
    USE SIGNAL ;
    PORT
      LAYER M5 ;
        RECT  294.144 647.916 294.168 648 ;
    END
  END t_s[837]
  PIN t_s[838]
    DIRECTION OUTPUT ;
    USE SIGNAL ;
    PORT
      LAYER M3 ;
        RECT  294.444 647.962 294.462 648 ;
    END
  END t_s[838]
  PIN t_s[839]
    DIRECTION OUTPUT ;
    USE SIGNAL ;
    PORT
      LAYER M5 ;
        RECT  294.768 647.916 294.792 648 ;
    END
  END t_s[839]
  PIN t_s[83]
    DIRECTION OUTPUT ;
    USE SIGNAL ;
    PORT
      LAYER M5 ;
        RECT  68.208 647.916 68.232 648 ;
    END
  END t_s[83]
  PIN t_s[840]
    DIRECTION OUTPUT ;
    USE SIGNAL ;
    PORT
      LAYER M3 ;
        RECT  295.056 647.962 295.074 648 ;
    END
  END t_s[840]
  PIN t_s[841]
    DIRECTION OUTPUT ;
    USE SIGNAL ;
    PORT
      LAYER M5 ;
        RECT  295.344 647.916 295.368 648 ;
    END
  END t_s[841]
  PIN t_s[842]
    DIRECTION OUTPUT ;
    USE SIGNAL ;
    PORT
      LAYER M3 ;
        RECT  295.632 647.962 295.65 648 ;
    END
  END t_s[842]
  PIN t_s[843]
    DIRECTION OUTPUT ;
    USE SIGNAL ;
    PORT
      LAYER M5 ;
        RECT  295.968 647.916 295.992 648 ;
    END
  END t_s[843]
  PIN t_s[844]
    DIRECTION OUTPUT ;
    USE SIGNAL ;
    PORT
      LAYER M3 ;
        RECT  296.244 647.962 296.262 648 ;
    END
  END t_s[844]
  PIN t_s[845]
    DIRECTION OUTPUT ;
    USE SIGNAL ;
    PORT
      LAYER M5 ;
        RECT  296.544 647.916 296.568 648 ;
    END
  END t_s[845]
  PIN t_s[846]
    DIRECTION OUTPUT ;
    USE SIGNAL ;
    PORT
      LAYER M3 ;
        RECT  296.856 647.962 296.874 648 ;
    END
  END t_s[846]
  PIN t_s[847]
    DIRECTION OUTPUT ;
    USE SIGNAL ;
    PORT
      LAYER M5 ;
        RECT  297.168 647.916 297.192 648 ;
    END
  END t_s[847]
  PIN t_s[848]
    DIRECTION OUTPUT ;
    USE SIGNAL ;
    PORT
      LAYER M3 ;
        RECT  297.432 647.962 297.45 648 ;
    END
  END t_s[848]
  PIN t_s[849]
    DIRECTION OUTPUT ;
    USE SIGNAL ;
    PORT
      LAYER M5 ;
        RECT  297.744 647.916 297.768 648 ;
    END
  END t_s[849]
  PIN t_s[84]
    DIRECTION OUTPUT ;
    USE SIGNAL ;
    PORT
      LAYER M3 ;
        RECT  68.508 647.962 68.526 648 ;
    END
  END t_s[84]
  PIN t_s[850]
    DIRECTION OUTPUT ;
    USE SIGNAL ;
    PORT
      LAYER M3 ;
        RECT  298.044 647.962 298.062 648 ;
    END
  END t_s[850]
  PIN t_s[851]
    DIRECTION OUTPUT ;
    USE SIGNAL ;
    PORT
      LAYER M5 ;
        RECT  298.32 647.916 298.344 648 ;
    END
  END t_s[851]
  PIN t_s[852]
    DIRECTION OUTPUT ;
    USE SIGNAL ;
    PORT
      LAYER M3 ;
        RECT  298.656 647.962 298.674 648 ;
    END
  END t_s[852]
  PIN t_s[853]
    DIRECTION OUTPUT ;
    USE SIGNAL ;
    PORT
      LAYER M5 ;
        RECT  298.944 647.916 298.968 648 ;
    END
  END t_s[853]
  PIN t_s[854]
    DIRECTION OUTPUT ;
    USE SIGNAL ;
    PORT
      LAYER M3 ;
        RECT  299.232 647.962 299.25 648 ;
    END
  END t_s[854]
  PIN t_s[855]
    DIRECTION OUTPUT ;
    USE SIGNAL ;
    PORT
      LAYER M5 ;
        RECT  299.52 647.916 299.544 648 ;
    END
  END t_s[855]
  PIN t_s[856]
    DIRECTION OUTPUT ;
    USE SIGNAL ;
    PORT
      LAYER M3 ;
        RECT  299.844 647.962 299.862 648 ;
    END
  END t_s[856]
  PIN t_s[857]
    DIRECTION OUTPUT ;
    USE SIGNAL ;
    PORT
      LAYER M5 ;
        RECT  300.144 647.916 300.168 648 ;
    END
  END t_s[857]
  PIN t_s[858]
    DIRECTION OUTPUT ;
    USE SIGNAL ;
    PORT
      LAYER M3 ;
        RECT  300.456 647.962 300.474 648 ;
    END
  END t_s[858]
  PIN t_s[859]
    DIRECTION OUTPUT ;
    USE SIGNAL ;
    PORT
      LAYER M5 ;
        RECT  300.72 647.916 300.744 648 ;
    END
  END t_s[859]
  PIN t_s[85]
    DIRECTION OUTPUT ;
    USE SIGNAL ;
    PORT
      LAYER M5 ;
        RECT  68.832 647.916 68.856 648 ;
    END
  END t_s[85]
  PIN t_s[860]
    DIRECTION OUTPUT ;
    USE SIGNAL ;
    PORT
      LAYER M3 ;
        RECT  301.032 647.962 301.05 648 ;
    END
  END t_s[860]
  PIN t_s[861]
    DIRECTION OUTPUT ;
    USE SIGNAL ;
    PORT
      LAYER M5 ;
        RECT  301.344 647.916 301.368 648 ;
    END
  END t_s[861]
  PIN t_s[862]
    DIRECTION OUTPUT ;
    USE SIGNAL ;
    PORT
      LAYER M3 ;
        RECT  301.644 647.962 301.662 648 ;
    END
  END t_s[862]
  PIN t_s[863]
    DIRECTION OUTPUT ;
    USE SIGNAL ;
    PORT
      LAYER M5 ;
        RECT  301.92 647.916 301.944 648 ;
    END
  END t_s[863]
  PIN t_s[864]
    DIRECTION OUTPUT ;
    USE SIGNAL ;
    PORT
      LAYER M3 ;
        RECT  302.256 647.962 302.274 648 ;
    END
  END t_s[864]
  PIN t_s[86]
    DIRECTION OUTPUT ;
    USE SIGNAL ;
    PORT
      LAYER M3 ;
        RECT  69.12 647.962 69.138 648 ;
    END
  END t_s[86]
  PIN t_s[87]
    DIRECTION OUTPUT ;
    USE SIGNAL ;
    PORT
      LAYER M5 ;
        RECT  69.408 647.916 69.432 648 ;
    END
  END t_s[87]
  PIN t_s[88]
    DIRECTION OUTPUT ;
    USE SIGNAL ;
    PORT
      LAYER M3 ;
        RECT  69.696 647.962 69.714 648 ;
    END
  END t_s[88]
  PIN t_s[89]
    DIRECTION OUTPUT ;
    USE SIGNAL ;
    PORT
      LAYER M5 ;
        RECT  69.984 647.916 70.008 648 ;
    END
  END t_s[89]
  PIN t_s[8]
    DIRECTION OUTPUT ;
    USE SIGNAL ;
    PORT
      LAYER M3 ;
        RECT  45.756 647.962 45.774 648 ;
    END
  END t_s[8]
  PIN t_s[90]
    DIRECTION OUTPUT ;
    USE SIGNAL ;
    PORT
      LAYER M3 ;
        RECT  70.308 647.962 70.326 648 ;
    END
  END t_s[90]
  PIN t_s[91]
    DIRECTION OUTPUT ;
    USE SIGNAL ;
    PORT
      LAYER M5 ;
        RECT  70.608 647.916 70.632 648 ;
    END
  END t_s[91]
  PIN t_s[92]
    DIRECTION OUTPUT ;
    USE SIGNAL ;
    PORT
      LAYER M3 ;
        RECT  70.92 647.962 70.938 648 ;
    END
  END t_s[92]
  PIN t_s[93]
    DIRECTION OUTPUT ;
    USE SIGNAL ;
    PORT
      LAYER M5 ;
        RECT  71.184 647.916 71.208 648 ;
    END
  END t_s[93]
  PIN t_s[94]
    DIRECTION OUTPUT ;
    USE SIGNAL ;
    PORT
      LAYER M3 ;
        RECT  71.496 647.962 71.514 648 ;
    END
  END t_s[94]
  PIN t_s[95]
    DIRECTION OUTPUT ;
    USE SIGNAL ;
    PORT
      LAYER M5 ;
        RECT  71.808 647.916 71.832 648 ;
    END
  END t_s[95]
  PIN t_s[96]
    DIRECTION OUTPUT ;
    USE SIGNAL ;
    PORT
      LAYER M3 ;
        RECT  72.108 647.962 72.126 648 ;
    END
  END t_s[96]
  PIN t_s[97]
    DIRECTION OUTPUT ;
    USE SIGNAL ;
    PORT
      LAYER M5 ;
        RECT  72.384 647.916 72.408 648 ;
    END
  END t_s[97]
  PIN t_s[98]
    DIRECTION OUTPUT ;
    USE SIGNAL ;
    PORT
      LAYER M3 ;
        RECT  72.72 647.962 72.738 648 ;
    END
  END t_s[98]
  PIN t_s[99]
    DIRECTION OUTPUT ;
    USE SIGNAL ;
    PORT
      LAYER M5 ;
        RECT  73.008 647.916 73.032 648 ;
    END
  END t_s[99]
  PIN t_s[9]
    DIRECTION OUTPUT ;
    USE SIGNAL ;
    PORT
      LAYER M5 ;
        RECT  46.032 647.916 46.056 648 ;
    END
  END t_s[9]
  PIN VDD
    DIRECTION INOUT ;
    USE POWER ;
    PORT
      LAYER M5 ;
        RECT  341.664 200.587 341.784 395.829 ;
        RECT  137.52 200.587 137.64 395.829 ;
        RECT  641.556 4.311 641.676 643.689 ;
        RECT  637.236 4.311 637.356 643.689 ;
        RECT  632.916 4.311 633.036 643.689 ;
        RECT  628.596 4.311 628.716 643.689 ;
        RECT  624.276 4.311 624.396 643.689 ;
        RECT  619.956 4.311 620.076 643.689 ;
        RECT  615.636 4.311 615.756 643.689 ;
        RECT  611.316 4.311 611.436 643.689 ;
        RECT  606.996 4.311 607.116 643.689 ;
        RECT  602.676 4.311 602.796 643.689 ;
        RECT  598.356 4.311 598.476 643.689 ;
        RECT  594.036 4.311 594.156 643.689 ;
        RECT  589.716 4.311 589.836 643.689 ;
        RECT  585.396 4.311 585.516 643.689 ;
        RECT  581.076 4.311 581.196 643.689 ;
        RECT  576.756 4.311 576.876 643.689 ;
        RECT  572.436 4.311 572.556 643.689 ;
        RECT  568.116 4.311 568.236 643.689 ;
        RECT  563.796 4.311 563.916 643.689 ;
        RECT  559.476 4.311 559.596 643.689 ;
        RECT  555.156 4.311 555.276 643.689 ;
        RECT  550.836 4.311 550.956 643.689 ;
        RECT  546.516 4.311 546.636 643.689 ;
        RECT  542.196 4.311 542.316 643.689 ;
        RECT  537.876 4.311 537.996 643.689 ;
        RECT  533.556 4.311 533.676 643.689 ;
        RECT  529.236 4.311 529.356 643.689 ;
        RECT  524.916 4.311 525.036 643.689 ;
        RECT  520.596 4.311 520.716 643.689 ;
        RECT  516.276 4.311 516.396 643.689 ;
        RECT  511.956 4.311 512.076 643.689 ;
        RECT  507.636 4.311 507.756 643.689 ;
        RECT  503.316 4.311 503.436 643.689 ;
        RECT  498.996 4.311 499.116 643.689 ;
        RECT  494.676 4.311 494.796 643.689 ;
        RECT  490.356 4.311 490.476 643.689 ;
        RECT  486.036 4.311 486.156 643.689 ;
        RECT  481.716 4.311 481.836 643.689 ;
        RECT  477.396 4.311 477.516 643.689 ;
        RECT  473.076 4.311 473.196 643.689 ;
        RECT  468.756 4.311 468.876 643.689 ;
        RECT  464.436 4.311 464.556 643.689 ;
        RECT  460.116 4.311 460.236 643.689 ;
        RECT  455.796 4.311 455.916 643.689 ;
        RECT  451.476 4.311 451.596 643.689 ;
        RECT  447.156 4.311 447.276 643.689 ;
        RECT  442.836 4.311 442.956 643.689 ;
        RECT  438.516 4.311 438.636 643.689 ;
        RECT  434.196 4.311 434.316 643.689 ;
        RECT  429.876 4.311 429.996 643.689 ;
        RECT  425.556 4.311 425.676 643.689 ;
        RECT  421.236 4.311 421.356 643.689 ;
        RECT  416.916 4.311 417.036 643.689 ;
        RECT  412.596 4.311 412.716 643.689 ;
        RECT  408.276 4.311 408.396 643.689 ;
        RECT  403.956 4.311 404.076 643.689 ;
        RECT  399.636 4.311 399.756 643.689 ;
        RECT  395.316 4.311 395.436 643.689 ;
        RECT  390.996 4.311 391.116 643.689 ;
        RECT  386.676 4.311 386.796 643.689 ;
        RECT  382.356 4.311 382.476 643.689 ;
        RECT  378.036 4.311 378.156 643.689 ;
        RECT  373.716 574.472 373.836 643.689 ;
        RECT  373.716 479.432 373.836 516.328 ;
        RECT  373.716 177.032 373.836 421.288 ;
        RECT  373.716 81.992 373.836 118.888 ;
        RECT  373.716 4.311 373.836 23.848 ;
        RECT  369.396 574.496 369.516 643.689 ;
        RECT  369.396 479.456 369.516 516.328 ;
        RECT  369.396 177.056 369.516 421.288 ;
        RECT  369.396 82.016 369.516 118.888 ;
        RECT  369.396 4.311 369.516 23.848 ;
        RECT  365.076 574.472 365.196 643.689 ;
        RECT  365.076 479.432 365.196 516.328 ;
        RECT  365.076 177.032 365.196 421.288 ;
        RECT  365.076 81.992 365.196 118.888 ;
        RECT  365.076 4.311 365.196 23.848 ;
        RECT  360.756 574.472 360.876 643.689 ;
        RECT  360.756 479.432 360.876 516.328 ;
        RECT  360.756 177.032 360.876 421.288 ;
        RECT  360.756 81.992 360.876 118.888 ;
        RECT  360.756 4.311 360.876 23.848 ;
        RECT  356.436 574.472 356.556 643.689 ;
        RECT  356.436 479.432 356.556 516.328 ;
        RECT  356.436 177.032 356.556 421.288 ;
        RECT  356.436 81.992 356.556 118.888 ;
        RECT  356.436 4.311 356.556 23.848 ;
        RECT  352.116 574.472 352.236 643.689 ;
        RECT  352.116 479.432 352.236 516.328 ;
        RECT  352.116 177.032 352.236 421.288 ;
        RECT  352.116 81.992 352.236 118.888 ;
        RECT  352.116 4.311 352.236 23.848 ;
        RECT  347.796 574.472 347.916 643.689 ;
        RECT  347.796 479.432 347.916 516.328 ;
        RECT  347.796 177.032 347.916 421.288 ;
        RECT  347.796 81.992 347.916 118.888 ;
        RECT  347.796 4.311 347.916 23.848 ;
        RECT  343.476 574.472 343.596 643.689 ;
        RECT  343.476 479.432 343.596 516.328 ;
        RECT  343.476 177.032 343.596 421.288 ;
        RECT  343.476 81.992 343.596 118.888 ;
        RECT  343.476 4.311 343.596 23.848 ;
        RECT  339.156 574.472 339.276 643.689 ;
        RECT  339.156 479.432 339.276 516.328 ;
        RECT  339.156 177.032 339.276 421.288 ;
        RECT  339.156 81.992 339.276 118.888 ;
        RECT  339.156 4.311 339.276 23.848 ;
        RECT  334.836 574.472 334.956 643.689 ;
        RECT  334.836 479.432 334.956 516.328 ;
        RECT  334.836 399.696 334.956 421.288 ;
        RECT  334.836 177.032 334.956 196.512 ;
        RECT  334.836 81.992 334.956 118.888 ;
        RECT  334.836 4.311 334.956 23.848 ;
        RECT  330.516 574.472 330.636 643.689 ;
        RECT  330.516 479.432 330.636 516.304 ;
        RECT  330.516 399.696 330.636 421.264 ;
        RECT  330.516 177.032 330.636 196.512 ;
        RECT  330.516 81.992 330.636 118.864 ;
        RECT  330.516 4.311 330.636 23.824 ;
        RECT  326.196 574.472 326.316 643.689 ;
        RECT  326.196 479.432 326.316 516.328 ;
        RECT  326.196 399.696 326.316 421.288 ;
        RECT  326.196 177.032 326.316 196.512 ;
        RECT  326.196 81.992 326.316 118.888 ;
        RECT  326.196 4.311 326.316 23.848 ;
        RECT  321.876 574.472 321.996 643.689 ;
        RECT  321.876 479.432 321.996 516.328 ;
        RECT  321.876 399.696 321.996 421.288 ;
        RECT  321.876 177.032 321.996 196.512 ;
        RECT  321.876 81.992 321.996 118.888 ;
        RECT  321.876 4.311 321.996 23.848 ;
        RECT  317.556 574.472 317.676 643.689 ;
        RECT  317.556 479.432 317.676 516.328 ;
        RECT  317.556 399.696 317.676 421.288 ;
        RECT  317.556 177.032 317.676 196.512 ;
        RECT  317.556 81.992 317.676 118.888 ;
        RECT  317.556 4.311 317.676 23.848 ;
        RECT  313.236 574.472 313.356 643.689 ;
        RECT  313.236 479.432 313.356 516.328 ;
        RECT  313.236 399.696 313.356 421.288 ;
        RECT  313.236 177.032 313.356 196.512 ;
        RECT  313.236 81.992 313.356 118.888 ;
        RECT  313.236 4.311 313.356 23.848 ;
        RECT  308.916 574.472 309.036 643.689 ;
        RECT  308.916 479.432 309.036 516.328 ;
        RECT  308.916 399.696 309.036 421.288 ;
        RECT  308.916 177.032 309.036 196.512 ;
        RECT  308.916 81.992 309.036 118.888 ;
        RECT  308.916 4.311 309.036 23.848 ;
        RECT  304.596 399.696 304.716 643.689 ;
        RECT  304.596 4.311 304.716 196.512 ;
        RECT  300.276 399.696 300.396 643.689 ;
        RECT  300.276 4.311 300.396 196.512 ;
        RECT  295.956 399.696 296.076 643.689 ;
        RECT  295.956 4.311 296.076 196.488 ;
        RECT  291.636 399.696 291.756 643.689 ;
        RECT  291.636 4.311 291.756 196.488 ;
        RECT  287.316 399.696 287.436 643.689 ;
        RECT  287.316 4.311 287.436 196.488 ;
        RECT  282.996 399.696 283.116 643.689 ;
        RECT  282.996 4.311 283.116 196.488 ;
        RECT  278.676 574.472 278.796 643.689 ;
        RECT  278.676 479.432 278.796 516.328 ;
        RECT  278.676 399.696 278.796 421.288 ;
        RECT  278.676 177.032 278.796 196.488 ;
        RECT  278.676 81.992 278.796 118.888 ;
        RECT  278.676 4.311 278.796 23.848 ;
        RECT  274.356 574.496 274.476 643.689 ;
        RECT  274.356 479.456 274.476 516.328 ;
        RECT  274.356 399.72 274.476 421.288 ;
        RECT  274.356 177.056 274.476 196.488 ;
        RECT  274.356 82.016 274.476 118.888 ;
        RECT  274.356 4.311 274.476 23.848 ;
        RECT  270.036 574.472 270.156 643.689 ;
        RECT  270.036 479.432 270.156 516.328 ;
        RECT  270.036 399.72 270.156 421.288 ;
        RECT  270.036 177.032 270.156 196.488 ;
        RECT  270.036 81.992 270.156 118.888 ;
        RECT  270.036 4.311 270.156 23.848 ;
        RECT  265.716 574.472 265.836 643.689 ;
        RECT  265.716 479.432 265.836 516.328 ;
        RECT  265.716 399.72 265.836 421.288 ;
        RECT  265.716 177.032 265.836 196.488 ;
        RECT  265.716 81.992 265.836 118.888 ;
        RECT  265.716 4.311 265.836 23.848 ;
        RECT  261.396 574.472 261.516 643.689 ;
        RECT  261.396 479.432 261.516 516.328 ;
        RECT  261.396 399.72 261.516 421.288 ;
        RECT  261.396 177.032 261.516 196.488 ;
        RECT  261.396 81.992 261.516 118.888 ;
        RECT  261.396 4.311 261.516 23.848 ;
        RECT  257.076 574.472 257.196 643.689 ;
        RECT  257.076 479.432 257.196 516.328 ;
        RECT  257.076 399.72 257.196 421.288 ;
        RECT  257.076 177.032 257.196 196.488 ;
        RECT  257.076 81.992 257.196 118.888 ;
        RECT  257.076 4.311 257.196 23.848 ;
        RECT  252.756 574.472 252.876 643.689 ;
        RECT  252.756 479.432 252.876 516.328 ;
        RECT  252.756 399.72 252.876 421.288 ;
        RECT  252.756 177.032 252.876 196.488 ;
        RECT  252.756 81.992 252.876 118.888 ;
        RECT  252.756 4.311 252.876 23.848 ;
        RECT  248.436 574.472 248.556 643.689 ;
        RECT  248.436 479.432 248.556 516.328 ;
        RECT  248.436 399.72 248.556 421.288 ;
        RECT  248.436 177.032 248.556 196.488 ;
        RECT  248.436 81.992 248.556 118.888 ;
        RECT  248.436 4.311 248.556 23.848 ;
        RECT  244.116 574.472 244.236 643.689 ;
        RECT  244.116 479.432 244.236 516.328 ;
        RECT  244.116 399.72 244.236 421.288 ;
        RECT  244.116 177.032 244.236 196.488 ;
        RECT  244.116 81.992 244.236 118.888 ;
        RECT  244.116 4.311 244.236 23.848 ;
        RECT  239.796 574.472 239.916 643.689 ;
        RECT  239.796 479.432 239.916 516.328 ;
        RECT  239.796 399.72 239.916 421.288 ;
        RECT  239.796 177.032 239.916 196.488 ;
        RECT  239.796 81.992 239.916 118.888 ;
        RECT  239.796 4.311 239.916 23.848 ;
        RECT  235.476 574.472 235.596 643.689 ;
        RECT  235.476 479.432 235.596 516.304 ;
        RECT  235.476 399.72 235.596 421.264 ;
        RECT  235.476 177.032 235.596 196.488 ;
        RECT  235.476 81.992 235.596 118.864 ;
        RECT  235.476 4.311 235.596 23.824 ;
        RECT  231.156 574.472 231.276 643.689 ;
        RECT  231.156 479.432 231.276 516.328 ;
        RECT  231.156 399.72 231.276 421.288 ;
        RECT  231.156 177.032 231.276 196.488 ;
        RECT  231.156 81.992 231.276 118.888 ;
        RECT  231.156 4.311 231.276 23.848 ;
        RECT  226.836 574.472 226.956 643.689 ;
        RECT  226.836 479.432 226.956 516.328 ;
        RECT  226.836 399.72 226.956 421.288 ;
        RECT  226.836 177.032 226.956 196.488 ;
        RECT  226.836 81.992 226.956 118.888 ;
        RECT  226.836 4.311 226.956 23.848 ;
        RECT  222.516 574.472 222.636 643.689 ;
        RECT  222.516 479.432 222.636 516.328 ;
        RECT  222.516 399.72 222.636 421.288 ;
        RECT  222.516 177.032 222.636 196.488 ;
        RECT  222.516 81.992 222.636 118.888 ;
        RECT  222.516 4.311 222.636 23.848 ;
        RECT  218.196 574.472 218.316 643.689 ;
        RECT  218.196 479.432 218.316 516.328 ;
        RECT  218.196 399.72 218.316 421.288 ;
        RECT  218.196 177.032 218.316 196.488 ;
        RECT  218.196 81.992 218.316 118.888 ;
        RECT  218.196 4.311 218.316 23.848 ;
        RECT  213.876 574.472 213.996 643.689 ;
        RECT  213.876 479.432 213.996 516.328 ;
        RECT  213.876 399.72 213.996 421.288 ;
        RECT  213.876 177.032 213.996 196.488 ;
        RECT  213.876 81.992 213.996 118.888 ;
        RECT  213.876 4.311 213.996 23.848 ;
        RECT  209.556 399.72 209.676 643.689 ;
        RECT  209.556 4.311 209.676 196.488 ;
        RECT  205.236 399.72 205.356 643.689 ;
        RECT  205.236 4.311 205.356 196.488 ;
        RECT  200.916 399.696 201.036 643.689 ;
        RECT  200.916 4.311 201.036 196.488 ;
        RECT  196.596 399.696 196.716 643.689 ;
        RECT  196.596 4.311 196.716 196.488 ;
        RECT  192.276 399.696 192.396 643.689 ;
        RECT  192.276 4.311 192.396 196.488 ;
        RECT  187.956 399.696 188.076 643.689 ;
        RECT  187.956 4.311 188.076 196.488 ;
        RECT  183.636 399.696 183.756 643.689 ;
        RECT  183.636 4.311 183.756 196.488 ;
        RECT  179.316 399.696 179.436 643.689 ;
        RECT  179.316 4.311 179.436 196.512 ;
        RECT  174.996 574.472 175.116 643.689 ;
        RECT  174.996 479.432 175.116 516.328 ;
        RECT  174.996 399.696 175.116 421.288 ;
        RECT  174.996 177.032 175.116 196.512 ;
        RECT  174.996 81.992 175.116 118.888 ;
        RECT  174.996 4.311 175.116 23.848 ;
        RECT  170.676 574.496 170.796 643.689 ;
        RECT  170.676 479.456 170.796 516.328 ;
        RECT  170.676 399.696 170.796 421.288 ;
        RECT  170.676 177.056 170.796 196.512 ;
        RECT  170.676 82.016 170.796 118.888 ;
        RECT  170.676 4.311 170.796 23.848 ;
        RECT  166.356 574.472 166.476 643.689 ;
        RECT  166.356 479.432 166.476 516.328 ;
        RECT  166.356 399.696 166.476 421.288 ;
        RECT  166.356 177.032 166.476 196.512 ;
        RECT  166.356 81.992 166.476 118.888 ;
        RECT  166.356 4.311 166.476 23.848 ;
        RECT  162.036 574.472 162.156 643.689 ;
        RECT  162.036 479.432 162.156 516.328 ;
        RECT  162.036 399.696 162.156 421.288 ;
        RECT  162.036 177.032 162.156 196.512 ;
        RECT  162.036 81.992 162.156 118.888 ;
        RECT  162.036 4.311 162.156 23.848 ;
        RECT  157.716 574.472 157.836 643.689 ;
        RECT  157.716 479.432 157.836 516.328 ;
        RECT  157.716 399.696 157.836 421.288 ;
        RECT  157.716 177.032 157.836 196.512 ;
        RECT  157.716 81.992 157.836 118.888 ;
        RECT  157.716 4.311 157.836 23.848 ;
        RECT  153.396 574.472 153.516 643.689 ;
        RECT  153.396 479.432 153.516 516.328 ;
        RECT  153.396 399.696 153.516 421.288 ;
        RECT  153.396 177.032 153.516 196.512 ;
        RECT  153.396 81.992 153.516 118.888 ;
        RECT  153.396 4.311 153.516 23.848 ;
        RECT  149.076 574.472 149.196 643.689 ;
        RECT  149.076 479.432 149.196 516.328 ;
        RECT  149.076 399.696 149.196 421.288 ;
        RECT  149.076 177.032 149.196 196.512 ;
        RECT  149.076 81.992 149.196 118.888 ;
        RECT  149.076 4.311 149.196 23.848 ;
        RECT  144.756 574.472 144.876 643.689 ;
        RECT  144.756 479.432 144.876 516.328 ;
        RECT  144.756 399.696 144.876 421.288 ;
        RECT  144.756 177.032 144.876 196.512 ;
        RECT  144.756 81.992 144.876 118.888 ;
        RECT  144.756 4.311 144.876 23.848 ;
        RECT  140.436 574.472 140.556 643.689 ;
        RECT  140.436 479.432 140.556 516.328 ;
        RECT  140.436 177.032 140.556 421.288 ;
        RECT  140.436 81.992 140.556 118.888 ;
        RECT  140.436 4.311 140.556 23.848 ;
        RECT  136.116 574.472 136.236 643.689 ;
        RECT  136.116 479.432 136.236 516.328 ;
        RECT  136.116 177.032 136.236 421.288 ;
        RECT  136.116 81.992 136.236 118.888 ;
        RECT  136.116 4.311 136.236 23.848 ;
        RECT  131.796 574.472 131.916 643.689 ;
        RECT  131.796 479.432 131.916 516.304 ;
        RECT  131.796 177.032 131.916 421.264 ;
        RECT  131.796 81.992 131.916 118.864 ;
        RECT  131.796 4.311 131.916 23.824 ;
        RECT  127.476 574.472 127.596 643.689 ;
        RECT  127.476 479.432 127.596 516.328 ;
        RECT  127.476 177.032 127.596 421.288 ;
        RECT  127.476 81.992 127.596 118.888 ;
        RECT  127.476 4.311 127.596 23.848 ;
        RECT  123.156 574.472 123.276 643.689 ;
        RECT  123.156 479.432 123.276 516.328 ;
        RECT  123.156 177.032 123.276 421.288 ;
        RECT  123.156 81.992 123.276 118.888 ;
        RECT  123.156 4.311 123.276 23.848 ;
        RECT  118.836 574.472 118.956 643.689 ;
        RECT  118.836 479.432 118.956 516.328 ;
        RECT  118.836 177.032 118.956 421.288 ;
        RECT  118.836 81.992 118.956 118.888 ;
        RECT  118.836 4.311 118.956 23.848 ;
        RECT  114.516 574.472 114.636 643.689 ;
        RECT  114.516 479.432 114.636 516.328 ;
        RECT  114.516 177.032 114.636 421.288 ;
        RECT  114.516 81.992 114.636 118.888 ;
        RECT  114.516 4.311 114.636 23.848 ;
        RECT  110.196 574.472 110.316 643.689 ;
        RECT  110.196 479.432 110.316 516.328 ;
        RECT  110.196 177.032 110.316 421.288 ;
        RECT  110.196 81.992 110.316 118.888 ;
        RECT  110.196 4.311 110.316 23.848 ;
        RECT  105.876 4.311 105.996 643.689 ;
        RECT  101.556 4.311 101.676 643.689 ;
        RECT  97.236 4.311 97.356 643.689 ;
        RECT  92.916 4.311 93.036 643.689 ;
        RECT  88.596 4.311 88.716 643.689 ;
        RECT  84.276 4.311 84.396 643.689 ;
        RECT  79.956 574.472 80.076 643.689 ;
        RECT  79.956 479.432 80.076 516.328 ;
        RECT  79.956 177.032 80.076 421.288 ;
        RECT  79.956 81.992 80.076 118.888 ;
        RECT  79.956 4.311 80.076 23.848 ;
        RECT  75.636 574.496 75.756 643.689 ;
        RECT  75.636 479.456 75.756 516.328 ;
        RECT  75.636 177.056 75.756 421.288 ;
        RECT  75.636 82.016 75.756 118.888 ;
        RECT  75.636 4.311 75.756 23.848 ;
        RECT  71.316 574.472 71.436 643.689 ;
        RECT  71.316 479.432 71.436 516.328 ;
        RECT  71.316 177.032 71.436 421.288 ;
        RECT  71.316 81.992 71.436 118.888 ;
        RECT  71.316 4.311 71.436 23.848 ;
        RECT  66.996 574.472 67.116 643.689 ;
        RECT  66.996 479.432 67.116 516.328 ;
        RECT  66.996 177.032 67.116 421.288 ;
        RECT  66.996 81.992 67.116 118.888 ;
        RECT  66.996 4.311 67.116 23.848 ;
        RECT  62.676 574.472 62.796 643.689 ;
        RECT  62.676 479.432 62.796 516.328 ;
        RECT  62.676 177.032 62.796 421.288 ;
        RECT  62.676 81.992 62.796 118.888 ;
        RECT  62.676 4.311 62.796 23.848 ;
        RECT  58.356 574.472 58.476 643.689 ;
        RECT  58.356 479.432 58.476 516.328 ;
        RECT  58.356 177.032 58.476 421.288 ;
        RECT  58.356 81.992 58.476 118.888 ;
        RECT  58.356 4.311 58.476 23.848 ;
        RECT  54.036 574.472 54.156 643.689 ;
        RECT  54.036 479.432 54.156 516.328 ;
        RECT  54.036 177.032 54.156 421.288 ;
        RECT  54.036 81.992 54.156 118.888 ;
        RECT  54.036 4.311 54.156 23.848 ;
        RECT  49.716 574.472 49.836 643.689 ;
        RECT  49.716 479.432 49.836 516.328 ;
        RECT  49.716 177.032 49.836 421.288 ;
        RECT  49.716 81.992 49.836 118.888 ;
        RECT  49.716 4.311 49.836 23.848 ;
        RECT  45.396 574.472 45.516 643.689 ;
        RECT  45.396 479.432 45.516 516.328 ;
        RECT  45.396 177.032 45.516 421.288 ;
        RECT  45.396 81.992 45.516 118.888 ;
        RECT  45.396 4.311 45.516 23.848 ;
        RECT  41.076 574.472 41.196 643.689 ;
        RECT  41.076 479.432 41.196 516.328 ;
        RECT  41.076 177.032 41.196 421.288 ;
        RECT  41.076 81.992 41.196 118.888 ;
        RECT  41.076 4.311 41.196 23.848 ;
        RECT  36.756 574.472 36.876 643.689 ;
        RECT  36.756 479.432 36.876 516.304 ;
        RECT  36.756 177.032 36.876 421.264 ;
        RECT  36.756 81.992 36.876 118.864 ;
        RECT  36.756 4.311 36.876 23.824 ;
        RECT  32.436 574.472 32.556 643.689 ;
        RECT  32.436 479.432 32.556 516.328 ;
        RECT  32.436 177.032 32.556 421.288 ;
        RECT  32.436 81.992 32.556 118.888 ;
        RECT  32.436 4.311 32.556 23.848 ;
        RECT  28.116 574.472 28.236 643.689 ;
        RECT  28.116 479.432 28.236 516.328 ;
        RECT  28.116 177.032 28.236 421.288 ;
        RECT  28.116 81.992 28.236 118.888 ;
        RECT  28.116 4.311 28.236 23.848 ;
        RECT  23.796 574.472 23.916 643.689 ;
        RECT  23.796 479.432 23.916 516.328 ;
        RECT  23.796 177.032 23.916 421.288 ;
        RECT  23.796 81.992 23.916 118.888 ;
        RECT  23.796 4.311 23.916 23.848 ;
        RECT  19.476 574.472 19.596 643.689 ;
        RECT  19.476 479.432 19.596 516.328 ;
        RECT  19.476 177.032 19.596 421.288 ;
        RECT  19.476 81.992 19.596 118.888 ;
        RECT  19.476 4.311 19.596 23.848 ;
        RECT  15.156 574.472 15.276 643.689 ;
        RECT  15.156 479.432 15.276 516.328 ;
        RECT  15.156 177.032 15.276 421.288 ;
        RECT  15.156 81.992 15.276 118.888 ;
        RECT  15.156 4.311 15.276 23.848 ;
        RECT  10.836 4.311 10.956 643.689 ;
        RECT  6.516 4.311 6.636 643.689 ;
    END
  END VDD
  PIN VSS
    DIRECTION INOUT ;
    USE GROUND ;
    PORT
      LAYER M5 ;
        RECT  341.856 200.601 341.976 395.843 ;
        RECT  137.712 200.601 137.832 395.843 ;
        RECT  641.364 4.297 641.484 643.703 ;
        RECT  637.044 4.297 637.164 643.703 ;
        RECT  632.724 4.297 632.844 643.703 ;
        RECT  628.404 4.297 628.524 643.703 ;
        RECT  624.084 4.297 624.204 643.703 ;
        RECT  619.764 4.297 619.884 643.703 ;
        RECT  615.444 4.297 615.564 643.703 ;
        RECT  611.124 4.297 611.244 643.703 ;
        RECT  606.804 4.297 606.924 643.703 ;
        RECT  602.484 4.297 602.604 643.703 ;
        RECT  598.164 4.297 598.284 643.703 ;
        RECT  593.844 4.297 593.964 643.703 ;
        RECT  589.524 4.297 589.644 643.703 ;
        RECT  585.204 4.297 585.324 643.703 ;
        RECT  580.884 4.297 581.004 643.703 ;
        RECT  576.564 4.297 576.684 643.703 ;
        RECT  572.244 4.297 572.364 643.703 ;
        RECT  567.924 4.297 568.044 643.703 ;
        RECT  563.604 4.297 563.724 643.703 ;
        RECT  559.284 4.297 559.404 643.703 ;
        RECT  554.964 4.297 555.084 643.703 ;
        RECT  550.644 4.297 550.764 643.703 ;
        RECT  546.324 4.297 546.444 643.703 ;
        RECT  542.004 4.297 542.124 643.703 ;
        RECT  537.684 4.297 537.804 643.703 ;
        RECT  533.364 4.297 533.484 643.703 ;
        RECT  529.044 4.297 529.164 643.703 ;
        RECT  524.724 4.297 524.844 643.703 ;
        RECT  520.404 4.297 520.524 643.703 ;
        RECT  516.084 4.297 516.204 643.703 ;
        RECT  511.764 4.297 511.884 643.703 ;
        RECT  507.444 4.297 507.564 643.703 ;
        RECT  503.124 4.297 503.244 643.703 ;
        RECT  498.804 4.297 498.924 643.703 ;
        RECT  494.484 4.297 494.604 643.703 ;
        RECT  490.164 4.297 490.284 643.703 ;
        RECT  485.844 4.297 485.964 643.703 ;
        RECT  481.524 4.297 481.644 643.703 ;
        RECT  477.204 4.297 477.324 643.703 ;
        RECT  472.884 4.297 473.004 643.703 ;
        RECT  468.564 4.297 468.684 643.703 ;
        RECT  464.244 4.297 464.364 643.703 ;
        RECT  459.924 4.297 460.044 643.703 ;
        RECT  455.604 4.297 455.724 643.703 ;
        RECT  451.284 4.297 451.404 643.703 ;
        RECT  446.964 4.297 447.084 643.703 ;
        RECT  442.644 4.297 442.764 643.703 ;
        RECT  438.324 4.297 438.444 643.703 ;
        RECT  434.004 4.297 434.124 643.703 ;
        RECT  429.684 4.297 429.804 643.703 ;
        RECT  425.364 4.297 425.484 643.703 ;
        RECT  421.044 4.297 421.164 643.703 ;
        RECT  416.724 4.297 416.844 643.703 ;
        RECT  412.404 4.297 412.524 643.703 ;
        RECT  408.084 4.297 408.204 643.703 ;
        RECT  403.764 4.297 403.884 643.703 ;
        RECT  399.444 4.297 399.564 643.703 ;
        RECT  395.124 4.297 395.244 643.703 ;
        RECT  390.804 4.297 390.924 643.703 ;
        RECT  386.484 4.297 386.604 643.703 ;
        RECT  382.164 4.297 382.284 643.703 ;
        RECT  377.844 574.472 377.964 643.703 ;
        RECT  377.844 479.432 377.964 516.328 ;
        RECT  377.844 177.032 377.964 421.288 ;
        RECT  377.844 81.992 377.964 118.888 ;
        RECT  377.844 4.297 377.964 23.848 ;
        RECT  373.524 574.472 373.644 643.703 ;
        RECT  373.524 479.432 373.644 516.328 ;
        RECT  373.524 177.032 373.644 421.288 ;
        RECT  373.524 81.992 373.644 118.888 ;
        RECT  373.524 4.297 373.644 23.848 ;
        RECT  369.204 574.496 369.324 643.703 ;
        RECT  369.204 479.456 369.324 516.328 ;
        RECT  369.204 177.056 369.324 421.288 ;
        RECT  369.204 82.016 369.324 118.888 ;
        RECT  369.204 4.297 369.324 23.848 ;
        RECT  364.884 574.472 365.004 643.703 ;
        RECT  364.884 479.432 365.004 516.328 ;
        RECT  364.884 177.032 365.004 421.288 ;
        RECT  364.884 81.992 365.004 118.888 ;
        RECT  364.884 4.297 365.004 23.848 ;
        RECT  360.564 574.472 360.684 643.703 ;
        RECT  360.564 479.432 360.684 516.328 ;
        RECT  360.564 177.032 360.684 421.288 ;
        RECT  360.564 81.992 360.684 118.888 ;
        RECT  360.564 4.297 360.684 23.848 ;
        RECT  356.244 574.472 356.364 643.703 ;
        RECT  356.244 479.432 356.364 516.328 ;
        RECT  356.244 177.032 356.364 421.288 ;
        RECT  356.244 81.992 356.364 118.888 ;
        RECT  356.244 4.297 356.364 23.848 ;
        RECT  351.924 574.472 352.044 643.703 ;
        RECT  351.924 479.432 352.044 516.328 ;
        RECT  351.924 177.032 352.044 421.288 ;
        RECT  351.924 81.992 352.044 118.888 ;
        RECT  351.924 4.297 352.044 23.848 ;
        RECT  347.604 574.472 347.724 643.703 ;
        RECT  347.604 479.432 347.724 516.328 ;
        RECT  347.604 177.032 347.724 421.288 ;
        RECT  347.604 81.992 347.724 118.888 ;
        RECT  347.604 4.297 347.724 23.848 ;
        RECT  343.284 574.472 343.404 643.703 ;
        RECT  343.284 479.432 343.404 516.328 ;
        RECT  343.284 177.032 343.404 421.288 ;
        RECT  343.284 81.992 343.404 118.888 ;
        RECT  343.284 4.297 343.404 23.848 ;
        RECT  338.964 574.472 339.084 643.703 ;
        RECT  338.964 479.432 339.084 516.328 ;
        RECT  338.964 177.032 339.084 421.288 ;
        RECT  338.964 81.992 339.084 118.888 ;
        RECT  338.964 4.297 339.084 23.848 ;
        RECT  334.644 574.472 334.764 643.703 ;
        RECT  334.644 479.432 334.764 516.328 ;
        RECT  334.644 399.696 334.764 421.288 ;
        RECT  334.644 177.032 334.764 196.512 ;
        RECT  334.644 81.992 334.764 118.888 ;
        RECT  334.644 4.297 334.764 23.848 ;
        RECT  330.324 574.472 330.444 643.703 ;
        RECT  330.324 479.432 330.444 516.304 ;
        RECT  330.324 399.696 330.444 421.264 ;
        RECT  330.324 177.032 330.444 196.512 ;
        RECT  330.324 81.992 330.444 118.864 ;
        RECT  330.324 4.297 330.444 23.824 ;
        RECT  326.004 574.472 326.124 643.703 ;
        RECT  326.004 479.432 326.124 516.328 ;
        RECT  326.004 399.696 326.124 421.288 ;
        RECT  326.004 177.032 326.124 196.512 ;
        RECT  326.004 81.992 326.124 118.888 ;
        RECT  326.004 4.297 326.124 23.848 ;
        RECT  321.684 574.472 321.804 643.703 ;
        RECT  321.684 479.432 321.804 516.328 ;
        RECT  321.684 399.696 321.804 421.288 ;
        RECT  321.684 177.032 321.804 196.512 ;
        RECT  321.684 81.992 321.804 118.888 ;
        RECT  321.684 4.297 321.804 23.848 ;
        RECT  317.364 574.472 317.484 643.703 ;
        RECT  317.364 479.432 317.484 516.328 ;
        RECT  317.364 399.696 317.484 421.288 ;
        RECT  317.364 177.032 317.484 196.512 ;
        RECT  317.364 81.992 317.484 118.888 ;
        RECT  317.364 4.297 317.484 23.848 ;
        RECT  313.044 574.472 313.164 643.703 ;
        RECT  313.044 479.432 313.164 516.328 ;
        RECT  313.044 399.696 313.164 421.288 ;
        RECT  313.044 177.032 313.164 196.512 ;
        RECT  313.044 81.992 313.164 118.888 ;
        RECT  313.044 4.297 313.164 23.848 ;
        RECT  308.724 399.696 308.844 643.703 ;
        RECT  308.724 4.297 308.844 196.512 ;
        RECT  304.404 399.696 304.524 643.703 ;
        RECT  304.404 4.297 304.524 196.512 ;
        RECT  300.084 399.696 300.204 643.703 ;
        RECT  300.084 4.297 300.204 196.512 ;
        RECT  295.764 399.696 295.884 643.703 ;
        RECT  295.764 4.297 295.884 196.488 ;
        RECT  291.444 399.696 291.564 643.703 ;
        RECT  291.444 4.297 291.564 196.488 ;
        RECT  287.124 399.696 287.244 643.703 ;
        RECT  287.124 4.297 287.244 196.488 ;
        RECT  282.804 479.432 282.924 643.703 ;
        RECT  282.804 399.696 282.924 421.288 ;
        RECT  282.804 177.032 282.924 196.488 ;
        RECT  282.804 81.992 282.924 118.888 ;
        RECT  282.804 4.297 282.924 23.848 ;
        RECT  278.484 574.472 278.604 643.703 ;
        RECT  278.484 479.432 278.604 516.328 ;
        RECT  278.484 399.696 278.604 421.288 ;
        RECT  278.484 177.032 278.604 196.488 ;
        RECT  278.484 81.992 278.604 118.888 ;
        RECT  278.484 4.297 278.604 23.848 ;
        RECT  274.164 574.496 274.284 643.703 ;
        RECT  274.164 479.456 274.284 516.328 ;
        RECT  274.164 399.72 274.284 421.288 ;
        RECT  274.164 177.056 274.284 196.488 ;
        RECT  274.164 82.016 274.284 118.888 ;
        RECT  274.164 4.297 274.284 23.848 ;
        RECT  269.844 574.472 269.964 643.703 ;
        RECT  269.844 479.432 269.964 516.328 ;
        RECT  269.844 399.72 269.964 421.288 ;
        RECT  269.844 177.032 269.964 196.488 ;
        RECT  269.844 81.992 269.964 118.888 ;
        RECT  269.844 4.297 269.964 23.848 ;
        RECT  265.524 574.472 265.644 643.703 ;
        RECT  265.524 479.432 265.644 516.328 ;
        RECT  265.524 399.72 265.644 421.288 ;
        RECT  265.524 177.032 265.644 196.488 ;
        RECT  265.524 81.992 265.644 118.888 ;
        RECT  265.524 4.297 265.644 23.848 ;
        RECT  261.204 574.472 261.324 643.703 ;
        RECT  261.204 479.432 261.324 516.328 ;
        RECT  261.204 399.72 261.324 421.288 ;
        RECT  261.204 177.032 261.324 196.488 ;
        RECT  261.204 81.992 261.324 118.888 ;
        RECT  261.204 4.297 261.324 23.848 ;
        RECT  256.884 574.472 257.004 643.703 ;
        RECT  256.884 479.432 257.004 516.328 ;
        RECT  256.884 399.72 257.004 421.288 ;
        RECT  256.884 177.032 257.004 196.488 ;
        RECT  256.884 81.992 257.004 118.888 ;
        RECT  256.884 4.297 257.004 23.848 ;
        RECT  252.564 574.472 252.684 643.703 ;
        RECT  252.564 479.432 252.684 516.328 ;
        RECT  252.564 399.72 252.684 421.288 ;
        RECT  252.564 177.032 252.684 196.488 ;
        RECT  252.564 81.992 252.684 118.888 ;
        RECT  252.564 4.297 252.684 23.848 ;
        RECT  248.244 574.472 248.364 643.703 ;
        RECT  248.244 479.432 248.364 516.328 ;
        RECT  248.244 399.72 248.364 421.288 ;
        RECT  248.244 177.032 248.364 196.488 ;
        RECT  248.244 81.992 248.364 118.888 ;
        RECT  248.244 4.297 248.364 23.848 ;
        RECT  243.924 574.472 244.044 643.703 ;
        RECT  243.924 479.432 244.044 516.328 ;
        RECT  243.924 399.72 244.044 421.288 ;
        RECT  243.924 177.032 244.044 196.488 ;
        RECT  243.924 81.992 244.044 118.888 ;
        RECT  243.924 4.297 244.044 23.848 ;
        RECT  239.604 574.472 239.724 643.703 ;
        RECT  239.604 479.432 239.724 516.328 ;
        RECT  239.604 399.72 239.724 421.288 ;
        RECT  239.604 177.032 239.724 196.488 ;
        RECT  239.604 81.992 239.724 118.888 ;
        RECT  239.604 4.297 239.724 23.848 ;
        RECT  235.284 574.472 235.404 643.703 ;
        RECT  235.284 479.432 235.404 516.304 ;
        RECT  235.284 399.72 235.404 421.264 ;
        RECT  235.284 177.032 235.404 196.488 ;
        RECT  235.284 81.992 235.404 118.864 ;
        RECT  235.284 4.297 235.404 23.824 ;
        RECT  230.964 574.472 231.084 643.703 ;
        RECT  230.964 479.432 231.084 516.328 ;
        RECT  230.964 399.72 231.084 421.288 ;
        RECT  230.964 177.032 231.084 196.488 ;
        RECT  230.964 81.992 231.084 118.888 ;
        RECT  230.964 4.297 231.084 23.848 ;
        RECT  226.644 574.472 226.764 643.703 ;
        RECT  226.644 479.432 226.764 516.328 ;
        RECT  226.644 399.72 226.764 421.288 ;
        RECT  226.644 177.032 226.764 196.488 ;
        RECT  226.644 81.992 226.764 118.888 ;
        RECT  226.644 4.297 226.764 23.848 ;
        RECT  222.324 574.472 222.444 643.703 ;
        RECT  222.324 479.432 222.444 516.328 ;
        RECT  222.324 399.72 222.444 421.288 ;
        RECT  222.324 177.032 222.444 196.488 ;
        RECT  222.324 81.992 222.444 118.888 ;
        RECT  222.324 4.297 222.444 23.848 ;
        RECT  218.004 574.472 218.124 643.703 ;
        RECT  218.004 479.432 218.124 516.328 ;
        RECT  218.004 399.72 218.124 421.288 ;
        RECT  218.004 177.032 218.124 196.488 ;
        RECT  218.004 81.992 218.124 118.888 ;
        RECT  218.004 4.297 218.124 23.848 ;
        RECT  213.684 574.472 213.804 643.703 ;
        RECT  213.684 399.72 213.804 516.328 ;
        RECT  213.684 4.297 213.804 196.488 ;
        RECT  209.364 399.72 209.484 643.703 ;
        RECT  209.364 4.297 209.484 196.488 ;
        RECT  205.044 399.72 205.164 643.703 ;
        RECT  205.044 4.297 205.164 196.488 ;
        RECT  200.724 399.696 200.844 643.703 ;
        RECT  200.724 4.297 200.844 196.488 ;
        RECT  196.404 399.696 196.524 643.703 ;
        RECT  196.404 4.297 196.524 196.488 ;
        RECT  192.084 399.696 192.204 643.703 ;
        RECT  192.084 4.297 192.204 196.488 ;
        RECT  187.764 399.696 187.884 643.703 ;
        RECT  187.764 4.297 187.884 196.488 ;
        RECT  183.444 399.696 183.564 643.703 ;
        RECT  183.444 4.297 183.564 196.488 ;
        RECT  179.124 574.472 179.244 643.703 ;
        RECT  179.124 479.432 179.244 516.328 ;
        RECT  179.124 399.696 179.244 421.288 ;
        RECT  179.124 177.032 179.244 196.512 ;
        RECT  179.124 81.992 179.244 118.888 ;
        RECT  179.124 4.297 179.244 23.848 ;
        RECT  174.804 574.472 174.924 643.703 ;
        RECT  174.804 479.432 174.924 516.328 ;
        RECT  174.804 399.696 174.924 421.288 ;
        RECT  174.804 177.032 174.924 196.512 ;
        RECT  174.804 81.992 174.924 118.888 ;
        RECT  174.804 4.297 174.924 23.848 ;
        RECT  170.484 574.496 170.604 643.703 ;
        RECT  170.484 479.456 170.604 516.328 ;
        RECT  170.484 399.696 170.604 421.288 ;
        RECT  170.484 177.056 170.604 196.512 ;
        RECT  170.484 82.016 170.604 118.888 ;
        RECT  170.484 4.297 170.604 23.848 ;
        RECT  166.164 574.472 166.284 643.703 ;
        RECT  166.164 479.432 166.284 516.328 ;
        RECT  166.164 399.696 166.284 421.288 ;
        RECT  166.164 177.032 166.284 196.512 ;
        RECT  166.164 81.992 166.284 118.888 ;
        RECT  166.164 4.297 166.284 23.848 ;
        RECT  161.844 574.472 161.964 643.703 ;
        RECT  161.844 479.432 161.964 516.328 ;
        RECT  161.844 399.696 161.964 421.288 ;
        RECT  161.844 177.032 161.964 196.512 ;
        RECT  161.844 81.992 161.964 118.888 ;
        RECT  161.844 4.297 161.964 23.848 ;
        RECT  157.524 574.472 157.644 643.703 ;
        RECT  157.524 479.432 157.644 516.328 ;
        RECT  157.524 399.696 157.644 421.288 ;
        RECT  157.524 177.032 157.644 196.512 ;
        RECT  157.524 81.992 157.644 118.888 ;
        RECT  157.524 4.297 157.644 23.848 ;
        RECT  153.204 574.472 153.324 643.703 ;
        RECT  153.204 479.432 153.324 516.328 ;
        RECT  153.204 399.696 153.324 421.288 ;
        RECT  153.204 177.032 153.324 196.512 ;
        RECT  153.204 81.992 153.324 118.888 ;
        RECT  153.204 4.297 153.324 23.848 ;
        RECT  148.884 574.472 149.004 643.703 ;
        RECT  148.884 479.432 149.004 516.328 ;
        RECT  148.884 399.696 149.004 421.288 ;
        RECT  148.884 177.032 149.004 196.512 ;
        RECT  148.884 81.992 149.004 118.888 ;
        RECT  148.884 4.297 149.004 23.848 ;
        RECT  144.564 574.472 144.684 643.703 ;
        RECT  144.564 479.432 144.684 516.328 ;
        RECT  144.564 399.696 144.684 421.288 ;
        RECT  144.564 177.032 144.684 196.512 ;
        RECT  144.564 81.992 144.684 118.888 ;
        RECT  144.564 4.297 144.684 23.848 ;
        RECT  140.244 574.472 140.364 643.703 ;
        RECT  140.244 479.432 140.364 516.328 ;
        RECT  140.244 177.032 140.364 421.288 ;
        RECT  140.244 81.992 140.364 118.888 ;
        RECT  140.244 4.297 140.364 23.848 ;
        RECT  135.924 574.472 136.044 643.703 ;
        RECT  135.924 479.432 136.044 516.328 ;
        RECT  135.924 177.032 136.044 421.288 ;
        RECT  135.924 81.992 136.044 118.888 ;
        RECT  135.924 4.297 136.044 23.848 ;
        RECT  131.604 574.472 131.724 643.703 ;
        RECT  131.604 479.432 131.724 516.304 ;
        RECT  131.604 177.032 131.724 421.264 ;
        RECT  131.604 81.992 131.724 118.864 ;
        RECT  131.604 4.297 131.724 23.824 ;
        RECT  127.284 574.472 127.404 643.703 ;
        RECT  127.284 479.432 127.404 516.328 ;
        RECT  127.284 177.032 127.404 421.288 ;
        RECT  127.284 81.992 127.404 118.888 ;
        RECT  127.284 4.297 127.404 23.848 ;
        RECT  122.964 574.472 123.084 643.703 ;
        RECT  122.964 479.432 123.084 516.328 ;
        RECT  122.964 177.032 123.084 421.288 ;
        RECT  122.964 81.992 123.084 118.888 ;
        RECT  122.964 4.297 123.084 23.848 ;
        RECT  118.644 574.472 118.764 643.703 ;
        RECT  118.644 479.432 118.764 516.328 ;
        RECT  118.644 177.032 118.764 421.288 ;
        RECT  118.644 81.992 118.764 118.888 ;
        RECT  118.644 4.297 118.764 23.848 ;
        RECT  114.324 574.472 114.444 643.703 ;
        RECT  114.324 479.432 114.444 516.328 ;
        RECT  114.324 177.032 114.444 421.288 ;
        RECT  114.324 81.992 114.444 118.888 ;
        RECT  114.324 4.297 114.444 23.848 ;
        RECT  110.004 4.297 110.124 643.703 ;
        RECT  105.684 4.297 105.804 643.703 ;
        RECT  101.364 4.297 101.484 643.703 ;
        RECT  97.044 4.297 97.164 643.703 ;
        RECT  92.724 4.297 92.844 643.703 ;
        RECT  88.404 4.297 88.524 643.703 ;
        RECT  84.084 574.472 84.204 643.703 ;
        RECT  84.084 479.432 84.204 516.328 ;
        RECT  84.084 177.032 84.204 421.288 ;
        RECT  84.084 81.992 84.204 118.888 ;
        RECT  84.084 4.297 84.204 23.848 ;
        RECT  79.764 574.472 79.884 643.703 ;
        RECT  79.764 479.432 79.884 516.328 ;
        RECT  79.764 177.032 79.884 421.288 ;
        RECT  79.764 81.992 79.884 118.888 ;
        RECT  79.764 4.297 79.884 23.848 ;
        RECT  75.444 574.496 75.564 643.703 ;
        RECT  75.444 479.456 75.564 516.328 ;
        RECT  75.444 177.056 75.564 421.288 ;
        RECT  75.444 82.016 75.564 118.888 ;
        RECT  75.444 4.297 75.564 23.848 ;
        RECT  71.124 574.472 71.244 643.703 ;
        RECT  71.124 479.432 71.244 516.328 ;
        RECT  71.124 177.032 71.244 421.288 ;
        RECT  71.124 81.992 71.244 118.888 ;
        RECT  71.124 4.297 71.244 23.848 ;
        RECT  66.804 574.472 66.924 643.703 ;
        RECT  66.804 479.432 66.924 516.328 ;
        RECT  66.804 177.032 66.924 421.288 ;
        RECT  66.804 81.992 66.924 118.888 ;
        RECT  66.804 4.297 66.924 23.848 ;
        RECT  62.484 574.472 62.604 643.703 ;
        RECT  62.484 479.432 62.604 516.328 ;
        RECT  62.484 177.032 62.604 421.288 ;
        RECT  62.484 81.992 62.604 118.888 ;
        RECT  62.484 4.297 62.604 23.848 ;
        RECT  58.164 574.472 58.284 643.703 ;
        RECT  58.164 479.432 58.284 516.328 ;
        RECT  58.164 177.032 58.284 421.288 ;
        RECT  58.164 81.992 58.284 118.888 ;
        RECT  58.164 4.297 58.284 23.848 ;
        RECT  53.844 574.472 53.964 643.703 ;
        RECT  53.844 479.432 53.964 516.328 ;
        RECT  53.844 177.032 53.964 421.288 ;
        RECT  53.844 81.992 53.964 118.888 ;
        RECT  53.844 4.297 53.964 23.848 ;
        RECT  49.524 574.472 49.644 643.703 ;
        RECT  49.524 479.432 49.644 516.328 ;
        RECT  49.524 177.032 49.644 421.288 ;
        RECT  49.524 81.992 49.644 118.888 ;
        RECT  49.524 4.297 49.644 23.848 ;
        RECT  45.204 574.472 45.324 643.703 ;
        RECT  45.204 479.432 45.324 516.328 ;
        RECT  45.204 177.032 45.324 421.288 ;
        RECT  45.204 81.992 45.324 118.888 ;
        RECT  45.204 4.297 45.324 23.848 ;
        RECT  40.884 574.472 41.004 643.703 ;
        RECT  40.884 479.432 41.004 516.328 ;
        RECT  40.884 177.032 41.004 421.288 ;
        RECT  40.884 81.992 41.004 118.888 ;
        RECT  40.884 4.297 41.004 23.848 ;
        RECT  36.564 574.472 36.684 643.703 ;
        RECT  36.564 479.432 36.684 516.304 ;
        RECT  36.564 177.032 36.684 421.264 ;
        RECT  36.564 81.992 36.684 118.864 ;
        RECT  36.564 4.297 36.684 23.824 ;
        RECT  32.244 574.472 32.364 643.703 ;
        RECT  32.244 479.432 32.364 516.328 ;
        RECT  32.244 177.032 32.364 421.288 ;
        RECT  32.244 81.992 32.364 118.888 ;
        RECT  32.244 4.297 32.364 23.848 ;
        RECT  27.924 574.472 28.044 643.703 ;
        RECT  27.924 479.432 28.044 516.328 ;
        RECT  27.924 177.032 28.044 421.288 ;
        RECT  27.924 81.992 28.044 118.888 ;
        RECT  27.924 4.297 28.044 23.848 ;
        RECT  23.604 574.472 23.724 643.703 ;
        RECT  23.604 479.432 23.724 516.328 ;
        RECT  23.604 177.032 23.724 421.288 ;
        RECT  23.604 81.992 23.724 118.888 ;
        RECT  23.604 4.297 23.724 23.848 ;
        RECT  19.284 574.472 19.404 643.703 ;
        RECT  19.284 479.432 19.404 516.328 ;
        RECT  19.284 177.032 19.404 421.288 ;
        RECT  19.284 81.992 19.404 118.888 ;
        RECT  19.284 4.297 19.404 23.848 ;
        RECT  14.964 4.297 15.084 643.703 ;
        RECT  10.644 4.297 10.764 643.703 ;
        RECT  6.324 4.297 6.444 643.703 ;
    END
  END VSS
  OBS
    LAYER RVTN ;
     RECT  0 3.067 643.68 648 ;
    LAYER RVTP ;
     RECT  0 3.067 643.68 648 ;
    LAYER M1 ;
     RECT  0 3.067 643.68 648 ;
    LAYER M2 ;
     RECT  0 3.067 643.68 648 ;
    LAYER M3 ;
     RECT  0 3.067 643.68 648 ;
    LAYER M4 ;
     RECT  0 3.067 643.68 648 ;
    LAYER M5 ;
     RECT  0 3.067 643.68 648 ;
    LAYER M6 ;
     RECT  0 3.067 643.68 648 ;
    LAYER M7 ;
     RECT  0 3.067 643.68 648 ;
  END
END dsdv_bksel_q
END LIBRARY
